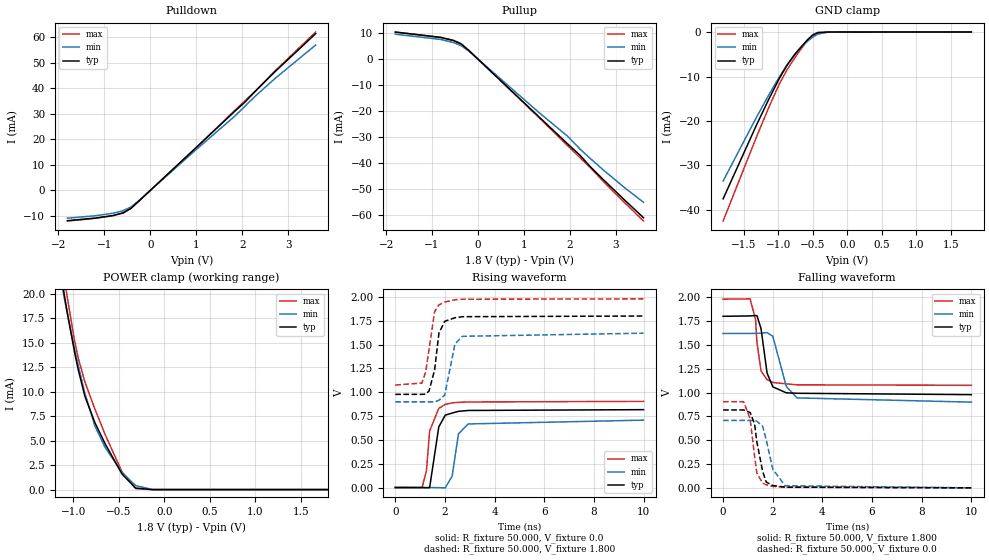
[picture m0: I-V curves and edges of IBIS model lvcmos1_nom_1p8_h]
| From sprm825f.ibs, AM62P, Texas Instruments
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|*********************** Begin LVCMOS ***********************************
|   nom_1p8_H
[Model]   lvcmos1_nom_1p8_h
Model_type I/O
Polarity   Non-Inverting
Enable   Active-High
Vinl = 0
Vinh = 0.8
Vmeas = 0.9
Vref = 1.8
Cref = 2pF
Rref = 100000
|   typ   min   max
C_comp   4.812pF   4.643pF   4.867pF
[Voltage Range]   1.8   1.62   1.98
[Temperature Range]   27   150   -40
[Pullup Reference]   1.8   1.62   1.98
[Pulldown Reference]   0   0   0
[Power Clamp Reference]   1.8   1.62   1.98
[GND Clamp Reference]   0   0   0
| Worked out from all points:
|   slope of the pulldown table from 0 to 0.27 V, typ, clamps not added: 59.6 ohm
|   slope of the pullup table from 0 to 0.27 V, typ, clamps not added: 60.3 ohm
|   GND clamp passes 1 mA (typ) near -0.52 V on its own axis
|   POWER clamp passes 1 mA (typ) near -0.42 V on its own axis
|   rising waveform, R_fixture 50.000, V_fixture 0.0: 20-80 % time 250ps typ, 243ps min, 219ps max; typ from 0 V to 0.817 V
|   rising waveform, R_fixture 50.000, V_fixture 1.800: 20-80 % time 281ps typ, 299ps min, 295ps max; typ from 0.978 V to 1.8 V
|   falling waveform, R_fixture 50.000, V_fixture 1.800: 20-80 % time 284ps typ, 315ps min, 224ps max; typ from 1.8 V to 0.978 V
|   falling waveform, R_fixture 50.000, V_fixture 0.0: 20-80 % time 324ps typ, 399ps min, 252ps max; typ from 0.817 V to 0 V
[Pulldown]
|Voltage   I(typ)   I(min)   I(max)
-1.8V     -11.83mA   -10.84mA   -11.95mA
-1.194V   -10.81mA   -9.89mA    -10.89mA
-808mV    -9.796mA   -8.891mA   -9.883mA
-588mV    -8.727mA   -7.88mA    -8.834mA
-422mV    -7.017mA   -6.479mA   -7.051mA
-257mV    -4.32mA    -4.115mA   -4.313mA
955mV     16.06mA    15.31mA    16.02mA
1.837V    30.98mA    29.07mA    31.32mA
2.057V    34.53mA    32.95mA    35.07mA
2.278V    38.73mA    36.82mA    38.73mA
2.718V    46.58mA    43.91mA    46.89mA
3.6V      61.43mA    56.98mA    62.05mA
[Pullup]
|Voltage   I(typ)   I(min)   I(max)
-1.8V     10.4mA     9.589mA    10.42mA
-808mV    8.34mA     7.567mA    8.338mA
-533mV    7.149mA    6.373mA    7.209mA
-367mV    5.812mA    5.163mA    5.937mA
-202mV    3.357mA    3.122mA    3.385mA
1.341V    -22.43mA   -20.74mA   -22.71mA
1.947V    -32.54mA   -29.6mA    -33.21mA
2.222V    -37mA      -34.61mA   -37.92mA
2.443V    -41.34mA   -38.19mA   -41.68mA
2.718V    -46.16mA   -42.47mA   -46.89mA
3.214V    -54.57mA   -49.76mA   -55.58mA
3.6V      -60.94mA   -55.01mA   -62.2mA
[GND_clamp]
|Voltage   I(typ)   I(min)   I(max)
-1.8V     -37.5mA    -33.49mA   -42.48mA
-1.318V   -20.97mA   -19.21mA   -23.65mA
-1.132V   -14.92mA   -13.99mA   -16.76mA
-984mV    -10.42mA   -10.06mA   -11.66mA
-872mV    -7.442mA   -7.36mA    -8.464mA
-761mV    -5.052mA   -4.998mA   -5.817mA
-687mV    -3.663mA   -3.691mA   -4.162mA
-575mV    -1.728mA   -2.058mA   -1.807mA
-501mV    -716.8uA   -1.141mA   -632.9uA
-427mV    -157.5uA   -469uA     -83.58uA
-278mV    -1.328uA   -23.74uA   -249.6nA
1.8V      0A         0A         0A
[POWER_clamp]
|Voltage   I(typ)   I(min)   I(max)
-1.8V     63.27mA    56.65mA    71.18mA
-1.095V   19.71mA    19.39mA    21.45mA
-1.058V   17.7mA     17.64mA    19.2mA
-984mV    13.96mA    14.3mA     15.14mA
-946mV    12.28mA    12.71mA    13.47mA
-872mV    9.531mA    9.826mA    11mA
-761mV    6.815mA    6.469mA    8.199mA
-649mV    4.665mA    4.296mA    5.605mA
-464mV    1.58mA     1.756mA    1.801mA
-315mV    158.8uA    413.9uA    104.9uA
-130mV    309.6nA    7.728uA    148.5nA
1.8V      0A         0A         0A
[Ramp]
| variable   typ   min   max
dV/dt_r   0.490/0.250n   0.424/0.242n   0.543/0.219n
dV/dt_f   0.493/0.285n   0.432/0.315n   0.543/0.223n
R_load = 50.000
[Rising Waveform]
R_fixture= 50.000
V_fixture= 0.0
V_fixture_min= 0.0
V_fixture_max= 0.0
|time   V(typ)   V(min)   V(max)
0s        823.8nV    18.05uV    1.398uV
1.078ns   135.1uV    18.7uV     -608.1uV
1.255ns   -2.306mV   28.57uV    177.4mV
1.383ns   -399.7uV   47.89uV    593.6mV
1.752ns   636.5mV    -1.598mV   830.2mV
2.013ns   759.9mV    -3.258mV   873.1mV
2.29ns    781.7mV    119.9mV    888.1mV
2.544ns   799.5mV    562.8mV    893.9mV
2.934ns   808.8mV    667.3mV    898.2mV
10ns      817.3mV    707.4mV    904.2mV
[Rising Waveform]
R_fixture= 50.000
V_fixture= 1.800
V_fixture_min= 1.620
V_fixture_max= 1.980
|time   V(typ)   V(min)   V(max)
0s        977.8mV    899.3mV    1.076V
1.069ns   977.9mV    899.3mV    1.096V
1.221ns   980.6mV    899.3mV    1.208V
1.356ns   1.011V     899.3mV    1.444V
1.584ns   1.235V     899.4mV    1.846V
1.757ns   1.62V      915.7mV    1.917V
1.992ns   1.745V     971.5mV    1.947V
2.403ns   1.782V     1.507V     1.971V
2.706ns   1.793V     1.587V     1.976V
10ns      1.8V       1.62V      1.98V
[Falling Waveform]
R_fixture= 50.000
V_fixture= 1.800
V_fixture_min= 1.620
V_fixture_max= 1.980
|time   V(typ)   V(min)   V(max)
0s        1.8V       1.62V      1.98V
1.087ns   1.804V     1.62V      1.983V
1.309ns   1.808V     1.621V     1.764V
1.363ns   1.807V     1.622V     1.525V
1.528ns   1.67V      1.623V     1.225V
1.771ns   1.204V     1.629V     1.136V
2.003ns   1.06V      1.591V     1.106V
2.544ns   997.1mV    1.064V     1.091V
2.977ns   992.4mV    943.8mV    1.081V
10ns      977.8mV    899.4mV    1.076V
[Falling Waveform]
R_fixture= 50.000
V_fixture= 0.0
V_fixture_min= 0.0
V_fixture_max= 0.0
|time   V(typ)   V(min)   V(max)
0s        817.3mV    707.5mV    904.3mV
825ps     817.3mV    707.5mV    903.8mV
1.087ns   790.8mV    707.5mV    726.3mV
1.266ns   672.8mV    707.5mV    334.4mV
1.359ns   481.5mV    699.2mV    155.1mV
1.591ns   174.7mV    648.4mV    49.85mV
1.736ns   60.8mV     503mV      31.72mV
2.003ns   23.91mV    194.1mV    14.95mV
2.497ns   7.87mV     22.14mV    6.191mV
10ns      33.03uV    87.62uV    16.17uV
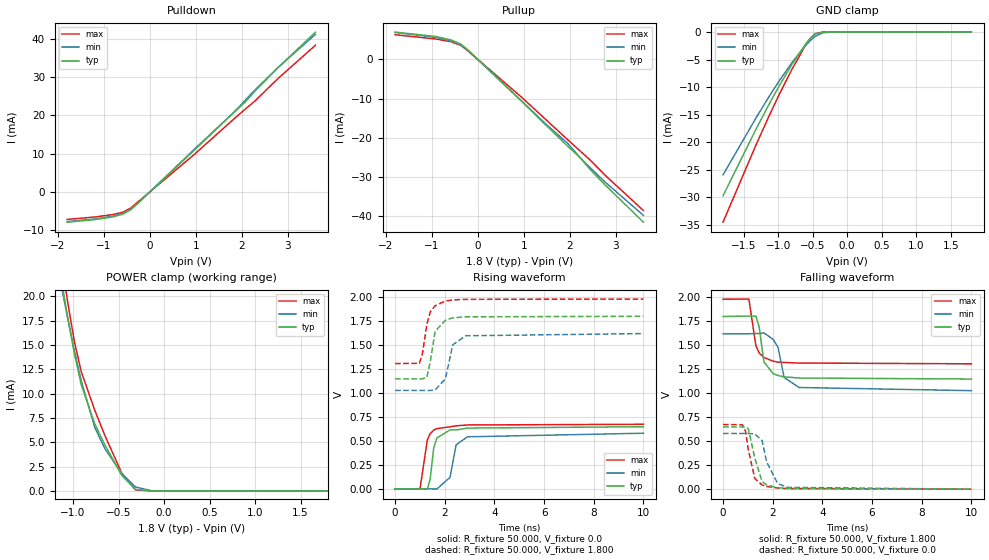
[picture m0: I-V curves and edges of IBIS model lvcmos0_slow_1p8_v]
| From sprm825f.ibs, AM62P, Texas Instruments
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|   slow_1p8_v
[Model]   lvcmos0_slow_1p8_v
Model_type I/O
Polarity   Non-Inverting
Enable   Active-High
Vinl = 0
Vinh = 0.8
Vmeas = 0.9
Vref = 1.8
Cref = 2pF
Rref = 100000
|   typ   min   max
C_comp   5.313pF   5.138pF   5.385pF
[Voltage Range]   1.8   1.62   1.98
[Temperature Range]   27   150   -40
[Pullup Reference]   1.8   1.62   1.98
[Pulldown Reference]   0   0   0
[Power Clamp Reference]   1.8   1.62   1.98
[GND Clamp Reference]   0   0   0
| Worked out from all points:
|   slope of the pulldown table from 0 to 0.27 V, typ, clamps not added: 88.7 ohm
|   slope of the pullup table from 0 to 0.27 V, typ, clamps not added: 89.7 ohm
|   GND clamp passes 1 mA (typ) near -0.52 V on its own axis
|   POWER clamp passes 1 mA (typ) near -0.42 V on its own axis
|   rising waveform, R_fixture 50.000, V_fixture 0.0: 20-80 % time 234ps typ, 265ps min, 232ps max; typ from 0 V to 0.648 V
|   rising waveform, R_fixture 50.000, V_fixture 1.800: 20-80 % time 260ps typ, 296ps min, 294ps max; typ from 1.15 V to 1.8 V
|   falling waveform, R_fixture 50.000, V_fixture 1.800: 20-80 % time 258ps typ, 334ps min, 257ps max; typ from 1.8 V to 1.15 V
|   falling waveform, R_fixture 50.000, V_fixture 0.0: 20-80 % time 343ps typ, 411ps min, 294ps max; typ from 0.648 V to 0 V
[Pulldown]
|Voltage   I(typ)   I(min)   I(max)
-1.8V     -7.963mA   -7.801mA   -7.241mA
-1.194V   -7.271mA   -7.118mA   -6.591mA
-808mV    -6.583mA   -6.398mA   -5.977mA
-588mV    -5.86mA    -5.668mA   -5.345mA
-422mV    -4.71mA    -4.654mA   -4.282mA
-257mV    -2.902mA   -2.957mA   -2.608mA
955mV     10.79mA    11.03mA    9.687mA
1.837V    20.92mA    20.94mA    19.19mA
2.057V    23.3mA     23.79mA    21.49mA
2.278V    26.26mA    26.63mA    23.71mA
2.773V    32.37mA    32.42mA    29.54mA
3.6V      41.82mA    41.24mA    38.38mA
[Pullup]
|Voltage   I(typ)   I(min)   I(max)
-1.8V     6.998mA    6.891mA    6.313mA
-918mV    5.872mA    5.673mA    5.243mA
-588mV    5.01mA     4.789mA    4.536mA
-367mV    3.923mA    3.703mA    3.583mA
-202mV    2.255mA    2.239mA    2.047mA
955mV     -10.69mA   -10.66mA   -9.684mA
1.506V    -17.07mA   -16.77mA   -15.65mA
1.947V    -22.06mA   -21.35mA   -20.42mA
2.222V    -25.07mA   -25.04mA   -23.35mA
2.443V    -28.13mA   -27.65mA   -25.69mA
2.773V    -32.1mA    -31.37mA   -29.62mA
3.6V      -41.55mA   -39.8mA    -38.57mA
[GND_clamp]
|Voltage   I(typ)   I(min)   I(max)
-1.8V     -29.72mA   -25.92mA   -34.52mA
-1.318V   -17.54mA   -15.51mA   -20.38mA
-1.132V   -13.09mA   -11.7mA    -15.22mA
-984mV    -9.729mA   -8.822mA   -11.3mA
-798mV    -5.797mA   -5.487mA   -6.696mA
-612mV    -2.352mA   -2.574mA   -2.564mA
-538mV    -1.174mA   -1.582mA   -1.166mA
-464mV    -368uA     -771.3uA   -275.5uA
-353mV    -15.75uA   -129.3uA   -4.378uA
-241mV    -383.4nA   -10.85uA   -119.1nA
1.8V      0A         0A         0A
[POWER_clamp]
|Voltage   I(typ)   I(min)   I(max)
-1.8V     63.47mA    56.87mA    71.37mA
-1.132V   21.93mA    21.29mA    24mA
-1.095V   19.85mA    19.49mA    21.65mA
-1.058V   17.84mA    17.74mA    19.39mA
-984mV    14.08mA    14.39mA    15.3mA
-909mV    10.9mA     11.31mA    12.25mA
-761mV    6.887mA    6.531mA    8.298mA
-649mV    4.716mA    4.334mA    5.678mA
-464mV    1.598mA    1.771mA    1.827mA
-315mV    160.7uA    409.8uA    112.2uA
-130mV    308nA      7.74uA     148.3nA
1.8V      0A         0A         0A
[Ramp]
| variable   typ   min   max
dV/dt_r   0.389/0.233n   0.348/0.263n   0.404/0.232n
dV/dt_f   0.391/0.258n   0.356/0.335n   0.404/0.256n
R_load = 50.000
[Rising Waveform]
R_fixture= 50.000
V_fixture= 0.0
|time   V(typ)   V(min)   V(max)
0s        961.2nV    20.53uV    1.691uV
1.003ns   104uV      18.77uV    172.7uV
1.297ns   -3.062mV   -5.319uV   510.4mV
1.411ns   101.2mV    76.52uV    574.7mV
1.555ns   427.3mV    -706.1uV   612.8mV
1.681ns   530.4mV    -1.883mV   628.3mV
2.212ns   615.3mV    120.5mV    647.4mV
2.457ns   614.4mV    459.8mV    657.9mV
2.91ns    634.3mV    543mV      666.5mV
10ns      648.3mV    580.6mV    673.9mV
[Rising Waveform]
R_fixture= 50.000
V_fixture= 1.800
V_fixture_min= 1.620
V_fixture_max= 1.980
|time   V(typ)   V(min)   V(max)
0s        1.148V     1.027V     1.307V
979ps     1.148V     1.027V     1.31V
1.103ns   1.147V     1.027V     1.414V
1.283ns   1.167V     1.027V     1.723V
1.416ns   1.327V     1.027V     1.847V
1.611ns   1.643V     1.03V      1.909V
2.026ns   1.76V      1.149V     1.96V
2.321ns   1.784V     1.503V     1.971V
2.844ns   1.795V     1.597V     1.977V
10ns      1.8V       1.62V      1.98V
[Falling Waveform]
R_fixture= 50.000
V_fixture= 1.800
V_fixture_min= 1.620
V_fixture_max= 1.980
|time   V(typ)   V(min)   V(max)
0s        1.8V       1.62V      1.98V
1.042ns   1.805V     1.62V      1.982V
1.323ns   1.803V     1.622V     1.496V
1.456ns   1.69V      1.623V     1.42V
1.648ns   1.326V     1.629V     1.373V
2.02ns    1.204V     1.561V     1.334V
2.214ns   1.185V     1.48V      1.324V
2.461ns   1.171V     1.165V     1.321V
3.059ns   1.159V     1.06V      1.315V
10ns      1.148V     1.027V     1.307V
[Falling Waveform]
R_fixture= 50.000
V_fixture= 0.0
V_fixture_min= 0.0
V_fixture_max= 0.0
|time   V(typ)   V(min)   V(max)
0s        648.3mV    580.6mV    673.9mV
775ps     648.3mV    580.6mV    671.8mV
905ps     648.5mV    580.6mV    607.9mV
1.017ns   631.4mV    580.6mV    412.8mV
1.281ns   323.2mV    575mV      111.3mV
1.571ns   79.82mV    507.1mV    44.39mV
1.759ns   42.72mV    283.3mV    28.53mV
2.204ns   15.58mV    57.04mV    11.36mV
2.608ns   7.835mV    18.53mV    6.216mV
10ns      47.85uV    118uV      30.83uV
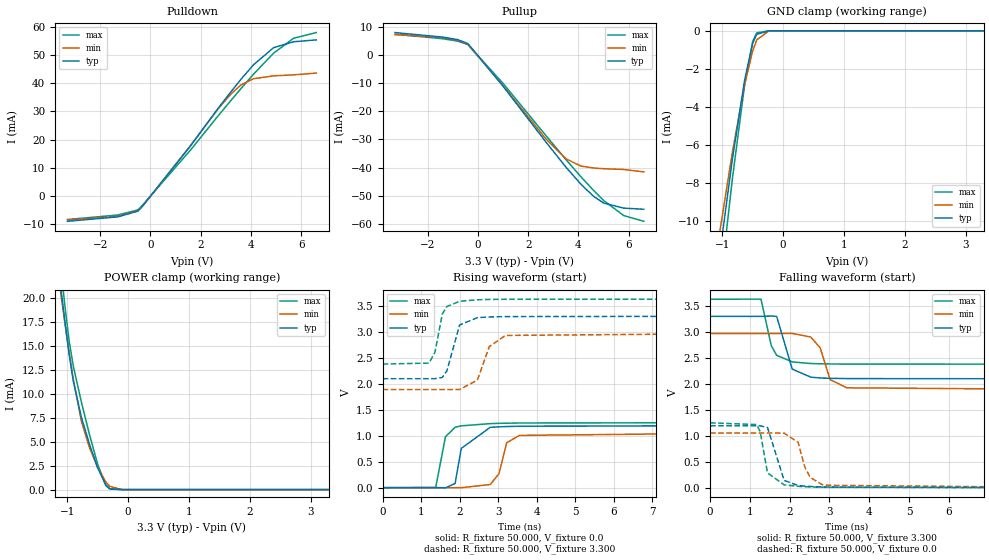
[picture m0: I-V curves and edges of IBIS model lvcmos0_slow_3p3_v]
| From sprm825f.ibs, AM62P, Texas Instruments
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|   slow_3p3_v
[Model]   lvcmos0_slow_3p3_v
Model_type I/O
Polarity   Non-Inverting
Enable   Active-High
Vinl = 0
Vinh = 0.8
Vmeas = 1.65
Vref = 3.3
Cref = 2pF
Rref = 100000
|   typ   min   max
C_comp   3.777pF   3.679pF   3.786pF
[Voltage Range]   3.3   2.97   3.63
[Temperature Range]   27   150   -40
[Pullup Reference]   3.3   2.97   3.63
[Pulldown Reference]   0   0   0
[Power Clamp Reference]   3.3   2.97   3.63
[GND Clamp Reference]   0   0   0
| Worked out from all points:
|   slope of the pulldown table from 0 to 0.495 V, typ, clamps not added: 89.6 ohm
|   slope of the pullup table from 0 to 0.495 V, typ, clamps not added: 90.9 ohm
|   GND clamp passes 1 mA (typ) near -0.53 V on its own axis
|   POWER clamp passes 1 mA (typ) near -0.41 V on its own axis
|   rising waveform, R_fixture 50.000, V_fixture 0.0: 20-80 % time 176ps typ, 256ps min, 171ps max; typ from 0 V to 1.19 V
|   rising waveform, R_fixture 50.000, V_fixture 3.300: 20-80 % time 250ps typ, 314ps min, 202ps max; typ from 2.1 V to 3.3 V
|   falling waveform, R_fixture 50.000, V_fixture 3.300: 20-80 % time 199ps typ, 289ps min, 196ps max; typ from 3.3 V to 2.1 V
|   falling waveform, R_fixture 50.000, V_fixture 0.0: 20-80 % time 240ps typ, 278ps min, 182ps max; typ from 1.19 V to 0 V
[Pulldown]
|Voltage   I(typ)   I(min)   I(max)
-3.3V     -8.88mA    -8.385mA   -8.25mA
-1.3V     -7.308mA   -7.119mA   -6.652mA
-500mV    -5.306mA   -5.103mA   -4.87mA
-300mV    -3.354mA   -3.386mA   -3.022mA
1.6V      17.84mA    18.03mA    16.39mA
2.7V      31.18mA    31mA       28.5mA
3.2V      36.91mA    36.13mA    33.86mA
3.6V      41.35mA    39.38mA    38.06mA
4.1V      46.49mA    41.56mA    43.15mA
4.9V      52.56mA    42.59mA    50.61mA
5.7V      54.65mA    42.94mA    55.9mA
6.6V      55.31mA    43.57mA    57.9mA
[Pullup]
|Voltage   I(typ)   I(min)   I(max)
-3.3V     8.025mA    7.28mA     7.462mA
-1.4V     6.408mA    6.261mA    5.826mA
-800mV    5.499mA    5.284mA    4.983mA
-400mV    4.1mA      3.839mA    3.763mA
1V        -11.05mA   -10.89mA   -10.06mA
2.7V      -30.85mA   -29.76mA   -28.57mA
3.5V      -39.82mA   -36.87mA   -37.14mA
4.1V      -45.93mA   -39.47mA   -43.29mA
4.6V      -50.21mA   -40.15mA   -48.11mA
5V        -52.61mA   -40.39mA   -51.69mA
5.8V      -54.41mA   -40.68mA   -57.07mA
6.6V      -54.82mA   -41.52mA   -59.1mA
[GND_clamp]
|Voltage   I(typ)   I(min)   I(max)
-3.3V     -91.93mA   -62.08mA   -135.9mA
-1.3V     -18.16mA   -15.85mA   -21.32mA
-1.233V   -16.57mA   -14.51mA   -19.39mA
-1.167V   -14.92mA   -13.18mA   -17.39mA
-1.1V     -13.23mA   -11.81mA   -15.39mA
-1.033V   -11.55mA   -10.42mA   -13.42mA
-833mV    -6.742mA   -6.382mA   -7.775mA
-633mV    -2.616mA   -2.841mA   -2.866mA
-500mV    -654.2uA   -1.063mA   -567uA
-433mV    -179.7uA   -474.3uA   -107.3uA
-233mV    -333.4nA   -7.881uA   -216.8nA
3.3V      0A         0A         0A
[POWER_clamp]
|Voltage   I(typ)   I(min)   I(max)
-3.3V     163.7mA    143.3mA    185.7mA
-1.1V     20.75mA    20.13mA    22.76mA
-1.033V   17.24mA    17.07mA    18.82mA
-967mV    14.03mA    14.18mA    15.4mA
-900mV    11.29mA    11.5mA     12.85mA
-767mV    7.523mA    7.108mA    9.097mA
-633mV    4.708mA    4.343mA    5.698mA
-500mV    2.263mA    2.325mA    2.644mA
-367mV    497.9uA    807.2uA    443.4uA
-300mV    94.26uA    333.7uA    53.33uA
-100mV    158.3nA    4.238uA    99.13nA
3.3V      0A         0A         0A
[Ramp]
| variable   typ   min   max
dV/dt_r   0.716/0.176n   0.633/0.257n   0.751/0.171n
dV/dt_f   0.721/0.199n   0.649/0.289n   0.750/0.196n
R_load = 50.000
[Rising Waveform]
R_fixture= 50.000
V_fixture= 0.0
V_fixture_min= 0.0
V_fixture_max= 0.0
|time   V(typ)   V(min)   V(max)
0s        2.233uV    22.67uV    3.142uV
1.378ns   -170.2uV   37.08uV    3.025mV
1.631ns   -3.81mV    -75.25uV   979.4mV
1.882ns   80.33mV    -80.37uV   1.163V
2.041ns   754.8mV    -747.2uV   1.19V
2.793ns   1.162V     60.76mV    1.233V
3.022ns   1.171V     269.9mV    1.238V
3.22ns    1.177V     864.7mV    1.241V
3.55ns    1.183V     1.006V     1.245V
10ns      1.194V     1.055V     1.252V
[Rising Waveform]
R_fixture= 50.000
V_fixture= 3.300
V_fixture_min= 2.970
V_fixture_max= 3.630
|time   V(typ)   V(min)   V(max)
0s        2.098V     1.889V     2.38V
1.205ns   2.098V     1.889V     2.398V
1.359ns   2.098V     1.889V     2.608V
1.55ns    2.122V     1.889V     3.344V
1.67ns    2.252V     1.889V     3.489V
1.998ns   3.132V     1.89V      3.588V
2.46ns    3.273V     2.071V     3.618V
2.769ns   3.287V     2.716V     3.624V
3.189ns   3.294V     2.931V     3.627V
10ns      3.3V       2.97V      3.63V
[Falling Waveform]
R_fixture= 50.000
V_fixture= 3.300
V_fixture_min= 2.970
V_fixture_max= 3.630
|time   V(typ)   V(min)   V(max)
0s        3.3V       2.97V      3.63V
1.279ns   3.3V       2.97V      3.632V
1.537ns   3.307V     2.97V      2.738V
1.673ns   3.3V       2.97V      2.551V
2.064ns   2.285V     2.972V     2.424V
2.528ns   2.131V     2.903V     2.393V
2.766ns   2.115V     2.696V     2.388V
3.014ns   2.108V     2.084V     2.384V
3.438ns   2.103V     1.925V     2.382V
10ns      2.098V     1.889V     2.38V
[Falling Waveform]
R_fixture= 50.000
V_fixture= 0.0
V_fixture_min= 0.0
V_fixture_max= 0.0
|time   V(typ)   V(min)   V(max)
0s        1.194V     1.055V     1.252V
1.168ns   1.194V     1.055V     1.218V
1.258ns   1.194V     1.055V     1.084V
1.443ns   1.162V     1.055V     287.1mV
1.861ns   142.9mV    1.053V     57.75mV
2.211ns   45.76mV    875.8mV    29.85mV
2.383ns   33.66mV    392.4mV    22.37mV
2.518ns   26.84mV    200mV      18.07mV
2.845ns   16.06mV    50.78mV    11.19mV
10ns      71.42uV    151.9uV    48.03uV
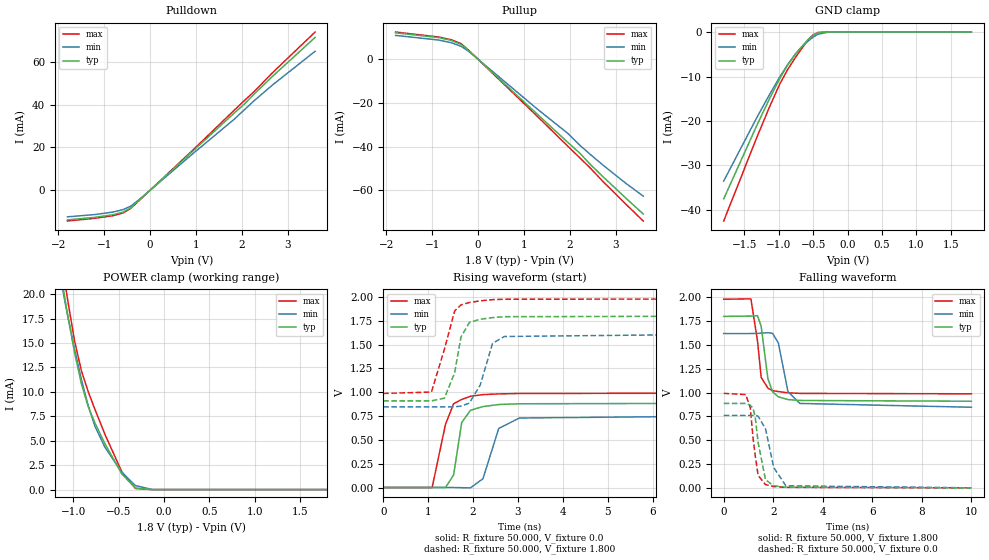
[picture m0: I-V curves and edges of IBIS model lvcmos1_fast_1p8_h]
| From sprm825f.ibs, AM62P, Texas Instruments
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|   fast_1p8_h
[Model]   lvcmos1_fast_1p8_h
Model_type I/O
Polarity   Non-Inverting
Enable   Active-High
Vinl = 0
Vinh = 0.8
Vmeas = 0.9
Vref = 1.8
Cref = 2pF
Rref = 100000
|   typ   min   max
C_comp   4.812pF   4.643pF   4.867pF
[Voltage Range]   1.8   1.62   1.98
[Temperature Range]   27   150   -40
[Pullup Reference]   1.8   1.62   1.98
[Pulldown Reference]   0   0   0
[Power Clamp Reference]   1.8   1.62   1.98
[GND Clamp Reference]   0   0   0
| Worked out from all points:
|   slope of the pulldown table from 0 to 0.27 V, typ, clamps not added: 51.1 ohm
|   slope of the pullup table from 0 to 0.27 V, typ, clamps not added: 51.6 ohm
|   GND clamp passes 1 mA (typ) near -0.52 V on its own axis
|   POWER clamp passes 1 mA (typ) near -0.42 V on its own axis
|   rising waveform, R_fixture 50.000, V_fixture 0.0: 20-80 % time 186ps typ, 284ps min, 281ps max; typ from 0 V to 0.886 V
|   rising waveform, R_fixture 50.000, V_fixture 1.800: 20-80 % time 220ps typ, 304ps min, 317ps max; typ from 0.909 V to 1.8 V
|   falling waveform, R_fixture 50.000, V_fixture 1.800: 20-80 % time 237ps typ, 357ps min, 242ps max; typ from 1.8 V to 0.909 V
|   falling waveform, R_fixture 50.000, V_fixture 0.0: 20-80 % time 320ps typ, 417ps min, 252ps max; typ from 0.886 V to 0 V
[Pulldown]
|Voltage   I(typ)   I(min)   I(max)
-1.8V     -13.81mA   -12.38mA   -14.33mA
-1.194V   -12.61mA   -11.3mA    -13.05mA
-808mV    -11.42mA   -10.15mA   -11.85mA
-588mV    -10.19mA   -9.002mA   -10.59mA
-422mV    -8.181mA   -7.402mA   -8.45mA
-257mV    -5.042mA   -4.7mA     -5.17mA
955mV     18.73mA    17.48mA    19.2mA
1.837V    36.09mA    33.19mA    37.41mA
2.057V    40.24mA    37.6mA     41.88mA
2.278V    45.07mA    41.97mA    46.25mA
2.663V    53.05mA    49.03mA    54.72mA
3.6V      71.37mA    64.91mA    73.89mA
[Pullup]
|Voltage   I(typ)   I(min)   I(max)
-1.8V     12.14mA    10.95mA    12.49mA
-863mV    9.949mA    8.822mA    10.22mA
-588mV    8.699mA    7.614mA    8.984mA
-367mV    6.789mA    5.895mA    7.103mA
-202mV    3.919mA    3.565mA    4.056mA
1.286V    -25.05mA   -22.7mA    -26mA
1.947V    -37.88mA   -33.76mA   -39.62mA
2.222V    -43.07mA   -39.42mA   -45.22mA
2.443V    -48.07mA   -43.49mA   -49.73mA
2.718V    -53.66mA   -48.37mA   -55.86mA
3.214V    -63.42mA   -56.66mA   -66.17mA
3.6V      -70.82mA   -62.64mA   -74.03mA
[GND_clamp]
|Voltage   I(typ)   I(min)   I(max)
-1.8V     -37.5mA    -33.49mA   -42.48mA
-1.318V   -20.97mA   -19.21mA   -23.65mA
-1.132V   -14.92mA   -13.99mA   -16.76mA
-984mV    -10.42mA   -10.06mA   -11.66mA
-872mV    -7.442mA   -7.36mA    -8.464mA
-761mV    -5.052mA   -4.998mA   -5.817mA
-687mV    -3.663mA   -3.691mA   -4.162mA
-575mV    -1.728mA   -2.058mA   -1.808mA
-501mV    -716.8uA   -1.141mA   -632.4uA
-427mV    -157.5uA   -468.3uA   -83.21uA
-278mV    -1.328uA   -23.76uA   -248.6nA
1.8V      0A         0A         0A
[POWER_clamp]
|Voltage   I(typ)   I(min)   I(max)
-1.8V     63.27mA    56.65mA    71.18mA
-1.095V   19.71mA    19.39mA    21.45mA
-1.058V   17.7mA     17.64mA    19.2mA
-984mV    13.96mA    14.3mA     15.15mA
-909mV    10.79mA    11.23mA    12.12mA
-835mV    8.489mA    8.575mA    10.02mA
-761mV    6.815mA    6.481mA    8.2mA
-649mV    4.665mA    4.299mA    5.607mA
-464mV    1.58mA     1.756mA    1.805mA
-315mV    158.8uA    411.2uA    110uA
-130mV    309.5nA    7.643uA    148.6nA
1.8V      0A         0A         0A
[Ramp]
| variable   typ   min   max
dV/dt_r   0.532/0.186n   0.456/0.284n   0.595/0.281n
dV/dt_f   0.535/0.237n   0.464/0.354n   0.596/0.242n
R_load = 50.000
[Rising Waveform]
R_fixture= 50.000
V_fixture= 0.0
V_fixture_min= 0.0
V_fixture_max= 0.0
|time   V(typ)   V(min)   V(max)
0s        765.5nV    16.98uV    1.281uV
1.089ns   103.2uV    17.62uV    -763.2uV
1.387ns   970.4uV    55.52uV    663.9mV
1.567ns   131.1mV    -256.9uV   879.7mV
1.747ns   681.1mV    -1.648mV   923.9mV
1.944ns   810.9mV    -3.579mV   958.3mV
2.221ns   849.6mV    92.62mV    974.9mV
2.572ns   871.1mV    620.2mV    982.5mV
3.032ns   878.9mV    729.4mV    986.8mV
10ns      886mV      760.3mV    992mV
[Rising Waveform]
R_fixture= 50.000
V_fixture= 1.800
V_fixture_min= 1.620
V_fixture_max= 1.980
|time   V(typ)   V(min)   V(max)
0s        909.1mV    846.2mV    987.3mV
1.074ns   909.2mV    846.2mV    1.002V
1.362ns   937.7mV    846.2mV    1.45V
1.59ns    1.203V     846.1mV    1.853V
1.731ns   1.579V     854.9mV    1.916V
1.918ns   1.732V     886.1mV    1.942V
2.159ns   1.766V     1.075V     1.959V
2.434ns   1.783V     1.513V     1.972V
2.696ns   1.793V     1.585V     1.976V
10ns      1.8V       1.62V      1.98V
[Falling Waveform]
R_fixture= 50.000
V_fixture= 1.800
V_fixture_min= 1.620
V_fixture_max= 1.980
|time   V(typ)   V(min)   V(max)
0s        1.8V       1.62V      1.98V
1.098ns   1.803V     1.62V      1.984V
1.364ns   1.808V     1.622V     1.543V
1.513ns   1.695V     1.624V     1.159V
1.783ns   1.147V     1.629V     1.047V
1.973ns   1.008V     1.622V     1.02V
2.208ns   955.3mV    1.52V      1.011V
2.593ns   926.8mV    1.011V     997.7mV
3.075ns   917.5mV    886mV      991.7mV
10ns      909.1mV    846.2mV    987.3mV
[Falling Waveform]
R_fixture= 50.000
V_fixture= 0.0
V_fixture_min= 0.0
V_fixture_max= 0.0
|time   V(typ)   V(min)   V(max)
0s        886mV      760.4mV    992mV
889ps     886mV      760.4mV    979.1mV
1.072ns   868.9mV    760.3mV    840.9mV
1.187ns   832.9mV    760.4mV    515.8mV
1.274ns   740mV      760.4mV    336.1mV
1.391ns   473.3mV    751.3mV    129.4mV
1.688ns   85.05mV    619.9mV    34.17mV
2.018ns   21.97mV    213.8mV    13.37mV
2.511ns   7.159mV    21.51mV    5.501mV
10ns      30.93uV    83.26uV    14.49uV
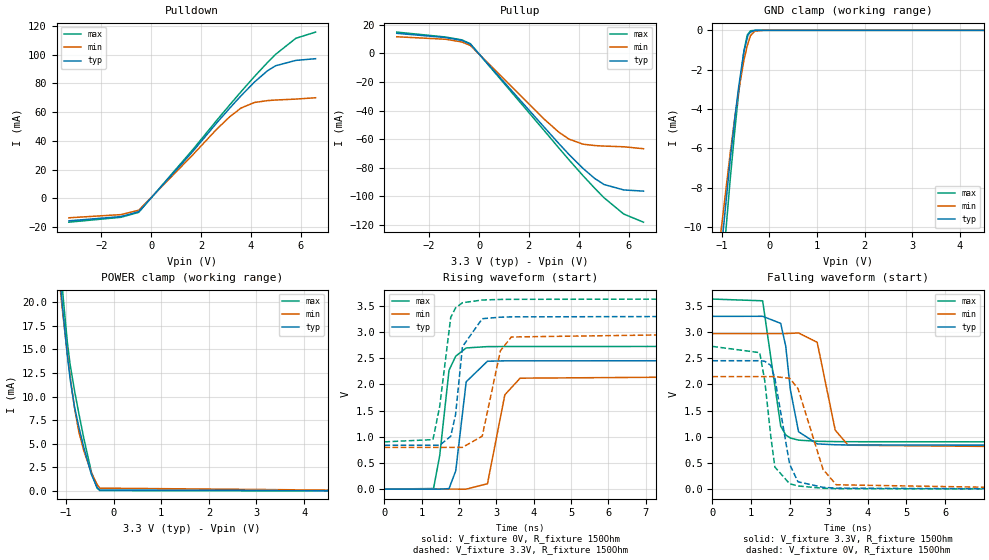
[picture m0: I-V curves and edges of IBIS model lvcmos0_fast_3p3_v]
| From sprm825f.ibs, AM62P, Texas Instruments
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|   fast_3p3_v
[Model]   lvcmos0_fast_3p3_v
Model_type   I/O
Polarity   Non-Inverting
Enable   Active-High
Vinl = 0
Vinh = 0.8
Vmeas = 1.65
Vref = 3.3
Cref = 2pF
Rref = 100000
|   typ   min   max
C_comp   3.777pF   3.679pF   3.786pF
[Voltage Range]   3.3   2.97   3.63
[Temperature Range]   27   150   -40
[Pullup Reference]   3.3   2.97   3.63
[Pulldown Reference]   0   0   0
[Power Clamp Reference]   3.3   2.97   3.63
[GND Clamp Reference]   0   0   0
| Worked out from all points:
|   slope of the pulldown table from 0 to 0.495 V, typ, clamps not added: 51 ohm
|   slope of the pullup table from 0 to 0.495 V, typ, clamps not added: 51.8 ohm
|   GND clamp passes 1 mA (typ) near -0.53 V on its own axis
|   POWER clamp passes 1 mA (typ) near -0.41 V on its own axis
|   falling waveform, V_fixture 3.3V, R_fixture 150Ohm: 20-80 % time 261ps typ, 321ps min, 254ps max; typ from 3.3 V to 0.838 V
|   rising waveform, V_fixture 0V, R_fixture 150Ohm: 20-80 % time 224ps typ, 296ps min, 246ps max; typ from 0 V to 2.45 V
|   rising waveform, V_fixture 3.3V, R_fixture 150Ohm: 20-80 % time 230ps typ, 344ps min, 246ps max; typ from 0.838 V to 3.3 V
|   falling waveform, V_fixture 0V, R_fixture 150Ohm: 20-80 % time 331ps typ, 530ps min, 250ps max; typ from 2.45 V to 0 V
[Pulldown]
|   Voltage   I(typ)   I(min)   I(max)
-3.3V     -15.6mA    -13.48mA   -16.54mA
-1.211V   -12.65mA   -11.27mA   -13.13mA
-498.3mV  -9.27mA    -8.248mA   -9.7mA
1.67V     32.6mA     30.27mA    33.88mA
2.64V     52.68mA    48.27mA    54.42mA
3.165V    62.99mA    56.94mA    65.26mA
3.61V     71.44mA    62.89mA    74.26mA
4.155V    81.07mA    66.76mA    84.94mA
4.67V     88.8mA     68.03mA    94.53mA
4.996V    92.28mA    68.45mA    100.2mA
5.808V    96.01mA    69.09mA    111.4mA
6.6V      97.19mA    70.03mA    115.7mA
[GND Clamp]
|   Voltage   I(typ)   I(min)   I(max)
-3.3V     -92.62mA   -62.37mA   -137.3mA
-1.558V   -24.44mA   -21.27mA   -28.6mA
-825mV    -6.576mA   -6.239mA   -7.571mA
-726mV    -4.419mA   -4.397mA   -5.03mA
-646.8mV  -2.873mA   -3.062mA   -3.168mA
-537.9mV  -1.081mA   -1.53mA    -1.069mA
-468.6mV  -411.3uA   -800.4uA   -249.5uA
-448.8mV  -222.3uA   -649.6uA   -177.8uA
-399.3mV  -88.23uA   -272.4uA   -22.86uA
-310.2mV  -2.837uA   -45uA      -952.2nA
-132mV    -56.02nA   -1.517uA   -88.26nA
6.6V      0A         0A         0A
[Pullup]
|   Voltage   I(typ)   I(min)   I(max)
-3.3V     14.1mA     11.7mA     14.97mA
-1.34V    11.16mA    9.96mA     11.51mA
-686.4mV  9.185mA    8.041mA    9.506mA
-349.8mV  6.513mA    5.631mA    6.858mA
2.64V     -52.08mA   -46.36mA   -54.47mA
3.194V    -62.88mA   -54.96mA   -65.98mA
3.61V     -70.68mA   -59.95mA   -74.44mA
4.165V    -80.32mA   -63.46mA   -85.38mA
4.64V     -87.46mA   -64.46mA   -94.28mA
5.016V    -91.72mA   -64.82mA   -101mA
5.808V    -95.53mA   -65.31mA   -112.4mA
6.6V      -96.34mA   -66.68mA   -118.1mA
[POWER Clamp]
|   Voltage   I(typ)   I(min)   I(max)
-3.3V     165.9mA    145.4mA    188.3mA
-1.112V   21.57mA    20.89mA    23.69mA
-1.063V   18.87mA    18.55mA    20.64mA
-973.5mV  14.41mA    14.56mA    15.79mA
-914.1mV  11.87mA    12.11mA    13.39mA
-825mV    8.991mA    8.884mA    10.71mA
-735.9mV  6.868mA    6.368mA    8.325mA
-627mV    4.603mA    4.244mA    5.577mA
-468.6mV  1.77mA     1.941mA    2.021mA
-349.8mV  384.3uA    698.9uA    308.4uA
-290.4mV  90.1uA     296uA      37.21uA
6.6V      0A         0A         0A
[Ramp]
R_load = 150
|   typ   min   max
dV/dt_r   1.47177/2.23289e-10   1.28927/2.94465e-10   1.63544/2.46128e-10
dV/dt_f   1.4772/2.5801e-10   1.30347/3.2028e-10   1.63641/2.55541e-10
[Falling Waveform]
V_fixture = 3.3V
V_fixture_min = 2.97V
V_fixture_max = 3.63V
R_fixture = 150Ohm
C_fixture = 0F
|   Time   V(typ)   V(min)   V(max)
0s        3.3V       2.97V      3.63V
1.295ns   3.301V     2.97V      3.597V
1.76ns    3.166V     2.97V      1.203V
1.89ns    2.729V     2.972V     1.035V
2.01ns    1.896V     2.975V     976.2mV
2.22ns    1.097V     2.983V     936.3mV
2.7ns     864.2mV    2.805V     914.4mV
3.165ns   847.7mV    1.126V     908.4mV
3.495ns   844.1mV    839.8mV    906.3mV
10ns      837.9mV    797.3mV    902.6mV
[Rising Waveform]
V_fixture = 0V
V_fixture_min = 0V
V_fixture_max = 0V
R_fixture = 150Ohm
C_fixture = 0F
|   Time   V(typ)   V(min)   V(max)
0s        97.29uV    232uV      57.55uV
1.315ns   65.81uV    210.7uV    11.1mV
1.48ns    -1.089mV   86.68uV    638.9mV
1.73ns    9.645mV    141.9uV    2.269V
1.91ns    349mV      117.8uV    2.54V
2.19ns    2.05V      -1.063mV   2.696V
2.76ns    2.443V     103.3mV    2.722V
3.225ns   2.45V      1.801V     2.723V
3.635ns   2.45V      2.119V     2.724V
10ns      2.453V     2.149V     2.726V
[Rising Waveform]
V_fixture = 3.3V
V_fixture_min = 2.97V
V_fixture_max = 3.63V
R_fixture = 150Ohm
C_fixture = 0F
|   Time   V(typ)   V(min)   V(max)
0s        837.9mV    797.3mV    902.6mV
1.3ns     837.9mV    797.2mV    945.1mV
1.48ns    838.4mV    797.1mV    1.578V
1.775ns   1.009V     797.2mV    3.279V
1.905ns   1.42V      797.1mV    3.462V
2.09ns    2.721V     797.3mV    3.56V
2.62ns    3.255V     1.012V     3.612V
3.105ns   3.284V     2.64V      3.623V
3.4ns     3.29V      2.906V     3.625V
10ns      3.3V       2.97V      3.63V
[Falling Waveform]
|Gnd
V_fixture = 0V
V_fixture_min = 0V
V_fixture_max = 0V
R_fixture = 150Ohm
C_fixture = 0F
|   Time   V(typ)   V(min)   V(max)
0s        2.453V     2.149V     2.726V
1.22ns    2.453V     2.149V     2.607V
1.35ns    2.442V     2.149V     2.07V
1.505ns   2.363V     2.149V     1.008V
1.61ns    2.117V     2.149V     421.8mV
1.99ns    475.7mV    2.117V     103.8mV
2.205ns   141.1mV    1.922V     61.45mV
2.85ns    35.41mV    379.2mV    17.02mV
3.19ns    19.13mV    83.99mV    9.983mV
10ns      97.42uV    232uV      57.54uV
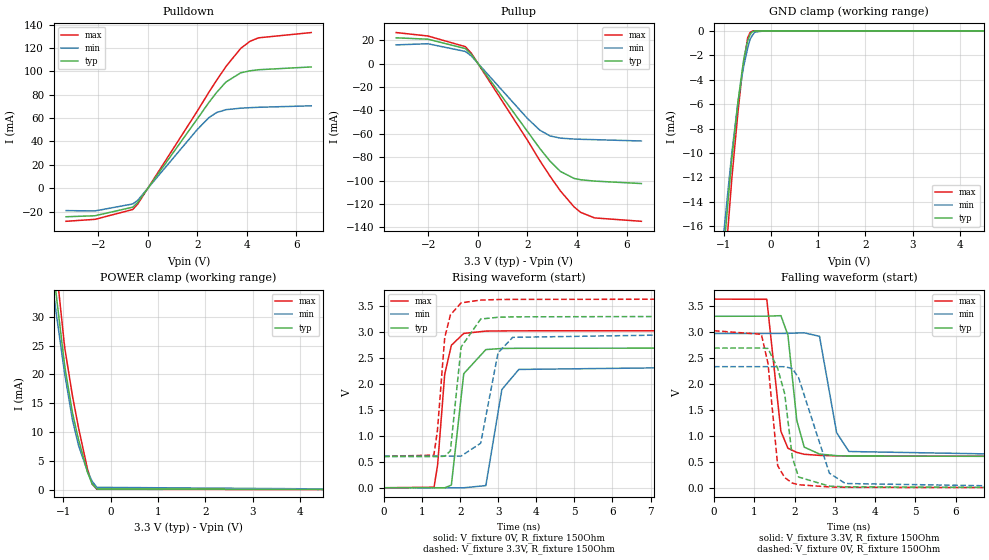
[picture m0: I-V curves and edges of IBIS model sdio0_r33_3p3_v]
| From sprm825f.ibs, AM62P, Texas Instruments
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|   r33_3p3_v
[Model]   sdio0_r33_3p3_v
Model_type   I/O
Polarity   Non-Inverting
Enable   Active-High
Vinl = 0
Vinh = 0.8
Vmeas = 1.65
Vref = 3.3
Cref = 2pF
Rref = 100000
|   typ   min   max
C_comp   4.972pF   4.893pF   4.997pF
[Voltage Range]   3.3   2.97   3.63
[Temperature Range]   27   150   -40
[Pullup Reference]   3.3   2.97   3.63
[Pulldown Reference]   0   0   0
[Power Clamp Reference]   3.3   2.97   3.63
[GND Clamp Reference]   0   0   0
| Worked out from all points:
|   slope of the pulldown table from 0 to 0.495 V, typ, clamps not added: 33.3 ohm
|   slope of the pullup table from 0 to 0.495 V, typ, clamps not added: 34 ohm
|   GND clamp passes 1 mA (typ) near -0.50 V on its own axis
|   POWER clamp passes 1 mA (typ) near -0.39 V on its own axis
|   falling waveform, V_fixture 3.3V, R_fixture 150Ohm: 20-80 % time 229ps typ, 284ps min, 207ps max; typ from 3.3 V to 0.6 V
|   rising waveform, V_fixture 0V, R_fixture 150Ohm: 20-80 % time 216ps typ, 280ps min, 213ps max; typ from 0 V to 2.69 V
|   rising waveform, V_fixture 3.3V, R_fixture 150Ohm: 20-80 % time 212ps typ, 322ps min, 207ps max; typ from 0.6 V to 3.3 V
|   falling waveform, V_fixture 0V, R_fixture 150Ohm: 20-80 % time 319ps typ, 565ps min, 207ps max; typ from 2.69 V to 0 V
[Pulldown]
|   Voltage   I(typ)   I(min)   I(max)
-3.3V     -24.46mA   -19.21mA   -28.35mA
-2.132V   -23.6mA    -19.48mA   -26.68mA
-607.2mV  -16.26mA   -13.5mA    -18.25mA
-409.2mV  -12.29mA   -10.44mA   -13.66mA
1.996V    59.18mA    50.11mA    65.83mA
2.472V    73.45mA    60.41mA    82.24mA
2.779V    81.9mA     64.69mA    92.3mA
3.155V    90.79mA    67.13mA    104mA
3.749V    98.64mA    68.42mA    119.5mA
4.125V    100.4mA    68.85mA    125.6mA
4.471V    101.3mA    69.18mA    128.6mA
6.6V      103.7mA    70.44mA    133.1mA
[GND Clamp]
|   Voltage   I(typ)   I(min)   I(max)
-3.3V     -167.6mA   -127.2mA   -224.9mA
-1.013V   -18.75mA   -17.23mA   -21.53mA
-825mV    -10.45mA   -9.998mA   -12.1mA
-696.3mV  -5.878mA   -5.888mA   -6.705mA
-607.2mV  -3.274mA   -3.637mA   -3.483mA
-567.6mV  -2.199mA   -2.783mA   -2.434mA
-488.4mV  -789uA     -1.403mA   -561uA
-438.9mV  -300.8uA   -691.9uA   -143.7uA
-389.4mV  -56.07uA   -362.7uA   -19.27uA
-339.9mV  -12.95uA   -110.9uA   -2.791uA
-132mV    -51.25nA   -1.744uA   -79.98nA
6.6V      0A         0A         0A
[Pullup]
|   Voltage   I(typ)   I(min)   I(max)
-3.3V     22.07mA    16.03mA    26.56mA
-2.023V   20.9mA     17mA       23.64mA
-508.2mV  12.85mA    10.4mA     14.51mA
-270.6mV  8mA        6.632mA    9.017mA
1.996V    -57.9mA    -46.84mA   -65.39mA
2.501V    -72.66mA   -56.97mA   -83.01mA
2.917V    -83.55mA   -61.91mA   -96.49mA
3.333V    -92.26mA   -63.76mA   -109mA
3.887V    -98.25mA   -64.54mA   -122.7mA
4.155V    -99.36mA   -64.74mA   -127.3mA
4.709V    -100.5mA   -65.05mA   -132mA
6.6V      -102.6mA   -66.2mA    -134.9mA
[POWER Clamp]
|   Voltage   I(typ)   I(min)   I(max)
-3.3V     223mA      188.3mA    262.7mA
-1.201V   37.71mA    33.88mA    43.19mA
-1.191V   36.97mA    33.27mA    42.33mA
-1.152V   34.04mA    30.8mA     38.94mA
-983.4mV  22.42mA    20.88mA    25.69mA
-963.6mV  21.15mA    19.79mA    24.34mA
-805.2mV  13.3mA     12.07mA    16.24mA
-676.5mV  8.66mA     7.637mA    10.69mA
-488.4mV  3.031mA    3.154mA    3.565mA
-389.4mV  960.3uA    1.439mA    969.3uA
-290.4mV  115.1uA    394uA      56.19uA
6.6V      0A         0A         0A
[Ramp]
R_load = 150
|   typ   min   max
dV/dt_r   1.61296/2.14879e-10   1.39809/2.78854e-10   1.81326/2.11824e-10
dV/dt_f   1.61967/2.27889e-10   1.41579/2.82397e-10   1.81476/2.05857e-10
[Falling Waveform]
V_fixture = 3.3V
V_fixture_min = 2.97V
V_fixture_max = 3.63V
R_fixture = 150Ohm
C_fixture = 0F
|   Time   V(typ)   V(min)   V(max)
0s        3.3V       2.969V     3.63V
1.31ns    3.302V     2.97V      3.627V
1.66ns    3.312V     2.97V      1.089V
1.835ns   2.938V     2.972V     762.6mV
2.055ns   1.298V     2.978V     682.2mV
2.24ns    782.8mV    2.982V     645.8mV
2.62ns    650.8mV    2.915V     624.8mV
3.045ns   619.2mV    1.061V     616.3mV
3.35ns    612.9mV    699.3mV    613mV
10ns      600.2mV    609.8mV    605.2mV
[Rising Waveform]
V_fixture = 0V
V_fixture_min = 0V
V_fixture_max = 0V
R_fixture = 150Ohm
C_fixture = 0F
|   Time   V(typ)   V(min)   V(max)
0s        273.1uV    591.5uV    174.9uV
1.315ns   238uV      436.2uV    10.05mV
1.41ns    20.34uV    351.6uV    446.1mV
1.595ns   -1.768mV   317.1uV    2.183V
1.77ns    52.6mV     338.2uV    2.742V
2.095ns   2.195V     -266.2uV   2.97V
2.675ns   2.659V     42.12mV    3.015V
3.095ns   2.68V      1.889V     3.018V
3.54ns    2.684V     2.277V     3.02V
10ns      2.689V     2.331V     3.022V
[Rising Waveform]
V_fixture = 3.3V
V_fixture_min = 2.97V
V_fixture_max = 3.63V
R_fixture = 150Ohm
C_fixture = 0F
|   Time   V(typ)   V(min)   V(max)
0s        600.2mV    609.8mV    605.2mV
1.31ns    600.2mV    609.7mV    628mV
1.405ns   600.1mV    609.6mV    1.106V
1.595ns   606.6mV    609.6mV    2.889V
1.745ns   710.5mV    609.6mV    3.326V
2.025ns   2.708V     609.5mV    3.558V
2.54ns    3.247V     858.1mV    3.612V
2.995ns   3.281V     2.595V     3.622V
3.38ns    3.289V     2.895V     3.625V
10ns      3.3V       2.969V     3.63V
[Falling Waveform]
|Gnd
V_fixture = 0V
V_fixture_min = 0V
V_fixture_max = 0V
R_fixture = 150Ohm
C_fixture = 0F
|   Time   V(typ)   V(min)   V(max)
0s        2.689V     2.331V     3.022V
1.175ns   2.689V     2.331V     2.954V
1.34ns    2.681V     2.331V     2.391V
1.58ns    2.299V     2.331V     428.2mV
1.755ns   1.809V     2.33V      197.5mV
1.945ns   584.4mV    2.295V     91.65mV
2.1ns     208mV      2.118V     60.03mV
2.865ns   33.27mV    283.2mV    17.49mV
3.26ns    20.13mV    83.75mV    10.83mV
10ns      272.9uV    591.6uV    175.3uV
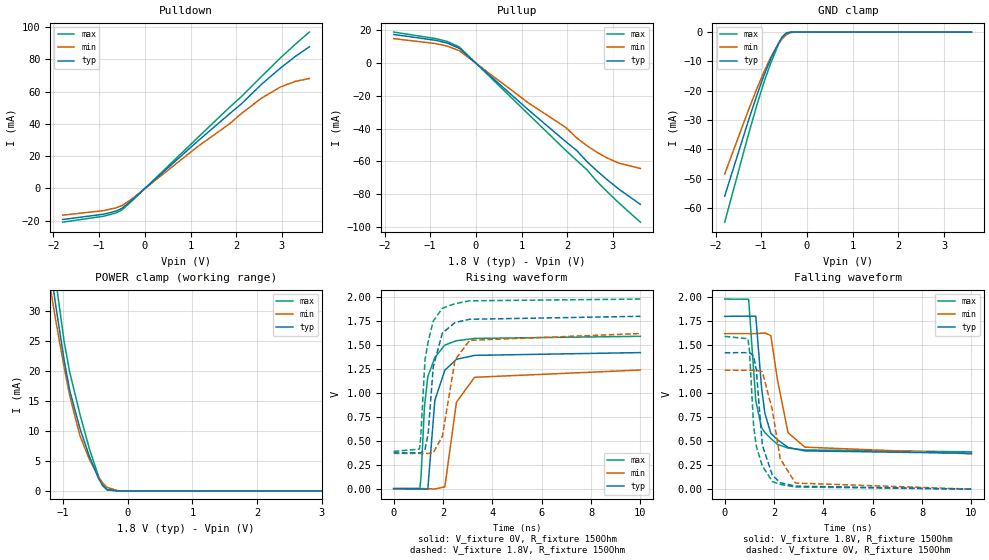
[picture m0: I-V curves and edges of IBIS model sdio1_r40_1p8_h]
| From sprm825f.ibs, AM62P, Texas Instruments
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|   r40_1p8_h
[Model]   sdio1_r40_1p8_h
Model_type   I/O
Polarity   Non-Inverting
Enable   Active-High
Vinl = 0
Vinh = 0.8
Vmeas = 0.9
Vref = 1.8
Cref = 2pF
Rref = 100000
|   typ   min   max
C_comp   7.913pF   7.707pF   7.969pF
[Voltage Range]   1.8   1.62   1.98
[Temperature Range]   27   150   -40
[Pullup Reference]   1.8   1.62   1.98
[Pulldown Reference]   0   0   0
[Power Clamp Reference]   1.8   1.62   1.98
[GND Clamp Reference]   0   0   0
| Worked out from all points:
|   slope of the pulldown table from 0 to 0.27 V, typ, clamps not added: 39.2 ohm
|   slope of the pullup table from 0 to 0.27 V, typ, clamps not added: 39.9 ohm
|   GND clamp passes 1 mA (typ) near -0.50 V on its own axis
|   POWER clamp passes 1 mA (typ) near -0.39 V on its own axis
|   falling waveform, V_fixture 1.8V, R_fixture 150Ohm: 20-80 % time 381ps typ, 505ps min, 345ps max; typ from 1.8 V to 0.374 V
|   rising waveform, V_fixture 0V, R_fixture 150Ohm: 20-80 % time 392ps typ, 476ps min, 388ps max; typ from 0 V to 1.42 V
|   rising waveform, V_fixture 1.8V, R_fixture 150Ohm: 20-80 % time 390ps typ, 483ps min, 375ps max; typ from 0.374 V to 1.8 V
|   falling waveform, V_fixture 0V, R_fixture 150Ohm: 20-80 % time 395ps typ, 510ps min, 391ps max; typ from 1.42 V to 0 V
[Pulldown]
|   Voltage   I(typ)   I(min)   I(max)
-1.8V     -19.28mA   -16.58mA   -20.93mA
-892.8mV  -15.94mA   -13.72mA   -17.19mA
-622.8mV  -13.96mA   -11.96mA   -15.1mA
-498.6mV  -12.28mA   -10.57mA   -13.28mA
-298.8mV  -7.64mA    -6.833mA   -8.173mA
1.154V    29.3mA     25.93mA    31.47mA
1.856V    46.38mA    40.15mA    50.39mA
2.12V     52.65mA    46.63mA    57.18mA
2.552V    64.58mA    55.99mA    69.41mA
2.968V    74.7mA     62.95mA    81mA
3.292V    81.89mA    66.42mA    89.43mA
3.6V      87.86mA    68.2mA     97mA
[GND Clamp]
|   Voltage   I(typ)   I(min)   I(max)
-1.8V     -55.9mA    -48.35mA   -64.79mA
-1.287V   -30.48mA   -26.87mA   -35.27mA
-1.109V   -22.12mA   -19.8mA    -25.59mA
-946.8mV  -15.01mA   -13.77mA   -17.35mA
-790.2mV  -8.997mA   -8.533mA   -10.48mA
-622.8mV  -3.762mA   -4.011mA   -4.148mA
-541.8mV  -1.721mA   -2.298mA   -1.693mA
-450mV    -363uA     -857.5uA   -221.7uA
-347.4mV  -20.25uA   -138.5uA   -4.047uA
-234mV    -328.7nA   -10.21uA   -105.1nA
3.6V      0A         0A         0A
[Pullup]
|   Voltage   I(typ)   I(min)   I(max)
-1.8V     17.29mA    14.76mA    18.75mA
-887.4mV  13.77mA    11.79mA    14.82mA
-628.2mV  12.1mA     10.22mA    13.07mA
-363.6mV  8.839mA    7.421mA    9.688mA
1.138V    -28.35mA   -24.18mA   -30.97mA
1.969V    -48.05mA   -39.37mA   -53.35mA
2.201V    -53.23mA   -45.58mA   -59.29mA
2.434V    -60.24mA   -50.5mA    -65.2mA
2.639V    -65.53mA   -54.28mA   -71.94mA
2.866V    -70.99mA   -57.86mA   -78.26mA
3.13V     -76.95mA   -61.09mA   -85.31mA
3.6V      -86.2mA    -64.31mA   -97.05mA
[POWER Clamp]
|   Voltage   I(typ)   I(min)   I(max)
-1.8V     86.44mA    75.43mA    99.9mA
-1.287V   44.12mA    39.56mA    50.59mA
-1.109V   30.39mA    27.98mA    34.62mA
-984.6mV  21.72mA    20.51mA    24.79mA
-898.2mV  16.68mA    15.82mA    19.69mA
-741.6mV  10.42mA    9.224mA    12.8mA
-595.8mV  5.776mA    5.267mA    7.057mA
-450mV    2.018mA    2.285mA    2.308mA
-390.6mV  933uA      1.359mA    950.1uA
-320.4mV  226.3uA    591.6uA    146.8uA
-147.6mV  917.5nA    14.06uA    197.8nA
3.6V      0A         0A         0A
[Ramp]
R_load = 150
|   typ   min   max
dV/dt_r   0.852598/3.91919e-10   0.742887/4.76013e-10   0.954205/3.88609e-10
dV/dt_f   0.855747/3.79521e-10   0.751111/5.00023e-10   0.954658/3.44802e-10
[Falling Waveform]
V_fixture = 1.8V
V_fixture_min = 1.62V
V_fixture_max = 1.98V
R_fixture = 150Ohm
C_fixture = 0F
|   Time   V(typ)   V(min)   V(max)
0s        1.8V       1.62V      1.98V
970ps     1.802V     1.62V      1.978V
1.26ns    1.802V     1.62V      919.6mV
1.495ns   1.052V     1.624V     640.3mV
1.63ns    788.7mV    1.628V     589.9mV
1.87ns    581.3mV    1.599V     527.6mV
2.14ns    514.9mV    1.137V     466.7mV
2.57ns    434.7mV    587.5mV    428.4mV
3.25ns    399mV      437.8mV    408.3mV
10ns      373.6mV    367.7mV    388.8mV
[Rising Waveform]
V_fixture = 0V
V_fixture_min = 0V
V_fixture_max = 0V
R_fixture = 150Ohm
C_fixture = 0F
|   Time   V(typ)   V(min)   V(max)
0s        269.3uV    665.7uV    176.7uV
1.065ns   -1.958mV   469.1uV    3.076mV
1.11ns    -2.732mV   473.5uV    125.1mV
1.25ns    -5.339mV   427.9uV    861.2mV
1.385ns   -4.684mV   -581.5uV   1.169V
1.67ns    922.7mV    -3.461mV   1.37V
2.075ns   1.237V     18.85mV    1.5V
2.545ns   1.351V     902.5mV    1.545V
3.28ns    1.392V     1.163V     1.569V
10ns      1.421V     1.239V     1.591V
[Rising Waveform]
V_fixture = 1.8V
V_fixture_min = 1.62V
V_fixture_max = 1.98V
R_fixture = 150Ohm
C_fixture = 0F
|   Time   V(typ)   V(min)   V(max)
0s        373.6mV    367.7mV    388.8mV
1.045ns   372.7mV    367.4mV    412.9mV
1.095ns   373.3mV    367.4mV    526mV
1.27ns    406.1mV    367.3mV    1.346V
1.4ns     578.6mV    367.2mV    1.536V
1.605ns   1.272V     374.5mV    1.751V
1.975ns   1.625V     548.6mV    1.884V
2.49ns    1.735V     1.346V     1.932V
3.08ns    1.769V     1.549V     1.962V
10ns      1.8V       1.62V      1.98V
[Falling Waveform]
|Gnd
V_fixture = 0V
V_fixture_min = 0V
V_fixture_max = 0V
R_fixture = 150Ohm
C_fixture = 0F
|   Time   V(typ)   V(min)   V(max)
0s        1.421V     1.239V     1.591V
945ps     1.422V     1.239V     1.567V
1.01ns    1.422V     1.239V     1.42V
1.17ns    1.389V     1.239V     666.5mV
1.28ns    1.244V     1.239V     447.9mV
1.525ns   459.3mV    1.224V     241.5mV
1.93ns    147.1mV    825.9mV    80.49mV
2.25ns    67.74mV    316.5mV    49.84mV
2.87ns    31.49mV    63.8mV     23.15mV
10ns      269.3uV    665.9uV    178.1uV
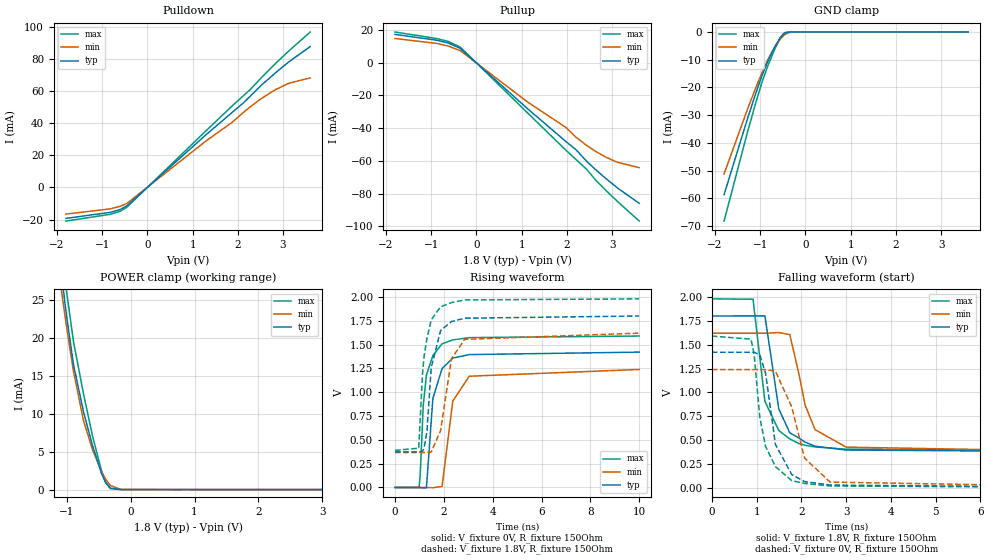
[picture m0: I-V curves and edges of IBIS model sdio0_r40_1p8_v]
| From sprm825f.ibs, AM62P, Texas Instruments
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|   r40_1p8_v
[Model]   sdio0_r40_1p8_v
Model_type   I/O
Polarity   Non-Inverting
Enable   Active-High
Vinl = 0
Vinh = 0.8
Vmeas = 0.9
Vref = 1.8
Cref = 2pF
Rref = 100000
|   typ   min   max
C_comp   6.976pF   6.800pF   6.977pF
[Voltage Range]   1.8   1.62   1.98
[Temperature Range]   27   150   -40
[Pullup Reference]   1.8   1.62   1.98
[Pulldown Reference]   0   0   0
[Power Clamp Reference]   1.8   1.62   1.98
[GND Clamp Reference]   0   0   0
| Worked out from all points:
|   slope of the pulldown table from 0 to 0.27 V, typ, clamps not added: 39.3 ohm
|   slope of the pullup table from 0 to 0.27 V, typ, clamps not added: 40 ohm
|   GND clamp passes 1 mA (typ) near -0.50 V on its own axis
|   POWER clamp passes 1 mA (typ) near -0.39 V on its own axis
|   falling waveform, V_fixture 1.8V, R_fixture 150Ohm: 20-80 % time 339ps typ, 420ps min, 306ps max; typ from 1.8 V to 0.374 V
|   rising waveform, V_fixture 0V, R_fixture 150Ohm: 20-80 % time 358ps typ, 435ps min, 347ps max; typ from 0 V to 1.42 V
|   rising waveform, V_fixture 1.8V, R_fixture 150Ohm: 20-80 % time 349ps typ, 447ps min, 334ps max; typ from 0.374 V to 1.8 V
|   falling waveform, V_fixture 0V, R_fixture 150Ohm: 20-80 % time 361ps typ, 444ps min, 349ps max; typ from 1.42 V to 0 V
[Pulldown]
|   Voltage   I(typ)   I(min)   I(max)
-1.8V     -19.24mA   -16.57mA   -20.88mA
-817.2mV  -15.47mA   -13.31mA   -16.69mA
-595.8mV  -13.64mA   -11.69mA   -14.75mA
-450mV    -11.31mA   -9.86mA    -12.17mA
1.289V    32.62mA    28.79mA    35.08mA
1.872V    46.66mA    40.48mA    50.66mA
2.115V    52.41mA    46.51mA    56.88mA
2.266V    56.58mA    50.01mA    60.72mA
2.525V    63.76mA    55.4mA     68.42mA
2.828V    71.21mA    60.81mA    77.02mA
3.125V    78.1mA     64.81mA    84.86mA
3.6V      87.67mA    68.16mA    96.71mA
[GND Clamp]
|   Voltage   I(typ)   I(min)   I(max)
-1.8V     -58.72mA   -51.23mA   -68.24mA
-1.271V   -30.69mA   -27.39mA   -35.46mA
-1.098V   -22.1mA    -20.06mA   -25.47mA
-952.2mV  -15.37mA   -14.29mA   -17.66mA
-822.6mV  -10.14mA   -9.655mA   -11.8mA
-671.4mV  -5.164mA   -5.19mA    -5.873mA
-563.4mV  -2.202mA   -2.714mA   -2.268mA
-487.8mV  -770.7uA   -1.357mA   -615uA
-439.2mV  -272.5uA   -734.7uA   -140.6uA
-369mV    -36.01uA   -217.7uA   -8.95uA
-255.6mV  -694nA     -16.46uA   -114.6nA
3.6V      0A         0A         0A
[Pullup]
|   Voltage   I(typ)   I(min)   I(max)
-1.8V     17.27mA    14.77mA    18.72mA
-887.4mV  13.75mA    11.78mA    14.79mA
-628.2mV  12.07mA    10.21mA    13.04mA
-358.2mV  8.717mA    7.34mA     9.549mA
1.138V    -28.29mA   -24.16mA   -30.88mA
1.98V     -48.19mA   -39.56mA   -53.47mA
2.201V    -53.12mA   -45.56mA   -59.11mA
2.439V    -60.28mA   -50.55mA   -65.17mA
2.633V    -65.26mA   -54.13mA   -71.59mA
2.871V    -70.96mA   -57.85mA   -78.18mA
3.125V    -76.65mA   -60.89mA   -84.92mA
3.6V      -85.89mA   -64.11mA   -96.71mA
[POWER Clamp]
|   Voltage   I(typ)   I(min)   I(max)
-1.8V     85.65mA    74.47mA    98.51mA
-1.287V   43.92mA    39.26mA    50.24mA
-1.13V    31.96mA    29.2mA     36.42mA
-1.006V   23.2mA     21.73mA    26.43mA
-892.8mV  16.49mA    15.59mA    19.51mA
-736.2mV  10.27mA    9.092mA    12.63mA
-595.8mV  5.806mA    5.297mA    7.095mA
-450mV    2.033mA    2.29mA     2.335mA
-390.6mV  941.9uA    1.376mA    958.2uA
-315mV    199.5uA    531uA      119.1uA
-147.6mV  835.7nA    14.07uA    186.3nA
3.6V      0A         0A         0A
[Ramp]
R_load = 150
|   typ   min   max
dV/dt_r   0.852335/3.58302e-10   0.742947/4.32864e-10   0.953788/3.46866e-10
dV/dt_f   0.855499/3.36816e-10   0.751211/4.18297e-10   0.954247/3.04296e-10
[Falling Waveform]
V_fixture = 1.8V
V_fixture_min = 1.62V
V_fixture_max = 1.98V
R_fixture = 150Ohm
C_fixture = 0F
|   Time   V(typ)   V(min)   V(max)
0s        1.8V       1.62V      1.98V
920ps     1.802V     1.62V      1.976V
1.185ns   1.802V     1.62V      906.2mV
1.495ns   827.7mV    1.627V     600.9mV
1.74ns    577.7mV    1.606V     512.8mV
1.94ns    523.2mV    1.204V     465.3mV
2.085ns   478.4mV    865.5mV    446.3mV
2.305ns   436.3mV    610.1mV    428.6mV
3ns       396.3mV    426.8mV    405.5mV
10ns      374mV      367.6mV    389.5mV
[Rising Waveform]
V_fixture = 0V
V_fixture_min = 0V
V_fixture_max = 0V
R_fixture = 150Ohm
C_fixture = 0F
|   Time   V(typ)   V(min)   V(max)
0s        206.9uV    471.4uV    132.9uV
985ps     -1.162mV   369.1uV    1.71mV
1.03ns    -1.864mV   368.1uV    131.4mV
1.155ns   -3.9mV     407.7uV    862mV
1.285ns   -3.567mV   -135.7uV   1.18V
1.55ns    934.7mV    -2.785mV   1.385V
1.925ns   1.248V     10.93mV    1.508V
2.365ns   1.358V     907.1mV    1.549V
3.04ns    1.395V     1.168V     1.573V
10ns      1.421V     1.239V     1.59V
[Rising Waveform]
V_fixture = 1.8V
V_fixture_min = 1.62V
V_fixture_max = 1.98V
R_fixture = 150Ohm
C_fixture = 0F
|   Time   V(typ)   V(min)   V(max)
0s        374mV      367.6mV    389.5mV
970ps     373.4mV    367.4mV    412.2mV
1.125ns   382.2mV    367.5mV    1.194V
1.185ns   406.3mV    367.4mV    1.368V
1.305ns   584.9mV    367.2mV    1.563V
1.48ns    1.256V     371.5mV    1.759V
1.865ns   1.648V     596.5mV    1.897V
2.31ns    1.742V     1.352V     1.941V
2.855ns   1.777V     1.555V     1.969V
10ns      1.8V       1.62V      1.98V
[Falling Waveform]
|Gnd
V_fixture = 0V
V_fixture_min = 0V
V_fixture_max = 0V
R_fixture = 150Ohm
C_fixture = 0F
|   Time   V(typ)   V(min)   V(max)
0s        1.421V     1.239V     1.59V
875ps     1.421V     1.239V     1.558V
945ps     1.421V     1.239V     1.397V
1.07ns    1.393V     1.239V     738.5mV
1.2ns     1.201V     1.239V     433.5mV
1.42ns    455.7mV    1.223V     222.1mV
1.785ns   138.8mV    847.3mV    75.55mV
2.07ns    65.82mV    312.5mV    46.53mV
2.64ns    29.16mV    60.59mV    19.94mV
10ns      207.3uV    470.5uV    132.9uV
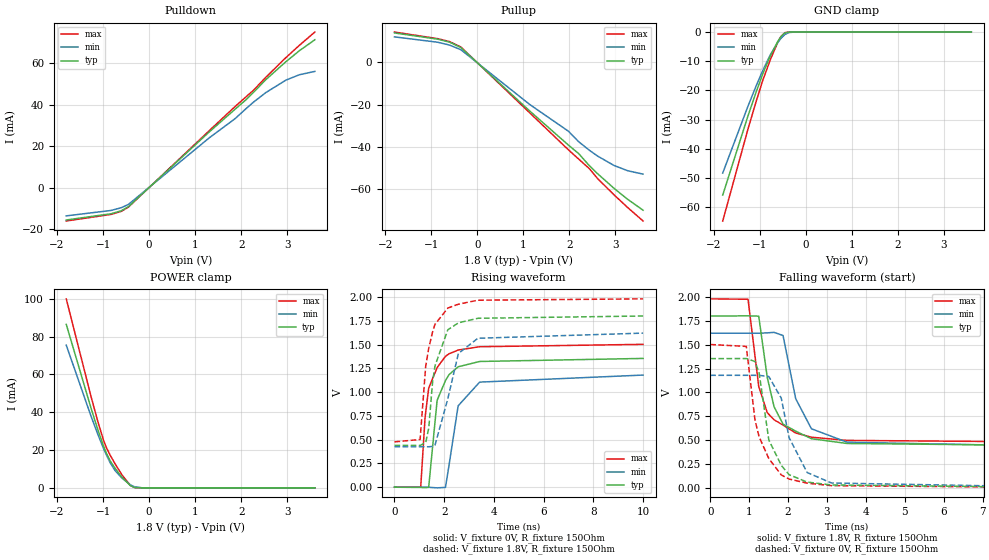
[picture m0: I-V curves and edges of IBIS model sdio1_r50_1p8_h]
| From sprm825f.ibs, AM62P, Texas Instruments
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|   r50_1p8_h
[Model]   sdio1_r50_1p8_h
Model_type   I/O
Polarity   Non-Inverting
Enable   Active-High
Vinl = 0
Vinh = 0.8
Vmeas = 0.9
Vref = 1.8
Cref = 2pF
Rref = 100000
|   typ   min   max
C_comp   7.913pF   7.707pF   7.969pF
[Voltage Range]   1.8   1.62   1.98
[Temperature Range]   27   150   -40
[Pullup Reference]   1.8   1.62   1.98
[Pulldown Reference]   0   0   0
[Power Clamp Reference]   1.8   1.62   1.98
[GND Clamp Reference]   0   0   0
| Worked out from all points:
|   slope of the pulldown table from 0 to 0.27 V, typ, clamps not added: 48.4 ohm
|   slope of the pullup table from 0 to 0.27 V, typ, clamps not added: 49.2 ohm
|   GND clamp passes 1 mA (typ) near -0.50 V on its own axis
|   POWER clamp passes 1 mA (typ) near -0.39 V on its own axis
|   falling waveform, V_fixture 1.8V, R_fixture 150Ohm: 20-80 % time 439ps typ, 515ps min, 422ps max; typ from 1.8 V to 0.44 V
|   rising waveform, V_fixture 0V, R_fixture 150Ohm: 20-80 % time 502ps typ, 559ps min, 490ps max; typ from 0 V to 1.35 V
|   rising waveform, V_fixture 1.8V, R_fixture 150Ohm: 20-80 % time 462ps typ, 606ps min, 469ps max; typ from 0.44 V to 1.8 V
|   falling waveform, V_fixture 0V, R_fixture 150Ohm: 20-80 % time 478ps typ, 519ps min, 488ps max; typ from 1.35 V to 0 V
[Pulldown]
|   Voltage   I(typ)   I(min)   I(max)
-1.8V     -15.62mA   -13.64mA   -16.12mA
-828mV    -12.62mA   -11.02mA   -12.94mA
-606.6mV  -11.18mA   -9.715mA   -11.49mA
-450mV    -9.198mA   -8.116mA   -9.407mA
1.316V    27.07mA    24.2mA     27.69mA
1.861V    37.71mA    33.16mA    39mA
2.12V     42.7mA     38.41mA    44.11mA
2.266V    45.96mA    41.23mA    46.97mA
2.536V    52.13mA    45.88mA    53.25mA
2.974V    60.82mA    51.91mA    62.81mA
3.265V    66.09mA    54.48mA    68.7mA
3.6V      71.36mA    56.09mA    75.09mA
[GND Clamp]
|   Voltage   I(typ)   I(min)   I(max)
-1.8V     -55.9mA    -48.35mA   -64.79mA
-1.255V   -28.93mA   -25.56mA   -33.47mA
-1.076V   -20.66mA   -18.55mA   -23.89mA
-930.6mV  -14.34mA   -13.21mA   -16.58mA
-768.6mV  -8.276mA   -7.871mA   -9.608mA
-606.6mV  -3.3mA     -3.654mA   -3.6mA
-536.4mV  -1.601mA   -2.185mA   -1.566mA
-450mV    -327.4uA   -852.5uA   -209.4uA
-358.2mV  -29.45uA   -169uA     -5.977uA
-239.4mV  -441.5nA   -11.55uA   -121.3nA
3.6V      0A         0A         0A
[Pullup]
|   Voltage   I(typ)   I(min)   I(max)
-1.8V     14.01mA    12.14mA    14.44mA
-865.8mV  11.07mA    9.615mA    11.32mA
-606.6mV  9.659mA    8.274mA    9.921mA
-358.2mV  7.082mA    6.053mA    7.368mA
1.138V    -23mA      -19.92mA   -23.87mA
1.98V     -39.19mA   -32.61mA   -41.44mA
2.201V    -43.2mA    -37.56mA   -45.79mA
2.434V    -48.94mA   -41.63mA   -50.35mA
2.612V    -52.73mA   -44.36mA   -55.02mA
2.968V    -59.64mA   -48.81mA   -62.72mA
3.265V    -64.86mA   -51.32mA   -68.76mA
3.6V      -70.03mA   -52.92mA   -75.15mA
[POWER Clamp]
|   Voltage   I(typ)   I(min)   I(max)
-1.8V     86.44mA    75.43mA    99.9mA
-1.26V    41.98mA    37.75mA    48.1mA
-1.109V   30.39mA    27.97mA    34.62mA
-990mV    22.06mA    20.81mA    25.16mA
-930.6mV  18.44mA    17.53mA    21.37mA
-844.2mV  14.2mA     13.21mA    17.16mA
-741.6mV  10.42mA    9.226mA    12.81mA
-595.8mV  5.783mA    5.268mA    7.062mA
-406.8mV  1.193mA    1.584mA    1.267mA
-315mV    187uA      546.2uA    116.5uA
-147.6mV  628.8nA    14.04uA    194.3nA
3.6V      0A         0A         0A
[Ramp]
R_load = 150
|   typ   min   max
dV/dt_r   0.812415/5.03508e-10   0.706683/5.59233e-10   0.901115/4.8967e-10
dV/dt_f   0.81606/4.37099e-10   0.71599/5.14122e-10   0.901707/4.20849e-10
[Falling Waveform]
V_fixture = 1.8V
V_fixture_min = 1.62V
V_fixture_max = 1.98V
R_fixture = 150Ohm
C_fixture = 0F
|   Time   V(typ)   V(min)   V(max)
0s        1.8V       1.62V      1.98V
970ps     1.802V     1.62V      1.976V
1.245ns   1.799V     1.62V      1.063V
1.465ns   1.156V     1.624V     787.3mV
1.64ns    849.1mV    1.629V     713.4mV
1.87ns    667.8mV    1.596V     657.8mV
2.195ns   594mV      934.8mV    574.9mV
2.6ns     515.1mV    619mV      530.8mV
3.515ns   465mV      478.4mV    497.3mV
10ns      439.7mV    426.2mV    477mV
[Rising Waveform]
V_fixture = 0V
V_fixture_min = 0V
V_fixture_max = 0V
R_fixture = 150Ohm
C_fixture = 0F
|   Time   V(typ)   V(min)   V(max)
0s        324.9uV    770.3uV    225.8uV
1.055ns   -1.891mV   541.4uV    947.5uV
1.23ns    -4.433mV   593.3uV    732.6mV
1.375ns   -806.9uV   -648.4uV   1.041V
1.715ns   914mV      -6.347mV   1.258V
2.05ns    1.121V     -1.969mV   1.376V
2.195ns   1.184V     232.9mV    1.403V
2.56ns    1.266V     855.6mV    1.442V
3.425ns   1.322V     1.105V     1.477V
10ns      1.354V     1.179V     1.502V
[Rising Waveform]
V_fixture = 1.8V
V_fixture_min = 1.62V
V_fixture_max = 1.98V
R_fixture = 150Ohm
C_fixture = 0F
|   Time   V(typ)   V(min)   V(max)
0s        439.7mV    426.2mV    477mV
1.03ns    439mV      425.9mV    501.8mV
1.255ns   470.3mV    425.8mV    1.271V
1.38ns    621.7mV    425.5mV    1.464V
1.53ns    1.101V     429.5mV    1.631V
1.63ns    1.276V     442.8mV    1.713V
2.145ns   1.655V     930.2mV    1.883V
2.57ns    1.728V     1.406V     1.924V
3.355ns   1.776V     1.566V     1.966V
10ns      1.8V       1.62V      1.98V
[Falling Waveform]
|Gnd
V_fixture = 0V
V_fixture_min = 0V
V_fixture_max = 0V
R_fixture = 150Ohm
C_fixture = 0F
|   Time   V(typ)   V(min)   V(max)
0s        1.354V     1.179V     1.502V
925ps     1.355V     1.179V     1.482V
1.15ns    1.324V     1.179V     709.3mV
1.255ns   1.204V     1.179V     535.2mV
1.505ns   501.4mV    1.166V     306.7mV
1.825ns   235.7mV    939.7mV    135.3mV
2.025ns   138.3mV    526.8mV    92.6mV
2.49ns    60.52mV    160.9mV    49.1mV
3.115ns   30.55mV    51.03mV    23.36mV
10ns      324.9uV    770.5uV    225.8uV
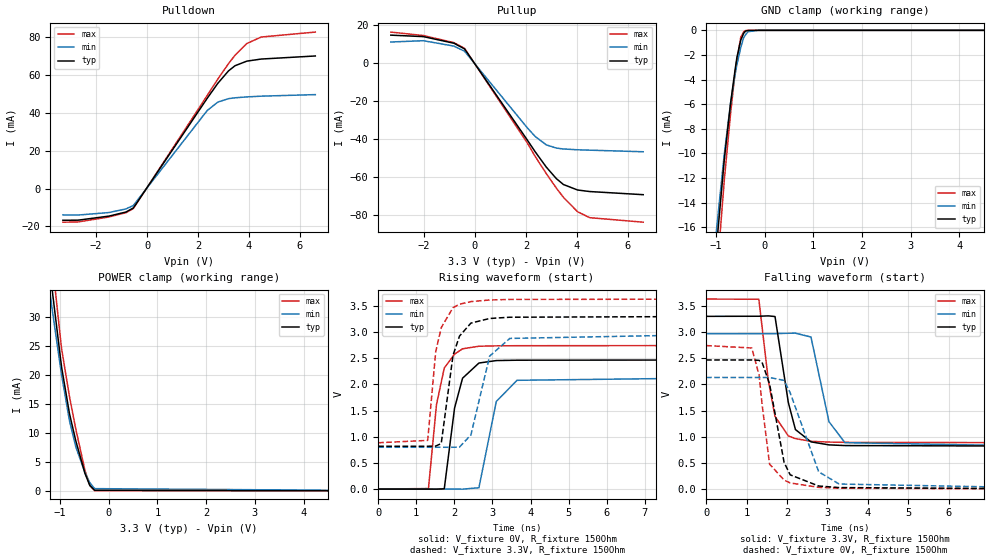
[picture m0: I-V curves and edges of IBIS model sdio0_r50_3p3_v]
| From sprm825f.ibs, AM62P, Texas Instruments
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|   r50_3p3_v
[Model]   sdio0_r50_3p3_v
Model_type   I/O
Polarity   Non-Inverting
Enable   Active-High
Vinl = 0
Vinh = 0.8
Vmeas = 1.65
Vref = 3.3
Cref = 2pF
Rref = 100000
|   typ   min   max
C_comp   4.972pF   4.893pF   4.997pF
[Voltage Range]   3.3   2.97   3.63
[Temperature Range]   27   150   -40
[Pullup Reference]   3.3   2.97   3.63
[Pulldown Reference]   0   0   0
[Power Clamp Reference]   3.3   2.97   3.63
[GND Clamp Reference]   0   0   0
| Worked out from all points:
|   slope of the pulldown table from 0 to 0.495 V, typ, clamps not added: 49.3 ohm
|   slope of the pullup table from 0 to 0.495 V, typ, clamps not added: 50.4 ohm
|   GND clamp passes 1 mA (typ) near -0.50 V on its own axis
|   POWER clamp passes 1 mA (typ) near -0.39 V on its own axis
|   falling waveform, V_fixture 3.3V, R_fixture 150Ohm: 20-80 % time 300ps typ, 354ps min, 284ps max; typ from 3.3 V to 0.819 V
|   rising waveform, V_fixture 0V, R_fixture 150Ohm: 20-80 % time 286ps typ, 345ps min, 277ps max; typ from 0 V to 2.47 V
|   rising waveform, V_fixture 3.3V, R_fixture 150Ohm: 20-80 % time 268ps typ, 399ps min, 273ps max; typ from 0.819 V to 3.3 V
|   falling waveform, V_fixture 0V, R_fixture 150Ohm: 20-80 % time 351ps typ, 594ps min, 238ps max; typ from 2.47 V to 0 V
[Pulldown]
|   Voltage   I(typ)   I(min)   I(max)
-3.3V     -16.73mA   -13.92mA   -17.75mA
-2.706V   -16.69mA   -13.98mA   -17.62mA
-1.498V   -14.55mA   -12.67mA   -15.02mA
-825mV    -12.38mA   -10.75mA   -12.74mA
-537.9mV  -10.26mA   -8.938mA   -10.57mA
2.363V    47.65mA    41.19mA    49.15mA
2.779V    55.55mA    45.62mA    57.8mA
3.194V    62.03mA    47.4mA     65.85mA
3.452V    64.79mA    47.87mA    70.33mA
3.917V    67.22mA    48.34mA    76.54mA
4.481V    68.31mA    48.73mA    79.93mA
6.6V      69.93mA    49.55mA    82.53mA
[GND Clamp]
|   Voltage   I(typ)   I(min)   I(max)
-3.3V     -167.6mA   -127.2mA   -224.9mA
-1.013V   -18.75mA   -17.23mA   -21.53mA
-825mV    -10.45mA   -9.999mA   -12.11mA
-696.3mV  -5.878mA   -5.888mA   -6.705mA
-607.2mV  -3.274mA   -3.636mA   -3.486mA
-567.6mV  -2.201mA   -2.784mA   -2.433mA
-488.4mV  -790.5uA   -1.403mA   -561.9uA
-429mV    -244.1uA   -590.5uA   -117.7uA
-389.4mV  -55.8uA    -362.5uA   -20.11uA
-339.9mV  -13.05uA   -110.4uA   -2.848uA
-132mV    -51.23nA   -1.745uA   -80.02nA
6.6V      0A         0A         0A
[Pullup]
|   Voltage   I(typ)   I(min)   I(max)
-3.3V     14.9mA     11.28mA    16.51mA
-2.023V   14.12mA    11.97mA    14.7mA
-825mV    10.63mA    9.127mA    10.93mA
-409.2mV  7.656mA    6.429mA    7.973mA
2.056V    -40.44mA   -34mA      -41.99mA
2.363V    -46.6mA    -38.51mA   -49.05mA
2.798V    -54.66mA   -42.94mA   -58.08mA
3.194V    -60.76mA   -44.64mA   -65.75mA
3.472V    -63.86mA   -45.11mA   -70.63mA
4.026V    -66.74mA   -45.54mA   -78.21mA
4.501V    -67.55mA   -45.74mA   -81.33mA
6.6V      -69.21mA   -46.58mA   -83.71mA
[POWER Clamp]
|   Voltage   I(typ)   I(min)   I(max)
-3.3V     223mA      188.3mA    262.7mA
-1.201V   37.71mA    33.88mA    43.19mA
-1.191V   36.97mA    33.27mA    42.33mA
-1.152V   34.04mA    30.8mA     38.94mA
-983.4mV  22.42mA    20.88mA    25.69mA
-963.6mV  21.15mA    19.79mA    24.33mA
-805.2mV  13.3mA     12.07mA    16.24mA
-676.5mV  8.66mA     7.636mA    10.69mA
-488.4mV  3.032mA    3.154mA    3.565mA
-389.4mV  959.3uA    1.439mA    971.7uA
-290.4mV  115.2uA    394.4uA    56.55uA
6.6V      0A         0A         0A
[Ramp]
R_load = 150
|   typ   min   max
dV/dt_r   1.47998/2.85323e-10   1.27948/3.43695e-10   1.64476/2.76258e-10
dV/dt_f   1.48868/2.97616e-10   1.30209/3.51727e-10   1.6468/2.84225e-10
[Falling Waveform]
V_fixture = 3.3V
V_fixture_min = 2.97V
V_fixture_max = 3.63V
R_fixture = 150Ohm
C_fixture = 0F
|   Time   V(typ)   V(min)   V(max)
0s        3.3V       2.969V     3.63V
1.305ns   3.302V     2.97V      3.627V
1.54ns    3.309V     2.97V      2.072V
1.705ns   3.296V     2.97V      1.39V
2.035ns   1.653V     2.977V     1.016V
2.21ns    1.139V     2.979V     965.9mV
2.595ns   903.4mV    2.905V     913.8mV
3.04ns    845.8mV    1.289V     899.3mV
3.435ns   832.7mV    887.7mV    894mV
10ns      818.5mV    799.2mV    885mV
[Rising Waveform]
V_fixture = 0V
V_fixture_min = 0V
V_fixture_max = 0V
R_fixture = 150Ohm
C_fixture = 0F
|   Time   V(typ)   V(min)   V(max)
0s        358.2uV    734.9uV    249.7uV
1.32ns    296.4uV    536.7uV    10.57mV
1.53ns    -1.283mV   403.4uV    1.611V
1.735ns   5.726mV    394.1uV    2.313V
2.005ns   1.547V     118.3uV    2.578V
2.215ns   2.118V     -1.486mV   2.68V
2.645ns   2.408V     25.78mV    2.729V
3.1ns     2.455V     1.673V     2.736V
3.645ns   2.462V     2.078V     2.739V
10ns      2.467V     2.133V     2.742V
[Rising Waveform]
V_fixture = 3.3V
V_fixture_min = 2.97V
V_fixture_max = 3.63V
R_fixture = 150Ohm
C_fixture = 0F
|   Time   V(typ)   V(min)   V(max)
0s        818.5mV    799.2mV    885mV
1.3ns     818.4mV    799.1mV    930.3mV
1.51ns    821.4mV    799mV      2.623V
1.655ns   870.4mV    799mV      3.084V
1.965ns   2.557V     798.9mV    3.466V
2.135ns   2.923V     803.1mV    3.531V
2.435ns   3.171V     1.035V     3.582V
2.925ns   3.259V     2.54V      3.612V
3.455ns   3.283V     2.878V     3.623V
10ns      3.3V       2.969V     3.63V
[Falling Waveform]
|Gnd
V_fixture = 0V
V_fixture_min = 0V
V_fixture_max = 0V
R_fixture = 150Ohm
C_fixture = 0F
|   Time   V(typ)   V(min)   V(max)
0s        2.467V     2.133V     2.742V
1.13ns    2.467V     2.133V     2.696V
1.31ns    2.46V      2.133V     2.181V
1.385ns   2.421V     2.133V     1.621V
1.57ns    2.009V     2.133V     479.3mV
1.93ns    511mV      2.077V     173mV
2.08ns    274.1mV    1.841V     118.8mV
2.785ns   60.68mV    332.3mV    35.04mV
3.29ns    30.44mV    98.21mV    18.93mV
10ns      358.5uV    735.2uV    249.3uV
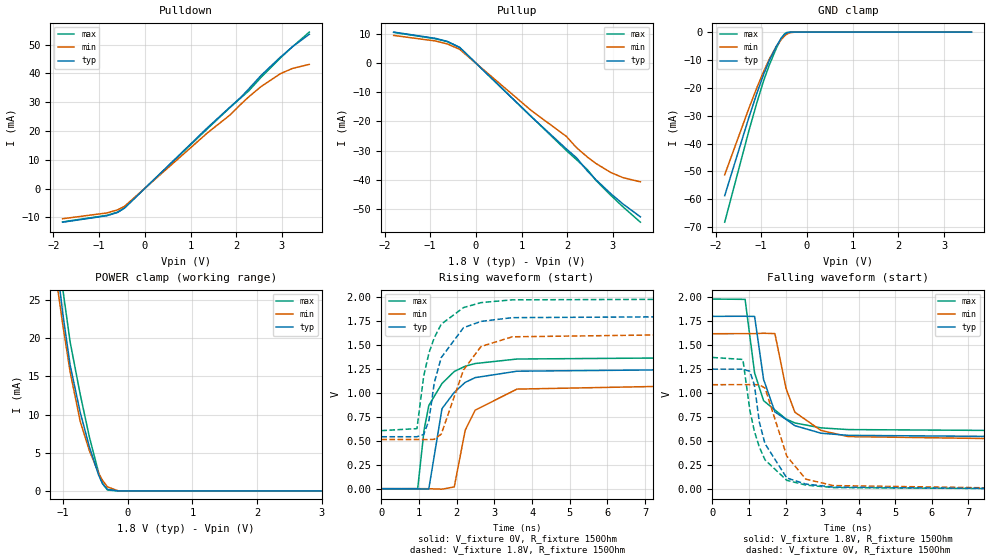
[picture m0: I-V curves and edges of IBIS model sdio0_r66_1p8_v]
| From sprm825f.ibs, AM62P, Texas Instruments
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|   r66_1p8_v
[Model]   sdio0_r66_1p8_v
Model_type   I/O
Polarity   Non-Inverting
Enable   Active-High
Vinl = 0
Vinh = 0.8
Vmeas = 0.9
Vref = 1.8
Cref = 2pF
Rref = 100000
|   typ   min   max
C_comp   6.976pF   6.800pF   6.977pF
[Voltage Range]   1.8   1.62   1.98
[Temperature Range]   27   150   -40
[Pullup Reference]   1.8   1.62   1.98
[Pulldown Reference]   0   0   0
[Power Clamp Reference]   1.8   1.62   1.98
[GND Clamp Reference]   0   0   0
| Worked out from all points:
|   slope of the pulldown table from 0 to 0.27 V, typ, clamps not added: 64.6 ohm
|   slope of the pullup table from 0 to 0.27 V, typ, clamps not added: 65.7 ohm
|   GND clamp passes 1 mA (typ) near -0.50 V on its own axis
|   POWER clamp passes 1 mA (typ) near -0.39 V on its own axis
|   falling waveform, V_fixture 1.8V, R_fixture 150Ohm: 20-80 % time 480ps typ, 535ps min, 520ps max; typ from 1.8 V to 0.543 V
|   rising waveform, V_fixture 0V, R_fixture 150Ohm: 20-80 % time 570ps typ, 638ps min, 565ps max; typ from 0 V to 1.25 V
|   rising waveform, V_fixture 1.8V, R_fixture 150Ohm: 20-80 % time 515ps typ, 638ps min, 540ps max; typ from 0.543 V to 1.8 V
|   falling waveform, V_fixture 0V, R_fixture 150Ohm: 20-80 % time 512ps typ, 567ps min, 540ps max; typ from 1.25 V to 0 V
[Pulldown]
|   Voltage   I(typ)   I(min)   I(max)
-1.8V     -11.69mA   -10.49mA   -11.59mA
-833.4mV  -9.461mA   -8.485mA   -9.319mA
-595.8mV  -8.29mA    -7.398mA   -8.185mA
-450mV    -6.873mA   -6.24mA    -6.754mA
1.364V    21.03mA    19.25mA    20.69mA
1.867V    28.33mA    25.58mA    28.18mA
2.115V    31.9mA     29.48mA    31.69mA
2.272V    34.56mA    31.81mA    33.89mA
2.547V    39.34mA    35.45mA    38.67mA
2.968V    45.65mA    39.9mA     45.36mA
3.238V    49.33mA    41.75mA    49.33mA
3.6V      53.58mA    43.11mA    54.33mA
[GND Clamp]
|   Voltage   I(typ)   I(min)   I(max)
-1.8V     -58.72mA   -51.23mA   -68.24mA
-1.271V   -30.69mA   -27.39mA   -35.46mA
-1.098V   -22.1mA    -20.06mA   -25.47mA
-952.2mV  -15.37mA   -14.29mA   -17.66mA
-822.6mV  -10.14mA   -9.655mA   -11.8mA
-671.4mV  -5.164mA   -5.19mA    -5.873mA
-563.4mV  -2.202mA   -2.714mA   -2.268mA
-487.8mV  -770.8uA   -1.357mA   -614.2uA
-439.2mV  -272.6uA   -734.7uA   -140.2uA
-369mV    -35.98uA   -217.8uA   -8.946uA
-255.6mV  -694.8nA   -16.48uA   -114.5nA
3.6V      0A         0A         0A
[Pullup]
|   Voltage   I(typ)   I(min)   I(max)
-1.8V     10.49mA    9.352mA    10.39mA
-887.4mV  8.355mA    7.456mA    8.208mA
-628.2mV  7.337mA    6.463mA    7.237mA
-358.2mV  5.298mA    4.645mA    5.299mA
1.213V    -18.38mA   -16.29mA   -18.34mA
1.98V     -29.38mA   -25.09mA   -29.92mA
2.201V    -32.36mA   -28.93mA   -33.03mA
2.444V    -36.98mA   -32.19mA   -36.49mA
2.628V    -39.89mA   -34.34mA   -40.12mA
2.957V    -44.7mA    -37.45mA   -45.26mA
3.217V    -48.13mA   -39.15mA   -49.1mA
3.6V      -52.54mA   -40.6mA    -54.37mA
[POWER Clamp]
|   Voltage   I(typ)   I(min)   I(max)
-1.8V     85.65mA    74.47mA    98.51mA
-1.287V   43.92mA    39.26mA    50.24mA
-1.13V    31.96mA    29.2mA     36.42mA
-1.006V   23.2mA     21.73mA    26.43mA
-892.8mV  16.49mA    15.59mA    19.51mA
-736.2mV  10.27mA    9.092mA    12.63mA
-595.8mV  5.806mA    5.297mA    7.095mA
-450mV    2.033mA    2.29mA     2.335mA
-390.6mV  942uA      1.376mA    958.1uA
-315mV    199.5uA    531.1uA    119.8uA
-147.6mV  837.1nA    14.06uA    186.1nA
3.6V      0A         0A         0A
[Ramp]
R_load = 150
|   typ   min   max
dV/dt_r   0.749875/5.6972e-10   0.652666/6.3674e-10   0.823341/5.6529e-10
dV/dt_f   0.754114/4.78568e-10   0.663357/5.30897e-10   0.824007/5.18626e-10
[Falling Waveform]
V_fixture = 1.8V
V_fixture_min = 1.62V
V_fixture_max = 1.98V
R_fixture = 150Ohm
C_fixture = 0F
|   Time   V(typ)   V(min)   V(max)
0s        1.8V       1.619V     1.98V
895ps     1.801V     1.62V      1.977V
1.155ns   1.799V     1.62V      1.21V
1.4ns     1.144V     1.624V     921.9mV
1.71ns    804.3mV    1.62V      825.3mV
2.015ns   726.9mV    1.049V     731mV
2.255ns   661.4mV    801.9mV    690mV
2.97ns    583.1mV    611.7mV    638.4mV
3.71ns    560.6mV    547.8mV    620.8mV
10ns      542.9mV    513.9mV    606.5mV
[Rising Waveform]
V_fixture = 0V
V_fixture_min = 0V
V_fixture_max = 0V
R_fixture = 150Ohm
C_fixture = 0F
|   Time   V(typ)   V(min)   V(max)
0s        289.8uV    640.8uV    196.2uV
965ps     -1.093mV   504.4uV    1.01mV
1.135ns   -3.178mV   563.1uV    615.2mV
1.26ns    -2.425mV   76.63uV    869.1mV
1.61ns    836.1mV    -4.644mV   1.099V
1.935ns   1.006V     18.61mV    1.224V
2.225ns   1.11V      609.9mV    1.279V
2.49ns    1.16V      820.3mV    1.307V
3.6ns     1.227V     1.04V      1.354V
10ns      1.25V      1.088V     1.372V
[Rising Waveform]
V_fixture = 1.8V
V_fixture_min = 1.62V
V_fixture_max = 1.98V
R_fixture = 150Ohm
C_fixture = 0F
|   Time   V(typ)   V(min)   V(max)
0s        542.9mV    513.9mV    606.5mV
945ps     542.6mV    513.7mV    627.4mV
1.125ns   565.8mV    513.7mV    1.177V
1.265ns   716.8mV    513.4mV    1.419V
1.405ns   1.107V     516.1mV    1.576V
1.59ns    1.369V     569.2mV    1.718V
2.18ns    1.681V     1.24V      1.891V
2.645ns   1.747V     1.485V     1.943V
3.475ns   1.786V     1.586V     1.972V
10ns      1.8V       1.619V     1.98V
[Falling Waveform]
|Gnd
V_fixture = 0V
V_fixture_min = 0V
V_fixture_max = 0V
R_fixture = 150Ohm
C_fixture = 0F
|   Time   V(typ)   V(min)   V(max)
0s        1.25V      1.088V     1.372V
835ps     1.25V      1.089V     1.351V
1.025ns   1.227V     1.089V     823.5mV
1.15ns    1.084V     1.089V     601.2mV
1.285ns   697.2mV    1.087V     437.4mV
1.44ns    473.4mV    1.053V     304.8mV
2.035ns   116.7mV    344.3mV    92.45mV
2.555ns   53.29mV    104.5mV    42.48mV
3.31ns    21.44mV    37.59mV    17.01mV
10ns      290.8uV    641uV      196.1uV
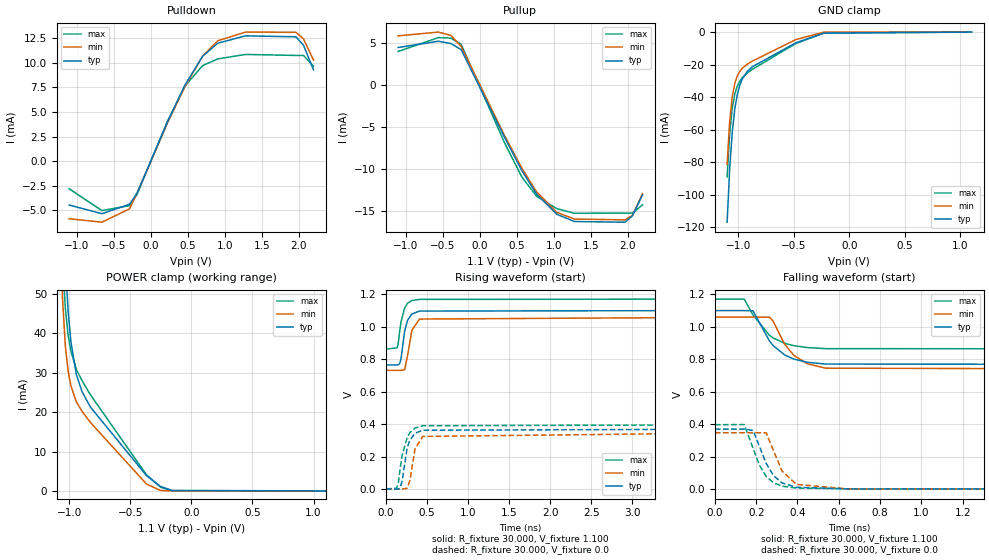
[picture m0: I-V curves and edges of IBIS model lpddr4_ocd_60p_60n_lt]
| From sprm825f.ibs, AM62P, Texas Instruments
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|   Model lpddr4_ocd_60p_60n_lt
[Model] lpddr4_ocd_60p_60n_lt
Model_type I/O
Polarity   Non-Inverting
Enable   Active-High
Vinl =  0.113V
Vinh =  0.253V
Vmeas =  0.183V
C_comp   2.344pF   2.143pF   2.405pF
[Model Spec]
Vinh   0.253V   0.247V   0.265V
Vinl   0.113V   0.107V   0.125V
Vmeas   0.183V   0.176V   0.195V
[Temperature Range]   25.000   -40.000   -40.000
[Voltage Range]   1.100V   1.060V   1.170V
[Pullup Reference]   1.100V   1.060V   1.170V
[Pulldown Reference]   0.0V   0.0V   0.0V
[C Comp Corner]
C_comp   2.344pF   2.143pF   2.405pF
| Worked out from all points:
|   slope of the pulldown table from 0 to 0.165 V, typ, clamps not added: 56.6 ohm
|   slope of the pullup table from 0 to 0.165 V, typ, clamps not added: 52.9 ohm
|   GND clamp passes 1 mA (typ) near -0.26 V on its own axis
|   POWER clamp passes 1 mA (typ) near -0.24 V on its own axis
|   rising waveform, R_fixture 30.000, V_fixture 1.100: 20-80 % time 67.5ps typ, 70.8ps min, 66.5ps max; typ from 0.765 V to 1.1 V
|   rising waveform, R_fixture 30.000, V_fixture 0.0: 20-80 % time 82.2ps typ, 81.1ps min, 96.3ps max; typ from 0.001 V to 0.37 V
|   falling waveform, R_fixture 30.000, V_fixture 1.100: 20-80 % time 118ps typ, 113ps min, 122ps max; typ from 1.1 V to 0.765 V
|   falling waveform, R_fixture 30.000, V_fixture 0.0: 20-80 % time 82.8ps typ, 75.5ps min, 78.2ps max; typ from 0.37 V to 0.001 V
[Pulldown]
|Voltage   I(typ)   I(min)   I(max)
-1.1V     -4.446mA   -5.832mA   -2.793mA
-658mV    -5.323mA   -6.187mA   -5.008mA
-284mV    -4.362mA   -4.83mA    -4.507mA
-181mV    -3.211mA   -3.196mA   -3.341mA
227mV     3.978mA    3.867mA    4.045mA
465mV     7.753mA    7.608mA    7.634mA
703mV     10.66mA    10.67mA    9.708mA
907mV     11.98mA    12.23mA    10.39mA
1.281V    12.73mA    13.11mA    10.84mA
1.962V    12.63mA    13.09mA    10.74mA
2.064V    11.79mA    12.42mA    10.74mA
2.2V      9.269mA    10.27mA    9.64mA
[Pullup]
|Voltage   I(typ)   I(min)   I(max)
-1.1V     4.437mA    5.825mA    3.961mA
-556mV    5.183mA    6.272mA    5.618mA
-386mV    4.908mA    5.867mA    5.553mA
-249mV    4.183mA    4.566mA    4.815mA
329mV     -6.125mA   -5.908mA   -6.761mA
567mV     -10.18mA   -9.883mA   -10.94mA
771mV     -13.04mA   -12.78mA   -13.3mA
1.043V    -15.43mA   -15.19mA   -14.76mA
1.281V    -16.29mA   -16mA      -15.31mA
1.962V    -16.37mA   -16.09mA   -15.29mA
2.064V    -15.61mA   -15.55mA   -15.29mA
2.2V      -13.11mA   -12.97mA   -14.31mA
[GND_clamp]
|Voltage   I(typ)   I(min)   I(max)
-1.1V     -116.8mA   -81.18mA   -88.94mA
-1.077V   -83.96mA   -55.01mA   -62.39mA
-1.054V   -61.6mA    -39.81mA   -46.82mA
-1.031V   -47.19mA   -31.46mA   -38.11mA
-1.008V   -38.16mA   -26.8mA    -33.12mA
-985mV    -32.43mA   -23.99mA   -30.04mA
-962mV    -28.65mA   -22.13mA   -27.95mA
-917mV    -24.03mA   -19.66mA   -25.07mA
-871mV    -21.2mA    -17.79mA   -22.81mA
-481mV    -6.583mA   -4.567mA   -6.994mA
-229mV    -598.8uA   -45.01uA   -573.1uA
1.1V      0A         0A         0A
[POWER_clamp]
|Voltage   I(typ)   I(min)   I(max)
-1.1V     158.5mA    112mA      122.8mA
-1.054V   78.43mA    48.88mA    58.82mA
-1.031V   58.13mA    36.84mA    46.37mA
-1.008V   45.61mA    30.38mA    39.54mA
-985mV    37.81mA    26.62mA    35.43mA
-940mV    29.44mA    22.56mA    30.8mA
-894mV    25.17mA    20.2mA     27.97mA
-825mV    21.26mA    17.35mA    24.37mA
-367mV    3.904mA    1.752mA    4.09mA
-252mV    1.127mA    118.9uA    960.8uA
-160mV    128.1uA    2.957uA    54.27uA
1.1V      0A         0A         0A
[Ramp]
| variable   typ   min   max
dV/dt_r   0.222/82.037p   0.210/81.160p   0.238/96.254p
dV/dt_f   0.201/0.118n   0.197/0.113n   0.185/0.122n
R_load = 30.000
[Rising Waveform]
R_fixture= 30.000
V_fixture= 1.100
V_fixture_min= 1.060
V_fixture_max= 1.170
|time   V(typ)   V(min)   V(max)
0s        764.9mV    731.4mV    861.9mV
136ps     764.3mV    731.4mV    869.9mV
149ps     765.6mV    731.4mV    892.8mV
170ps     774.7mV    731.4mV    980.9mV
185ps     805.5mV    731.2mV    1.031V
228ps     973.1mV    735.5mV    1.115V
265ps     1.041V     825.3mV    1.145V
316ps     1.078V     977.7mV    1.161V
409ps     1.096V     1.047V     1.168V
5ns       1.1V       1.06V      1.17V
[Rising Waveform]
R_fixture= 30.000
V_fixture= 0.0
V_fixture_min= 0.0
V_fixture_max= 0.0
|time   V(typ)   V(min)   V(max)
0s        840.1uV    56.39uV    1.786mV
130ps     803uV      55.73uV    5.934mV
153ps     1.087mV    57.47uV    43.93mV
175ps     12.86mV    55.26uV    132.8mV
198ps     50.73mV    96.17uV    209.2mV
258ps     253.2mV    5.765mV    316.8mV
291ps     300.9mV    50.83mV    346.8mV
355ps     344.4mV    248.7mV    376.2mV
448ps     362.8mV    324.5mV    390.4mV
5ns       370.4mV    350.1mV    397.6mV
[Falling Waveform]
R_fixture= 30.000
V_fixture= 1.100
V_fixture_min= 1.060
V_fixture_max= 1.170
|time   V(typ)   V(min)   V(max)
0s        1.1V       1.06V      1.17V
142ps     1.1V       1.06V      1.171V
184ps     1.099V     1.06V      1.074V
265ps     911.4mV    1.059V     946.5mV
282ps     884.9mV    1.035V     931.5mV
337ps     827.4mV    894.3mV    898.9mV
382ps     801.4mV    824.6mV    884mV
447ps     781.7mV    772.9mV    872.3mV
536ps     770.7mV    745.2mV    865.7mV
5ns       764.9mV    731.4mV    861.9mV
[Falling Waveform]
R_fixture= 30.000
V_fixture= 0.0
V_fixture_min= 0.0
V_fixture_max= 0.0
|time   V(typ)   V(min)   V(max)
0s        369.9mV    347.7mV    397.2mV
142ps     369.8mV    347.7mV    397.9mV
185ps     361.8mV    347.7mV    251.3mV
216ps     262.8mV    347.7mV    146.6mV
248ps     159.8mV    347.2mV    79.01mV
284ps     83.07mV    237.3mV    39.42mV
325ps     38.59mV    111.8mV    18.69mV
395ps     11.56mV    29.11mV    6.622mV
651ps     1.609mV    963.8uV    2.219mV
5ns       839.5uV    56.18uV    1.787mV
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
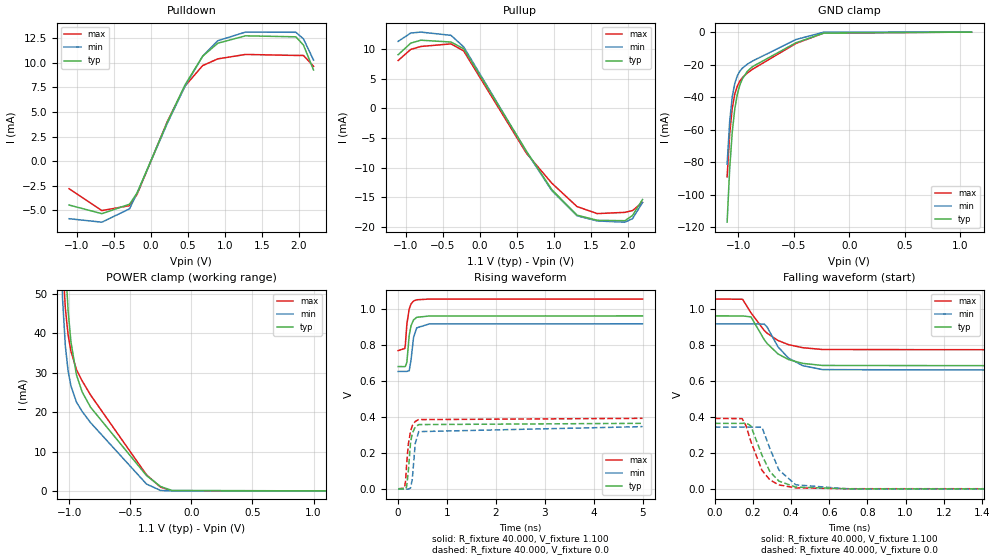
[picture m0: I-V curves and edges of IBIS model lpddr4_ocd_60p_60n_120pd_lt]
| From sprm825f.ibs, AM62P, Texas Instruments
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|   Model lpddr4_ocd_60p_60n_120pd
[Model] lpddr4_ocd_60p_60n_120pd_lt
Model_type I/O
Polarity   Non-Inverting
Enable   Active-High
Vinl =  0.113V
Vinh =  0.253V
Vmeas =  0.183V
C_comp   2.248pF   2.075pF   2.320pF
[Model Spec]
Vinh   0.253V   0.247V   0.265V
Vinl   0.113V   0.107V   0.125V
Vmeas   0.183V   0.176V   0.195V
[Temperature Range]   25.000   -40.000   -40.000
[Voltage Range]   1.100V   1.060V   1.170V
[Pullup Reference]   1.100V   1.060V   1.170V
[Pulldown Reference]   0.0V   0.0V   0.0V
[C Comp Corner]
C_comp   2.248pF   2.075pF   2.320pF
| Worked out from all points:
|   slope of the pulldown table from 0 to 0.165 V, typ, clamps not added: 56.6 ohm
|   slope of the pullup table from 0 to 0.165 V, typ, clamps not added: 49.8 ohm
|   GND clamp passes 1 mA (typ) near -0.26 V on its own axis
|   POWER clamp passes 1 mA (typ) near -0.24 V on its own axis
|   rising waveform, R_fixture 40.000, V_fixture 1.100: 20-80 % time 71.6ps typ, 74.6ps min, 70.4ps max; typ from 0.682 V to 0.963 V
|   rising waveform, R_fixture 40.000, V_fixture 0.0: 20-80 % time 72.3ps typ, 71.1ps min, 86.2ps max; typ from 0.001 V to 0.366 V
|   falling waveform, R_fixture 40.000, V_fixture 1.100: 20-80 % time 135ps typ, 126ps min, 150ps max; typ from 0.963 V to 0.682 V
|   falling waveform, R_fixture 40.000, V_fixture 0.0: 20-80 % time 92.7ps typ, 87.8ps min, 87.6ps max; typ from 0.366 V to 0.001 V
[Pulldown]
|Voltage   I(typ)   I(min)   I(max)
-1.1V     -4.446mA   -5.832mA   -2.793mA
-658mV    -5.323mA   -6.187mA   -5.008mA
-284mV    -4.362mA   -4.83mA    -4.507mA
-181mV    -3.211mA   -3.196mA   -3.341mA
227mV     3.978mA    3.867mA    4.045mA
465mV     7.753mA    7.608mA    7.634mA
703mV     10.66mA    10.67mA    9.708mA
907mV     11.98mA    12.23mA    10.39mA
1.281V    12.73mA    13.11mA    10.84mA
1.962V    12.63mA    13.09mA    10.74mA
2.064V    11.79mA    12.42mA    10.74mA
2.2V      9.269mA    10.27mA    9.64mA
[Pullup]
|Voltage   I(typ)   I(min)   I(max)
-1.1V     9.064mA    11.32mA    8.089mA
-930mV    11.02mA    12.73mA    9.963mA
-794mV    11.52mA    12.89mA    10.46mA
-386mV    11.21mA    12.34mA    10.9mA
-215mV    10.08mA    10.4mA     9.714mA
635mV     -7.266mA   -7.348mA   -7.62mA
975mV     -13.71mA   -13.89mA   -12.62mA
1.315V    -18.02mA   -18.13mA   -16.57mA
1.588V    -18.89mA   -19mA      -17.76mA
1.962V    -18.96mA   -19.21mA   -17.55mA
2.064V    -18.09mA   -18.62mA   -17.25mA
2.2V      -15.37mA   -15.9mA    -15.87mA
[GND_clamp]
|Voltage   I(typ)   I(min)   I(max)
-1.1V     -116.8mA   -81.18mA   -88.94mA
-1.077V   -83.96mA   -55.01mA   -62.39mA
-1.054V   -61.6mA    -39.81mA   -46.82mA
-1.031V   -47.19mA   -31.46mA   -38.11mA
-1.008V   -38.16mA   -26.8mA    -33.12mA
-985mV    -32.43mA   -23.99mA   -30.04mA
-962mV    -28.65mA   -22.13mA   -27.95mA
-917mV    -24.03mA   -19.66mA   -25.07mA
-871mV    -21.2mA    -17.79mA   -22.81mA
-481mV    -6.583mA   -4.567mA   -6.994mA
-229mV    -598.7uA   -45.02uA   -573.1uA
1.1V      0A         0A         0A
[POWER_clamp]
|Voltage   I(typ)   I(min)   I(max)
-1.1V     158.5mA    112mA      122.8mA
-1.054V   78.43mA    48.88mA    58.82mA
-1.031V   58.13mA    36.84mA    46.37mA
-1.008V   45.61mA    30.38mA    39.54mA
-985mV    37.81mA    26.62mA    35.43mA
-940mV    29.44mA    22.56mA    30.8mA
-894mV    25.17mA    20.2mA     27.97mA
-825mV    21.26mA    17.35mA    24.37mA
-367mV    3.904mA    1.752mA    4.09mA
-252mV    1.127mA    118.9uA    960.8uA
-160mV    128.1uA    2.957uA    54.27uA
1.1V      0A         0A         0A
[Ramp]
| variable   typ   min   max
dV/dt_r   0.219/72.259p   0.209/71.224p   0.235/86.126p
dV/dt_f   0.169/0.135n   0.159/0.126n   0.172/0.150n
R_load = 40.000
[Rising Waveform]
R_fixture= 40.000
V_fixture= 1.100
V_fixture_min= 1.060
V_fixture_max= 1.170
|time   V(typ)   V(min)   V(max)
0s        681.9mV    654.7mV    770.5mV
137ps     681.4mV    654.7mV    782.4mV
149ps     682.7mV    654.7mV    806mV
179ps     706.1mV    654.7mV    918.1mV
227ps     856mV      658.4mV    1.002V
265ps     909.7mV    720.2mV    1.03V
315ps     940.7mV    843.1mV    1.046V
380ps     955.6mV    897mV      1.053V
637ps     962.9mV    918.7mV    1.057V
5ns       963.4mV    919.4mV    1.057V
[Rising Waveform]
R_fixture= 40.000
V_fixture= 0.0
V_fixture_min= 0.0
V_fixture_max= 0.0
|time   V(typ)   V(min)   V(max)
0s        1.002mV    66.58uV    2.128mV
129ps     967.8uV    65.84uV    5.958mV
152ps     1.194mV    67.55uV    45.36mV
173ps     12.36mV    65.3uV     134.7mV
208ps     96.57mV    97.91uV    248.3mV
255ps     261mV      7.022mV    324mV
290ps     310.2mV    55.14mV    353.1mV
350ps     346.1mV    253.4mV    376.8mV
421ps     359.1mV    320mV      386.8mV
5ns       366.2mV    347.8mV    393.9mV
[Falling Waveform]
R_fixture= 40.000
V_fixture= 1.100
V_fixture_min= 1.060
V_fixture_max= 1.170
|time   V(typ)   V(min)   V(max)
0s        963.4mV    919.1mV    1.057V
145ps     963.3mV    919.1mV    1.056V
189ps     958mV      919.1mV    981.1mV
259ps     831mV      917.9mV    882mV
274ps     809.8mV    901.2mV    867.2mV
331ps     752mV      791mV      826.6mV
386ps     720.8mV    728.8mV    803.5mV
461ps     699.3mV    686.6mV    786.5mV
565ps     687.9mV    664.7mV    776.5mV
5ns       681.9mV    654.7mV    770.5mV
[Falling Waveform]
R_fixture= 40.000
V_fixture= 0.0
V_fixture_min= 0.0
V_fixture_max= 0.0
|time   V(typ)   V(min)   V(max)
0s        365.8mV    345.3mV    393.5mV
143ps     365.6mV    345.3mV    392.1mV
163ps     368.4mV    345.3mV    352.8mV
188ps     352.7mV    345.3mV    266.8mV
247ps     188.5mV    344.3mV    104.5mV
289ps     97.01mV    224.5mV    51.02mV
336ps     44.61mV    106.6mV    23.7mV
424ps     11.64mV    24.26mV    7.329mV
705ps     1.777mV    953.6uV    2.553mV
5ns       1.002mV    66.34uV    2.129mV
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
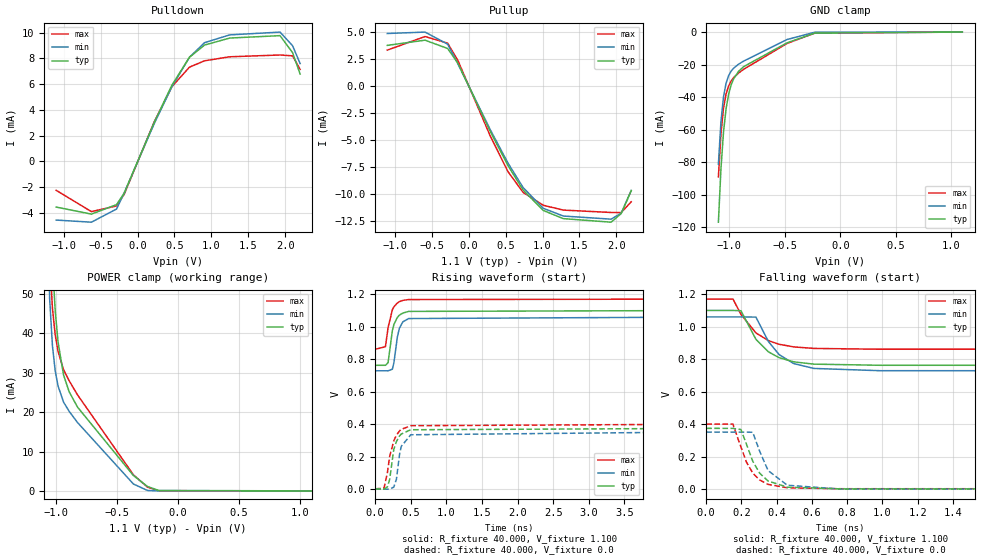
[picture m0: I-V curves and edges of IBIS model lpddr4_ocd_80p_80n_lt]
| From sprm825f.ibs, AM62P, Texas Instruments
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|   Model lpddr4_ocd_80p_80n_lt
[Model] lpddr4_ocd_80p_80n_lt
Model_type I/O
Polarity   Non-Inverting
Enable   Active-High
Vinl =  0.113V
Vinh =  0.253V
Vmeas =  0.183V
C_comp   2.560pF   2.357pF   2.583pF
[Model Spec]
Vinh   0.253V   0.247V   0.265V
Vinl   0.113V   0.107V   0.125V
Vmeas   0.183V   0.176V   0.195V
[Temperature Range]   25.000   -40.000   -40.000
[Voltage Range]   1.100V   1.060V   1.170V
[Pullup Reference]   1.100V   1.060V   1.170V
[Pulldown Reference]   0.0V   0.0V   0.0V
[C Comp Corner]
C_comp   2.560pF   2.357pF   2.583pF
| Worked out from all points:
|   slope of the pulldown table from 0 to 0.165 V, typ, clamps not added: 73.9 ohm
|   slope of the pullup table from 0 to 0.165 V, typ, clamps not added: 69 ohm
|   GND clamp passes 1 mA (typ) near -0.26 V on its own axis
|   POWER clamp passes 1 mA (typ) near -0.24 V on its own axis
|   rising waveform, R_fixture 40.000, V_fixture 1.100: 20-80 % time 79ps typ, 73.8ps min, 83.4ps max; typ from 0.762 V to 1.1 V
|   rising waveform, R_fixture 40.000, V_fixture 0.0: 20-80 % time 96.6ps typ, 82.8ps min, 118ps max; typ from 0.001 V to 0.375 V
|   falling waveform, R_fixture 40.000, V_fixture 1.100: 20-80 % time 148ps typ, 141ps min, 154ps max; typ from 1.1 V to 0.762 V
|   falling waveform, R_fixture 40.000, V_fixture 0.0: 20-80 % time 100ps typ, 94ps min, 96.9ps max; typ from 0.374 V to 0.001 V
[Pulldown]
|Voltage   I(typ)   I(min)   I(max)
-1.1V     -3.54mA    -4.549mA   -2.243mA
-624mV    -4.087mA   -4.713mA   -3.891mA
-284mV    -3.349mA   -3.692mA   -3.451mA
-181mV    -2.465mA   -2.443mA   -2.558mA
227mV     3.047mA    2.952mA    3.088mA
465mV     5.92mA     5.796mA    5.804mA
703mV     8.089mA    8.091mA    7.321mA
907mV     9.034mA    9.219mA    7.812mA
1.247V    9.577mA    9.823mA    8.123mA
1.928V    9.764mA    10.04mA    8.263mA
2.098V    8.441mA    8.98mA     8.195mA
2.2V      6.782mA    7.594mA    7.144mA
[Pullup]
|Voltage   I(typ)   I(min)   I(max)
-1.1V     3.776mA    4.877mA    3.339mA
-590mV    4.258mA    5.007mA    4.595mA
-284mV    3.487mA    3.892mA    3.984mA
-147mV    2.15mA     2.087mA    2.406mA
295mV     -4.224mA   -4.061mA   -4.655mA
533mV     -7.364mA   -7.129mA   -7.922mA
737mV     -9.617mA   -9.391mA   -9.838mA
1.009V    -11.51mA   -11.31mA   -11.03mA
1.281V    -12.27mA   -12.03mA   -11.48mA
1.928V    -12.6mA    -12.32mA   -11.7mA
2.064V    -11.8mA    -11.77mA   -11.71mA
2.2V      -9.689mA   -9.656mA   -10.71mA
[GND_clamp]
|Voltage   I(typ)   I(min)   I(max)
-1.1V     -116.8mA   -81.18mA   -88.94mA
-1.077V   -83.96mA   -55.01mA   -62.39mA
-1.054V   -61.6mA    -39.81mA   -46.82mA
-1.031V   -47.19mA   -31.46mA   -38.11mA
-1.008V   -38.16mA   -26.8mA    -33.12mA
-985mV    -32.43mA   -23.99mA   -30.04mA
-962mV    -28.65mA   -22.13mA   -27.95mA
-917mV    -24.03mA   -19.66mA   -25.07mA
-871mV    -21.2mA    -17.79mA   -22.81mA
-481mV    -6.583mA   -4.567mA   -6.994mA
-229mV    -598.7uA   -45.01uA   -573.1uA
1.1V      0A         0A         0A
[POWER_clamp]
|Voltage   I(typ)   I(min)   I(max)
-1.1V     158.5mA    112mA      122.8mA
-1.054V   78.43mA    48.88mA    58.82mA
-1.031V   58.13mA    36.84mA    46.37mA
-1.008V   45.61mA    30.38mA    39.54mA
-985mV    37.81mA    26.62mA    35.43mA
-940mV    29.44mA    22.56mA    30.8mA
-894mV    25.17mA    20.2mA     27.97mA
-825mV    21.26mA    17.35mA    24.37mA
-367mV    3.904mA    1.752mA    4.09mA
-252mV    1.127mA    118.9uA    960.8uA
-160mV    128.1uA    2.957uA    54.28uA
1.1V      0A         0A         0A
[Ramp]
| variable   typ   min   max
dV/dt_r   0.224/96.443p   0.212/82.237p   0.239/0.118n
dV/dt_f   0.203/0.148n   0.199/0.141n   0.185/0.154n
R_load = 40.000
[Rising Waveform]
R_fixture= 40.000
V_fixture= 1.100
V_fixture_min= 1.060
V_fixture_max= 1.170
|time   V(typ)   V(min)   V(max)
0s        762.3mV    728.7mV    861mV
145ps     762.3mV    728.7mV    876.5mV
182ps     779.1mV    728.5mV    994.3mV
243ps     977.8mV    738.4mV    1.105V
265ps     1.015V     781.1mV    1.123V
312ps     1.057V     935.8mV    1.146V
341ps     1.071V     990.5mV    1.154V
390ps     1.084V     1.03V      1.162V
471ps     1.094V     1.05V      1.167V
5ns       1.1V       1.06V      1.17V
[Rising Waveform]
R_fixture= 40.000
V_fixture= 0.0
V_fixture_min= 0.0
V_fixture_max= 0.0
|time   V(typ)   V(min)   V(max)
0s        1.128mV    71.4uV     2.398mV
125ps     1.1mV      70.96uV    5.56mV
172ps     13.25mV    70.12uV    99.92mV
204ps     59.55mV    66.77uV    201.2mV
262ps     243.8mV    12.59mV    297.3mV
299ps     293.2mV    60.63mV    332.6mV
344ps     328.1mV    216.1mV    359.1mV
367ps     339.4mV    263.1mV    367.9mV
500ps     365.7mV    334.8mV    390.6mV
5ns       374.9mV    353.7mV    400.5mV
[Falling Waveform]
R_fixture= 40.000
V_fixture= 1.100
V_fixture_min= 1.060
V_fixture_max= 1.170
|time   V(typ)   V(min)   V(max)
0s        1.1V       1.06V      1.17V
152ps     1.1V       1.06V      1.17V
197ps     1.098V     1.06V      1.076V
282ps     922.5mV    1.059V     961.6mV
353ps     845.1mV    908.4mV    914.1mV
414ps     809mV      827.8mV    891.6mV
497ps     783.6mV    772.7mV    875.5mV
611ps     769.5mV    743.1mV    866.2mV
987ps     762.5mV    729.1mV    861.2mV
5ns       762.3mV    728.7mV    861mV
[Falling Waveform]
R_fixture= 40.000
V_fixture= 0.0
V_fixture_min= 0.0
V_fixture_max= 0.0
|time   V(typ)   V(min)   V(max)
0s        374.4mV    351.2mV    400.1mV
151ps     374.2mV    351.2mV    401mV
197ps     367.2mV    351.1mV    259.7mV
229ps     275.1mV    351mV      164.9mV
264ps     172.6mV    350.2mV    99.13mV
303ps     98.77mV    234.3mV    56.87mV
351ps     50.43mV    114.6mV    29.44mV
460ps     12.32mV    24.25mV    8.35mV
761ps     1.909mV    864.5uV    2.809mV
5ns       1.127mV    71.41uV    2.399mV
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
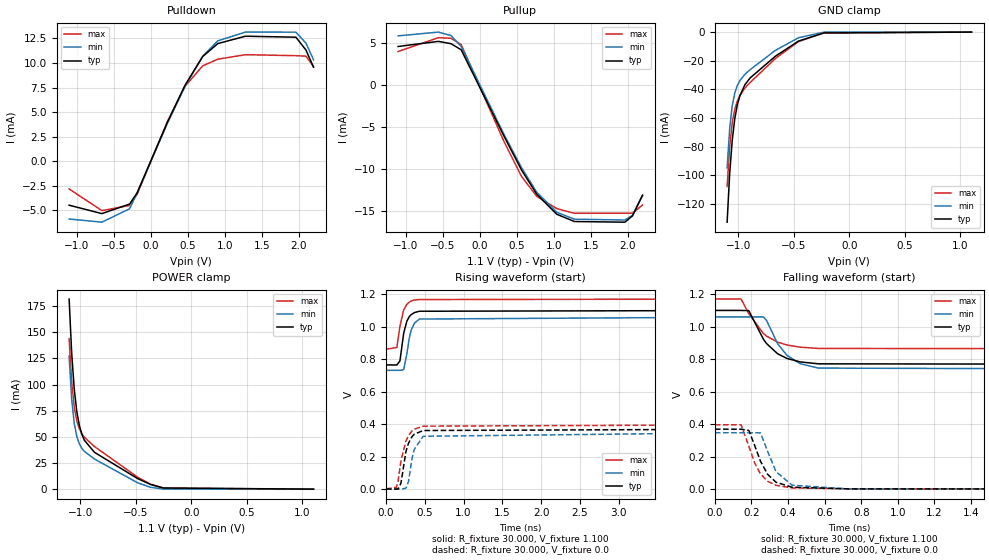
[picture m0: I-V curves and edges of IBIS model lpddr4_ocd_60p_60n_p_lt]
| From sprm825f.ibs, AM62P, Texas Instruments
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|   Model lpddr4_ocd_60p_60n_p_lt
[Model] lpddr4_ocd_60p_60n_p_lt
Model_type I/O
Polarity   Non-Inverting
Enable   Active-High
Vinl =  0.113V
Vinh =  0.253V
Vmeas =  0.183V
C_comp   2.659pF   2.485pF   2.734pF
C_comp_pullup   0.232pF   0.222pF   0.242pF
C_comp_pulldown   1.079pF   1.003pF   1.105pF
[Model Spec]
Vinh   0.253V   0.247V   0.265V
Vinl   0.113V   0.107V   0.125V
Vmeas   0.183V   0.176V   0.195V
[Temperature Range]   25.000   -40.000   -40.000
[Voltage Range]   1.100V   1.060V   1.170V
[Pullup Reference]   1.100V   1.060V   1.170V
[Pulldown Reference]   0.0V   0.0V   0.0V
[C Comp Corner]
C_comp_pullup   0.232pF   0.222pF   0.242pF
C_comp_pulldown   1.079pF   1.003pF   1.105pF
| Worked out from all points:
|   slope of the pulldown table from 0 to 0.165 V, typ, clamps not added: 56.7 ohm
|   slope of the pullup table from 0 to 0.165 V, typ, clamps not added: 53.1 ohm
|   GND clamp passes 1 mA (typ) near -0.26 V on its own axis
|   POWER clamp passes 1 mA (typ) near -0.24 V on its own axis
|   rising waveform, R_fixture 30.000, V_fixture 1.100: 20-80 % time 75.6ps typ, 78.8ps min, 74.4ps max; typ from 0.765 V to 1.1 V
|   rising waveform, R_fixture 30.000, V_fixture 0.0: 20-80 % time 95.6ps typ, 95.6ps min, 111ps max; typ from 0.001 V to 0.37 V
|   falling waveform, R_fixture 30.000, V_fixture 1.100: 20-80 % time 130ps typ, 124ps min, 135ps max; typ from 1.1 V to 0.765 V
|   falling waveform, R_fixture 30.000, V_fixture 0.0: 20-80 % time 90.8ps typ, 83.3ps min, 86.5ps max; typ from 0.369 V to 0.001 V
[Pulldown]
|Voltage   I(typ)   I(min)   I(max)
-1.1V     -4.465mA   -5.868mA   -2.813mA
-658mV    -5.322mA   -6.195mA   -5.016mA
-284mV    -4.35mA    -4.83mA    -4.5mA
-181mV    -3.204mA   -3.197mA   -3.337mA
227mV     3.972mA    3.87mA     4.042mA
465mV     7.743mA    7.616mA    7.631mA
703mV     10.66mA    10.69mA    9.709mA
907mV     11.98mA    12.26mA    10.39mA
1.281V    12.73mA    13.15mA    10.85mA
1.962V    12.63mA    13.14mA    10.75mA
2.098V    11.32mA    12.02mA    10.7mA
2.2V      9.575mA    10.33mA    9.654mA
[Pullup]
|Voltage   I(typ)   I(min)   I(max)
-1.1V     4.549mA    5.812mA    3.953mA
-556mV    5.158mA    6.261mA    5.598mA
-386mV    4.881mA    5.848mA    5.525mA
-249mV    4.161mA    4.556mA    4.791mA
329mV     -6.101mA   -5.897mA   -6.734mA
567mV     -10.14mA   -9.865mA   -10.9mA
771mV     -13mA      -12.76mA   -13.25mA
1.043V    -15.39mA   -15.16mA   -14.72mA
1.281V    -16.25mA   -15.97mA   -15.27mA
1.962V    -16.33mA   -16.07mA   -15.26mA
2.064V    -15.58mA   -15.53mA   -15.26mA
2.2V      -13.15mA   -13.09mA   -14.29mA
[GND_clamp]
|Voltage   I(typ)   I(min)   I(max)
-1.1V     -132.9mA   -94.96mA   -107.9mA
-1.077V   -98.86mA   -67.55mA   -79.9mA
-1.054V   -75.63mA   -51.54mA   -63.35mA
-1.031V   -60.5mA    -42.53mA   -53.84mA
-1.008V   -50.81mA   -37.28mA   -48.11mA
-985mV    -44.46mA   -33.89mA   -44.3mA
-940mV    -36.83mA   -29.52mA   -39.19mA
-894mV    -32.12mA   -26.33mA   -35.3mA
-665mV    -16.86mA   -12.76mA   -18.45mA
-458mV    -6.31mA    -3.966mA   -6.61mA
-229mV    -598.2uA   -44.98uA   -572.8uA
1.1V      0A         0A         0A
[POWER_clamp]
|Voltage   I(typ)   I(min)   I(max)
-1.1V     181.7mA    127.2mA    143.9mA
-1.077V   130mA      86.12mA    102.2mA
-1.054V   95.89mA    62.98mA    78.5mA
-1.031V   74.31mA    50.37mA    65.32mA
-1.008V   60.91mA    43.33mA    57.78mA
-985mV    52.38mA    38.99mA    52.94mA
-963mV    46.75mA    36.06mA    49.58mA
-871mV    35.15mA    28.73mA    40.66mA
-481mV    10mA       5.972mA    11.31mA
-367mV    4.507mA    1.8mA      4.728mA
-252mV    1.151mA    119.1uA    969.3uA
1.1V      0A         0A         0A
[Ramp]
| variable   typ   min   max
dV/dt_r   0.224/66.061p   0.213/75.699p   0.245/67.594p
dV/dt_f   0.224/0.129n   0.212/0.104n   0.245/0.137n
R_load = 30.000
[Rising Waveform]
R_fixture= 30.000
V_fixture= 1.100
V_fixture_min= 1.060
V_fixture_max= 1.170
|time   V(typ)   V(min)   V(max)
0s        764.7mV    731.4mV    861.3mV
141ps     764.3mV    731.4mV    871.7mV
181ps     789.7mV    731.3mV    1.003V
229ps     960.1mV    735.1mV    1.103V
270ps     1.034V     831.7mV    1.138V
300ps     1.061V     927.3mV    1.151V
325ps     1.074V     977.9mV    1.158V
369ps     1.087V     1.023V     1.164V
433ps     1.095V     1.047V     1.167V
5ns       1.1V       1.06V      1.17V
[Rising Waveform]
R_fixture= 30.000
V_fixture= 0.0
V_fixture_min= 0.0
V_fixture_max= 0.0
|time   V(typ)   V(min)   V(max)
0s        839uV      56.48uV    1.781mV
136ps     805.9uV    55.59uV    11.99mV
157ps     1.959mV    56.5uV     50.07mV
194ps     36.91mV    59.25uV    173.8mV
258ps     230.9mV    6.113mV    296.2mV
291ps     282.7mV    46.36mV    330mV
336ps     323mV      187.8mV    357.9mV
366ps     338.3mV    245.2mV    369.2mV
480ps     361mV      325.6mV    387.8mV
5ns       369.5mV    349.5mV    396.5mV
[Falling Waveform]
R_fixture= 30.000
V_fixture= 1.100
V_fixture_min= 1.060
V_fixture_max= 1.170
|time   V(typ)   V(min)   V(max)
0s        1.1V       1.06V      1.17V
143ps     1.1V       1.06V      1.17V
185ps     1.099V     1.06V      1.081V
266ps     921.5mV    1.06V      956.7mV
283ps     895.5mV    1.037V     941.5mV
343ps     833.4mV    895.2mV    904.8mV
394ps     804.5mV    823.3mV    887.3mV
466ps     783.3mV    772.3mV    874mV
566ps     771.4mV    745.1mV    866.1mV
5ns       764.7mV    731.4mV    861.3mV
[Falling Waveform]
R_fixture= 30.000
V_fixture= 0.0
V_fixture_min= 0.0
V_fixture_max= 0.0
|time   V(typ)   V(min)   V(max)
0s        369.2mV    347mV      396.4mV
143ps     369.1mV    347.1mV    396.4mV
186ps     361mV      347mV      263mV
218ps     267.2mV    347.3mV    160.1mV
249ps     172.9mV    346.5mV    94.24mV
288ps     91.63mV    233.8mV    48.65mV
334ps     42.79mV    108.4mV    23.59mV
422ps     11.91mV    24.6mV     7.862mV
735ps     1.732mV    1.086mV    2.283mV
5ns       842.1uV    56.4uV     1.785mV
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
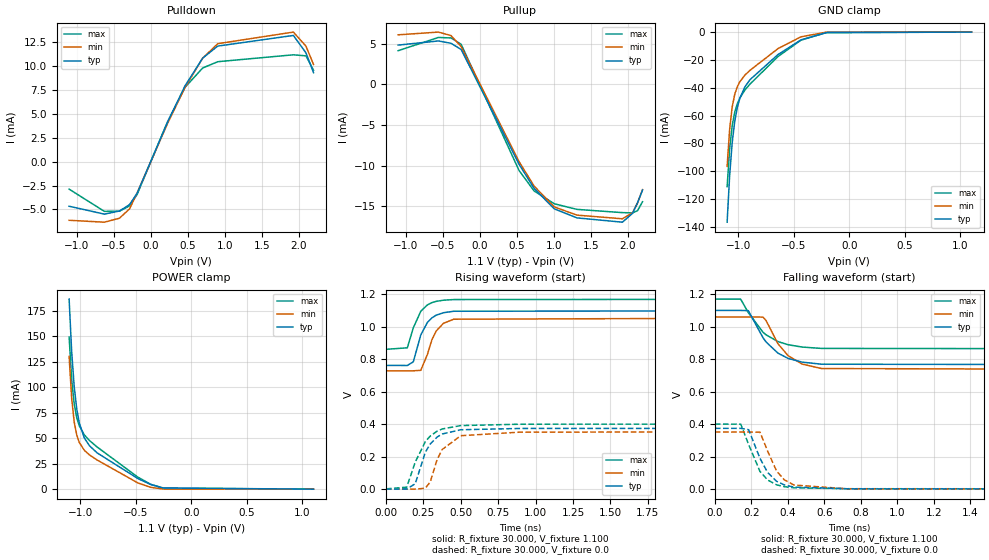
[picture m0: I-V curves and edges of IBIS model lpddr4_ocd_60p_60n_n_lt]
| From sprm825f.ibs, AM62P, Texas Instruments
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|   Model lpddr4_ocd_60p_60n_n_lt
[Model] lpddr4_ocd_60p_60n_n_lt
Model_type I/O
Polarity   Non-Inverting
Enable   Active-High
Vinl =  0.113V
Vinh =  0.253V
Vmeas =  0.183V
C_comp   3.036pF   2.867pF   3.082pF
C_comp_pullup   0.271pF   0.260pF   0.277pF
C_comp_pulldown   1.220pF   1.147pF   1.236pF
[Model Spec]
Vinh   0.253V   0.247V   0.265V
Vinl   0.113V   0.107V   0.125V
Vmeas   0.183V   0.176V   0.195V
[Temperature Range]   25.000   -40.000   -40.000
[Voltage Range]   1.100V   1.060V   1.170V
[Pullup Reference]   1.100V   1.060V   1.170V
[Pulldown Reference]   0.0V   0.0V   0.0V
[C Comp Corner]
C_comp_pullup   0.271pF   0.260pF   0.277pF
C_comp_pulldown   1.220pF   1.147pF   1.236pF
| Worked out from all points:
|   slope of the pulldown table from 0 to 0.165 V, typ, clamps not added: 55.3 ohm
|   slope of the pullup table from 0 to 0.165 V, typ, clamps not added: 51.6 ohm
|   GND clamp passes 1 mA (typ) near -0.26 V on its own axis
|   POWER clamp passes 1 mA (typ) near -0.24 V on its own axis
|   rising waveform, R_fixture 30.000, V_fixture 1.100: 20-80 % time 84.7ps typ, 87.1ps min, 82.2ps max; typ from 0.762 V to 1.1 V
|   rising waveform, R_fixture 30.000, V_fixture 0.0: 20-80 % time 105ps typ, 105ps min, 120ps max; typ from 0.001 V to 0.375 V
|   falling waveform, R_fixture 30.000, V_fixture 1.100: 20-80 % time 141ps typ, 134ps min, 145ps max; typ from 1.1 V to 0.762 V
|   falling waveform, R_fixture 30.000, V_fixture 0.0: 20-80 % time 98.7ps typ, 92.1ps min, 93.8ps max; typ from 0.375 V to 0.001 V
[Pulldown]
|Voltage   I(typ)   I(min)   I(max)
-1.1V     -4.662mA   -6.128mA   -2.879mA
-624mV    -5.487mA   -6.327mA   -5.197mA
-420mV    -5.158mA   -5.912mA   -5.178mA
-284mV    -4.493mA   -4.936mA   -4.625mA
-181mV    -3.295mA   -3.26mA    -3.417mA
227mV     4.067mA    3.939mA    4.121mA
465mV     7.903mA    7.734mA    7.744mA
703mV     10.79mA    10.79mA    9.764mA
907mV     12.05mA    12.3mA     10.42mA
1.928V    13.16mA    13.51mA    11.14mA
2.098V    11.34mA    12.04mA    11.03mA
2.2V      9.276mA    10.13mA    9.525mA
[Pullup]
|Voltage   I(typ)   I(min)   I(max)
-1.1V     4.852mA    6.119mA    4.161mA
-556mV    5.364mA    6.456mA    5.795mA
-386mV    5.075mA    6.024mA    5.732mA
-249mV    4.312mA    4.67mA     4.955mA
533mV     -9.838mA   -9.519mA   -10.61mA
737mV     -12.83mA   -12.54mA   -13.14mA
1.009V    -15.34mA   -15.1mA    -14.71mA
1.315V    -16.45mA   -16.11mA   -15.4mA
1.928V    -16.98mA   -16.56mA   -15.8mA
2.064V    -15.9mA    -15.83mA   -15.83mA
2.132V    -14.61mA   -14.62mA   -15.57mA
2.2V      -13.01mA   -12.97mA   -14.46mA
[GND_clamp]
|Voltage   I(typ)   I(min)   I(max)
-1.1V     -136.6mA   -96.46mA   -111.1mA
-1.077V   -102.6mA   -69.55mA   -83.57mA
-1.054V   -79.22mA   -53.64mA   -67.05mA
-1.031V   -63.93mA   -44.56mA   -57.36mA
-1.008V   -54.04mA   -39.16mA   -51.37mA
-985mV    -47.47mA   -35.61mA   -47.28mA
-940mV    -39.36mA   -30.91mA   -41.63mA
-894mV    -34.19mA   -27.47mA   -37.37mA
-642mV    -16.16mA   -11.85mA   -17.57mA
-435mV    -5.566mA   -3.394mA   -5.8mA
-206mV    -368.5uA   -17.49uA   -340.6uA
1.1V      0A         0A         0A
[POWER_clamp]
|Voltage   I(typ)   I(min)   I(max)
-1.1V     186.7mA    130.4mA    149.4mA
-1.077V   134.7mA    89.1mA     107.4mA
-1.054V   100.3mA    65.79mA    83.44mA
-1.031V   78.51mA    53mA       69.97mA
-1.008V   64.87mA    45.79mA    62.12mA
-963mV    50.23mA    38.14mA    53.29mA
-917mV    42.67mA    33.66mA    47.79mA
-848mV    35.63mA    28.64mA    41.42mA
-481mV    10.42mA    6.123mA    11.78mA
-367mV    4.613mA    1.825mA    4.83mA
-252mV    1.166mA    119.4uA    981uA
1.1V      0A         0A         0A
[Ramp]
| variable   typ   min   max
dV/dt_r   0.236/85.778p   0.222/97.378p   0.256/83.872p
dV/dt_f   0.235/0.167n   0.221/0.141n   0.256/0.177n
R_load = 30.000
[Rising Waveform]
R_fixture= 30.000
V_fixture= 1.100
V_fixture_min= 1.060
V_fixture_max= 1.170
|time   V(typ)   V(min)   V(max)
0s        761.8mV    728.5mV    860.8mV
143ps     761.3mV    728.5mV    869.9mV
183ps     783.5mV    728.4mV    992.7mV
233ps     949.2mV    731.4mV    1.095V
277ps     1.026V     828.7mV    1.134V
307ps     1.054V     919mV      1.148V
336ps     1.071V     973.6mV    1.156V
385ps     1.086V     1.021V     1.163V
453ps     1.095V     1.046V     1.167V
5ns       1.1V       1.06V      1.17V
[Rising Waveform]
R_fixture= 30.000
V_fixture= 0.0
V_fixture_min= 0.0
V_fixture_max= 0.0
|time   V(typ)   V(min)   V(max)
0s        850uV      57.13uV    1.802mV
139ps     802.6uV    56.6uV     12.16mV
196ps     33.56mV    42.98uV    166.9mV
264ps     228.4mV    6.344mV    293.6mV
296ps     277.8mV    44.01mV    326.7mV
342ps     320.9mV    182.4mV    356.9mV
376ps     339.6mV    244.2mV    370.5mV
500ps     365.7mV    329.1mV    391.4mV
898ps     373.7mV    351.1mV    399.9mV
5ns       374.8mV    353.8mV    400.8mV
[Falling Waveform]
R_fixture= 30.000
V_fixture= 1.100
V_fixture_min= 1.060
V_fixture_max= 1.170
|time   V(typ)   V(min)   V(max)
0s        1.1V       1.06V      1.17V
141ps     1.1V       1.06V      1.17V
183ps     1.099V     1.06V      1.087V
264ps     931.6mV    1.059V     965.3mV
281ps     905.4mV    1.037V     949.5mV
345ps     837.7mV    896.1mV    908.8mV
401ps     805mV      821.8mV    889mV
478ps     781.9mV    770mV      874.6mV
584ps     769.1mV    742.5mV    866.3mV
5ns       761.8mV    728.5mV    860.8mV
[Falling Waveform]
R_fixture= 30.000
V_fixture= 0.0
V_fixture_min= 0.0
V_fixture_max= 0.0
|time   V(typ)   V(min)   V(max)
0s        374.5mV    351.7mV    400.8mV
142ps     374.4mV    351.7mV    399.9mV
185ps     365.8mV    351.7mV    274.5mV
247ps     190.2mV    351.2mV    109.6mV
289ps     102.6mV    234.4mV    56.53mV
338ps     48.67mV    112mV      27.03mV
380ps     26.28mV    58.04mV    15.27mV
434ps     12.69mV    25.44mV    8.343mV
737ps     2.085mV    1.449mV    2.804mV
5ns       857.8uV    57.08uV    1.807mV
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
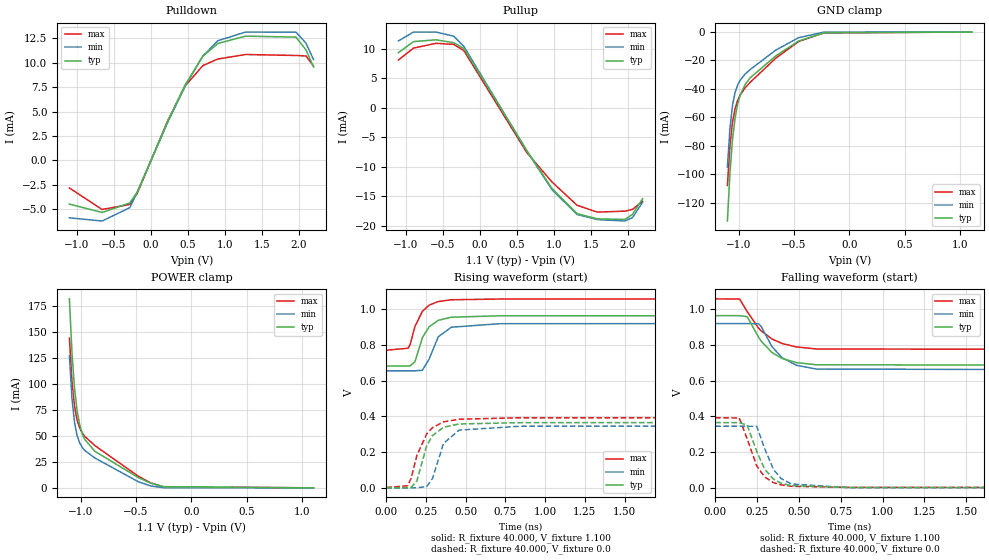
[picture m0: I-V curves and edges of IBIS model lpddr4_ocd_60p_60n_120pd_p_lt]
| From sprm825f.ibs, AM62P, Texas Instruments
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|   Model lpddr4_ocd_60p_60n_120pd_p_lt
[Model] lpddr4_ocd_60p_60n_120pd_p_lt
Model_type I/O
Polarity   Non-Inverting
Enable   Active-High
Vinl =  0.113V
Vinh =  0.253V
Vmeas =  0.183V
C_comp   2.501pF   2.199pF   2.627pF
C_comp_pullup   0.222pF   0.183pF   0.241pF
C_comp_pulldown   1.010pF   0.900pF   1.054pF
[Model Spec]
Vinh   0.253V   0.247V   0.265V
Vinl   0.113V   0.107V   0.125V
Vmeas   0.183V   0.176V   0.195V
[Temperature Range]   25.000   -40.000   -40.000
[Voltage Range]   1.100V   1.060V   1.170V
[Pullup Reference]   1.100V   1.060V   1.170V
[Pulldown Reference]   0.0V   0.0V   0.0V
[C Comp Corner]
C_comp_pullup   0.222pF   0.183pF   0.241pF
C_comp_pulldown   1.010pF   0.900pF   1.054pF
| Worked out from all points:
|   slope of the pulldown table from 0 to 0.165 V, typ, clamps not added: 56.7 ohm
|   slope of the pullup table from 0 to 0.165 V, typ, clamps not added: 50 ohm
|   GND clamp passes 1 mA (typ) near -0.26 V on its own axis
|   POWER clamp passes 1 mA (typ) near -0.24 V on its own axis
|   rising waveform, R_fixture 40.000, V_fixture 1.100: 20-80 % time 82.6ps typ, 84.4ps min, 81.3ps max; typ from 0.682 V to 0.963 V
|   rising waveform, R_fixture 40.000, V_fixture 0.0: 20-80 % time 86.2ps typ, 85.9ps min, 101ps max; typ from 0.001 V to 0.365 V
|   falling waveform, R_fixture 40.000, V_fixture 1.100: 20-80 % time 149ps typ, 138ps min, 167ps max; typ from 0.963 V to 0.682 V
|   falling waveform, R_fixture 40.000, V_fixture 0.0: 20-80 % time 102ps typ, 97.4ps min, 97.7ps max; typ from 0.365 V to 0.001 V
[Pulldown]
|Voltage   I(typ)   I(min)   I(max)
-1.1V     -4.465mA   -5.868mA   -2.813mA
-658mV    -5.322mA   -6.195mA   -5.016mA
-284mV    -4.35mA    -4.83mA    -4.5mA
-181mV    -3.204mA   -3.197mA   -3.337mA
227mV     3.972mA    3.87mA     4.042mA
465mV     7.743mA    7.616mA    7.631mA
703mV     10.66mA    10.69mA    9.709mA
907mV     11.98mA    12.26mA    10.39mA
1.281V    12.73mA    13.15mA    10.85mA
1.962V    12.63mA    13.14mA    10.75mA
2.098V    11.32mA    12.01mA    10.7mA
2.2V      9.575mA    10.33mA    9.655mA
[Pullup]
|Voltage   I(typ)   I(min)   I(max)
-1.1V     9.331mA    11.33mA    8.089mA
-896mV    11.22mA    12.84mA    10.12mA
-590mV    11.52mA    12.84mA    10.93mA
-352mV    11.03mA    12.13mA    10.74mA
-215mV    10.05mA    10.41mA    9.687mA
635mV     -7.226mA   -7.319mA   -7.577mA
975mV     -13.66mA   -13.86mA   -12.56mA
1.315V    -17.95mA   -18.1mA    -16.52mA
1.588V    -18.82mA   -18.95mA   -17.68mA
1.962V    -18.93mA   -19.19mA   -17.52mA
2.064V    -18.06mA   -18.61mA   -17.22mA
2.2V      -15.42mA   -16.05mA   -15.86mA
[GND_clamp]
|Voltage   I(typ)   I(min)   I(max)
-1.1V     -132.9mA   -94.96mA   -107.9mA
-1.077V   -98.86mA   -67.55mA   -79.9mA
-1.054V   -75.63mA   -51.54mA   -63.35mA
-1.031V   -60.5mA    -42.53mA   -53.84mA
-1.008V   -50.81mA   -37.28mA   -48.11mA
-985mV    -44.46mA   -33.89mA   -44.3mA
-940mV    -36.83mA   -29.52mA   -39.19mA
-894mV    -32.12mA   -26.33mA   -35.3mA
-665mV    -16.86mA   -12.76mA   -18.45mA
-458mV    -6.31mA    -3.966mA   -6.61mA
-229mV    -598.2uA   -44.97uA   -572.8uA
1.1V      0A         0A         0A
[POWER_clamp]
|Voltage   I(typ)   I(min)   I(max)
-1.1V     181.7mA    127.2mA    143.9mA
-1.077V   130mA      86.12mA    102.2mA
-1.054V   95.89mA    62.98mA    78.5mA
-1.031V   74.31mA    50.37mA    65.32mA
-1.008V   60.91mA    43.33mA    57.78mA
-985mV    52.38mA    38.99mA    52.94mA
-963mV    46.75mA    36.06mA    49.58mA
-871mV    35.15mA    28.73mA    40.66mA
-481mV    10mA       5.973mA    11.31mA
-367mV    4.507mA    1.8mA      4.728mA
-252mV    1.151mA    119.1uA    969.3uA
1.1V      0A         0A         0A
[Ramp]
| variable   typ   min   max
dV/dt_r   0.204/64.725p   0.193/75.922p   0.233/76.545p
dV/dt_f   0.204/0.144n   0.191/0.113n   0.233/0.138n
R_load = 40.000
[Rising Waveform]
R_fixture= 40.000
V_fixture= 1.100
V_fixture_min= 1.060
V_fixture_max= 1.170
|time   V(typ)   V(min)   V(max)
0s        681.8mV    654.8mV    769.8mV
139ps     681.3mV    654.8mV    781.1mV
151ps     682.7mV    654.8mV    802.9mV
181ps     705.5mV    654.7mV    903mV
228ps     840.8mV    657.8mV    987.4mV
270ps     900.9mV    720.4mV    1.022V
328ps     937mV      845.3mV    1.042V
410ps     954.6mV    898.5mV    1.052V
716ps     962.3mV    918.1mV    1.056V
5ns       963.1mV    919.1mV    1.057V
[Rising Waveform]
R_fixture= 40.000
V_fixture= 0.0
V_fixture_min= 0.0
V_fixture_max= 0.0
|time   V(typ)   V(min)   V(max)
0s        1.001mV    66.44uV    2.122mV
135ps     958.1uV    65.51uV    12.02mV
157ps     2.348mV    66.4uV     54.57mV
193ps     39.17mV    64.57uV    181.4mV
255ps     235.7mV    7.366mV    301.9mV
291ps     291.9mV    51.94mV    336.5mV
361ps     339.4mV    248.9mV    369.2mV
458ps     357.3mV    322.9mV    384mV
845ps     364.6mV    344.7mV    392.1mV
5ns       365.4mV    347.1mV    392.5mV
[Falling Waveform]
R_fixture= 40.000
V_fixture= 1.100
V_fixture_min= 1.060
V_fixture_max= 1.170
|time   V(typ)   V(min)   V(max)
0s        963.1mV    918.8mV    1.057V
146ps     963mV      918.8mV    1.056V
191ps     957.3mV    918.8mV    985.7mV
260ps     840.7mV    917.3mV    892.5mV
275ps     820mV      902.3mV    877.9mV
339ps     756.9mV    789.9mV    832.6mV
401ps     723.1mV    726.9mV    806.9mV
485ps     700.5mV    685.7mV    788.2mV
603ps     688.5mV    664.5mV    776.9mV
5ns       681.8mV    654.8mV    769.8mV
[Falling Waveform]
R_fixture= 40.000
V_fixture= 0.0
V_fixture_min= 0.0
V_fixture_max= 0.0
|time   V(typ)   V(min)   V(max)
0s        365.1mV    344.7mV    392.4mV
144ps     364.9mV    344.7mV    390.8mV
191ps     350.7mV    344.7mV    273.8mV
248ps     203.6mV    344mV      123mV
295ps     105.1mV    221.2mV    61.08mV
348ps     48.7mV     103mV      29.09mV
394ps     25.99mV    51.71mV    16.4mV
455ps     12.38mV    21.75mV    8.768mV
802ps     1.883mV    1.067mV    2.601mV
5ns       1.007mV    66.26uV    2.128mV
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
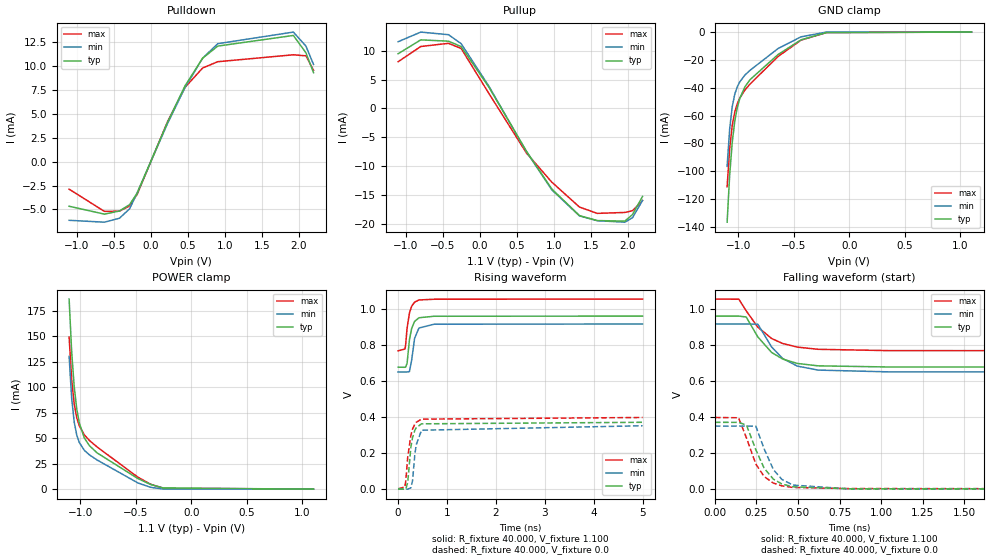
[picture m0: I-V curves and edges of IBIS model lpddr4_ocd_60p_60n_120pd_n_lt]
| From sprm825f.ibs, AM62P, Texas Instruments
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|   Model lpddr4_ocd_60p_60n_120pd_n_lt
[Model] lpddr4_ocd_60p_60n_120pd_n_lt
Model_type I/O
Polarity   Non-Inverting
Enable   Active-High
Vinl =  0.113V
Vinh =  0.253V
Vmeas =  0.183V
C_comp   2.882pF   2.570pF   2.980pF
C_comp_pullup   0.261pF   0.223pF   0.276pF
C_comp_pulldown   1.154pF   1.038pF   1.187pF
[Model Spec]
Vinh   0.253V   0.247V   0.265V
Vinl   0.113V   0.107V   0.125V
Vmeas   0.183V   0.176V   0.195V
[Temperature Range]   25.000   -40.000   -40.000
[Voltage Range]   1.100V   1.060V   1.170V
[Pullup Reference]   1.100V   1.060V   1.170V
[Pulldown Reference]   0.0V   0.0V   0.0V
[C Comp Corner]
C_comp_pullup   0.261pF   0.223pF   0.276pF
C_comp_pulldown   1.154pF   1.038pF   1.187pF
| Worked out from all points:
|   slope of the pulldown table from 0 to 0.165 V, typ, clamps not added: 55.3 ohm
|   slope of the pullup table from 0 to 0.165 V, typ, clamps not added: 48.5 ohm
|   GND clamp passes 1 mA (typ) near -0.26 V on its own axis
|   POWER clamp passes 1 mA (typ) near -0.24 V on its own axis
|   rising waveform, R_fixture 40.000, V_fixture 1.100: 20-80 % time 92.8ps typ, 93.9ps min, 90.2ps max; typ from 0.678 V to 0.961 V
|   rising waveform, R_fixture 40.000, V_fixture 0.0: 20-80 % time 95.8ps typ, 95.3ps min, 111ps max; typ from 0.001 V to 0.371 V
|   falling waveform, R_fixture 40.000, V_fixture 1.100: 20-80 % time 162ps typ, 150ps min, 180ps max; typ from 0.961 V to 0.678 V
|   falling waveform, R_fixture 40.000, V_fixture 0.0: 20-80 % time 112ps typ, 108ps min, 106ps max; typ from 0.371 V to 0.001 V
[Pulldown]
|Voltage   I(typ)   I(min)   I(max)
-1.1V     -4.662mA   -6.128mA   -2.879mA
-624mV    -5.486mA   -6.326mA   -5.197mA
-420mV    -5.158mA   -5.912mA   -5.178mA
-284mV    -4.493mA   -4.936mA   -4.625mA
-181mV    -3.295mA   -3.26mA    -3.417mA
227mV     4.067mA    3.939mA    4.121mA
465mV     7.903mA    7.734mA    7.744mA
703mV     10.79mA    10.79mA    9.764mA
907mV     12.05mA    12.3mA     10.42mA
1.928V    13.16mA    13.51mA    11.14mA
2.098V    11.34mA    12.04mA    11.03mA
2.2V      9.276mA    10.13mA    9.525mA
[Pullup]
|Voltage   I(typ)   I(min)   I(max)
-1.1V     9.492mA    11.58mA    8.104mA
-794mV    11.9mA     13.25mA    10.75mA
-420mV    11.67mA    12.8mA     11.3mA
-249mV    10.74mA    11.24mA    10.41mA
125mV     3.7mA      3.874mA    2.615mA
635mV     -7.477mA   -7.541mA   -7.78mA
975mV     -13.98mA   -14.12mA   -12.79mA
1.349V    -18.6mA    -18.65mA   -17.12mA
1.588V    -19.46mA   -19.48mA   -18.21mA
1.962V    -19.55mA   -19.74mA   -18.05mA
2.064V    -18.42mA   -18.97mA   -17.75mA
2.2V      -15.28mA   -15.97mA   -15.99mA
[GND_clamp]
|Voltage   I(typ)   I(min)   I(max)
-1.1V     -136.6mA   -96.46mA   -111.1mA
-1.077V   -102.6mA   -69.55mA   -83.57mA
-1.054V   -79.22mA   -53.64mA   -67.05mA
-1.031V   -63.93mA   -44.56mA   -57.36mA
-1.008V   -54.04mA   -39.16mA   -51.37mA
-985mV    -47.47mA   -35.61mA   -47.28mA
-940mV    -39.36mA   -30.91mA   -41.63mA
-894mV    -34.19mA   -27.47mA   -37.37mA
-642mV    -16.16mA   -11.85mA   -17.57mA
-435mV    -5.566mA   -3.394mA   -5.8mA
-206mV    -368.5uA   -17.49uA   -340.6uA
1.1V      0A         0A         0A
[POWER_clamp]
|Voltage   I(typ)   I(min)   I(max)
-1.1V     186.7mA    130.4mA    149.4mA
-1.077V   134.7mA    89.1mA     107.4mA
-1.054V   100.3mA    65.79mA    83.44mA
-1.031V   78.51mA    53mA       69.97mA
-1.008V   64.87mA    45.79mA    62.12mA
-963mV    50.23mA    38.14mA    53.29mA
-917mV    42.67mA    33.66mA    47.79mA
-848mV    35.63mA    28.64mA    41.42mA
-481mV    10.42mA    6.123mA    11.78mA
-367mV    4.613mA    1.825mA    4.83mA
-252mV    1.166mA    119.3uA    981uA
1.1V      0A         0A         0A
[Ramp]
| variable   typ   min   max
dV/dt_r   0.212/79.827p   0.199/91.371p   0.242/93.343p
dV/dt_f   0.212/0.171n   0.199/0.143n   0.242/0.166n
R_load = 40.000
[Rising Waveform]
R_fixture= 40.000
V_fixture= 1.100
V_fixture_min= 1.060
V_fixture_max= 1.170
|time   V(typ)   V(min)   V(max)
0s        677.6mV    651mV      768.6mV
141ps     677.1mV    651mV      778.5mV
153ps     678.2mV    651mV      799.5mV
183ps     699.1mV    650.9mV    893.6mV
232ps     831mV      653.3mV    978.9mV
278ps     894mV      718.9mV    1.017V
337ps     931.7mV    838mV      1.039V
426ps     952.2mV    895.1mV    1.051V
735ps     960.5mV    916.3mV    1.055V
5ns       961.4mV    917.6mV    1.056V
[Rising Waveform]
R_fixture= 40.000
V_fixture= 0.0
V_fixture_min= 0.0
V_fixture_max= 0.0
|time   V(typ)   V(min)   V(max)
0s        1.013mV    67.98uV    2.144mV
138ps     958.2uV    67.48uV    12.04mV
158ps     1.751mV    69.55uV    48.72mV
196ps     37.34mV    55.44uV    177.2mV
261ps     233.6mV    7.374mV    299.7mV
295ps     286.2mV    47.33mV    333.5mV
341ps     326.6mV    190.3mV    361mV
370ps     341.2mV    246.8mV    371.5mV
479ps     363mV      327.5mV    389mV
5ns       371.5mV    352.3mV    398.2mV
[Falling Waveform]
R_fixture= 40.000
V_fixture= 1.100
V_fixture_min= 1.060
V_fixture_max= 1.170
|time   V(typ)   V(min)   V(max)
0s        961.5mV    917.6mV    1.056V
144ps     961.4mV    917.6mV    1.055V
188ps     956.4mV    917.6mV    990.7mV
258ps     845.8mV    916.3mV    899.9mV
341ps     759.4mV    789.9mV    836.9mV
408ps     722.6mV    725.4mV    808.9mV
496ps     698.3mV    683.5mV    789.1mV
620ps     685.1mV    661.5mV    776.9mV
1.044ns   678.7mV    651.6mV    769.6mV
5ns       677.6mV    651mV      768.7mV
[Falling Waveform]
R_fixture= 40.000
V_fixture= 0.0
V_fixture_min= 0.0
V_fixture_max= 0.0
|time   V(typ)   V(min)   V(max)
0s        371.3mV    350.5mV    398.2mV
142ps     371.2mV    350.5mV    396.6mV
190ps     355.7mV    350.5mV    284.1mV
246ps     219mV      349.5mV    139.6mV
296ps     116.3mV    224mV      70.37mV
352ps     55.39mV    107.9mV    33.56mV
403ps     28.81mV    54.06mV    18.18mV
469ps     13.3mV     22.76mV    9.479mV
808ps     2.308mV    1.508mV    3.187mV
5ns       1.025mV    68.48uV    2.152mV
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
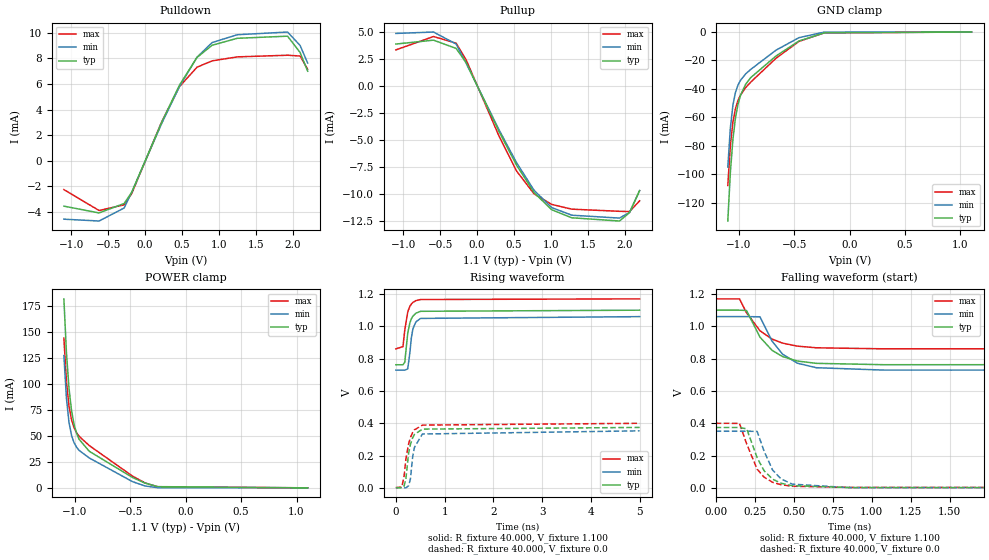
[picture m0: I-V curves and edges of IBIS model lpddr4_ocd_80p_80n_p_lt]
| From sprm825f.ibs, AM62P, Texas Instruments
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|   Model lpddr4_ocd_80p_80n_p_lt
[Model] lpddr4_ocd_80p_80n_p_lt
Model_type I/O
Polarity   Non-Inverting
Enable   Active-High
Vinl =  0.113V
Vinh =  0.253V
Vmeas =  0.183V
C_comp   2.875pF   2.705pF   2.914pF
C_comp_pullup   0.267pF   0.256pF   0.274pF
C_comp_pulldown   1.150pF   1.077pF   1.162pF
[Model Spec]
Vinh   0.253V   0.247V   0.265V
Vinl   0.113V   0.107V   0.125V
Vmeas   0.183V   0.176V   0.195V
[Temperature Range]   25.000   -40.000   -40.000
[Voltage Range]   1.100V   1.060V   1.170V
[Pullup Reference]   1.100V   1.060V   1.170V
[Pulldown Reference]   0.0V   0.0V   0.0V
[C Comp Corner]
C_comp_pullup   0.267pF   0.256pF   0.274pF
C_comp_pulldown   1.150pF   1.077pF   1.162pF
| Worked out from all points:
|   slope of the pulldown table from 0 to 0.165 V, typ, clamps not added: 73.9 ohm
|   slope of the pullup table from 0 to 0.165 V, typ, clamps not added: 69.2 ohm
|   GND clamp passes 1 mA (typ) near -0.26 V on its own axis
|   POWER clamp passes 1 mA (typ) near -0.24 V on its own axis
|   rising waveform, R_fixture 40.000, V_fixture 1.100: 20-80 % time 94.3ps typ, 85.3ps min, 97.7ps max; typ from 0.762 V to 1.1 V
|   rising waveform, R_fixture 40.000, V_fixture 0.0: 20-80 % time 117ps typ, 111ps min, 138ps max; typ from 0.001 V to 0.374 V
|   falling waveform, R_fixture 40.000, V_fixture 1.100: 20-80 % time 165ps typ, 156ps min, 173ps max; typ from 1.1 V to 0.762 V
|   falling waveform, R_fixture 40.000, V_fixture 0.0: 20-80 % time 112ps typ, 106ps min, 109ps max; typ from 0.374 V to 0.001 V
[Pulldown]
|Voltage   I(typ)   I(min)   I(max)
-1.1V     -3.55mA    -4.569mA   -2.257mA
-624mV    -4.081mA   -4.713mA   -3.89mA
-284mV    -3.342mA   -3.694mA   -3.446mA
-181mV    -2.462mA   -2.445mA   -2.556mA
227mV     3.045mA    2.956mA    3.087mA
465mV     5.917mA    5.805mA    5.803mA
703mV     8.088mA    8.108mA    7.323mA
907mV     9.036mA    9.246mA    7.815mA
1.247V    9.58mA     9.859mA    8.126mA
1.928V    9.746mA    10.07mA    8.255mA
2.098V    8.47mA     9.019mA    8.192mA
2.2V      7.007mA    7.645mA    7.157mA
[Pullup]
|Voltage   I(typ)   I(min)   I(max)
-1.1V     3.878mA    4.864mA    3.337mA
-590mV    4.241mA    4.995mA    4.578mA
-284mV    3.474mA    3.881mA    3.963mA
-147mV    2.143mA    2.082mA    2.395mA
295mV     -4.212mA   -4.051mA   -4.634mA
533mV     -7.344mA   -7.112mA   -7.89mA
771mV     -9.904mA   -9.688mA   -10.02mA
1.009V    -11.49mA   -11.29mA   -11mA
1.281V    -12.24mA   -12mA      -11.44mA
1.928V    -12.54mA   -12.27mA   -11.64mA
2.064V    -11.76mA   -11.74mA   -11.66mA
2.2V      -9.708mA   -9.73mA    -10.67mA
[GND_clamp]
|Voltage   I(typ)   I(min)   I(max)
-1.1V     -132.9mA   -94.96mA   -107.9mA
-1.077V   -98.86mA   -67.55mA   -79.9mA
-1.054V   -75.63mA   -51.54mA   -63.35mA
-1.031V   -60.5mA    -42.53mA   -53.84mA
-1.008V   -50.81mA   -37.28mA   -48.11mA
-985mV    -44.46mA   -33.89mA   -44.3mA
-940mV    -36.83mA   -29.52mA   -39.19mA
-894mV    -32.12mA   -26.33mA   -35.3mA
-665mV    -16.86mA   -12.76mA   -18.45mA
-458mV    -6.31mA    -3.966mA   -6.61mA
-229mV    -598.2uA   -44.98uA   -572.8uA
1.1V      0A         0A         0A
[POWER_clamp]
|Voltage   I(typ)   I(min)   I(max)
-1.1V     181.7mA    127.2mA    143.9mA
-1.077V   130mA      86.12mA    102.2mA
-1.054V   95.89mA    62.98mA    78.5mA
-1.031V   74.31mA    50.37mA    65.33mA
-1.008V   60.91mA    43.33mA    57.78mA
-985mV    52.38mA    38.99mA    52.94mA
-963mV    46.75mA    36.06mA    49.58mA
-871mV    35.15mA    28.73mA    40.66mA
-481mV    10mA       5.973mA    11.31mA
-367mV    4.507mA    1.8mA      4.728mA
-252mV    1.151mA    119.1uA    969.3uA
1.1V      0A         0A         0A
[Ramp]
| variable   typ   min   max
dV/dt_r   0.230/80.319p   0.218/74.786p   0.251/87.678p
dV/dt_f   0.230/0.177n   0.217/0.160n   0.251/0.185n
R_load = 40.000
[Rising Waveform]
R_fixture= 40.000
V_fixture= 1.100
V_fixture_min= 1.060
V_fixture_max= 1.170
|time   V(typ)   V(min)   V(max)
0s        762.1mV    728.7mV    860.5mV
146ps     762mV      728.7mV    874.4mV
183ps     777.5mV    728.5mV    976.1mV
244ps     957.8mV    736.6mV    1.089V
288ps     1.022V     837.3mV    1.124V
319ps     1.047V     930.8mV    1.138V
350ps     1.063V     984mV      1.148V
410ps     1.081V     1.027V     1.159V
508ps     1.093V     1.049V     1.166V
5ns       1.1V       1.06V      1.17V
[Rising Waveform]
R_fixture= 40.000
V_fixture= 0.0
V_fixture_min= 0.0
V_fixture_max= 0.0
|time   V(typ)   V(min)   V(max)
0s        1.126mV    70.83uV    2.392mV
122ps     1.111mV    70.64uV    4.252mV
170ps     11.4mV     70.26uV    75.8mV
206ps     57.8mV     67.76uV    177.4mV
262ps     214.5mV    13.01mV    272.4mV
299ps     269mV      55.06mV    311.4mV
346ps     311.3mV    194.5mV    343.7mV
381ps     330.7mV    250mV      359.2mV
545ps     363.7mV    333.3mV    388.5mV
5ns       374.1mV    353mV      399.7mV
[Falling Waveform]
R_fixture= 40.000
V_fixture= 1.100
V_fixture_min= 1.060
V_fixture_max= 1.170
|time   V(typ)   V(min)   V(max)
0s        1.1V       1.06V      1.17V
153ps     1.1V       1.06V      1.17V
198ps     1.098V     1.06V      1.084V
284ps     933.2mV    1.059V     972.7mV
362ps     851mV      907.8mV    920.8mV
430ps     812.4mV    826.8mV    895.7mV
524ps     785.2mV    771.7mV    877.4mV
645ps     770.8mV    743.8mV    867.1mV
1.073ns   762.5mV    729.2mV    860.8mV
5ns       762.1mV    728.7mV    860.5mV
[Falling Waveform]
R_fixture= 40.000
V_fixture= 0.0
V_fixture_min= 0.0
V_fixture_max= 0.0
|time   V(typ)   V(min)   V(max)
0s        373.8mV    350.5mV    399.6mV
153ps     373.6mV    350.5mV    399.2mV
199ps     365.6mV    350.5mV    272mV
266ps     186.9mV    349.6mV    115.8mV
311ps     105.2mV    226.1mV    65.9mV
365ps     54.02mV    110.4mV    34.68mV
419ps     28.83mV    55.42mV    19.31mV
492ps     13.39mV    22.94mV    9.914mV
859ps     2.026mV    1.008mV    2.866mV
5ns       1.132mV    70.72uV    2.397mV
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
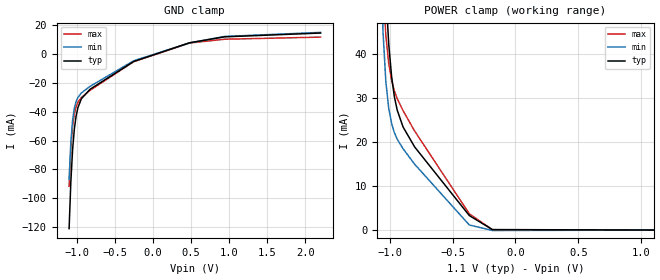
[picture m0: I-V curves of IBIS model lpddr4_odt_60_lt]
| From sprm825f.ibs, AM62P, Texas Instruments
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|   Model lpddr4_odt_60_lt
[Model] lpddr4_odt_60_lt
Model_type Input
Polarity   Non-Inverting
Enable   Active-High
Vinl =  0.113V
Vinh =  0.253V
C_comp   2.516pF   2.367pF   2.551pF
[Model Spec]
Vinh   0.253V   0.247V   0.265V
Vinl   0.113V   0.107V   0.125V
[Temperature Range]   25.000   -40.000   -40.000
[Voltage Range]   1.100V   1.060V   1.170V
[C Comp Corner]
C_comp   2.516pF   2.367pF   2.551pF
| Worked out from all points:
|   GND clamp passes 1 mA (typ) near -0.05 V on its own axis
|   POWER clamp passes 1 mA (typ) near -0.27 V on its own axis
[GND_clamp]
|Voltage   I(typ)   I(min)   I(max)
-1.1V     -121.2mA   -87mA      -91.74mA
-1.077V   -88.47mA   -60.89mA   -65.3mA
-1.054V   -66.2mA    -45.75mA   -49.83mA
-1.031V   -51.88mA   -37.44mA   -41.24mA
-1.008V   -42.91mA   -32.83mA   -36.39mA
-985mV    -37.26mA   -30.08mA   -33.45mA
-940mV    -30.99mA   -26.94mA   -30.07mA
-825mV    -24.33mA   -22.31mA   -25.06mA
-252mV    -5.011mA   -4.503mA   -5.159mA
481mV     7.979mA    7.845mA    7.801mA
940mV     12.1mA     12.38mA    10.44mA
2.2V      14.74mA    15.19mA    11.91mA
[POWER_clamp]
|Voltage   I(typ)   I(min)   I(max)
-1.1V     153.2mA    107.6mA    119.3mA
-1.054V   74.17mA    45.42mA    56.33mA
-1.031V   54.35mA    33.78mA    44.31mA
-1.008V   42.29mA    27.69mA    37.87mA
-985mV    34.9mA     24.24mA    34.08mA
-963mV    30.31mA    22.15mA    31.67mA
-940mV    27.23mA    20.64mA    29.86mA
-894mV    23.45mA    18.5mA     27.16mA
-802mV    18.91mA    14.98mA    22.53mA
-367mV    3.295mA    1.152mA    3.701mA
-183mV    103.8uA    -100.7uA   71.17uA
1.1V      0A         0A         0A
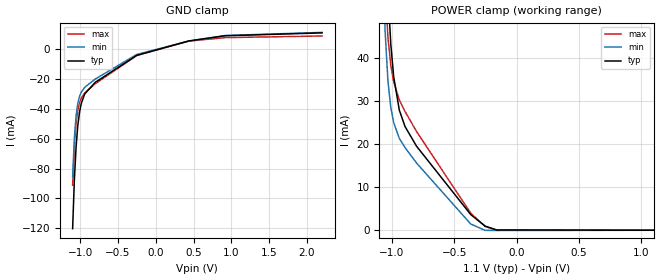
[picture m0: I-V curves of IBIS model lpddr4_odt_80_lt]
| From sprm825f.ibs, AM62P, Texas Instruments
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|   Model lpddr4_odt_80_lt
[Model] lpddr4_odt_80_lt
Model_type Input
Polarity   Non-Inverting
Enable   Active-High
Vinl =  0.113V
Vinh =  0.253V
C_comp   2.678pF   2.500pF   2.686pF
[Model Spec]
Vinh   0.253V   0.247V   0.265V
Vinl   0.113V   0.107V   0.125V
[Temperature Range]   25.000   -40.000   -40.000
[Voltage Range]   1.100V   1.060V   1.170V
[C Comp Corner]
C_comp   2.678pF   2.500pF   2.686pF
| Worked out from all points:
|   GND clamp passes 1 mA (typ) near -0.07 V on its own axis
|   POWER clamp passes 1 mA (typ) near -0.25 V on its own axis
[GND_clamp]
|Voltage   I(typ)   I(min)   I(max)
-1.1V     -120.3mA   -85.71mA   -91.19mA
-1.077V   -87.55mA   -59.59mA   -64.72mA
-1.054V   -65.25mA   -44.43mA   -49.23mA
-1.031V   -50.9mA    -36.1mA    -40.6mA
-1.008V   -41.92mA   -31.47mA   -35.71mA
-985mV    -36.24mA   -28.69mA   -32.73mA
-940mV    -29.91mA   -25.5mA    -29.26mA
-802mV    -22.2mA    -20mA      -23.13mA
-252mV    -4.059mA   -3.469mA   -4.164mA
435mV     5.579mA    5.465mA    5.474mA
917mV     9.059mA    9.251mA    7.814mA
2.2V      11.01mA    11.33mA    8.92mA
[POWER_clamp]
|Voltage   I(typ)   I(min)   I(max)
-1.1V     154.4mA    108.7mA    119.9mA
-1.054V   75.16mA    46.35mA    56.82mA
-1.031V   55.26mA    34.64mA    44.74mA
-1.008V   43.12mA    28.48mA    38.27mA
-985mV    35.66mA    24.99mA    34.46mA
-940mV    27.9mA     21.34mA    30.26mA
-894mV    24.08mA    19.19mA    27.58mA
-802mV    19.52mA    15.62mA    22.94mA
-367mV    3.629mA    1.439mA    3.947mA
-252mV    967.4uA    -24.03uA   877.7uA
-160mV    71.14uA    -54.83uA   34.22uA
1.1V      0A         0A         0A
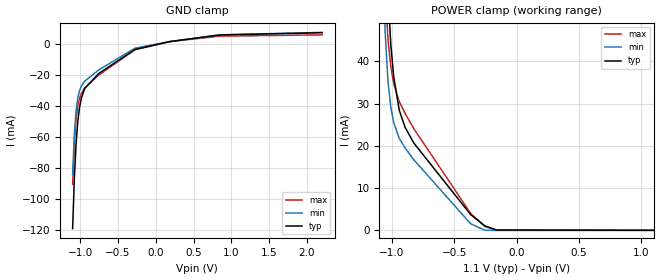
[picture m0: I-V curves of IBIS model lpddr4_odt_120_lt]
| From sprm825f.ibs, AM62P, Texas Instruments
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|   Model lpddr4_odt_120_lt
[Model] lpddr4_odt_120_lt
Model_type Input
Polarity   Non-Inverting
Enable   Active-High
Vinl =  0.113V
Vinh =  0.253V
C_comp   2.759pF   2.558pF   2.762pF
[Model Spec]
Vinh   0.253V   0.247V   0.265V
Vinl   0.113V   0.107V   0.125V
[Temperature Range]   25.000   -40.000   -40.000
[Voltage Range]   1.100V   1.060V   1.170V
[C Comp Corner]
C_comp   2.759pF   2.558pF   2.762pF
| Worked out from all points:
|   GND clamp passes 1 mA (typ) near -0.10 V on its own axis
|   POWER clamp passes 1 mA (typ) near -0.25 V on its own axis
[GND_clamp]
|Voltage   I(typ)   I(min)   I(max)
-1.1V     -119.1mA   -84.18mA   -90.44mA
-1.077V   -86.33mA   -58.04mA   -63.94mA
-1.054V   -64.01mA   -42.87mA   -48.42mA
-1.031V   -49.65mA   -34.53mA   -39.77mA
-1.008V   -40.65mA   -29.89mA   -34.85mA
-985mV    -34.95mA   -27.11mA   -31.83mA
-940mV    -28.59mA   -23.91mA   -28.3mA
-756mV    -19.03mA   -16.72mA   -20.07mA
-275mV    -3.494mA   -2.65mA    -3.59mA
183mV     1.609mA    1.598mA    1.584mA
848mV     5.888mA    5.986mA    5.131mA
2.2V      7.344mA    7.55mA     5.944mA
[POWER_clamp]
|Voltage   I(typ)   I(min)   I(max)
-1.1V     155.8mA    109.8mA    120.9mA
-1.054V   76.24mA    47.18mA    57.49mA
-1.031V   56.2mA     35.36mA    45.29mA
-1.008V   43.93mA    29.1mA     38.69mA
-985mV    36.35mA    25.52mA    34.77mA
-940mV    28.38mA    21.73mA    30.42mA
-894mV    24.41mA    19.5mA     27.69mA
-825mV    20.71mA    16.73mA    24.12mA
-367mV    3.696mA    1.527mA    3.977mA
-252mV    1.004mA    20.43uA    893.6uA
-160mV    85.09uA    -35.79uA   39.17uA
1.1V      0A         0A         0A
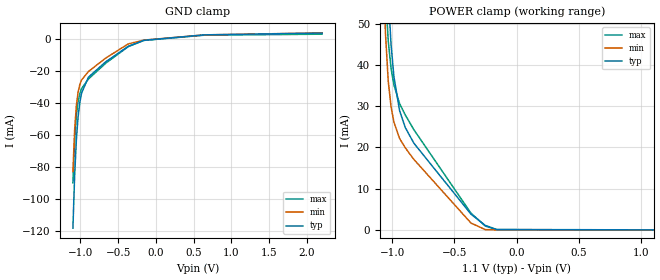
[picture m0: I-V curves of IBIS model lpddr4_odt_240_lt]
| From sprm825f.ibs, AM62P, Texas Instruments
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|   Model lpddr4_odt_240_lt
[Model] lpddr4_odt_240_lt
Model_type Input
Polarity   Non-Inverting
Enable   Active-High
Vinl =  0.113V
Vinh =  0.253V
C_comp   2.845pF   2.618pF   2.850pF
[Model Spec]
Vinh   0.253V   0.247V   0.265V
Vinl   0.113V   0.107V   0.125V
[Temperature Range]   25.000   -40.000   -40.000
[Voltage Range]   1.100V   1.060V   1.170V
[C Comp Corner]
C_comp   2.850pF   2.618pF   2.845pF
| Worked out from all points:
|   GND clamp passes 1 mA (typ) near -0.18 V on its own axis
|   POWER clamp passes 1 mA (typ) near -0.25 V on its own axis
[GND_clamp]
|Voltage   I(typ)   I(min)   I(max)
-1.1V     -118mA     -82.7mA    -89.7mA
-1.077V   -85.16mA   -56.55mA   -63.17mA
-1.054V   -62.82mA   -41.36mA   -47.63mA
-1.031V   -48.44mA   -33.02mA   -38.95mA
-1.008V   -39.42mA   -28.37mA   -34mA
-985mV    -33.72mA   -25.58mA   -30.95mA
-894mV    -23.83mA   -20.3mA    -24.96mA
-665mV    -14.23mA   -11.91mA   -15.11mA
-367mV    -4.597mA   -3.103mA   -4.806mA
-160mV    -865.1uA   -725uA     -900.3uA
642mV     2.55mA     2.533mA    2.353mA
2.2V      3.682mA    3.776mA    2.977mA
[POWER_clamp]
|Voltage   I(typ)   I(min)   I(max)
-1.1V     157.1mA    110.9mA    121.8mA
-1.054V   77.32mA    48.05mA    58.15mA
-1.031V   57.15mA    36.13mA    45.83mA
-1.008V   44.77mA    29.77mA    39.12mA
-985mV    37.09mA    26.1mA     35.11mA
-940mV    28.93mA    22.18mA    30.64mA
-894mV    24.81mA    19.89mA    27.87mA
-825mV    21.02mA    17.09mA    24.29mA
-367mV    3.829mA    1.664mA    4.063mA
-252mV    1.082mA    74.19uA    942.8uA
-160mV    107.7uA    -16.29uA   47.67uA
1.1V      0A         0A         0A
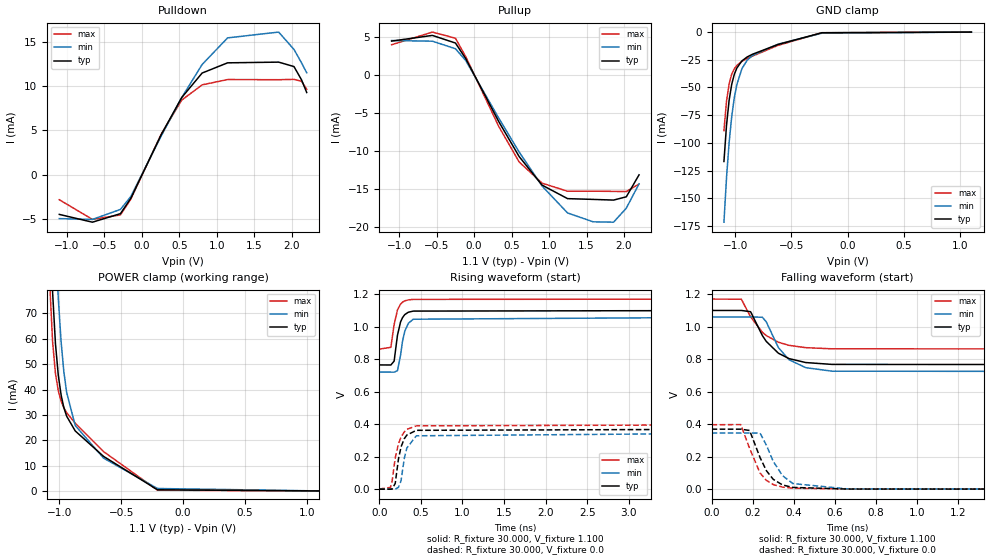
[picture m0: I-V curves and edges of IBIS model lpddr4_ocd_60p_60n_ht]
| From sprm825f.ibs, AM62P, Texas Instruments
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|   Model lpddr4_ocd_60p_60n_ht
[Model] lpddr4_ocd_60p_60n_ht
Model_type I/O
Polarity   Non-Inverting
Enable   Active-High
Vinl =  0.113V
Vinh =  0.253V
Vmeas =  0.183V
C_comp   2.344pF   2.304pF   2.405pF
[Model Spec]
Vinh   0.253V   0.247V   0.265V
Vinl   0.113V   0.107V   0.125V
Vmeas   0.183V   0.176V   0.195V
[Temperature Range]   25.000   0.125k   -40.000
[Voltage Range]   1.100V   1.060V   1.170V
[Pullup Reference]   1.100V   1.060V   1.170V
[Pulldown Reference]   0.0V   0.0V   0.0V
[C Comp Corner]
C_comp   2.344pF   2.304pF   2.405pF
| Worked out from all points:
|   slope of the pulldown table from 0 to 0.165 V, typ, clamps not added: 56.6 ohm
|   slope of the pullup table from 0 to 0.165 V, typ, clamps not added: 52.9 ohm
|   GND clamp passes 1 mA (typ) near -0.26 V on its own axis
|   POWER clamp passes 1 mA (typ) near -0.24 V on its own axis
|   rising waveform, R_fixture 30.000, V_fixture 1.100: 20-80 % time 67.5ps typ, 73.6ps min, 66.5ps max; typ from 0.765 V to 1.1 V
|   rising waveform, R_fixture 30.000, V_fixture 0.0: 20-80 % time 82.2ps typ, 82.5ps min, 96.3ps max; typ from 0.001 V to 0.37 V
|   falling waveform, R_fixture 30.000, V_fixture 1.100: 20-80 % time 118ps typ, 107ps min, 122ps max; typ from 1.1 V to 0.765 V
|   falling waveform, R_fixture 30.000, V_fixture 0.0: 20-80 % time 82.8ps typ, 90.5ps min, 78.2ps max; typ from 0.37 V to 0.001 V
[Pulldown]
|Voltage   I(typ)   I(min)   I(max)
-1.1V     -4.446mA   -4.919mA   -2.793mA
-658mV    -5.323mA   -5.012mA   -5.008mA
-284mV    -4.362mA   -3.884mA   -4.507mA
-147mV    -2.65mA    -2.442mA   -2.744mA
261mV     4.549mA    4.403mA    4.612mA
533mV     8.705mA    8.699mA    8.418mA
805mV     11.46mA    12.42mA    10.13mA
1.145V    12.61mA    15.42mA    10.73mA
1.826V    12.69mA    16.07mA    10.71mA
2.03V     12.19mA    14.12mA    10.75mA
2.132V    10.68mA    12.59mA    10.52mA
2.2V      9.269mA    11.49mA    9.64mA
[Pullup]
|Voltage   I(typ)   I(min)   I(max)
-1.1V     4.437mA    4.51mA     3.961mA
-556mV    5.183mA    4.424mA    5.618mA
-249mV    4.183mA    3.436mA    4.815mA
-113mV    2.168mA    1.914mA    2.422mA
329mV     -6.125mA   -5.668mA   -6.761mA
601mV     -10.71mA   -10.11mA   -11.42mA
907mV     -14.46mA   -14.58mA   -14.2mA
1.247V    -16.23mA   -18.11mA   -15.26mA
1.588V    -16.33mA   -19.27mA   -15.25mA
1.86V     -16.42mA   -19.32mA   -15.28mA
2.03V     -15.99mA   -17.48mA   -15.3mA
2.2V      -13.11mA   -14.29mA   -14.31mA
[GND_clamp]
|Voltage   I(typ)   I(min)   I(max)
-1.1V     -116.8mA   -171.6mA   -88.94mA
-1.077V   -83.96mA   -131.3mA   -62.39mA
-1.054V   -61.6mA    -99.87mA   -46.82mA
-1.031V   -47.19mA   -76.34mA   -38.11mA
-1.008V   -38.16mA   -59.32mA   -33.12mA
-985mV    -32.43mA   -47.3mA    -30.04mA
-940mV    -26mA      -32.95mA   -26.37mA
-894mV    -22.48mA   -25.52mA   -23.91mA
-848mV    -20.08mA   -21.13mA   -21.75mA
-619mV    -11.17mA   -10.91mA   -11.97mA
-229mV    -598.8uA   -1.001mA   -573.1uA
1.1V      0A         0A         0A
[POWER_clamp]
|Voltage   I(typ)   I(min)   I(max)
-1.1V     158.5mA    248.7mA    122.8mA
-1.077V   110.5mA    184.5mA    81.81mA
-1.054V   78.43mA    136mA      58.82mA
-1.031V   58.13mA    100.8mA    46.37mA
-1.008V   45.61mA    75.97mA    39.54mA
-985mV    37.81mA    58.74mA    35.43mA
-963mV    32.84mA    46.93mA    32.78mA
-940mV    29.44mA    38.74mA    30.8mA
-871mV    23.65mA    25.79mA    26.71mA
-642mV    13.62mA    12.94mA    15.51mA
-206mV    448.9uA    953.5uA    285.6uA
1.1V      0A         0A         0A
[Ramp]
| variable   typ   min   max
dV/dt_r   0.222/82.037p   0.208/82.554p   0.238/96.254p
dV/dt_f   0.201/0.118n   0.204/0.107n   0.185/0.122n
R_load = 30.000
[Rising Waveform]
R_fixture= 30.000
V_fixture= 1.100
V_fixture_min= 1.060
V_fixture_max= 1.170
|time   V(typ)   V(min)   V(max)
0s        764.9mV    720.6mV    861.9mV
140ps     764.5mV    720.6mV    873.4mV
179ps     788.4mV    720.3mV    1.013V
219ps     946.8mV    729.4mV    1.103V
256ps     1.029V     823.9mV    1.139V
280ps     1.056V     911.1mV    1.151V
308ps     1.075V     973.6mV    1.159V
350ps     1.089V     1.021V     1.165V
409ps     1.096V     1.046V     1.168V
5ns       1.1V       1.06V      1.17V
[Rising Waveform]
R_fixture= 30.000
V_fixture= 0.0
V_fixture_min= 0.0
V_fixture_max= 0.0
|time   V(typ)   V(min)   V(max)
0s        840.1uV    1.262mV    1.786mV
136ps     813.9uV    1.256mV    11.91mV
155ps     1.336mV    1.253mV    49.87mV
192ps     36.08mV    1.28mV     192.3mV
231ps     185.7mV    12.09mV    279.3mV
262ps     260.5mV    52.55mV    321.2mV
302ps     311.9mV    192.2mV    354mV
332ps     333.6mV    254.2mV    368.7mV
446ps     362.7mV    329.1mV    390.2mV
5ns       370.4mV    347.2mV    397.6mV
[Falling Waveform]
R_fixture= 30.000
V_fixture= 1.100
V_fixture_min= 1.060
V_fixture_max= 1.170
|time   V(typ)   V(min)   V(max)
0s        1.1V       1.06V      1.17V
145ps     1.1V       1.06V      1.169V
190ps     1.092V     1.06V      1.06V
247ps     945.7mV    1.058V     965.8mV
266ps     909.7mV    1.03V      945.5mV
325ps     837mV      871.5mV    904.4mV
377ps     803.7mV    796.9mV    885.3mV
458ps     779.6mV    748mV      871.1mV
586ps     768.1mV    726.5mV    864mV
5ns       764.9mV    720.6mV    861.9mV
[Falling Waveform]
R_fixture= 30.000
V_fixture= 0.0
V_fixture_min= 0.0
V_fixture_max= 0.0
|time   V(typ)   V(min)   V(max)
0s        369.9mV    346.1mV    397.2mV
142ps     369.8mV    346.1mV    397.9mV
185ps     361.8mV    346.1mV    251.3mV
236ps     194.8mV    345.4mV    99.87mV
267ps     114mV      270.3mV    54.59mV
300ps     61.45mV    171.6mV    29.23mV
345ps     26.87mV    83.99mV    13.39mV
395ps     11.56mV    35.45mV    6.622mV
662ps     1.571mV    2.272mV    2.197mV
5ns       839.5uV    1.255mV    1.787mV
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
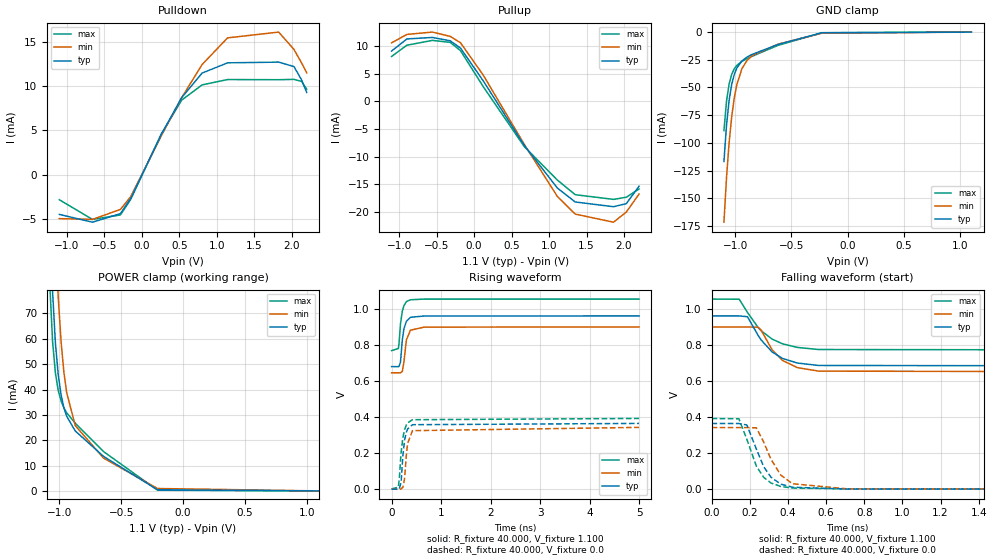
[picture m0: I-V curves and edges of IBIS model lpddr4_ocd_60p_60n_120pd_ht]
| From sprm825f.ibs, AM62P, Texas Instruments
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|   Model lpddr4_ocd_60p_60n_120pd_ht
[Model] lpddr4_ocd_60p_60n_120pd_ht
Model_type I/O
Polarity   Non-Inverting
Enable   Active-High
Vinl =  0.113V
Vinh =  0.253V
Vmeas =  0.183V
C_comp   2.248pF   2.196pF   2.320pF
[Model Spec]
Vinh   0.253V   0.247V   0.265V
Vinl   0.113V   0.107V   0.125V
Vmeas   0.183V   0.176V   0.195V
[Temperature Range]   25.000   0.125k   -40.000
[Voltage Range]   1.100V   1.060V   1.170V
[Pullup Reference]   1.100V   1.060V   1.170V
[Pulldown Reference]   0.0V   0.0V   0.0V
[C Comp Corner]
C_comp   2.248pF   2.196pF   2.320pF
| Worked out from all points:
|   slope of the pulldown table from 0 to 0.165 V, typ, clamps not added: 56.6 ohm
|   slope of the pullup table from 0 to 0.165 V, typ, clamps not added: 49.8 ohm
|   GND clamp passes 1 mA (typ) near -0.26 V on its own axis
|   POWER clamp passes 1 mA (typ) near -0.24 V on its own axis
|   rising waveform, R_fixture 40.000, V_fixture 1.100: 20-80 % time 71.6ps typ, 72.1ps min, 70.4ps max; typ from 0.682 V to 0.963 V
|   rising waveform, R_fixture 40.000, V_fixture 0.0: 20-80 % time 72.3ps typ, 72.9ps min, 86.2ps max; typ from 0.001 V to 0.366 V
|   falling waveform, R_fixture 40.000, V_fixture 1.100: 20-80 % time 135ps typ, 123ps min, 150ps max; typ from 0.963 V to 0.682 V
|   falling waveform, R_fixture 40.000, V_fixture 0.0: 20-80 % time 92.7ps typ, 102ps min, 87.6ps max; typ from 0.366 V to 0.001 V
[Pulldown]
|Voltage   I(typ)   I(min)   I(max)
-1.1V     -4.446mA   -4.919mA   -2.793mA
-658mV    -5.323mA   -5.012mA   -5.008mA
-284mV    -4.362mA   -3.884mA   -4.507mA
-147mV    -2.65mA    -2.442mA   -2.744mA
261mV     4.549mA    4.403mA    4.612mA
533mV     8.705mA    8.699mA    8.418mA
805mV     11.46mA    12.42mA    10.13mA
1.145V    12.61mA    15.42mA    10.73mA
1.826V    12.69mA    16.07mA    10.71mA
2.03V     12.19mA    14.12mA    10.75mA
2.132V    10.68mA    12.59mA    10.52mA
2.2V      9.269mA    11.49mA    9.64mA
[Pullup]
|Voltage   I(typ)   I(min)   I(max)
-1.1V     9.064mA    10.55mA    8.089mA
-896mV    11.25mA    12.07mA    10.12mA
-556mV    11.52mA    12.49mA    10.99mA
-318mV    10.91mA    11.71mA    10.63mA
-181mV    9.596mA    10.56mA    9.131mA
125mV     3.619mA    4.649mA    2.567mA
669mV     -7.994mA   -7.798mA   -8.199mA
1.111V    -15.7mA    -17.23mA   -14.26mA
1.349V    -18.22mA   -20.41mA   -16.9mA
1.86V     -19.07mA   -21.87mA   -17.75mA
2.03V     -18.52mA   -20.04mA   -17.36mA
2.2V      -15.37mA   -16.79mA   -15.87mA
[GND_clamp]
|Voltage   I(typ)   I(min)   I(max)
-1.1V     -116.8mA   -171.6mA   -88.94mA
-1.077V   -83.96mA   -131.3mA   -62.39mA
-1.054V   -61.6mA    -99.87mA   -46.82mA
-1.031V   -47.19mA   -76.34mA   -38.11mA
-1.008V   -38.16mA   -59.32mA   -33.12mA
-985mV    -32.43mA   -47.3mA    -30.04mA
-940mV    -26mA      -32.95mA   -26.37mA
-894mV    -22.48mA   -25.52mA   -23.91mA
-848mV    -20.08mA   -21.13mA   -21.75mA
-619mV    -11.17mA   -10.91mA   -11.97mA
-229mV    -598.7uA   -1.001mA   -573.1uA
1.1V      0A         0A         0A
[POWER_clamp]
|Voltage   I(typ)   I(min)   I(max)
-1.1V     158.5mA    248.7mA    122.8mA
-1.077V   110.5mA    184.5mA    81.81mA
-1.054V   78.43mA    136mA      58.82mA
-1.031V   58.13mA    100.8mA    46.37mA
-1.008V   45.61mA    75.97mA    39.54mA
-985mV    37.81mA    58.74mA    35.43mA
-963mV    32.84mA    46.93mA    32.78mA
-940mV    29.44mA    38.74mA    30.8mA
-871mV    23.65mA    25.79mA    26.71mA
-642mV    13.62mA    12.94mA    15.51mA
-206mV    448.9uA    953.5uA    285.6uA
1.1V      0A         0A         0A
[Ramp]
| variable   typ   min   max
dV/dt_r   0.219/72.259p   0.206/73.091p   0.235/86.126p
dV/dt_f   0.169/0.135n   0.153/0.123n   0.172/0.150n
R_load = 40.000
[Rising Waveform]
R_fixture= 40.000
V_fixture= 1.100
V_fixture_min= 1.060
V_fixture_max= 1.170
|time   V(typ)   V(min)   V(max)
0s        681.9mV    647.3mV    770.5mV
137ps     681.4mV    647.4mV    782.4mV
149ps     682.7mV    647.4mV    806mV
179ps     706.1mV    647mV      918.1mV
216ps     829.4mV    654.9mV    989mV
250ps     893.4mV    710.5mV    1.021V
299ps     933.6mV    830.4mV    1.043V
380ps     955.6mV    884mV      1.053V
658ps     962.9mV    901.2mV    1.057V
5ns       963.4mV    902.1mV    1.057V
[Rising Waveform]
R_fixture= 40.000
V_fixture= 0.0
V_fixture_min= 0.0
V_fixture_max= 0.0
|time   V(typ)   V(min)   V(max)
0s        1.002mV    1.511mV    2.128mV
135ps     967uV      1.505mV    11.9mV
155ps     1.593mV    1.502mV    54.88mV
191ps     38.59mV    1.513mV    202.8mV
229ps     191.4mV    12.34mV    289.1mV
262ps     273.7mV    58.82mV    331.2mV
300ps     319.2mV    198.8mV    358.8mV
325ps     335.7mV    256mV      369.6mV
421ps     359.1mV    326mV      386.8mV
5ns       366.2mV    344.2mV    393.9mV
[Falling Waveform]
R_fixture= 40.000
V_fixture= 1.100
V_fixture_min= 1.060
V_fixture_max= 1.170
|time   V(typ)   V(min)   V(max)
0s        963.4mV    901.9mV    1.057V
145ps     963.3mV    901.9mV    1.056V
188ps     959.1mV    901.9mV    982.9mV
244ps     855mV      900.9mV    898.8mV
260ps     829.5mV    883.7mV    880.9mV
317ps     763.4mV    775.2mV    834.7mV
372ps     727.1mV    715.8mV    808.3mV
450ps     701.5mV    676.1mV    788.3mV
561ps     688.2mV    656.7mV    776.7mV
5ns       681.9mV    647.3mV    770.5mV
[Falling Waveform]
R_fixture= 40.000
V_fixture= 0.0
V_fixture_min= 0.0
V_fixture_max= 0.0
|time   V(typ)   V(min)   V(max)
0s        365.8mV    343.2mV    393.5mV
143ps     365.6mV    343.2mV    392.1mV
185ps     357.5mV    343.1mV    277.7mV
235ps     223.1mV    341.8mV    128.2mV
273ps     126.1mV    262.7mV    66.94mV
311ps     67.32mV    167.3mV    35.38mV
363ps     28.91mV    78.89mV    15.8mV
424ps     11.64mV    31.16mV    7.329mV
713ps     1.751mV    2.508mV    2.537mV
5ns       1.002mV    1.502mV    2.129mV
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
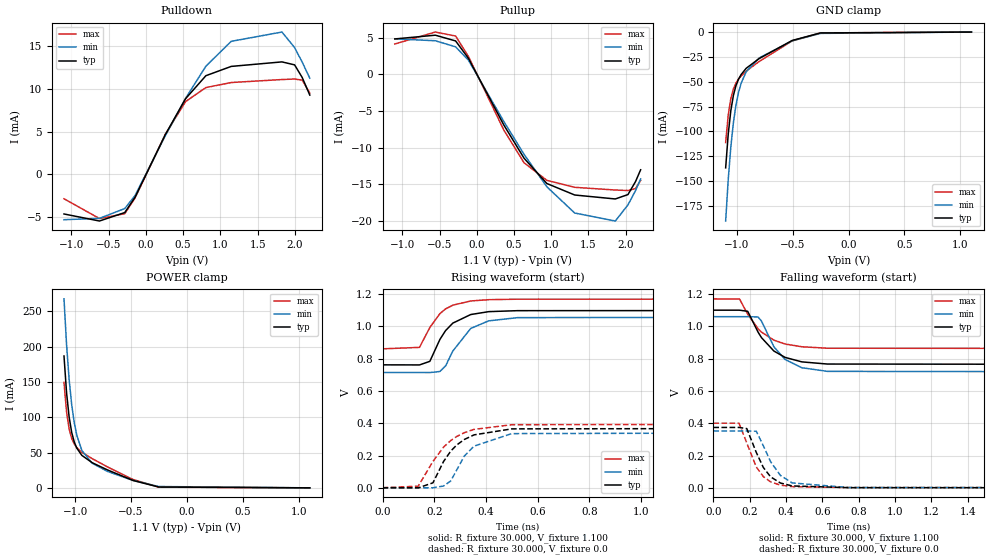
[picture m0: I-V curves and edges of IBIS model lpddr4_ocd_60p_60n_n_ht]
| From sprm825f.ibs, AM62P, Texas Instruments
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|   Model lpddr4_ocd_60p_60n_n_ht
[Model] lpddr4_ocd_60p_60n_n_ht
Model_type I/O
Polarity   Non-Inverting
Enable   Active-High
Vinl =  0.113V
Vinh =  0.253V
Vmeas =  0.183V
C_comp   3.036pF   3.018pF   3.082pF
C_comp_pullup   0.276pF   0.271pF   0.277pF
C_comp_pulldown   1.220pF   1.206pF   1.236pF
[Model Spec]
Vinh   0.253V   0.247V   0.265V
Vinl   0.113V   0.107V   0.125V
Vmeas   0.183V   0.176V   0.195V
[Temperature Range]   25.000   0.125k   -40.000
[Voltage Range]   1.100V   1.060V   1.170V
[Pullup Reference]   1.100V   1.060V   1.170V
[Pulldown Reference]   0.0V   0.0V   0.0V
[C Comp Corner]
C_comp_pullup   0.271pF   0.276pF   0.277pF
C_comp_pulldown   1.220pF   1.206pF   1.236pF
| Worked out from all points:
|   slope of the pulldown table from 0 to 0.165 V, typ, clamps not added: 55.3 ohm
|   slope of the pullup table from 0 to 0.165 V, typ, clamps not added: 51.6 ohm
|   GND clamp passes 1 mA (typ) near -0.26 V on its own axis
|   POWER clamp passes 1 mA (typ) near -0.24 V on its own axis
|   rising waveform, R_fixture 30.000, V_fixture 1.100: 20-80 % time 84.7ps typ, 90.9ps min, 82.2ps max; typ from 0.762 V to 1.1 V
|   rising waveform, R_fixture 30.000, V_fixture 0.0: 20-80 % time 105ps typ, 102ps min, 120ps max; typ from 0.001 V to 0.375 V
|   falling waveform, R_fixture 30.000, V_fixture 1.100: 20-80 % time 141ps typ, 127ps min, 145ps max; typ from 1.1 V to 0.762 V
|   falling waveform, R_fixture 30.000, V_fixture 0.0: 20-80 % time 98.7ps typ, 107ps min, 93.8ps max; typ from 0.375 V to 0.001 V
[Pulldown]
|Voltage   I(typ)   I(min)   I(max)
-1.1V     -4.662mA   -5.333mA   -2.879mA
-624mV    -5.487mA   -5.176mA   -5.197mA
-284mV    -4.493mA   -4.026mA   -4.625mA
-147mV    -2.717mA   -2.518mA   -2.805mA
261mV     4.65mA     4.521mA    4.697mA
533mV     8.86mA     8.913mA    8.517mA
805mV     11.55mA    12.66mA    10.16mA
1.145V    12.64mA    15.58mA    10.75mA
1.826V    13.17mA    16.67mA    11.1mA
1.996V    12.82mA    14.85mA    11.16mA
2.098V    11.34mA    13.14mA    11.03mA
2.2V      9.276mA    11.26mA    9.525mA
[Pullup]
|Voltage   I(typ)   I(min)   I(max)
-1.1V     4.852mA    4.863mA    4.161mA
-556mV    5.364mA    4.606mA    5.795mA
-284mV    4.579mA    3.774mA    5.248mA
-113mV    2.225mA    1.973mA    2.483mA
363mV     -6.889mA   -6.408mA   -7.581mA
635mV     -11.43mA   -10.9mA    -12.05mA
941mV     -14.88mA   -15.33mA   -14.45mA
1.315V    -16.45mA   -18.91mA   -15.4mA
1.86V     -16.99mA   -20mA      -15.77mA
2.03V     -16.39mA   -17.8mA    -15.84mA
2.132V    -14.61mA   -15.84mA   -15.57mA
2.2V      -13.01mA   -14.26mA   -14.46mA
[GND_clamp]
|Voltage   I(typ)   I(min)   I(max)
-1.1V     -136.6mA   -190.1mA   -111.1mA
-1.077V   -102.6mA   -148.4mA   -83.57mA
-1.054V   -79.22mA   -115.9mA   -67.05mA
-1.031V   -63.93mA   -91.43mA   -57.36mA
-1.008V   -54.04mA   -73.6mA    -51.37mA
-985mV    -47.47mA   -60.82mA   -47.28mA
-962mV    -42.85mA   -51.68mA   -44.18mA
-917mV    -36.56mA   -40.08mA   -39.42mA
-802mV    -26.83mA   -26.21mA   -29.77mA
-504mV    -8.458mA   -8.847mA   -8.902mA
-252mV    -923uA     -1.37mA    -917.2uA
1.1V      0A         0A         0A
[POWER_clamp]
|Voltage   I(typ)   I(min)   I(max)
-1.1V     186.7mA    267.6mA    149.4mA
-1.077V   134.7mA    202.8mA    107.4mA
-1.054V   100.3mA    153.6mA    83.44mA
-1.031V   78.51mA    117.7mA    69.97mA
-1.008V   64.87mA    92.18mA    62.12mA
-985mV    56.1mA     74.26mA    56.97mA
-940mV    45.96mA    52.89mA    50.3mA
-848mV    35.63mA    34.9mA     41.42mA
-710mV    25.31mA    23.21mA    29.58mA
-481mV    10.42mA    10.4mA     11.78mA
-252mV    1.166mA    1.865mA    981uA
1.1V      0A         0A         0A
[Ramp]
| variable   typ   min   max
dV/dt_r   0.236/85.778p   0.221/94.351p   0.256/83.872p
dV/dt_f   0.235/0.167n   0.221/0.167n   0.256/0.177n
R_load = 30.000
[Rising Waveform]
R_fixture= 30.000
V_fixture= 1.100
V_fixture_min= 1.060
V_fixture_max= 1.170
|time   V(typ)   V(min)   V(max)
0s        761.8mV    714.3mV    860.8mV
143ps     761.3mV    714.3mV    869.9mV
183ps     783.5mV    713.9mV    992.7mV
222ps     919.1mV    720.8mV    1.079V
244ps     974mV      755.4mV    1.108V
272ps     1.02V      847.3mV    1.131V
341ps     1.073V     986.8mV    1.157V
411ps     1.091V     1.034V     1.165V
523ps     1.097V     1.054V     1.168V
5ns       1.1V       1.06V      1.17V
[Rising Waveform]
R_fixture= 30.000
V_fixture= 0.0
V_fixture_min= 0.0
V_fixture_max= 0.0
|time   V(typ)   V(min)   V(max)
0s        850uV      1.28mV     1.802mV
138ps     796uV      1.275mV    11.06mV
195ps     31.84mV    1.287mV    164.2mV
236ps     163.6mV    12.19mV    252.7mV
264ps     228.4mV    43.46mV    293.6mV
287ps     265.9mV    111.4mV    318.6mV
316ps     299.7mV    196.8mV    341.9mV
354ps     328.5mV    258.8mV    362.4mV
500ps     365.7mV    336.4mV    391.4mV
5ns       374.8mV    353.3mV    400.8mV
[Falling Waveform]
R_fixture= 30.000
V_fixture= 1.100
V_fixture_min= 1.060
V_fixture_max= 1.170
|time   V(typ)   V(min)   V(max)
0s        1.1V       1.06V      1.17V
144ps     1.1V       1.06V      1.169V
189ps     1.093V     1.06V      1.075V
246ps     964.2mV    1.058V     985mV
265ps     929.9mV    1.032V     964.3mV
333ps     847.4mV    873.6mV    914.6mV
395ps     807.7mV    794.5mV    890.6mV
487ps     780.2mV    743.9mV    873.6mV
627ps     766.8mV    721.5mV    864.7mV
5ns       761.8mV    714.4mV    860.8mV
[Falling Waveform]
R_fixture= 30.000
V_fixture= 0.0
V_fixture_min= 0.0
V_fixture_max= 0.0
|time   V(typ)   V(min)   V(max)
0s        374.5mV    352.7mV    400.8mV
141ps     374.5mV    352.7mV    401.1mV
184ps     367.4mV    352.7mV    278mV
236ps     220.5mV    351.2mV    130.4mV
275ps     126.8mV    261.3mV    70.39mV
315ps     68.93mV    162.5mV    37.94mV
369ps     30.79mV    77.61mV    17.61mV
434ps     12.69mV    31.2mV     8.343mV
744ps     2.059mV    2.698mV    2.784mV
5ns       857.8uV    1.339mV    1.807mV
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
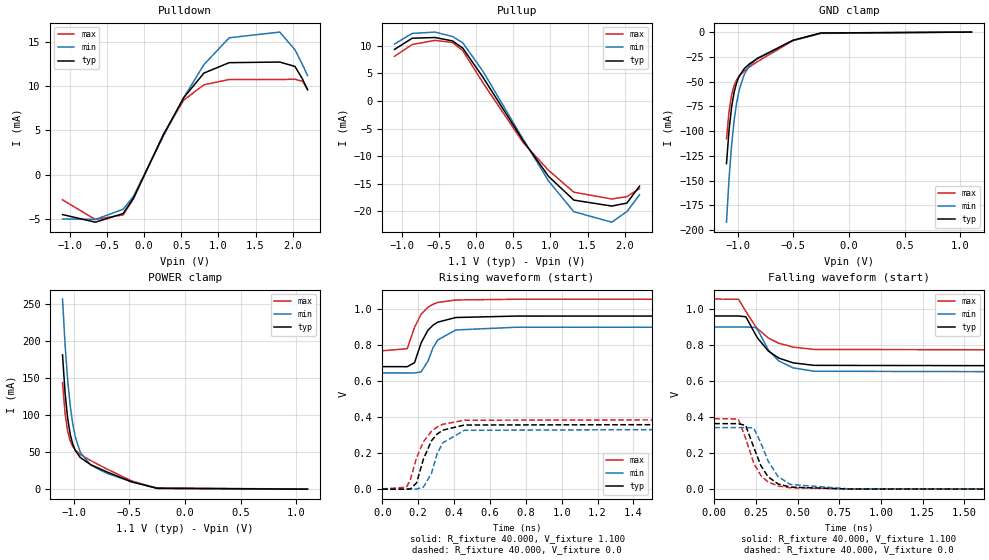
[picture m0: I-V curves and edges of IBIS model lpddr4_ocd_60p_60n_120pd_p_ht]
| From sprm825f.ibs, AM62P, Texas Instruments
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|   Model lpddr4_ocd_60p_60n_120pd_p_ht
[Model] lpddr4_ocd_60p_60n_120pd_p_ht
Model_type I/O
Polarity   Non-Inverting
Enable   Active-High
Vinl =  0.113V
Vinh =  0.253V
Vmeas =  0.183V
C_comp   2.501pF   2.444pF   2.627pF
C_comp_pullup   0.222pF   0.220pF   0.241pF
C_comp_pulldown   1.010pF   0.984pF   1.054pF
[Model Spec]
Vinh   0.253V   0.247V   0.265V
Vinl   0.113V   0.107V   0.125V
Vmeas   0.183V   0.176V   0.195V
[Temperature Range]   25.000   0.125k   -40.000
[Voltage Range]   1.100V   1.060V   1.170V
[Pullup Reference]   1.100V   1.060V   1.170V
[Pulldown Reference]   0.0V   0.0V   0.0V
[C Comp Corner]
C_comp_pullup   0.222pF   0.220pF   0.241pF
C_comp_pulldown   1.010pF   0.984pF   1.054pF
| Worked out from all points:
|   slope of the pulldown table from 0 to 0.165 V, typ, clamps not added: 56.7 ohm
|   slope of the pullup table from 0 to 0.165 V, typ, clamps not added: 50 ohm
|   GND clamp passes 1 mA (typ) near -0.26 V on its own axis
|   POWER clamp passes 1 mA (typ) near -0.24 V on its own axis
|   rising waveform, R_fixture 40.000, V_fixture 1.100: 20-80 % time 82.6ps typ, 81.5ps min, 81.3ps max; typ from 0.682 V to 0.963 V
|   rising waveform, R_fixture 40.000, V_fixture 0.0: 20-80 % time 86.2ps typ, 82.8ps min, 101ps max; typ from 0.001 V to 0.365 V
|   falling waveform, R_fixture 40.000, V_fixture 1.100: 20-80 % time 149ps typ, 133ps min, 167ps max; typ from 0.963 V to 0.682 V
|   falling waveform, R_fixture 40.000, V_fixture 0.0: 20-80 % time 102ps typ, 112ps min, 97.7ps max; typ from 0.365 V to 0.001 V
[Pulldown]
|Voltage   I(typ)   I(min)   I(max)
-1.1V     -4.465mA   -4.958mA   -2.813mA
-658mV    -5.322mA   -5.009mA   -5.016mA
-284mV    -4.35mA    -3.873mA   -4.5mA
-147mV    -2.645mA   -2.437mA   -2.741mA
261mV     4.542mA    4.396mA    4.609mA
533mV     8.695mA    8.688mA    8.416mA
805mV     11.45mA    12.41mA    10.13mA
1.145V    12.62mA    15.42mA    10.73mA
1.826V    12.69mA    16.06mA    10.72mA
2.03V     12.2mA     14.08mA    10.76mA
2.132V    10.78mA    12.41mA    10.53mA
2.2V      9.575mA    11.17mA    9.655mA
[Pullup]
|Voltage   I(typ)   I(min)   I(max)
-1.1V     9.331mA    10.3mA     8.089mA
-862mV    11.36mA    12.23mA    10.22mA
-556mV    11.49mA    12.47mA    10.97mA
-318mV    10.87mA    11.67mA    10.59mA
-181mV    9.57mA     10.53mA    9.109mA
90.72mV   4.302mA    5.379mA    3.299mA
635mV     -7.226mA   -6.993mA   -7.577mA
975mV     -13.66mA   -14.49mA   -12.56mA
1.315V    -17.95mA   -20.05mA   -16.52mA
1.826V    -19.03mA   -21.95mA   -17.75mA
2.03V     -18.49mA   -20.03mA   -17.33mA
2.2V      -15.42mA   -16.99mA   -15.86mA
[GND_clamp]
|Voltage   I(typ)   I(min)   I(max)
-1.1V     -132.9mA   -192.1mA   -107.9mA
-1.077V   -98.86mA   -148mA     -79.9mA
-1.054V   -75.63mA   -114.1mA   -63.35mA
-1.031V   -60.5mA    -88.93mA   -53.84mA
-1.008V   -50.81mA   -70.83mA   -48.11mA
-985mV    -44.46mA   -58.02mA   -44.3mA
-940mV    -36.83mA   -42.48mA   -39.19mA
-894mV    -32.12mA   -34.02mA   -35.3mA
-825mV    -26.95mA   -26.56mA   -29.98mA
-504mV    -8.258mA   -8.592mA   -8.733mA
-252mV    -912.8uA   -1.351mA   -908.2uA
1.1V      0A         0A         0A
[POWER_clamp]
|Voltage   I(typ)   I(min)   I(max)
-1.1V     181.7mA    257.3mA    143.9mA
-1.077V   130mA      195.2mA    102.2mA
-1.054V   95.89mA    147.8mA    78.5mA
-1.031V   74.31mA    112.9mA    65.32mA
-1.008V   60.91mA    88.11mA    57.78mA
-985mV    52.38mA    70.63mA    52.94mA
-940mV    42.73mA    49.84mA    46.89mA
-848mV    33.32mA    32.69mA    38.81mA
-710mV    23.85mA    21.95mA    27.87mA
-481mV    10mA       9.999mA    11.31mA
-252mV    1.151mA    1.835mA    969.3uA
1.1V      0A         0A         0A
[Ramp]
| variable   typ   min   max
dV/dt_r   0.204/64.725p   0.186/67.193p   0.233/76.545p
dV/dt_f   0.204/0.144n   0.186/0.149n   0.233/0.138n
R_load = 40.000
[Rising Waveform]
R_fixture= 40.000
V_fixture= 1.100
V_fixture_min= 1.060
V_fixture_max= 1.170
|time   V(typ)   V(min)   V(max)
0s        681.8mV    646.7mV    769.8mV
139ps     681.3mV    646.7mV    781.1mV
180ps     703.8mV    646.4mV    900.3mV
217ps     814.7mV    653.1mV    973.4mV
255ps     884.4mV    712.5mV    1.012V
283ps     912.1mV    787.1mV    1.028V
309ps     928.6mV    829.6mV    1.038V
410ps     954.6mV    885.3mV    1.052V
751ps     962.5mV    900.6mV    1.056V
5ns       963.1mV    901.6mV    1.057V
[Rising Waveform]
R_fixture= 40.000
V_fixture= 0.0
V_fixture_min= 0.0
V_fixture_max= 0.0
|time   V(typ)   V(min)   V(max)
0s        1.001mV    1.51mV     2.122mV
135ps     958.1uV    1.509mV    12.02mV
157ps     2.348mV    1.508mV    54.57mV
191ps     35.46mV    1.523mV    175.4mV
229ps     166.6mV    12.13mV    263.6mV
274ps     269.5mV    87.88mV    322.3mV
306ps     307.1mV    198.2mV    346.5mV
337ps     328.7mV    258.1mV    361.4mV
458ps     357.3mV    328mV      384mV
5ns       365.4mV    343.8mV    392.5mV
[Falling Waveform]
R_fixture= 40.000
V_fixture= 1.100
V_fixture_min= 1.060
V_fixture_max= 1.170
|time   V(typ)   V(min)   V(max)
0s        963.1mV    901.6mV    1.057V
146ps     963mV      901.6mV    1.056V
190ps     958.4mV    901.5mV    987.4mV
246ps     862.1mV    900.1mV    907.9mV
262ps     837.8mV    883.6mV    890.5mV
325ps     767.7mV    773.5mV    840.5mV
386ps     729.5mV    713.7mV    812mV
473ps     702.7mV    674.7mV    790.1mV
599ps     688.7mV    656mV      777.1mV
5ns       681.8mV    646.8mV    769.8mV
[Falling Waveform]
R_fixture= 40.000
V_fixture= 0.0
V_fixture_min= 0.0
V_fixture_max= 0.0
|time   V(typ)   V(min)   V(max)
0s        365.1mV    343mV      392.4mV
144ps     364.9mV    343mV      390.8mV
188ps     355.2mV    342.9mV    283.8mV
237ps     233.8mV    341.1mV    145mV
279ps     132.7mV    258.2mV    77.31mV
323ps     69.72mV    157.6mV    40.92mV
382ps     30.47mV    71.73mV    18.9mV
455ps     12.38mV    27.25mV    8.768mV
808ps     1.861mV    2.702mV    2.586mV
5ns       1.007mV    1.536mV    2.128mV
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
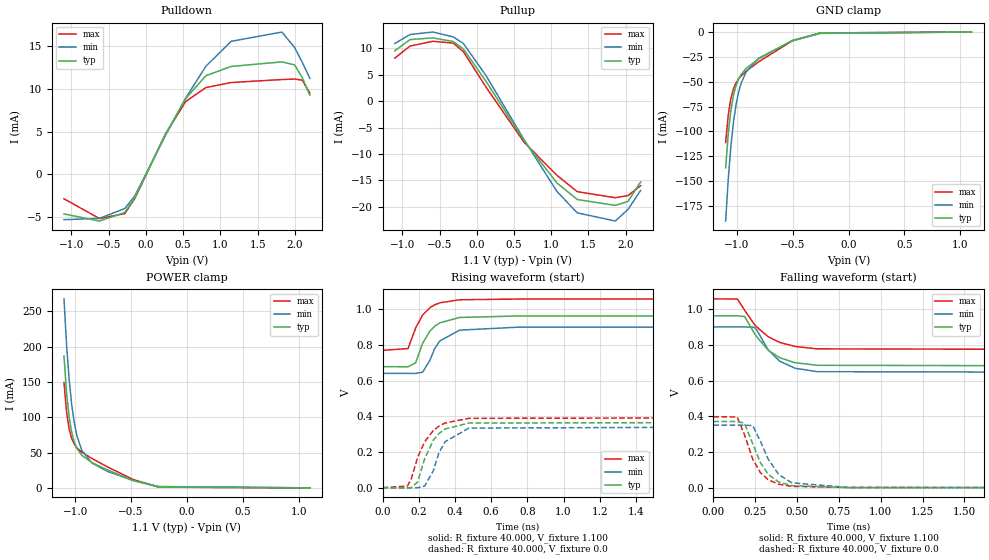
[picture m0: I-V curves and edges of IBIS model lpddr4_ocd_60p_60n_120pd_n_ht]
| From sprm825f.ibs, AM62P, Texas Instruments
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|   Model lpddr4_ocd_60p_60n_120pd_n_ht
[Model] lpddr4_ocd_60p_60n_120pd_n_ht
Model_type I/O
Polarity   Non-Inverting
Enable   Active-High
Vinl =  0.113V
Vinh =  0.253V
Vmeas =  0.183V
C_comp   2.882pF   2.852pF   2.980pF
C_comp_pullup   0.264pF   0.261pF   0.276pF
C_comp_pulldown   1.154pF   1.136pF   1.187pF
[Model Spec]
Vinh   0.253V   0.247V   0.265V
Vinl   0.113V   0.107V   0.125V
Vmeas   0.183V   0.176V   0.195V
[Temperature Range]   25.000   0.125k   -40.000
[Voltage Range]   1.100V   1.060V   1.170V
[Pullup Reference]   1.100V   1.060V   1.170V
[Pulldown Reference]   0.0V   0.0V   0.0V
[C Comp Corner]
C_comp_pullup   0.261pF   0.264pF   0.276pF
C_comp_pulldown   1.154pF   1.136pF   1.187pF
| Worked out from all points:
|   slope of the pulldown table from 0 to 0.165 V, typ, clamps not added: 55.3 ohm
|   slope of the pullup table from 0 to 0.165 V, typ, clamps not added: 48.5 ohm
|   GND clamp passes 1 mA (typ) near -0.26 V on its own axis
|   POWER clamp passes 1 mA (typ) near -0.24 V on its own axis
|   rising waveform, R_fixture 40.000, V_fixture 1.100: 20-80 % time 92.8ps typ, 92.3ps min, 90.2ps max; typ from 0.678 V to 0.961 V
|   rising waveform, R_fixture 40.000, V_fixture 0.0: 20-80 % time 95.8ps typ, 92.4ps min, 111ps max; typ from 0.001 V to 0.371 V
|   falling waveform, R_fixture 40.000, V_fixture 1.100: 20-80 % time 162ps typ, 146ps min, 180ps max; typ from 0.961 V to 0.678 V
|   falling waveform, R_fixture 40.000, V_fixture 0.0: 20-80 % time 112ps typ, 122ps min, 106ps max; typ from 0.371 V to 0.001 V
[Pulldown]
|Voltage   I(typ)   I(min)   I(max)
-1.1V     -4.662mA   -5.333mA   -2.879mA
-624mV    -5.486mA   -5.176mA   -5.197mA
-284mV    -4.493mA   -4.026mA   -4.625mA
-147mV    -2.717mA   -2.518mA   -2.805mA
261mV     4.65mA     4.521mA    4.697mA
533mV     8.86mA     8.913mA    8.517mA
805mV     11.55mA    12.66mA    10.16mA
1.145V    12.64mA    15.58mA    10.75mA
1.826V    13.17mA    16.67mA    11.1mA
1.996V    12.82mA    14.85mA    11.16mA
2.098V    11.34mA    13.14mA    11.03mA
2.2V      9.276mA    11.26mA    9.525mA
[Pullup]
|Voltage   I(typ)   I(min)   I(max)
-1.1V     9.492mA    10.86mA    8.104mA
-896mV    11.6mA     12.56mA    10.38mA
-590mV    11.93mA    13.03mA    11.28mA
-318mV    11.24mA    12.12mA    10.94mA
-181mV    9.847mA    10.9mA     9.353mA
125mV     3.7mA      4.786mA    2.615mA
635mV     -7.477mA   -7.286mA   -7.78mA
1.077V    -15.48mA   -17.08mA   -14.04mA
1.349V    -18.6mA    -21.12mA   -17.12mA
1.86V     -19.71mA   -22.66mA   -18.26mA
2.03V     -18.96mA   -20.48mA   -17.86mA
2.2V      -15.28mA   -16.88mA   -15.99mA
[GND_clamp]
|Voltage   I(typ)   I(min)   I(max)
-1.1V     -136.6mA   -190.1mA   -111.1mA
-1.077V   -102.6mA   -148.4mA   -83.57mA
-1.054V   -79.22mA   -115.9mA   -67.05mA
-1.031V   -63.93mA   -91.43mA   -57.36mA
-1.008V   -54.04mA   -73.6mA    -51.37mA
-985mV    -47.47mA   -60.82mA   -47.28mA
-962mV    -42.85mA   -51.68mA   -44.18mA
-917mV    -36.56mA   -40.08mA   -39.42mA
-802mV    -26.83mA   -26.21mA   -29.77mA
-504mV    -8.458mA   -8.847mA   -8.902mA
-252mV    -923uA     -1.37mA    -917.2uA
1.1V      0A         0A         0A
[POWER_clamp]
|Voltage   I(typ)   I(min)   I(max)
-1.1V     186.7mA    267.6mA    149.4mA
-1.077V   134.7mA    202.8mA    107.4mA
-1.054V   100.3mA    153.6mA    83.44mA
-1.031V   78.51mA    117.7mA    69.97mA
-1.008V   64.87mA    92.18mA    62.12mA
-985mV    56.1mA     74.26mA    56.97mA
-940mV    45.96mA    52.89mA    50.3mA
-848mV    35.63mA    34.9mA     41.42mA
-710mV    25.31mA    23.21mA    29.58mA
-481mV    10.42mA    10.4mA     11.78mA
-252mV    1.166mA    1.865mA    981uA
1.1V      0A         0A         0A
[Ramp]
| variable   typ   min   max
dV/dt_r   0.212/79.827p   0.195/83.761p   0.242/93.343p
dV/dt_f   0.212/0.171n   0.195/0.180n   0.242/0.166n
R_load = 40.000
[Rising Waveform]
R_fixture= 40.000
V_fixture= 1.100
V_fixture_min= 1.060
V_fixture_max= 1.170
|time   V(typ)   V(min)   V(max)
0s        677.6mV    640.1mV    768.6mV
141ps     677.1mV    640.1mV    778.5mV
183ps     699.1mV    639.8mV    893.6mV
221ps     807mV      646.3mV    964.9mV
262ps     876.9mV    713.4mV    1.007V
288ps     902.9mV    777.9mV    1.023V
317ps     922.3mV    821.5mV    1.034V
426ps     952.2mV    881.4mV    1.051V
747ps     960.5mV    897.8mV    1.055V
5ns       961.4mV    899mV      1.056V
[Rising Waveform]
R_fixture= 40.000
V_fixture= 0.0
V_fixture_min= 0.0
V_fixture_max= 0.0
|time   V(typ)   V(min)   V(max)
0s        1.013mV    1.529mV    2.144mV
137ps     953.1uV    1.524mV    10.94mV
158ps     1.751mV    1.52mV     48.72mV
194ps     33.69mV    1.521mV    171.6mV
233ps     164.5mV    11.64mV    258.6mV
281ps     267.6mV    97.24mV    321.3mV
311ps     303.4mV    195.4mV    345mV
346ps     329.6mV    258.8mV    363.1mV
477ps     362.8mV    334.5mV    388.9mV
5ns       371.5mV    351.3mV    398.2mV
[Falling Waveform]
R_fixture= 40.000
V_fixture= 1.100
V_fixture_min= 1.060
V_fixture_max= 1.170
|time   V(typ)   V(min)   V(max)
0s        961.5mV    899.1mV    1.056V
144ps     961.4mV    899.1mV    1.055V
187ps     957.4mV    899.1mV    992.3mV
243ps     867.7mV    898mV      916.1mV
258ps     845.8mV    884.1mV    899.9mV
328ps     769.4mV    770.8mV    844.3mV
396ps     727.7mV    708.2mV    812.9mV
488ps     699.8mV    668.8mV    790.3mV
620ps     685.1mV    649.7mV    776.9mV
5ns       677.6mV    640.3mV    768.7mV
[Falling Waveform]
R_fixture= 40.000
V_fixture= 0.0
V_fixture_min= 0.0
V_fixture_max= 0.0
|time   V(typ)   V(min)   V(max)
0s        371.3mV    350.9mV    398.2mV
142ps     371.2mV    350.9mV    396.6mV
185ps     362.7mV    350.8mV    299.9mV
235ps     247.9mV    348.9mV    162mV
281ps     141.7mV    261.7mV    86.36mV
328ps     76.02mV    160.8mV    45.81mV
391ps     33.49mV    74.92mV    20.85mV
469ps     13.3mV     29.13mV    9.479mV
808ps     2.308mV    3.064mV    3.187mV
5ns       1.025mV    1.633mV    2.152mV
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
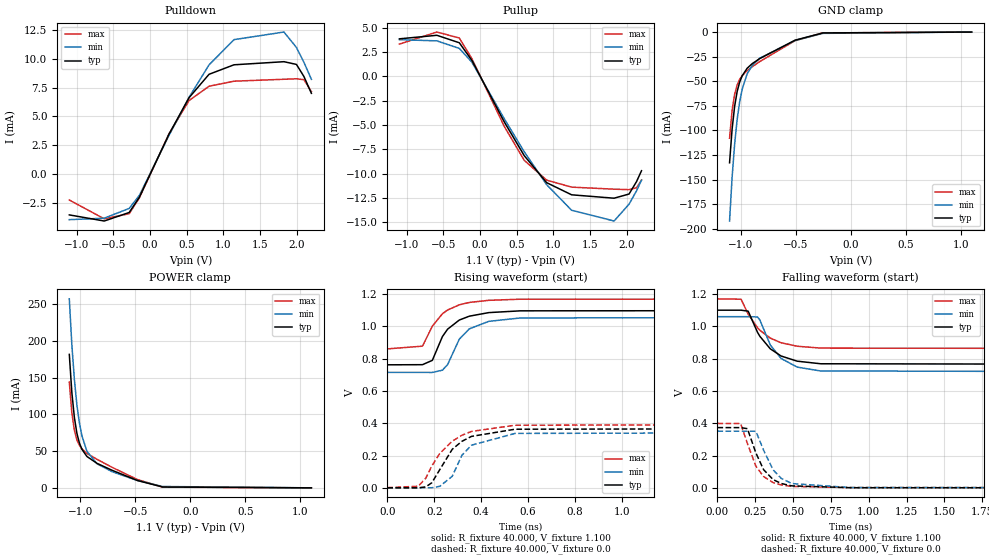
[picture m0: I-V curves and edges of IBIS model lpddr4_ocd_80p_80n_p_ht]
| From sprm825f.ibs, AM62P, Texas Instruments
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|   Model lpddr4_ocd_80p_80n_p_ht
[Model] lpddr4_ocd_80p_80n_p_ht
Model_type I/O
Polarity   Non-Inverting
Enable   Active-High
Vinl =  0.113V
Vinh =  0.253V
Vmeas =  0.183V
C_comp   2.875pF   2.850pF   2.914pF
C_comp_pullup   0.267pF   0.267pF   0.274pF
C_comp_pulldown   1.150pF   1.137pF   1.162pF
[Model Spec]
Vinh   0.253V   0.247V   0.265V
Vinl   0.113V   0.107V   0.125V
Vmeas   0.183V   0.176V   0.195V
[Temperature Range]   25.000   0.125k   -40.000
[Voltage Range]   1.100V   1.060V   1.170V
[Pullup Reference]   1.100V   1.060V   1.170V
[Pulldown Reference]   0.0V   0.0V   0.0V
[C Comp Corner]
C_comp_pullup   0.267pF   0.267pF   0.274pF
C_comp_pulldown   1.150pF   1.137pF   1.162pF
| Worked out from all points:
|   slope of the pulldown table from 0 to 0.165 V, typ, clamps not added: 73.9 ohm
|   slope of the pullup table from 0 to 0.165 V, typ, clamps not added: 69.2 ohm
|   GND clamp passes 1 mA (typ) near -0.26 V on its own axis
|   POWER clamp passes 1 mA (typ) near -0.24 V on its own axis
|   rising waveform, R_fixture 40.000, V_fixture 1.100: 20-80 % time 94.3ps typ, 92.5ps min, 97.7ps max; typ from 0.762 V to 1.1 V
|   rising waveform, R_fixture 40.000, V_fixture 0.0: 20-80 % time 117ps typ, 102ps min, 138ps max; typ from 0.001 V to 0.374 V
|   falling waveform, R_fixture 40.000, V_fixture 1.100: 20-80 % time 165ps typ, 145ps min, 173ps max; typ from 1.1 V to 0.762 V
|   falling waveform, R_fixture 40.000, V_fixture 0.0: 20-80 % time 112ps typ, 119ps min, 109ps max; typ from 0.374 V to 0.001 V
[Pulldown]
|Voltage   I(typ)   I(min)   I(max)
-1.1V     -3.55mA    -3.963mA   -2.257mA
-624mV    -4.081mA   -3.837mA   -3.89mA
-284mV    -3.342mA   -2.988mA   -3.446mA
-147mV    -2.032mA   -1.879mA   -2.1mA
261mV     3.481mA    3.381mA    3.519mA
533mV     6.635mA    6.667mA    6.384mA
805mV     8.661mA    9.479mA    7.624mA
1.145V    9.485mA    11.67mA    8.061mA
1.826V    9.754mA    12.33mA    8.229mA
1.996V    9.518mA    10.99mA    8.27mA
2.098V    8.47mA     9.704mA    8.192mA
2.2V      7.007mA    8.222mA    7.157mA
[Pullup]
|Voltage   I(typ)   I(min)   I(max)
-1.1V     3.878mA    3.791mA    3.337mA
-590mV    4.241mA    3.668mA    4.578mA
-284mV    3.474mA    2.891mA    3.963mA
-113mV    1.662mA    1.483mA    1.847mA
329mV     -4.679mA   -4.354mA   -5.14mA
601mV     -8.155mA   -7.754mA   -8.638mA
907mV     -10.94mA   -11.15mA   -10.68mA
1.247V    -12.19mA   -13.78mA   -11.4mA
1.826V    -12.54mA   -14.89mA   -11.61mA
2.03V     -12.11mA   -13.16mA   -11.66mA
2.132V    -10.83mA   -11.78mA   -11.47mA
2.2V      -9.708mA   -10.68mA   -10.67mA
[GND_clamp]
|Voltage   I(typ)   I(min)   I(max)
-1.1V     -132.9mA   -192.1mA   -107.9mA
-1.077V   -98.86mA   -148mA     -79.9mA
-1.054V   -75.63mA   -114.1mA   -63.35mA
-1.031V   -60.5mA    -88.93mA   -53.84mA
-1.008V   -50.81mA   -70.83mA   -48.11mA
-985mV    -44.46mA   -58.02mA   -44.3mA
-940mV    -36.83mA   -42.48mA   -39.19mA
-894mV    -32.12mA   -34.02mA   -35.3mA
-825mV    -26.95mA   -26.56mA   -29.98mA
-504mV    -8.258mA   -8.592mA   -8.733mA
-252mV    -912.8uA   -1.351mA   -908.3uA
1.1V      0A         0A         0A
[POWER_clamp]
|Voltage   I(typ)   I(min)   I(max)
-1.1V     181.7mA    257.3mA    143.9mA
-1.077V   130mA      195.2mA    102.2mA
-1.054V   95.89mA    147.8mA    78.5mA
-1.031V   74.31mA    112.9mA    65.33mA
-1.008V   60.91mA    88.11mA    57.78mA
-985mV    52.38mA    70.63mA    52.94mA
-940mV    42.73mA    49.84mA    46.89mA
-848mV    33.32mA    32.69mA    38.81mA
-710mV    23.85mA    21.95mA    27.87mA
-481mV    10mA       9.999mA    11.31mA
-252mV    1.151mA    1.835mA    969.3uA
1.1V      0A         0A         0A
[Ramp]
| variable   typ   min   max
dV/dt_r   0.230/80.319p   0.215/72.798p   0.251/87.678p
dV/dt_f   0.230/0.177n   0.215/0.182n   0.251/0.185n
R_load = 40.000
[Rising Waveform]
R_fixture= 40.000
V_fixture= 1.100
V_fixture_min= 1.060
V_fixture_max= 1.170
|time   V(typ)   V(min)   V(max)
0s        762.1mV    715.1mV    860.5mV
150ps     762.9mV    715.2mV    877.5mV
192ps     789.7mV    714.9mV    1.001V
235ps     936.7mV    728.8mV    1.078V
257ps     982.4mV    763.2mV    1.101V
307ps     1.039V     920.6mV    1.133V
350ps     1.063V     984.8mV    1.148V
433ps     1.085V     1.031V     1.161V
568ps     1.096V     1.052V     1.168V
5ns       1.1V       1.06V      1.17V
[Rising Waveform]
R_fixture= 40.000
V_fixture= 0.0
V_fixture_min= 0.0
V_fixture_max= 0.0
|time   V(typ)   V(min)   V(max)
0s        1.126mV    1.689mV    2.392mV
132ps     1.065mV    1.687mV    10.88mV
164ps     7.084mV    1.681mV    60.84mV
190ps     32.74mV    1.622mV    137.2mV
224ps     114.3mV    10.56mV    214.1mV
277ps     239.7mV    72.78mV    290mV
318ps     288.8mV    202.3mV    326.4mV
359ps     319.4mV    265.1mV    350.1mV
545ps     363.7mV    337.7mV    388.5mV
5ns       374.1mV    352.7mV    399.7mV
[Falling Waveform]
R_fixture= 40.000
V_fixture= 1.100
V_fixture_min= 1.060
V_fixture_max= 1.170
|time   V(typ)   V(min)   V(max)
0s        1.1V       1.06V      1.17V
156ps     1.1V       1.06V      1.168V
203ps     1.094V     1.06V      1.076V
265ps     962.8mV    1.058V     991.2mV
281ps     937.5mV    1.038V     975.5mV
349ps     861.2mV    885.1mV    927.3mV
421ps     816.4mV    801.1mV    898.3mV
527ps     784.6mV    747.9mV    877mV
682ps     768.6mV    724.1mV    865.5mV
5ns       762.1mV    715.3mV    860.5mV
[Falling Waveform]
R_fixture= 40.000
V_fixture= 0.0
V_fixture_min= 0.0
V_fixture_max= 0.0
|time   V(typ)   V(min)   V(max)
0s        373.8mV    351.9mV    399.6mV
153ps     373.6mV    351.9mV    399.2mV
198ps     367.3mV    351.8mV    275.3mV
254ps     217mV      351mV      135.1mV
305ps     113.6mV    234mV      70.96mV
368ps     52.11mV    112.4mV    33.52mV
422ps     27.88mV    59.41mV    18.73mV
492ps     13.39mV    27.61mV    9.914mV
880ps     1.95mV     2.894mV    2.817mV
5ns       1.132mV    1.716mV    2.397mV
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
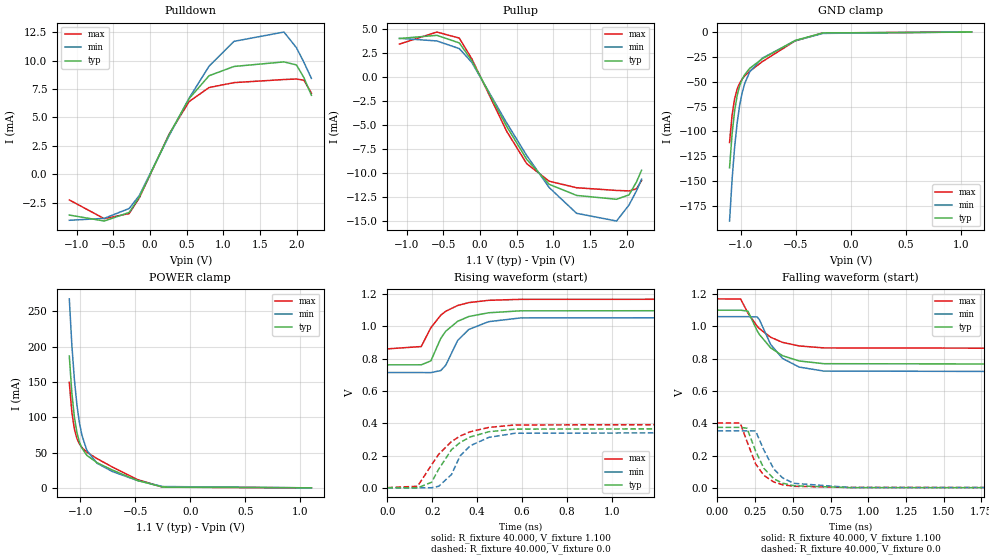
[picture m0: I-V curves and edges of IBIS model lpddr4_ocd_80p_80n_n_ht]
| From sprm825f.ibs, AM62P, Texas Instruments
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|   Model lpddr4_ocd_80p_80n_n_ht
[Model] lpddr4_ocd_80p_80n_n_ht
Model_type I/O
Polarity   Non-Inverting
Enable   Active-High
Vinl =  0.113V
Vinh =  0.253V
Vmeas =  0.183V
C_comp   3.217pF   3.216pF   3.235pF
C_comp_pullup   0.305pF   0.301pF   0.306pF
C_comp_pulldown   1.279pF   1.273pF   1.283pF
[Model Spec]
Vinh   0.253V   0.247V   0.265V
Vinl   0.113V   0.107V   0.125V
Vmeas   0.183V   0.176V   0.195V
[Temperature Range]   25.000   0.125k   -40.000
[Voltage Range]   1.100V   1.060V   1.170V
[Pullup Reference]   1.100V   1.060V   1.170V
[Pulldown Reference]   0.0V   0.0V   0.0V
[C Comp Corner]
C_comp_pullup   0.301pF   0.306pF   0.305pF
C_comp_pulldown   1.279pF   1.273pF   1.283pF
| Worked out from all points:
|   slope of the pulldown table from 0 to 0.165 V, typ, clamps not added: 73.7 ohm
|   slope of the pullup table from 0 to 0.165 V, typ, clamps not added: 68.8 ohm
|   GND clamp passes 1 mA (typ) near -0.26 V on its own axis
|   POWER clamp passes 1 mA (typ) near -0.24 V on its own axis
|   rising waveform, R_fixture 40.000, V_fixture 1.100: 20-80 % time 106ps typ, 106ps min, 107ps max; typ from 0.762 V to 1.1 V
|   rising waveform, R_fixture 40.000, V_fixture 0.0: 20-80 % time 130ps typ, 114ps min, 150ps max; typ from 0.001 V to 0.375 V
|   falling waveform, R_fixture 40.000, V_fixture 1.100: 20-80 % time 178ps typ, 158ps min, 186ps max; typ from 1.1 V to 0.762 V
|   falling waveform, R_fixture 40.000, V_fixture 0.0: 20-80 % time 122ps typ, 131ps min, 119ps max; typ from 0.375 V to 0.001 V
[Pulldown]
|Voltage   I(typ)   I(min)   I(max)
-1.1V     -3.6mA     -4.061mA   -2.269mA
-624mV    -4.125mA   -3.893mA   -3.918mA
-284mV    -3.371mA   -3.023mA   -3.47mA
-147mV    -2.039mA   -1.891mA   -2.105mA
261mV     3.489mA    3.393mA    3.525mA
533mV     6.647mA    6.689mA    6.389mA
805mV     8.664mA    9.502mA    7.623mA
1.145V    9.48mA     11.69mA    8.057mA
1.826V    9.881mA    12.51mA    8.329mA
1.996V    9.616mA    11.13mA    8.375mA
2.098V    8.498mA    9.845mA    8.273mA
2.2V      6.944mA    8.432mA    7.136mA
[Pullup]
|Voltage   I(typ)   I(min)   I(max)
-1.1V     3.978mA    3.999mA    3.399mA
-590mV    4.31mA     3.725mA    4.652mA
-284mV    3.52mA     2.929mA    4.021mA
-113mV    1.673mA    1.492mA    1.862mA
363mV     -5.171mA   -4.81mA    -5.683mA
635mV     -8.585mA   -8.19mA    -9.035mA
941mV     -11.18mA   -11.52mA   -10.86mA
1.315V    -12.34mA   -14.2mA    -11.54mA
1.86V     -12.74mA   -15mA      -11.82mA
2.03V     -12.28mA   -13.33mA   -11.87mA
2.132V    -10.93mA   -11.85mA   -11.65mA
2.2V      -9.724mA   -10.66mA   -10.8mA
[GND_clamp]
|Voltage   I(typ)   I(min)   I(max)
-1.1V     -136.6mA   -190.1mA   -111.1mA
-1.077V   -102.6mA   -148.4mA   -83.57mA
-1.054V   -79.22mA   -115.9mA   -67.05mA
-1.031V   -63.93mA   -91.43mA   -57.36mA
-1.008V   -54.04mA   -73.6mA    -51.37mA
-985mV    -47.47mA   -60.82mA   -47.28mA
-962mV    -42.85mA   -51.68mA   -44.18mA
-917mV    -36.56mA   -40.08mA   -39.42mA
-802mV    -26.83mA   -26.21mA   -29.77mA
-504mV    -8.458mA   -8.847mA   -8.902mA
-252mV    -923uA     -1.37mA    -917.2uA
1.1V      0A         0A         0A
[POWER_clamp]
|Voltage   I(typ)   I(min)   I(max)
-1.1V     186.7mA    267.6mA    149.4mA
-1.077V   134.7mA    202.8mA    107.4mA
-1.054V   100.3mA    153.6mA    83.44mA
-1.031V   78.51mA    117.7mA    69.97mA
-1.008V   64.87mA    92.18mA    62.12mA
-985mV    56.1mA     74.26mA    56.97mA
-940mV    45.96mA    52.89mA    50.3mA
-848mV    35.63mA    34.9mA     41.42mA
-710mV    25.31mA    23.21mA    29.58mA
-481mV    10.42mA    10.4mA     11.78mA
-252mV    1.166mA    1.865mA    981uA
1.1V      0A         0A         0A
[Ramp]
| variable   typ   min   max
dV/dt_r   0.232/98.871p   0.217/91.391p   0.253/0.105n
dV/dt_f   0.232/0.216n   0.217/0.224n   0.253/0.227n
R_load = 40.000
[Rising Waveform]
R_fixture= 40.000
V_fixture= 1.100
V_fixture_min= 1.060
V_fixture_max= 1.170
|time   V(typ)   V(min)   V(max)
0s        761.9mV    714.3mV    860.7mV
151ps     762.2mV    714.3mV    875.1mV
194ps     786.5mV    713.9mV    991.6mV
238ps     925.6mV    726.5mV    1.069V
260ps     969.6mV    759.1mV    1.093V
313ps     1.031V     912mV      1.129V
363ps     1.061V     980.8mV    1.147V
451ps     1.084V     1.029V     1.161V
593ps     1.096V     1.052V     1.167V
5ns       1.1V       1.06V      1.17V
[Rising Waveform]
R_fixture= 40.000
V_fixture= 0.0
V_fixture_min= 0.0
V_fixture_max= 0.0
|time   V(typ)   V(min)   V(max)
0s        1.134mV    1.7mV      2.405mV
135ps     1.024mV    1.694mV    10.9mV
197ps     35.5mV     1.676mV    143.6mV
229ps     117mV      10.84mV    209.3mV
286ps     237.3mV    83.95mV    287.6mV
324ps     281.5mV    198.3mV    321.2mV
369ps     315.6mV    261.2mV    348mV
452ps     348.2mV    313.3mV    374.8mV
568ps     364.3mV    338.7mV    389.9mV
5ns       375.3mV    354.1mV    401.8mV
[Falling Waveform]
R_fixture= 40.000
V_fixture= 1.100
V_fixture_min= 1.060
V_fixture_max= 1.170
|time   V(typ)   V(min)   V(max)
0s        1.1V       1.06V      1.17V
154ps     1.1V       1.06V      1.169V
202ps     1.094V     1.06V      1.082V
264ps     971.5mV    1.058V     1V
279ps     948.7mV    1.04V      985.3mV
353ps     867mV      887.7mV    932.4mV
432ps     818.4mV    801.3mV    900.7mV
542ps     785.9mV    748.1mV    878.8mV
705ps     769.1mV    723.5mV    866.7mV
5ns       761.9mV    714.5mV    860.7mV
[Falling Waveform]
R_fixture= 40.000
V_fixture= 0.0
V_fixture_min= 0.0
V_fixture_max= 0.0
|time   V(typ)   V(min)   V(max)
0s        375.1mV    353.7mV    401.8mV
151ps     375mV      353.7mV    401.8mV
196ps     369.9mV    353.7mV    288.1mV
253ps     228.7mV    352.8mV    149.3mV
308ps     121.7mV    234.8mV    78.21mV
374ps     57.15mV    117.1mV    37.11mV
432ps     30.2mV     62.61mV    20.38mV
507ps     14.17mV    29mV       10.68mV
883ps     2.438mV    3.306mV    3.442mV
5ns       1.147mV    1.813mV    2.412mV
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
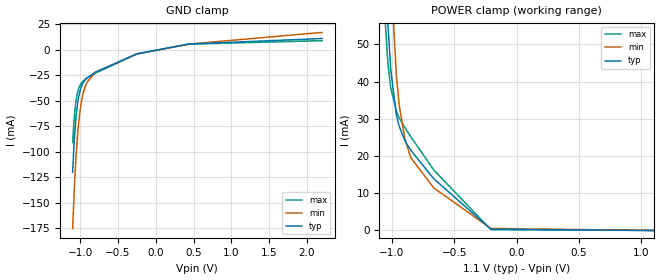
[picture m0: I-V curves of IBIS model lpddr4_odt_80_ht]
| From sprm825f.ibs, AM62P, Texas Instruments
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|   Model lpddr4_odt_80_ht
[Model] lpddr4_odt_80_ht
Model_type Input
Polarity   Non-Inverting
Enable   Active-High
Vinl =  0.113V
Vinh =  0.253V
C_comp   2.678pF   2.644pF   2.686pF
[Model Spec]
Vinh   0.253V   0.247V   0.265V
Vinl   0.113V   0.107V   0.125V
[Temperature Range]   25.000   0.125k   -40.000
[Voltage Range]   1.100V   1.060V   1.170V
[C Comp Corner]
C_comp   2.678pF   2.644pF   2.686pF
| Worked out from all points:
|   GND clamp passes 1 mA (typ) near -0.07 V on its own axis
|   POWER clamp passes 1 mA (typ) near -0.25 V on its own axis
[GND_clamp]
|Voltage   I(typ)   I(min)   I(max)
-1.1V     -120.3mA   -175.6mA   -91.19mA
-1.077V   -87.55mA   -135.2mA   -64.72mA
-1.054V   -65.25mA   -103.8mA   -49.23mA
-1.031V   -50.9mA    -80.3mA    -40.6mA
-1.008V   -41.92mA   -63.29mA   -35.71mA
-985mV    -36.24mA   -51.28mA   -32.73mA
-962mV    -32.51mA   -42.86mA   -30.73mA
-917mV    -27.98mA   -32.67mA   -28.06mA
-802mV    -22.2mA    -22.13mA   -23.13mA
-252mV    -4.059mA   -4.158mA   -4.164mA
435mV     5.579mA    5.513mA    5.474mA
2.2V      11.01mA    17.02mA    8.92mA
[POWER_clamp]
|Voltage   I(typ)   I(min)   I(max)
-1.1V     154.4mA    240.6mA    119.9mA
-1.077V   106.8mA    176.8mA    79.41mA
-1.054V   75.16mA    128.8mA    56.82mA
-1.031V   55.26mA    94.01mA    44.74mA
-1.008V   43.12mA    69.59mA    38.27mA
-963mV    31.01mA    41.34mA    32.06mA
-940mV    27.9mA     33.53mA    30.26mA
-894mV    24.08mA    24.41mA    27.58mA
-848mV    21.57mA    19.61mA    25.22mA
-665mV    13.96mA    11.47mA    16.32mA
-206mV    344uA      552.2uA    239.5uA
1.1V      0A         0A         0A
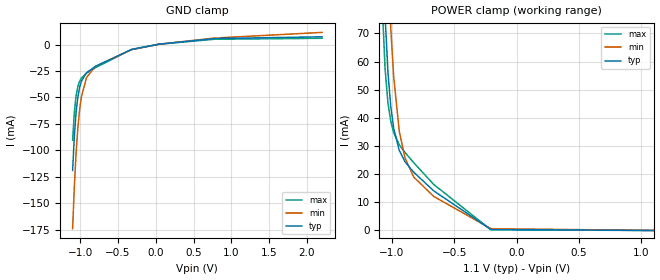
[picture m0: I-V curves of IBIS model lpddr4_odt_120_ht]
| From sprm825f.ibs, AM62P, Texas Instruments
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|   Model lpddr4_odt_120_ht
[Model] lpddr4_odt_120_ht
Model_type Input
Polarity   Non-Inverting
Enable   Active-High
Vinl =  0.113V
Vinh =  0.253V
C_comp   2.759pF   2.736pF   2.762pF
[Model Spec]
Vinh   0.253V   0.247V   0.265V
Vinl   0.113V   0.107V   0.125V
[Temperature Range]   25.000   0.125k   -40.000
[Voltage Range]   1.100V   1.060V   1.170V
[C Comp Corner]
C_comp   2.759pF   2.736pF   2.762pF
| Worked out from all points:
|   GND clamp passes 1 mA (typ) near -0.10 V on its own axis
|   POWER clamp passes 1 mA (typ) near -0.25 V on its own axis
[GND_clamp]
|Voltage   I(typ)   I(min)   I(max)
-1.1V     -119.1mA   -174.2mA   -90.44mA
-1.077V   -86.33mA   -133.9mA   -63.94mA
-1.054V   -64.01mA   -102.5mA   -48.42mA
-1.031V   -49.65mA   -78.95mA   -39.77mA
-1.008V   -40.65mA   -61.94mA   -34.85mA
-985mV    -34.95mA   -49.92mA   -31.83mA
-917mV    -26.65mA   -31.32mA   -27.07mA
-802mV    -20.83mA   -20.79mA   -21.98mA
-321mV    -4.594mA   -4.757mA   -4.755mA
45.83mV   377.2uA    344.2uA    336.1uA
779mV     5.687mA    6.155mA    5.028mA
2.2V      7.344mA    11.5mA     5.944mA
[POWER_clamp]
|Voltage   I(typ)   I(min)   I(max)
-1.1V     155.8mA    243.2mA    120.9mA
-1.077V   108mA      179.3mA    80.22mA
-1.054V   76.24mA    131.1mA    57.49mA
-1.031V   56.2mA     96.14mA    45.29mA
-1.008V   43.93mA    71.59mA    38.69mA
-985mV    36.35mA    54.62mA    34.77mA
-940mV    28.38mA    35.13mA    30.42mA
-894mV    24.41mA    25.77mA    27.69mA
-825mV    20.71mA    19.03mA    24.12mA
-665mV    14.12mA    12.12mA    16.39mA
-206mV    368.1uA    645.9uA    249.1uA
1.1V      0A         0A         0A
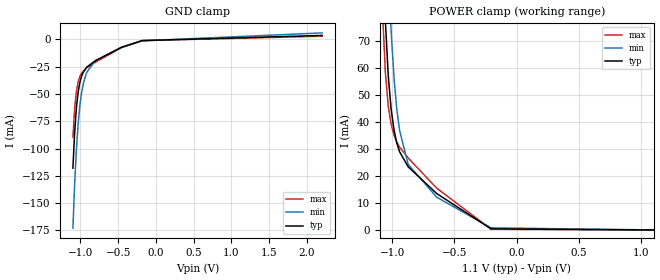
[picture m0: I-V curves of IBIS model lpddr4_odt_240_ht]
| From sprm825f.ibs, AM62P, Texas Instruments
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|   Model lpddr4_odt_240_ht
[Model] lpddr4_odt_240_ht
Model_type Input
Polarity   Non-Inverting
Enable   Active-High
Vinl =  0.113V
Vinh =  0.253V
C_comp   2.845pF   2.841pF   2.850pF
[Model Spec]
Vinh   0.253V   0.247V   0.265V
Vinl   0.113V   0.107V   0.125V
[Temperature Range]   25.000   0.125k   -40.000
[Voltage Range]   1.100V   1.060V   1.170V
[C Comp Corner]
C_comp   2.850pF   2.841pF   2.845pF
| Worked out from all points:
|   GND clamp passes 1 mA (typ) near -0.18 V on its own axis
|   POWER clamp passes 1 mA (typ) near -0.25 V on its own axis
[GND_clamp]
|Voltage   I(typ)   I(min)   I(max)
-1.1V     -118mA     -173mA     -89.7mA
-1.077V   -85.16mA   -132.6mA   -63.17mA
-1.054V   -62.82mA   -101.2mA   -47.63mA
-1.031V   -48.44mA   -77.68mA   -38.95mA
-1.008V   -39.42mA   -60.67mA   -34mA
-985mV    -33.72mA   -48.65mA   -30.95mA
-962mV    -29.96mA   -40.23mA   -28.89mA
-917mV    -25.37mA   -30.04mA   -26.09mA
-802mV    -19.5mA    -19.5mA    -20.85mA
-458mV    -7.211mA   -7.27mA    -7.571mA
-183mV    -1.048mA   -1.251mA   -1.066mA
2.2V      3.682mA    6.016mA    2.977mA
[POWER_clamp]
|Voltage   I(typ)   I(min)   I(max)
-1.1V     157.1mA    245.7mA    121.8mA
-1.077V   109.2mA    181.7mA    81mA
-1.054V   77.32mA    133.4mA    58.15mA
-1.031V   57.15mA    98.3mA     45.83mA
-1.008V   44.77mA    73.63mA    39.12mA
-985mV    37.09mA    56.54mA    35.11mA
-963mV    32.23mA    44.87mA    32.56mA
-940mV    28.93mA    36.81mA    30.64mA
-871mV    23.35mA    24.25mA    26.62mA
-642mV    13.46mA    12.11mA    15.46mA
-206mV    416.8uA    783.5uA    274.1uA
1.1V      0A         0A         0A
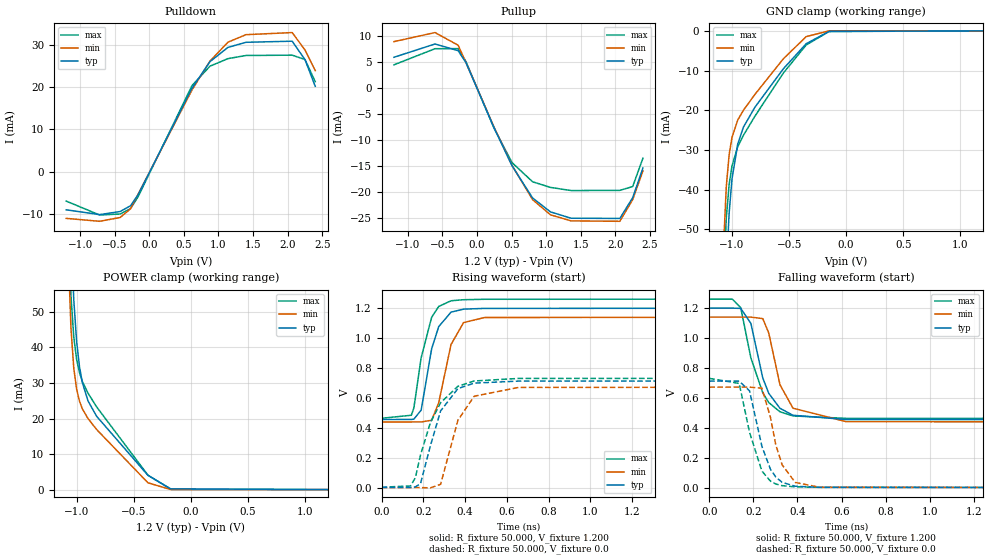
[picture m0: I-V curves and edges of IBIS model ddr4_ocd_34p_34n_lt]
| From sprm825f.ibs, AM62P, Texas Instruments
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|LPDDR4 ********** End LPDDR4 HT Models
|DDR4 ********** Begin DDR4 LT Models
|   Model ddr4_ocd_34p_34n_lt
[Model] ddr4_ocd_34p_34n_lt
Model_type I/O
Polarity   Non-Inverting
Enable   Active-High
Vinl =  0.700V
Vinh =  0.900V
Vmeas =  0.600V
C_comp   2.033pF   1.929pF   2.166pF
[Model Spec]
Vinh   0.900V   0.820V   0.980V
Vinl   0.700V   0.620V   0.780V
Vmeas   0.600V   NA   NA
[Temperature Range]   25.000   -40.000   -40.000
[Voltage Range]   1.200V   1.140V   1.260V
[Pullup Reference]   1.200V   1.140V   1.260V
[Pulldown Reference]   0.0V   0.0V   0.0V
[C Comp Corner]
C_comp   2.033pF   1.929pF   2.166pF
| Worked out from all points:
|   slope of the pulldown table from 0 to 0.18 V, typ, clamps not added: 29.6 ohm
|   slope of the pullup table from 0 to 0.18 V, typ, clamps not added: 32.3 ohm
|   GND clamp passes 1 mA (typ) near -0.25 V on its own axis
|   POWER clamp passes 1 mA (typ) near -0.25 V on its own axis
|   rising waveform, R_fixture 50.000, V_fixture 1.200: 20-80 % time 64.1ps typ, 67.1ps min, 64.6ps max; typ from 0.455 V to 1.2 V
|   rising waveform, R_fixture 50.000, V_fixture 0.0: 20-80 % time 89.4ps typ, 84.5ps min, 116ps max; typ from 0.001 V to 0.713 V
|   falling waveform, R_fixture 50.000, V_fixture 1.200: 20-80 % time 84ps typ, 78.4ps min, 88.7ps max; typ from 1.2 V to 0.455 V
|   falling waveform, R_fixture 50.000, V_fixture 0.0: 20-80 % time 76.3ps typ, 68.4ps min, 70.4ps max; typ from 0.713 V to 0.001 V
[Pulldown]
|Voltage   I(typ)   I(min)   I(max)
-1.2V     -9.006mA   -11.03mA   -6.947mA
-718mV    -10.14mA   -11.72mA   -10.24mA
-421mV    -9.412mA   -10.82mA   -9.989mA
-272mV    -8.055mA   -8.78mA    -8.751mA
-161mV    -5.435mA   -5.32mA    -5.9mA
619mV     19.76mA    19.35mA    20.38mA
878mV     26.02mA    26.15mA    24.95mA
1.138V    29.39mA    30.62mA    26.73mA
1.398V    30.59mA    32.39mA    27.47mA
2.066V    30.85mA    32.89mA    27.55mA
2.252V    26.49mA    28.78mA    26.52mA
2.4V      20.19mA    23.89mA    21.28mA
[Pullup]
|Voltage   I(typ)   I(min)   I(max)
-1.2V     5.943mA    8.949mA    4.494mA
-606mV    8.496mA    10.69mA    7.591mA
-272mV    7.209mA    8.254mA    7.602mA
-161mV    4.965mA    4.989mA    5.17mA
247mV     -7.589mA   -7.486mA   -7.694mA
507mV     -14.9mA    -14.83mA   -14.3mA
804mV     -21.09mA   -21.41mA   -17.98mA
1.064V    -23.78mA   -24.34mA   -19.07mA
1.361V    -24.99mA   -25.5mA    -19.67mA
2.066V    -25.03mA   -25.58mA   -19.64mA
2.252V    -21.04mA   -21.41mA   -18.9mA
2.4V      -15.33mA   -15.91mA   -13.45mA
[GND_clamp]
|Voltage   I(typ)   I(min)   I(max)
-1.2V     -396.3mA   -359.8mA   -370.1mA
-1.075V   -83.02mA   -54.49mA   -62.73mA
-1.05V    -59.94mA   -39.12mA   -46.97mA
-1.025V   -45.76mA   -31.12mA   -38.62mA
-1V       -37.22mA   -26.8mA    -33.98mA
-950mV    -28.5mA    -22.45mA   -29.17mA
-900mV    -24.23mA   -19.99mA   -26.3mA
-800mV    -19.26mA   -16.03mA   -21.52mA
-550mV    -9.545mA   -7.027mA   -10.62mA
-350mV    -3.249mA   -1.463mA   -3.563mA
-150mV    -148.5uA   -4.429uA   -178.6uA
1.2V      0A         0A         0A
[POWER_clamp]
|Voltage   I(typ)   I(min)   I(max)
-1.2V     594.8mA    611.1mA    623.3mA
-1.075V   106.2mA    68.15mA    77.8mA
-1.05V    73.23mA    45.49mA    54.67mA
-1.025V   53.34mA    34.11mA    42.85mA
-1V       41.61mA    28.23mA    36.57mA
-975mV    34.56mA    24.88mA    32.87mA
-950mV    30.12mA    22.73mA    30.42mA
-900mV    24.94mA    19.97mA    27.12mA
-825mV    20.64mA    16.92mA    23.28mA
-375mV    4.008mA    1.916mA    4.058mA
-175mV    200.6uA    5.438uA    99.18uA
1.2V      0A         0A         0A
[Ramp]
| variable   typ   min   max
dV/dt_r   0.427/89.561p   0.434/87.040p   0.437/0.117n
dV/dt_f   0.447/84.662p   0.450/81.126p   0.478/88.149p
R_load = 60.000
[Rising Waveform]
R_fixture= 50.000
V_fixture= 1.200
V_fixture_min= 1.140
V_fixture_max= 1.260
|time   V(typ)   V(min)   V(max)
0s        455.2mV    438.8mV    463.4mV
143ps     455.3mV    438.8mV    483.7mV
155ps     457.8mV    438.9mV    532.8mV
190ps     518mV      438.8mV    868.7mV
240ps     927.2mV    450.4mV    1.138V
274ps     1.076V     566.9mV    1.211V
333ps     1.173V     956.5mV    1.249V
393ps     1.193V     1.103V     1.256V
493ps     1.198V     1.137V     1.259V
3ns       1.2V       1.14V      1.26V
[Rising Waveform]
R_fixture= 50.000
V_fixture= 0.0
V_fixture_min= 0.0
V_fixture_max= 0.0
|time   V(typ)   V(min)   V(max)
0s        1.434mV    129.7uV    2.494mV
139ps     1.37mV     124.7uV    11.11mV
162ps     4.513mV    125.3uV    65.51mV
187ps     27.16mV    115.4uV    218.5mV
234ps     278.4mV    -1.779mV   433.5mV
283ps     512.4mV    21.95mV    567.1mV
366ps     662mV      450.1mV    677.4mV
444ps     698.5mV    611mV      712.7mV
656ps     711.9mV    669.5mV    729.8mV
3ns       712.8mV    672.6mV    731.1mV
[Falling Waveform]
R_fixture= 50.000
V_fixture= 1.200
V_fixture_min= 1.140
V_fixture_max= 1.260
|time   V(typ)   V(min)   V(max)
0s        1.2V       1.14V      1.26V
105ps     1.2V       1.14V      1.26V
143ps     1.198V     1.14V      1.203V
189ps     1.098V     1.14V      867.2mV
243ps     733.9mV    1.13V      634.6mV
270ps     631.1mV    1.034V     569.9mV
321ps     531.2mV    688.2mV    507.8mV
380ps     484.7mV    531.8mV    480.4mV
621ps     456.3mV    442.2mV    464.1mV
3ns       455.2mV    438.8mV    463.4mV
[Falling Waveform]
R_fixture= 50.000
V_fixture= 0.0
V_fixture_min= 0.0
V_fixture_max= 0.0
|time   V(typ)   V(min)   V(max)
0s        712.8mV    672.5mV    731.1mV
136ps     712.6mV    672.5mV    697.2mV
183ps     647.6mV    672.5mV    370.5mV
239ps     277.2mV    665.7mV    112.2mV
278ps     123.6mV    469.6mV    44.64mV
302ps     72.3mV     286.6mV    25.83mV
331ps     36.75mV    153.4mV    14.79mV
390ps     11.04mV    36.29mV    6.887mV
500ps     3.468mV    4.197mV    3.86mV
3ns       1.433mV    130.6uV    2.494mV
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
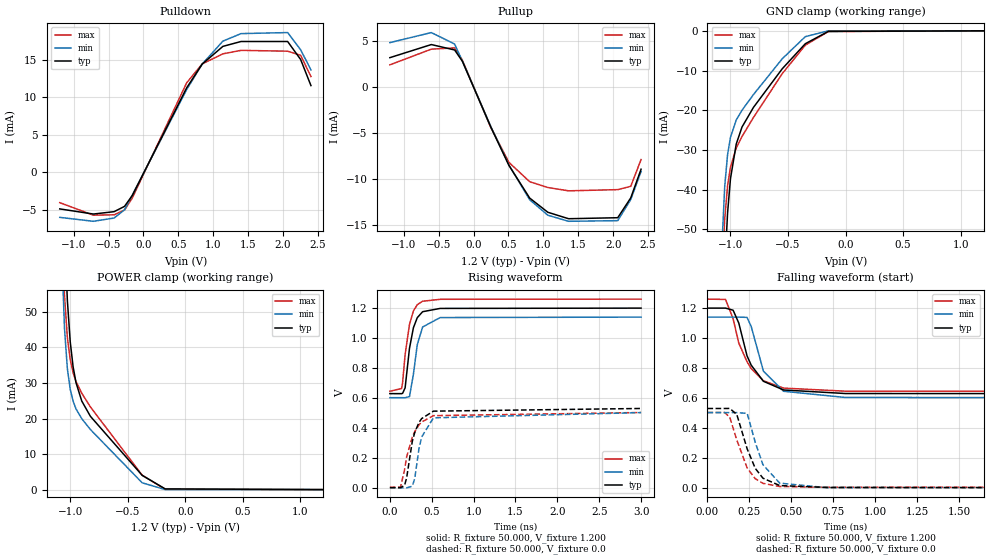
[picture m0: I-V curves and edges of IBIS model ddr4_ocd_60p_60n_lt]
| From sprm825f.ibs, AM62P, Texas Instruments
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|   Model ddr4_ocd_60p_60n_lt
[Model] ddr4_ocd_60p_60n_lt
Model_type I/O
Polarity   Non-Inverting
Enable   Active-High
Vinl =  0.700V
Vinh =  0.900V
Vmeas =  0.600V
C_comp   2.354pF   2.257pF   2.430pF
[Model Spec]
Vinh   0.900V   0.820V   0.980V
Vinl   0.700V   0.620V   0.780V
Vmeas   0.600V   NA   NA
[Temperature Range]   25.000   -40.000   -40.000
[Voltage Range]   1.200V   1.140V   1.260V
[Pullup Reference]   1.200V   1.140V   1.260V
[Pulldown Reference]   0.0V   0.0V   0.0V
[C Comp Corner]
C_comp   2.354pF   2.257pF   2.430pF
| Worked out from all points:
|   slope of the pulldown table from 0 to 0.18 V, typ, clamps not added: 51.9 ohm
|   slope of the pullup table from 0 to 0.18 V, typ, clamps not added: 56.7 ohm
|   GND clamp passes 1 mA (typ) near -0.25 V on its own axis
|   POWER clamp passes 1 mA (typ) near -0.25 V on its own axis
|   rising waveform, R_fixture 50.000, V_fixture 1.200: 20-80 % time 91.8ps typ, 91.7ps min, 91.5ps max; typ from 0.629 V to 1.2 V
|   rising waveform, R_fixture 50.000, V_fixture 0.0: 20-80 % time 127ps typ, 116ps min, 155ps max; typ from 0.002 V to 0.53 V
|   falling waveform, R_fixture 50.000, V_fixture 1.200: 20-80 % time 116ps typ, 103ps min, 129ps max; typ from 1.2 V to 0.629 V
|   falling waveform, R_fixture 50.000, V_fixture 0.0: 20-80 % time 105ps typ, 93.8ps min, 98.9ps max; typ from 0.53 V to 0.002 V
[Pulldown]
|Voltage   I(typ)   I(min)   I(max)
-1.2V     -4.862mA   -5.99mA    -4.03mA
-718mV    -5.546mA   -6.512mA   -5.698mA
-421mV    -5.23mA    -6.077mA   -5.647mA
-272mV    -4.526mA   -4.984mA   -5.015mA
-161mV    -3.087mA   -3.031mA   -3.417mA
619mV     11.26mA    11.03mA    11.93mA
841mV     14.42mA    14.42mA    14.44mA
1.138V    16.78mA    17.48mA    15.79mA
1.398V    17.43mA    18.48mA    16.25mA
2.066V    17.43mA    18.62mA    16.14mA
2.252V    15.04mA    16.34mA    15.6mA
2.4V      11.56mA    13.65mA    12.77mA
[Pullup]
|Voltage   I(typ)   I(min)   I(max)
-1.2V     3.216mA    4.848mA    2.435mA
-606mV    4.639mA    5.941mA    4.139mA
-272mV    4.049mA    4.689mA    4.277mA
-161mV    2.823mA    2.843mA    2.946mA
247mV     -4.328mA   -4.267mA   -4.391mA
507mV     -8.502mA   -8.457mA   -8.167mA
804mV     -12.04mA   -12.22mA   -10.26mA
1.064V    -13.58mA   -13.9mA    -10.89mA
1.361V    -14.28mA   -14.56mA   -11.25mA
2.066V    -14.17mA   -14.49mA   -11.12mA
2.252V    -12.02mA   -12.2mA    -10.76mA
2.4V      -8.904mA   -9.156mA   -7.854mA
[GND_clamp]
|Voltage   I(typ)   I(min)   I(max)
-1.2V     -396.3mA   -359.8mA   -370.5mA
-1.075V   -83.02mA   -54.49mA   -63.08mA
-1.05V    -59.94mA   -39.12mA   -47.32mA
-1.025V   -45.76mA   -31.12mA   -38.96mA
-1V       -37.22mA   -26.8mA    -34.32mA
-950mV    -28.5mA    -22.45mA   -29.5mA
-900mV    -24.23mA   -19.99mA   -26.62mA
-800mV    -19.26mA   -16.03mA   -21.8mA
-550mV    -9.545mA   -7.027mA   -10.77mA
-350mV    -3.249mA   -1.463mA   -3.61mA
-150mV    -148.5uA   -4.429uA   -178.6uA
1.2V      0A         0A         0A
[POWER_clamp]
|Voltage   I(typ)   I(min)   I(max)
-1.2V     594.8mA    611.1mA    623.3mA
-1.075V   106.2mA    68.15mA    77.8mA
-1.05V    73.23mA    45.49mA    54.67mA
-1.025V   53.34mA    34.11mA    42.85mA
-1V       41.61mA    28.23mA    36.57mA
-975mV    34.56mA    24.88mA    32.87mA
-950mV    30.12mA    22.73mA    30.42mA
-900mV    24.94mA    19.97mA    27.12mA
-825mV    20.64mA    16.92mA    23.28mA
-375mV    4.008mA    1.916mA    4.058mA
-175mV    200.6uA    5.443uA    99.19uA
1.2V      0A         0A         0A
[Ramp]
| variable   typ   min   max
dV/dt_r   0.317/0.126n   0.301/0.116n   0.300/0.156n
dV/dt_f   0.342/0.115n   0.323/0.103n   0.369/0.128n
R_load = 60.000
[Rising Waveform]
R_fixture= 50.000
V_fixture= 1.200
V_fixture_min= 1.140
V_fixture_max= 1.260
|time   V(typ)   V(min)   V(max)
0s        629.2mV    602mV      645mV
140ps     629mV      602mV      663.4mV
152ps     631.3mV    602mV      702.5mV
182ps     667.6mV    601.9mV    889.9mV
234ps     931.1mV    609.5mV    1.091V
281ps     1.069V     758.4mV    1.181V
327ps     1.136V     955.9mV    1.223V
391ps     1.176V     1.074V     1.246V
601ps     1.198V     1.137V     1.259V
3ns       1.2V       1.14V      1.26V
[Rising Waveform]
R_fixture= 50.000
V_fixture= 0.0
V_fixture_min= 0.0
V_fixture_max= 0.0
|time   V(typ)   V(min)   V(max)
0s        1.981mV    174.6uV    3.443mV
127ps     1.94mV     169.5uV    5.199mV
175ps     16.38mV    167.4uV    120.6mV
200ps     66.17mV    196.7uV    206.2mV
267ps     308.5mV    11.33mV    338.3mV
297ps     369.6mV    62.15mV    375.9mV
347ps     436.1mV    260.4mV    420.2mV
380ps     462.9mV    340.1mV    440mV
520ps     512.2mV    467.7mV    482.2mV
3ns       530.1mV    502.6mV    503.2mV
[Falling Waveform]
R_fixture= 50.000
V_fixture= 1.200
V_fixture_min= 1.140
V_fixture_max= 1.260
|time   V(typ)   V(min)   V(max)
0s        1.2V       1.14V      1.26V
108ps     1.2V       1.14V      1.258V
153ps     1.186V     1.14V      1.129V
187ps     1.1V       1.14V      966.2mV
236ps     881.7mV    1.138V     842.4mV
261ps     819.1mV    1.077V     796.5mV
334ps     711.5mV    779.2mV    714.6mV
454ps     653.5mV    644.9mV    666.1mV
824ps     629.8mV    603.5mV    645.4mV
3ns       629.2mV    602mV      645mV
[Falling Waveform]
R_fixture= 50.000
V_fixture= 0.0
V_fixture_min= 0.0
V_fixture_max= 0.0
|time   V(typ)   V(min)   V(max)
0s        530mV      502.5mV    503.2mV
102ps     530mV      502.5mV    503.5mV
133ps     530.4mV    502.5mV    471.4mV
175ps     490.4mV    502.5mV    320mV
237ps     260.1mV    497.4mV    132.2mV
285ps     130.5mV    304.4mV    61.4mV
331ps     64.78mV    154.3mV    30.26mV
431ps     15.52mV    31.71mV    9.288mV
711ps     2.84mV     1.545mV    3.937mV
3ns       1.98mV     176uV      3.443mV
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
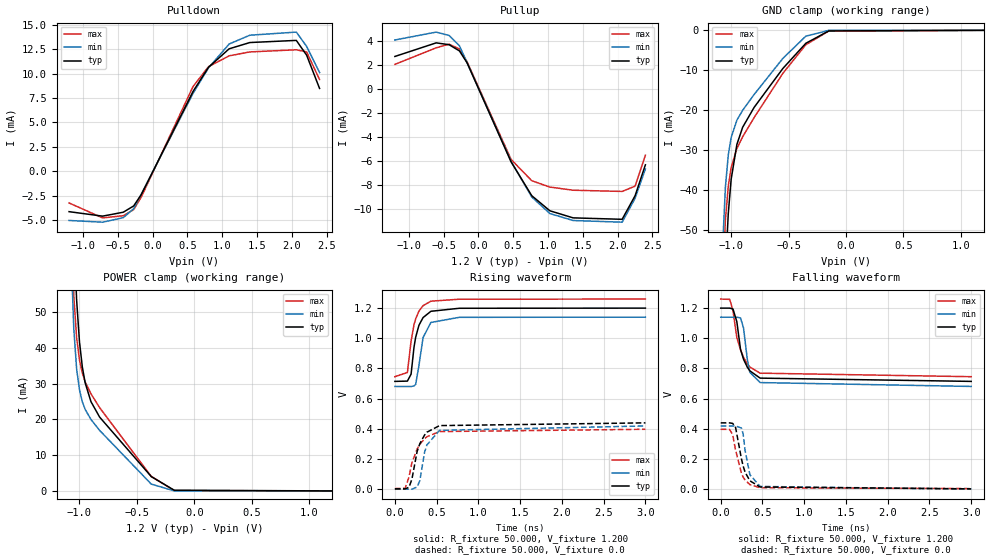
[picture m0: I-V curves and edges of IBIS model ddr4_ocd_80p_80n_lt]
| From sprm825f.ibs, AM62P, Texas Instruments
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|   Model ddr4_ocd_80p_80n_lt
[Model] ddr4_ocd_80p_80n_lt
Model_type I/O
Polarity   Non-Inverting
Enable   Active-High
Vinl =  0.700V
Vinh =  0.900V
Vmeas =  0.600V
C_comp   2.588pF   2.501pF   2.607pF
[Model Spec]
Vinh   0.900V   0.820V   0.980V
Vinl   0.700V   0.620V   0.780V
Vmeas   0.600V   NA   NA
[Temperature Range]   25.000   -40.000   -40.000
[Voltage Range]   1.200V   1.140V   1.260V
[Pullup Reference]   1.200V   1.140V   1.260V
[Pulldown Reference]   0.0V   0.0V   0.0V
[C Comp Corner]
C_comp   2.588pF   2.501pF   2.607pF
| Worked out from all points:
|   slope of the pulldown table from 0 to 0.18 V, typ, clamps not added: 67.6 ohm
|   slope of the pullup table from 0 to 0.18 V, typ, clamps not added: 74.1 ohm
|   GND clamp passes 1 mA (typ) near -0.25 V on its own axis
|   POWER clamp passes 1 mA (typ) near -0.25 V on its own axis
|   rising waveform, R_fixture 50.000, V_fixture 1.200: 20-80 % time 96.8ps typ, 83.8ps min, 100ps max; typ from 0.714 V to 1.2 V
|   rising waveform, R_fixture 50.000, V_fixture 0.0: 20-80 % time 136ps typ, 117ps min, 158ps max; typ from 0.002 V to 0.44 V
|   falling waveform, R_fixture 50.000, V_fixture 1.200: 20-80 % time 121ps typ, 71.4ps min, 143ps max; typ from 1.2 V to 0.714 V
|   falling waveform, R_fixture 50.000, V_fixture 0.0: 20-80 % time 109ps typ, 82.7ps min, 109ps max; typ from 0.44 V to 0.002 V
[Pulldown]
|Voltage   I(typ)   I(min)   I(max)
-1.2V     -4.138mA   -5.038mA   -3.244mA
-718mV    -4.597mA   -5.215mA   -4.78mA
-421mV    -4.194mA   -4.754mA   -4.551mA
-272mV    -3.555mA   -3.836mA   -3.931mA
-161mV    -2.383mA   -2.321mA   -2.63mA
581mV     8.157mA    7.957mA    8.662mA
804mV     10.64mA    10.58mA    10.7mA
1.101V    12.53mA    13.02mA    11.81mA
1.398V    13.17mA    13.92mA    12.21mA
2.066V    13.39mA    14.24mA    12.43mA
2.214V    11.88mA    12.78mA    12.21mA
2.4V      8.473mA    10.1mA     9.385mA
[Pullup]
|Voltage   I(typ)   I(min)   I(max)
-1.2V     2.716mA    4.087mA    2.056mA
-606mV    3.849mA    4.745mA    3.437mA
-421mV    3.694mA    4.461mA    3.74mA
-272mV    3.176mA    3.6mA      3.338mA
-161mV    2.171mA    2.174mA    2.253mA
470mV     -6.059mA   -6.015mA   -5.855mA
767mV     -8.876mA   -8.983mA   -7.628mA
1.027V    -10.13mA   -10.36mA   -8.155mA
1.361V    -10.72mA   -10.94mA   -8.419mA
2.066V    -10.84mA   -11.08mA   -8.519mA
2.252V    -8.875mA   -9.091mA   -8.079mA
2.4V      -6.303mA   -6.648mA   -5.506mA
[GND_clamp]
|Voltage   I(typ)   I(min)   I(max)
-1.2V     -396.3mA   -359.8mA   -370.5mA
-1.075V   -83.02mA   -54.49mA   -63.08mA
-1.05V    -59.94mA   -39.12mA   -47.32mA
-1.025V   -45.76mA   -31.12mA   -38.96mA
-1V       -37.22mA   -26.8mA    -34.32mA
-950mV    -28.5mA    -22.45mA   -29.5mA
-900mV    -24.23mA   -19.99mA   -26.62mA
-800mV    -19.26mA   -16.03mA   -21.8mA
-550mV    -9.545mA   -7.027mA   -10.77mA
-350mV    -3.249mA   -1.463mA   -3.61mA
-150mV    -148.5uA   -4.429uA   -178.6uA
1.2V      0A         0A         0A
[POWER_clamp]
|Voltage   I(typ)   I(min)   I(max)
-1.2V     594.8mA    611.1mA    623.3mA
-1.075V   106.2mA    68.15mA    77.8mA
-1.05V    73.23mA    45.49mA    54.67mA
-1.025V   53.34mA    34.11mA    42.85mA
-1V       41.61mA    28.23mA    36.57mA
-975mV    34.56mA    24.88mA    32.87mA
-950mV    30.12mA    22.73mA    30.42mA
-900mV    24.94mA    19.97mA    27.12mA
-825mV    20.64mA    16.92mA    23.28mA
-375mV    4.008mA    1.916mA    4.058mA
-175mV    200.6uA    5.448uA    99.19uA
1.2V      0A         0A         0A
[Ramp]
| variable   typ   min   max
dV/dt_r   0.262/0.136n   0.251/0.116n   0.236/0.159n
dV/dt_f   0.291/0.121n   0.275/71.606p   0.309/0.142n
R_load = 60.000
[Rising Waveform]
R_fixture= 50.000
V_fixture= 1.200
V_fixture_min= 1.140
V_fixture_max= 1.260
|time   V(typ)   V(min)   V(max)
0s        714.4mV    680.9mV    745.5mV
150ps     716.3mV    680.9mV    773.5mV
194ps     762.5mV    680.4mV    982.3mV
229ps     941mV      684.1mV    1.09V
249ps     1.007V     694.9mV    1.129V
288ps     1.086V     819.1mV    1.18V
337ps     1.137V     1.004V     1.216V
431ps     1.179V     1.105V     1.246V
771ps     1.199V     1.139V     1.259V
3ns       1.2V       1.14V      1.26V
[Rising Waveform]
R_fixture= 50.000
V_fixture= 0.0
V_fixture_min= 0.0
V_fixture_max= 0.0
|time   V(typ)   V(min)   V(max)
0s        2.274mV    185.1uV    3.976mV
123ps     2.249mV    181uV      5.906mV
169ps     12.68mV    178.9uV    80.57mV
204ps     66.3mV     163.9uV    175.4mV
266ps     249.6mV    14.46mV    265.3mV
299ps     301.9mV    56.55mV    297mV
355ps     358.6mV    243.6mV    334.4mV
384ps     377.8mV    293.6mV    347.8mV
534ps     421.4mV    389.8mV    381.8mV
3ns       439.6mV    419.1mV    397.1mV
[Falling Waveform]
R_fixture= 50.000
V_fixture= 1.200
V_fixture_min= 1.140
V_fixture_max= 1.260
|time   V(typ)   V(min)   V(max)
0s        1.2V       1.14V      1.26V
108ps     1.2V       1.14V      1.258V
147ps     1.194V     1.14V      1.183V
193ps     1.11V      1.14V      1.005V
237ps     927.1mV    1.135V     923.8mV
273ps     861.3mV    1.069V     874.3mV
318ps     809.3mV    862.3mV    830.4mV
348ps     784.6mV    774.8mV    810.1mV
472ps     736.1mV    706.6mV    768.9mV
3ns       714.4mV    680.9mV    745.5mV
[Falling Waveform]
R_fixture= 50.000
V_fixture= 0.0
V_fixture_min= 0.0
V_fixture_max= 0.0
|time   V(typ)   V(min)   V(max)
0s        439.5mV    419.1mV    397.1mV
105ps     439.5mV    419.1mV    396.2mV
143ps     436.1mV    419.1mV    362.2mV
178ps     408.7mV    419mV      258.1mV
248ps     201.7mV    405.2mV    104.9mV
268ps     154.7mV    366.5mV    81.21mV
292ps     112.5mV    256.5mV    60.4mV
349ps     55.93mV    95.99mV    30.54mV
471ps     14.57mV    18.18mV    9.765mV
3ns       2.273mV    189.3uV    3.975mV
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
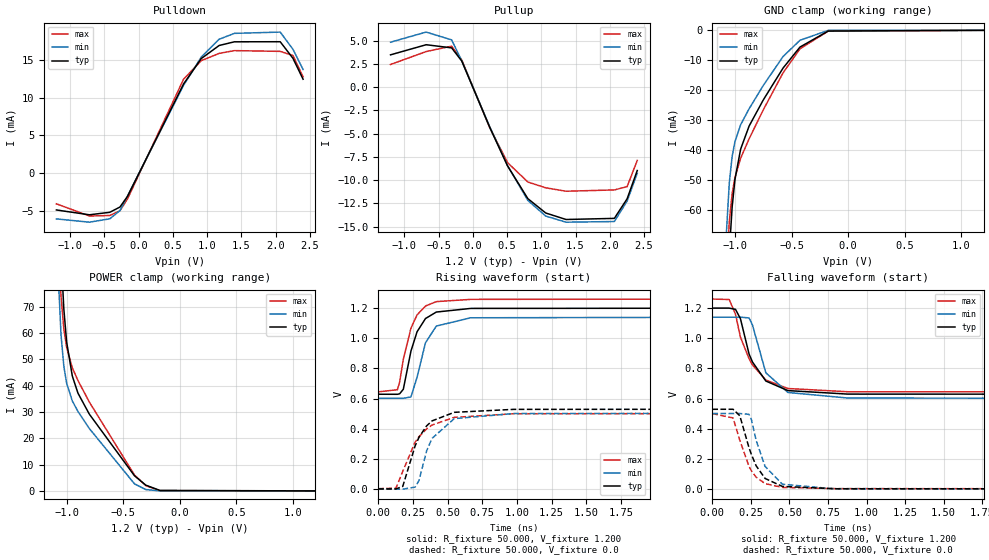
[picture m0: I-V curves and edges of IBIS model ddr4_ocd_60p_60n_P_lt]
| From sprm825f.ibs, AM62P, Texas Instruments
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|   Model ddr4_ocd_60p_60n_P_lt
[Model] ddr4_ocd_60p_60n_P_lt
Model_type I/O
Polarity   Non-Inverting
Enable   Active-High
Vinl =  0.700V
Vinh =  0.900V
Vmeas =  0.600V
C_comp   2.675pF   2.621pF   2.768pF
C_comp_pullup   0.253pF   0.249pF   0.268pF
C_comp_pulldown   1.065pF   1.043pF   1.096pF
[Model Spec]
Vinh   0.900V   0.820V   0.980V
Vinl   0.700V   0.620V   0.780V
Vmeas   0.600V   NA   NA
[Temperature Range]   25.000   -40.000   -40.000
[Voltage Range]   1.200V   1.140V   1.260V
[Pullup Reference]   1.200V   1.140V   1.260V
[Pulldown Reference]   0.0V   0.0V   0.0V
[C Comp Corner]
C_comp_pullup   0.253pF   0.249pF   0.268pF
C_comp_pulldown   1.065pF   1.043pF   1.096pF
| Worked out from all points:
|   slope of the pulldown table from 0 to 0.18 V, typ, clamps not added: 52 ohm
|   slope of the pullup table from 0 to 0.18 V, typ, clamps not added: 56.9 ohm
|   GND clamp passes 1 mA (typ) near -0.25 V on its own axis
|   POWER clamp passes 1 mA (typ) near -0.24 V on its own axis
|   rising waveform, R_fixture 50.000, V_fixture 1.200: 20-80 % time 103ps typ, 102ps min, 104ps max; typ from 0.629 V to 1.2 V
|   rising waveform, R_fixture 50.000, V_fixture 0.0: 20-80 % time 142ps typ, 131ps min, 180ps max; typ from 0.002 V to 0.53 V
|   falling waveform, R_fixture 50.000, V_fixture 1.200: 20-80 % time 129ps typ, 117ps min, 144ps max; typ from 1.2 V to 0.629 V
|   falling waveform, R_fixture 50.000, V_fixture 0.0: 20-80 % time 115ps typ, 105ps min, 109ps max; typ from 0.529 V to 0.002 V
[Pulldown]
|Voltage   I(typ)   I(min)   I(max)
-1.2V     -4.899mA   -6.086mA   -4.083mA
-718mV    -5.542mA   -6.524mA   -5.703mA
-421mV    -5.211mA   -6.076mA   -5.636mA
-272mV    -4.512mA   -4.986mA   -5.005mA
-161mV    -3.08mA    -3.033mA   -3.413mA
656mV     11.83mA    11.65mA    12.46mA
915mV     15.21mA    15.41mA    14.93mA
1.175V    16.94mA    17.77mA    15.89mA
1.398V    17.43mA    18.55mA    16.26mA
2.066V    17.44mA    18.72mA    16.16mA
2.252V    15.24mA    16.44mA    15.61mA
2.4V      12.46mA    13.75mA    12.78mA
[Pullup]
|Voltage   I(typ)   I(min)   I(max)
-1.2V     3.47mA     4.83mA     2.432mA
-680mV    4.558mA    5.917mA    3.824mA
-309mV    4.22mA     5.08mA     4.403mA
-161mV    2.812mA    2.836mA    2.926mA
247mV     -4.313mA   -4.256mA   -4.361mA
507mV     -8.473mA   -8.435mA   -8.119mA
804mV     -12mA      -12.19mA   -10.21mA
1.064V    -13.54mA   -13.87mA   -10.83mA
1.361V    -14.24mA   -14.53mA   -11.2mA
2.066V    -14.12mA   -14.46mA   -11.06mA
2.252V    -12.02mA   -12.26mA   -10.71mA
2.4V      -8.975mA   -9.277mA   -7.887mA
[GND_clamp]
|Voltage   I(typ)   I(min)   I(max)
-1.2V     -423mA     -390.7mA   -407.3mA
-1.075V   -97.83mA   -66.95mA   -80.47mA
-1.05V    -73.83mA   -50.72mA   -63.69mA
-1.025V   -58.88mA   -42.03mA   -54.46mA
-1V       -49.64mA   -37.06mA   -49.02mA
-950mV    -39.6mA    -31.47mA   -42.62mA
-875mV    -31.9mA    -26.14mA   -36.15mA
-750mV    -23.22mA   -18.39mA   -26.52mA
-575mV    -12.59mA   -8.74mA    -14.18mA
-425mV    -5.575mA   -3.312mA   -6.164mA
-175mV    -232.2uA   -7.719uA   -237.1uA
1.2V      0A         0A         0A
[POWER_clamp]
|Voltage   I(typ)   I(min)   I(max)
-1.2V     670.7mA    628.9mA    647.6mA
-1.075V   125.5mA    82.79mA    98.14mA
-1.05V    90.4mA     59.49mA    74.22mA
-1.025V   69.26mA    47.48mA    61.61mA
-1V       56.63mA    40.97mA    54.54mA
-950mV    43.7mA     34.22mA    46.83mA
-900mV    37.19mA    30.22mA    41.98mA
-800mV    29.23mA    23.76mA    33.84mA
-400mV    5.761mA    2.693mA    6.038mA
-300mV    2.19mA     521.5uA    2.013mA
-175mV    202uA      5.489uA    99.3uA
1.2V      0A         0A         0A
[Ramp]
| variable   typ   min   max
dV/dt_r   0.371/0.137n   0.350/0.136n   0.397/0.164n
dV/dt_f   0.371/0.124n   0.349/0.107n   0.396/0.114n
R_load = 60.000
[Rising Waveform]
R_fixture= 50.000
V_fixture= 1.200
V_fixture_min= 1.140
V_fixture_max= 1.260
|time   V(typ)   V(min)   V(max)
0s        629.3mV    602.3mV    645mV
138ps     628.9mV    602.3mV    659.1mV
154ps     631.9mV    602.3mV    706.9mV
181ps     662mV      602.2mV    860.8mV
236ps     915mV      611.3mV    1.067V
280ps     1.043V     741.4mV    1.155V
341ps     1.131V     970.8mV    1.214V
419ps     1.174V     1.081V     1.243V
667ps     1.198V     1.136V     1.258V
3ns       1.2V       1.14V      1.26V
[Rising Waveform]
R_fixture= 50.000
V_fixture= 0.0
V_fixture_min= 0.0
V_fixture_max= 0.0
|time   V(typ)   V(min)   V(max)
0s        1.997mV    179.4uV    3.445mV
128ps     1.949mV    173uV      6.842mV
177ps     18.51mV    171.3uV    118.2mV
266ps     286.7mV    13.64mV    311.8mV
294ps     343.6mV    57.19mV    347.7mV
349ps     419.5mV    254.1mV    399.8mV
388ps     452.6mV    336.5mV    425.1mV
548ps     509.4mV    467.7mV    476mV
978ps     529.1mV    501.3mV    500mV
3ns       529.8mV    503.2mV    501.4mV
[Falling Waveform]
R_fixture= 50.000
V_fixture= 1.200
V_fixture_min= 1.140
V_fixture_max= 1.260
|time   V(typ)   V(min)   V(max)
0s        1.2V       1.14V      1.26V
109ps     1.2V       1.14V      1.257V
150ps     1.192V     1.14V      1.16V
182ps     1.13V      1.14V      1.008V
238ps     895.9mV    1.135V     864.7mV
260ps     843.1mV    1.088V     823.7mV
347ps     716.7mV    771mV      723.5mV
490ps     653.4mV    640.9mV    667.3mV
880ps     630.1mV    604mV      645.7mV
3ns       629.3mV    602.3mV    645mV
[Falling Waveform]
R_fixture= 50.000
V_fixture= 0.0
V_fixture_min= 0.0
V_fixture_max= 0.0
|time   V(typ)   V(min)   V(max)
0s        529.5mV    501.5mV    501mV
134ps     529.8mV    501.5mV    472.3mV
178ps     486.8mV    501.5mV    324.2mV
237ps     277.3mV    496.5mV    153.2mV
253ps     230.4mV    462mV      122.2mV
284ps     154.9mV    323.3mV    79.51mV
342ps     71.14mV    150.6mV    36.99mV
454ps     18.43mV    33.08mV    11.65mV
794ps     3.041mV    1.755mV    3.98mV
3ns       1.978mV    174.9uV    3.436mV
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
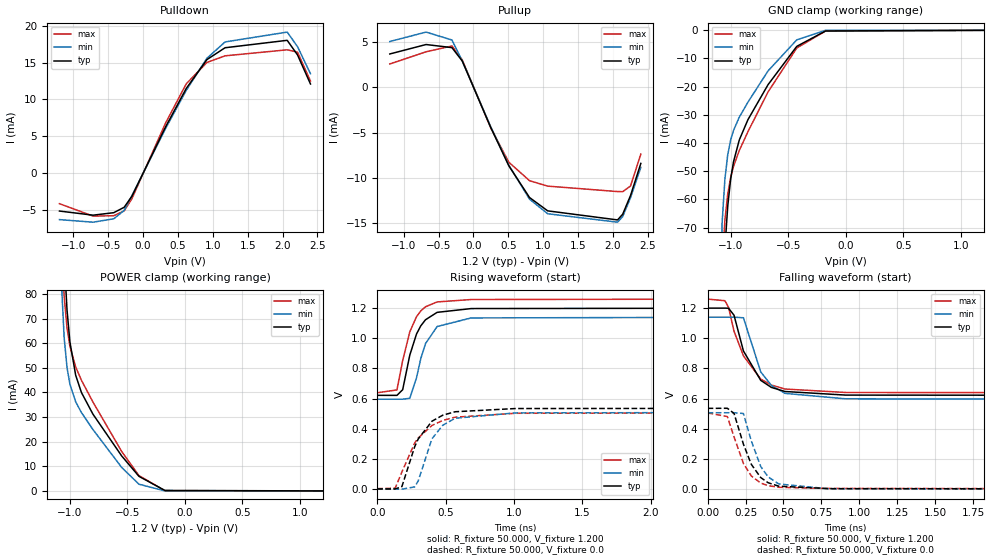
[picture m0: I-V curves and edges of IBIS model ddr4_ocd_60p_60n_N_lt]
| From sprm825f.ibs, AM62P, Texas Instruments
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|   Model ddr4_ocd_60p_60n_N_lt
[Model] ddr4_ocd_60p_60n_N_lt
Model_type I/O
Polarity   Non-Inverting
Enable   Active-High
Vinl =  0.700V
Vinh =  0.900V
Vmeas =  0.600V
C_comp   3.048pF   2.993pF   3.116pF
C_comp_pullup   0.292pF   0.288pF   0.302pF
C_comp_pulldown   1.204pF   1.182pF   1.227pF
[Model Spec]
Vinh   0.900V   0.820V   0.980V
Vinl   0.700V   0.620V   0.780V
Vmeas   0.600V   NA   NA
[Temperature Range]   25.000   -40.000   -40.000
[Voltage Range]   1.200V   1.140V   1.260V
[Pullup Reference]   1.200V   1.140V   1.260V
[Pulldown Reference]   0.0V   0.0V   0.0V
[C Comp Corner]
C_comp_pullup   0.292pF   0.288pF   0.302pF
C_comp_pulldown   1.204pF   1.182pF   1.227pF
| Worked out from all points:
|   slope of the pulldown table from 0 to 0.18 V, typ, clamps not added: 50.6 ohm
|   slope of the pullup table from 0 to 0.18 V, typ, clamps not added: 55.4 ohm
|   GND clamp passes 1 mA (typ) near -0.25 V on its own axis
|   POWER clamp passes 1 mA (typ) near -0.24 V on its own axis
|   rising waveform, R_fixture 50.000, V_fixture 1.200: 20-80 % time 115ps typ, 113ps min, 114ps max; typ from 0.622 V to 1.2 V
|   rising waveform, R_fixture 50.000, V_fixture 0.0: 20-80 % time 157ps typ, 145ps min, 196ps max; typ from 0.002 V to 0.536 V
|   falling waveform, R_fixture 50.000, V_fixture 1.200: 20-80 % time 142ps typ, 130ps min, 159ps max; typ from 1.2 V to 0.622 V
|   falling waveform, R_fixture 50.000, V_fixture 0.0: 20-80 % time 125ps typ, 116ps min, 118ps max; typ from 0.536 V to 0.002 V
[Pulldown]
|Voltage   I(typ)   I(min)   I(max)
-1.2V     -5.186mA   -6.351mA   -4.184mA
-718mV    -5.748mA   -6.702mA   -5.872mA
-421mV    -5.409mA   -6.24mA    -5.822mA
-272mV    -4.672mA   -5.1mA     -5.163mA
-161mV    -3.174mA   -3.096mA   -3.506mA
322mV     6.26mA     6.038mA    6.789mA
619mV     11.5mA     11.24mA    12.13mA
915mV     15.42mA    15.6mA     15.03mA
1.175V    17.03mA    17.82mA    15.93mA
2.066V    18.04mA    19.16mA    16.75mA
2.214V    16.06mA    17.18mA    16.43mA
2.4V      12.1mA     13.49mA    12.5mA
[Pullup]
|Voltage   I(typ)   I(min)   I(max)
-1.2V     3.674mA    5.049mA    2.574mA
-680mV    4.717mA    6.089mA    3.914mA
-309mV    4.374mA    5.216mA    4.558mA
-161mV    2.897mA    2.901mA    3.012mA
247mV     -4.428mA   -4.35mA    -4.478mA
507mV     -8.672mA   -8.603mA   -8.274mA
804mV     -12.17mA   -12.35mA   -10.31mA
1.064V    -13.64mA   -13.96mA   -10.91mA
2.066V    -14.64mA   -14.89mA   -11.51mA
2.14V     -14.01mA   -14.27mA   -11.52mA
2.252V    -11.95mA   -12.19mA   -10.9mA
2.4V      -8.403mA   -8.843mA   -7.368mA
[GND_clamp]
|Voltage   I(typ)   I(min)   I(max)
-1.2V     -425.9mA   -379.8mA   -398.3mA
-1.075V   -101.6mA   -69.04mA   -84.28mA
-1.05V    -77.49mA   -52.88mA   -67.47mA
-1.025V   -62.34mA   -44.08mA   -58.02mA
-1V       -52.87mA   -38.95mA   -52.27mA
-975mV    -46.68mA   -35.53mA   -48.3mA
-925mV    -38.95mA   -30.85mA   -42.67mA
-850mV    -31.75mA   -25.54mA   -36.03mA
-675mV    -19.3mA    -14.42mA   -21.88mA
-425mV    -5.686mA   -3.366mA   -6.273mA
-175mV    -233uA     -7.686uA   -237.7uA
1.2V      0A         0A         0A
[POWER_clamp]
|Voltage   I(typ)   I(min)   I(max)
-1.2V     676.6mA    632.8mA    654.2mA
-1.075V   130.1mA    85.72mA    103.3mA
-1.05V    94.76mA    62.24mA    79.03mA
-1.025V   73.36mA    50.04mA    66.12mA
-1V       60.47mA    43.33mA    58.72mA
-950mV    47.01mA    36.18mA    50.34mA
-900mV    39.97mA    31.83mA    44.95mA
-800mV    31.18mA    24.94mA    36.1mA
-550mV    14.2mA     9.538mA    16.02mA
-400mV    5.928mA    2.735mA    6.211mA
-175mV    202.9uA    5.524uA    99.59uA
1.2V      0A         0A         0A
[Ramp]
| variable   typ   min   max
dV/dt_r   0.381/0.163n   0.357/0.162n   0.406/0.195n
dV/dt_f   0.380/0.147n   0.356/0.131n   0.406/0.132n
R_load = 60.000
[Rising Waveform]
R_fixture= 50.000
V_fixture= 1.200
V_fixture_min= 1.140
V_fixture_max= 1.260
|time   V(typ)   V(min)   V(max)
0s        622mV      596.4mV    639.1mV
144ps     621.8mV    596.4mV    657.9mV
186ps     659.4mV    596.3mV    852.8mV
238ps     888.7mV    602.7mV    1.043V
287ps     1.028V     737.9mV    1.143V
318ps     1.082V     864.4mV    1.181V
353ps     1.123V     965mV      1.209V
438ps     1.172V     1.078V     1.241V
687ps     1.197V     1.135V     1.257V
3ns       1.2V       1.14V      1.26V
[Rising Waveform]
R_fixture= 50.000
V_fixture= 0.0
V_fixture_min= 0.0
V_fixture_max= 0.0
|time   V(typ)   V(min)   V(max)
0s        2.043mV    237.2uV    3.486mV
131ps     1.959mV    217.6uV    6.884mV
180ps     16.77mV    206.3uV    113.6mV
274ps     282.2mV    15.28mV    306.4mV
300ps     333.5mV    56.08mV    339.4mV
400ps     450.4mV    333.8mV    422.3mV
480ps     490.8mV    424.5mV    456.2mV
570ps     513.2mV    470.2mV    477.3mV
1.01ns    534.5mV    505.7mV    503.1mV
3ns       536mV      508.4mV    505.7mV
[Falling Waveform]
R_fixture= 50.000
V_fixture= 1.200
V_fixture_min= 1.140
V_fixture_max= 1.260
|time   V(typ)   V(min)   V(max)
0s        1.2V       1.14V      1.26V
114ps     1.2V       1.14V      1.249V
138ps     1.199V     1.14V      1.205V
174ps     1.153V     1.14V      1.047V
236ps     916.2mV    1.136V     883.9mV
350ps     721.3mV    777.6mV    729.8mV
420ps     674.6mV    687.9mV    690.4mV
510ps     647.4mV    635mV      663.8mV
910ps     623.6mV    598.9mV    640.9mV
3ns       622mV      596.4mV    639.1mV
[Falling Waveform]
R_fixture= 50.000
V_fixture= 0.0
V_fixture_min= 0.0
V_fixture_max= 0.0
|time   V(typ)   V(min)   V(max)
0s        535.8mV    506.7mV    505.4mV
130ps     536.2mV    506.8mV    481.3mV
174ps     502.4mV    506.8mV    347.2mV
236ps     298.1mV    501.6mV    170.3mV
288ps     164.7mV    319.6mV    87.66mV
350ps     77.14mV    150.2mV    40.66mV
399ps     42.72mV    81.39mV    23.57mV
469ps     19.82mV    34.49mV    12.58mV
799ps     3.765mV    2.53mV     4.781mV
3ns       2.022mV    193.6uV    3.477mV
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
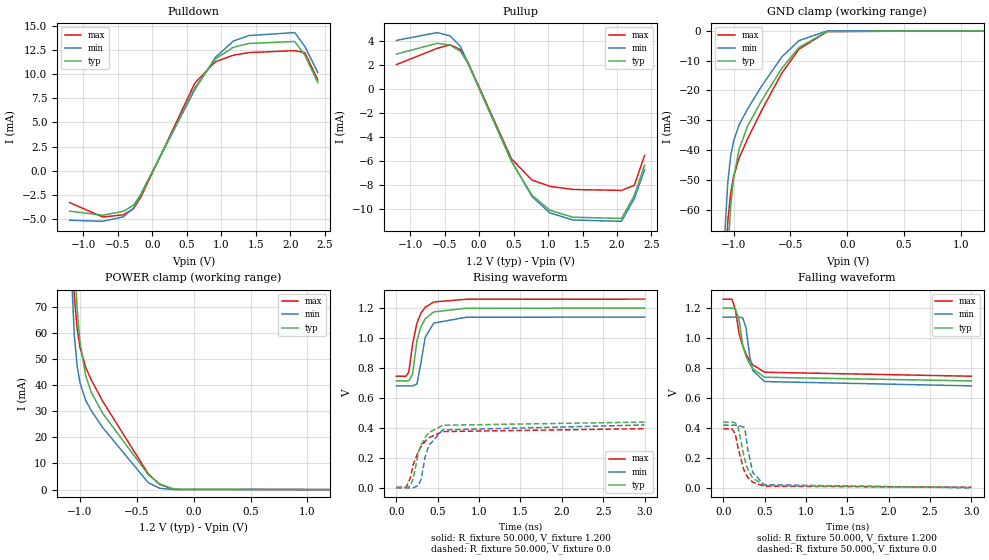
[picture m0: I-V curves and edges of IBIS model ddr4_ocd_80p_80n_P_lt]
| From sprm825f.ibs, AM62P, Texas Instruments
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|   Model ddr4_ocd_80p_80n_P_lt
[Model] ddr4_ocd_80p_80n_P_lt
Model_type I/O
Polarity   Non-Inverting
Enable   Active-High
Vinl =  0.700V
Vinh =  0.900V
Vmeas =  0.600V
C_comp   2.908pF   2.865pF   2.945pF
C_comp_pullup   0.288pF   0.287pF   0.290pF
C_comp_pulldown   1.145pF   1.125pF   1.160pF
[Model Spec]
Vinh   0.900V   0.820V   0.980V
Vinl   0.700V   0.620V   0.780V
Vmeas   0.600V   NA   NA
[Temperature Range]   25.000   -40.000   -40.000
[Voltage Range]   1.200V   1.140V   1.260V
[Pullup Reference]   1.200V   1.140V   1.260V
[Pulldown Reference]   0.0V   0.0V   0.0V
[C Comp Corner]
C_comp_pullup   0.288pF   0.287pF   0.290pF
C_comp_pulldown   1.145pF   1.125pF   1.160pF
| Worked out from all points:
|   slope of the pulldown table from 0 to 0.18 V, typ, clamps not added: 67.6 ohm
|   slope of the pullup table from 0 to 0.18 V, typ, clamps not added: 74.3 ohm
|   GND clamp passes 1 mA (typ) near -0.25 V on its own axis
|   POWER clamp passes 1 mA (typ) near -0.24 V on its own axis
|   rising waveform, R_fixture 50.000, V_fixture 1.200: 20-80 % time 112ps typ, 97.2ps min, 117ps max; typ from 0.714 V to 1.2 V
|   rising waveform, R_fixture 50.000, V_fixture 0.0: 20-80 % time 153ps typ, 140ps min, 184ps max; typ from 0.002 V to 0.439 V
|   falling waveform, R_fixture 50.000, V_fixture 1.200: 20-80 % time 138ps typ, 85.7ps min, 163ps max; typ from 1.2 V to 0.714 V
|   falling waveform, R_fixture 50.000, V_fixture 0.0: 20-80 % time 123ps typ, 94.1ps min, 122ps max; typ from 0.439 V to 0.002 V
[Pulldown]
|Voltage   I(typ)   I(min)   I(max)
-1.2V     -4.165mA   -5.106mA   -3.283mA
-718mV    -4.586mA   -5.214mA   -4.774mA
-421mV    -4.182mA   -4.754mA   -4.542mA
-272mV    -3.547mA   -3.839mA   -3.925mA
-161mV    -2.381mA   -2.323mA   -2.628mA
619mV     8.608mA    8.436mA    9.09mA
915mV     11.56mA    11.72mA    11.27mA
1.175V    12.77mA    13.41mA    11.95mA
1.398V    13.16mA    13.98mA    12.22mA
2.066V    13.37mA    14.29mA    12.42mA
2.214V    11.94mA    12.84mA    12.2mA
2.4V      9.127mA    10.18mA    9.402mA
[Pullup]
|Voltage   I(typ)   I(min)   I(max)
-1.2V     2.935mA    4.075mA    2.058mA
-606mV    3.837mA    4.731mA    3.418mA
-421mV    3.68mA     4.446mA    3.712mA
-272mV    3.164mA    3.59mA     3.311mA
-161mV    2.165mA    2.168mA    2.235mA
470mV     -6.042mA   -6mA       -5.815mA
767mV     -8.854mA   -8.961mA   -7.585mA
1.027V    -10.11mA   -10.33mA   -8.111mA
1.361V    -10.69mA   -10.92mA   -8.373mA
2.066V    -10.79mA   -11.03mA   -8.452mA
2.252V    -8.865mA   -9.124mA   -8.025mA
2.4V      -6.356mA   -6.726mA   -5.529mA
[GND_clamp]
|Voltage   I(typ)   I(min)   I(max)
-1.2V     -423mA     -390.7mA   -407.3mA
-1.075V   -97.83mA   -66.95mA   -80.47mA
-1.05V    -73.83mA   -50.72mA   -63.69mA
-1.025V   -58.88mA   -42.03mA   -54.46mA
-1V       -49.64mA   -37.06mA   -49.02mA
-950mV    -39.6mA    -31.47mA   -42.62mA
-875mV    -31.9mA    -26.14mA   -36.15mA
-750mV    -23.22mA   -18.39mA   -26.52mA
-575mV    -12.59mA   -8.74mA    -14.18mA
-425mV    -5.575mA   -3.312mA   -6.164mA
-175mV    -232.2uA   -7.716uA   -237.1uA
1.2V      0A         0A         0A
[POWER_clamp]
|Voltage   I(typ)   I(min)   I(max)
-1.2V     670.7mA    628.9mA    647.6mA
-1.075V   125.5mA    82.79mA    98.14mA
-1.05V    90.4mA     59.49mA    74.22mA
-1.025V   69.26mA    47.48mA    61.61mA
-1V       56.63mA    40.97mA    54.54mA
-950mV    43.7mA     34.22mA    46.83mA
-900mV    37.19mA    30.22mA    41.98mA
-800mV    29.23mA    23.76mA    33.84mA
-400mV    5.761mA    2.693mA    6.038mA
-300mV    2.19mA     521.5uA    2.013mA
-175mV    201.9uA    5.487uA    99.31uA
1.2V      0A         0A         0A
[Ramp]
| variable   typ   min   max
dV/dt_r   0.324/0.158n   0.305/0.150n   0.345/0.197n
dV/dt_f   0.324/0.132n   0.304/86.503p   0.344/0.127n
R_load = 60.000
[Rising Waveform]
R_fixture= 50.000
V_fixture= 1.200
V_fixture_min= 1.140
V_fixture_max= 1.260
|time   V(typ)   V(min)   V(max)
0s        714.2mV    681mV      745.3mV
115ps     714.2mV    681mV      745.5mV
150ps     715.5mV    681mV      772.2mV
195ps     759mV      680.5mV    958.5mV
248ps     979.5mV    693.4mV    1.1V
296ps     1.075V     833.6mV    1.166V
349ps     1.129V     1.007V     1.206V
452ps     1.175V     1.1V       1.241V
842ps     1.199V     1.139V     1.259V
3ns       1.2V       1.14V      1.26V
[Rising Waveform]
R_fixture= 50.000
V_fixture= 0.0
V_fixture_min= 0.0
V_fixture_max= 0.0
|time   V(typ)   V(min)   V(max)
0s        2.292mV    205.7uV    3.978mV
119ps     2.279mV    199.4uV    4.933mV
167ps     11.52mV    196.7uV    65.42mV
203ps     60.46mV    175.7uV    154.2mV
265ps     232.4mV    16.76mV    243mV
299ps     284.8mV    57.77mV    276.3mV
349ps     337.9mV    211.1mV    312.5mV
393ps     368.7mV    284mV      335mV
560ps     418.1mV    387.1mV    376mV
3ns       439.3mV    419.9mV    395.5mV
[Falling Waveform]
R_fixture= 50.000
V_fixture= 1.200
V_fixture_min= 1.140
V_fixture_max= 1.260
|time   V(typ)   V(min)   V(max)
0s        1.2V       1.14V      1.26V
106ps     1.2V       1.14V      1.259V
147ps     1.195V     1.14V      1.19V
194ps     1.117V     1.14V      1.024V
236ps     950.4mV    1.135V     948.8mV
276ps     879.2mV    1.069V     893.6mV
319ps     827.6mV    885.2mV    850mV
358ps     794mV      783.3mV    821.8mV
502ps     738.5mV    709.7mV    772mV
3ns       714.2mV    681mV      745.3mV
[Falling Waveform]
R_fixture= 50.000
V_fixture= 0.0
V_fixture_min= 0.0
V_fixture_max= 0.0
|time   V(typ)   V(min)   V(max)
0s        439mV      418.2mV    395.2mV
106ps     439mV      418.2mV    393.9mV
145ps     434.1mV    418.2mV    361.8mV
179ps     409.6mV    418.2mV    267.8mV
249ps     218mV      404.5mV    121.5mV
267ps     176.5mV    376.2mV    98.99mV
297ps     124.9mV    257.6mV    70.91mV
358ps     64.3mV     101.9mV    37.36mV
497ps     17.06mV    21.25mV    11.61mV
3ns       2.27mV     188.1uV    3.969mV
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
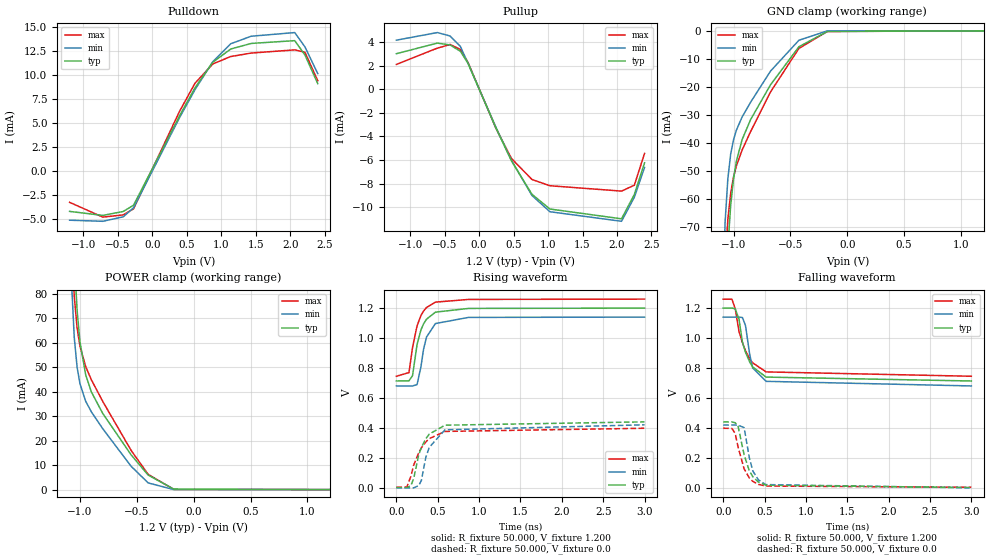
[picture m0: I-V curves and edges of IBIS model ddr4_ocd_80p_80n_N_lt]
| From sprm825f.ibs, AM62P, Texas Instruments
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|   Model ddr4_ocd_80p_80n_N_lt
[Model] ddr4_ocd_80p_80n_N_lt
Model_type I/O
Polarity   Non-Inverting
Enable   Active-High
Vinl =  0.700V
Vinh =  0.900V
Vmeas =  0.600V
C_comp   3.246pF   3.204pF   3.263pF
C_comp_pullup   0.321pF   0.321pF   0.322pF
C_comp_pulldown   1.272pF   1.252pF   1.281pF
[Model Spec]
Vinh   0.900V   0.820V   0.980V
Vinl   0.700V   0.620V   0.780V
Vmeas   0.600V   NA   NA
[Temperature Range]   25.000   -40.000   -40.000
[Voltage Range]   1.200V   1.140V   1.260V
[Pullup Reference]   1.200V   1.140V   1.260V
[Pulldown Reference]   0.0V   0.0V   0.0V
[C Comp Corner]
C_comp_pullup   0.322pF   0.321pF   0.321pF
C_comp_pulldown   1.272pF   1.252pF   1.281pF
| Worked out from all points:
|   slope of the pulldown table from 0 to 0.18 V, typ, clamps not added: 67.5 ohm
|   slope of the pullup table from 0 to 0.18 V, typ, clamps not added: 73.9 ohm
|   GND clamp passes 1 mA (typ) near -0.25 V on its own axis
|   POWER clamp passes 1 mA (typ) near -0.24 V on its own axis
|   rising waveform, R_fixture 50.000, V_fixture 1.200: 20-80 % time 125ps typ, 110ps min, 130ps max; typ from 0.714 V to 1.2 V
|   rising waveform, R_fixture 50.000, V_fixture 0.0: 20-80 % time 170ps typ, 154ps min, 201ps max; typ from 0.002 V to 0.441 V
|   falling waveform, R_fixture 50.000, V_fixture 1.200: 20-80 % time 153ps typ, 105ps min, 180ps max; typ from 1.2 V to 0.714 V
|   falling waveform, R_fixture 50.000, V_fixture 0.0: 20-80 % time 135ps typ, 107ps min, 133ps max; typ from 0.441 V to 0.002 V
[Pulldown]
|Voltage   I(typ)   I(min)   I(max)
-1.2V     -4.226mA   -5.142mA   -3.284mA
-718mV    -4.644mA   -5.256mA   -4.821mA
-421mV    -4.233mA   -4.786mA   -4.59mA
-272mV    -3.58mA    -3.848mA   -3.956mA
396mV     5.729mA    5.54mA     6.191mA
619mV     8.627mA    8.431mA    9.102mA
878mV     11.29mA    11.35mA    11.11mA
1.138V    12.66mA    13.21mA    11.88mA
1.435V    13.24mA    13.99mA    12.24mA
2.066V    13.53mA    14.37mA    12.57mA
2.214V    12.04mA    12.88mA    12.32mA
2.4V      9.059mA    10.1mA     9.364mA
[Pullup]
|Voltage   I(typ)   I(min)   I(max)
-1.2V     3.001mA    4.145mA    2.093mA
-606mV    3.897mA    4.788mA    3.469mA
-421mV    3.739mA    4.497mA    3.78mA
-272mV    3.206mA    3.614mA    3.367mA
-161mV    2.182mA    2.179mA    2.262mA
247mV     -3.321mA   -3.266mA   -3.355mA
470mV     -6.079mA   -6.028mA   -5.872mA
767mV     -8.898mA   -8.998mA   -7.645mA
1.027V    -10.14mA   -10.37mA   -8.171mA
2.066V    -10.97mA   -11.18mA   -8.625mA
2.252V    -8.911mA   -9.143mA   -8.127mA
2.4V      -6.233mA   -6.623mA   -5.434mA
[GND_clamp]
|Voltage   I(typ)   I(min)   I(max)
-1.2V     -425.9mA   -379.8mA   -398.3mA
-1.075V   -101.6mA   -69.04mA   -84.28mA
-1.05V    -77.49mA   -52.88mA   -67.47mA
-1.025V   -62.34mA   -44.08mA   -58.02mA
-1V       -52.87mA   -38.95mA   -52.27mA
-975mV    -46.68mA   -35.53mA   -48.3mA
-925mV    -38.95mA   -30.85mA   -42.67mA
-850mV    -31.75mA   -25.54mA   -36.03mA
-675mV    -19.3mA    -14.42mA   -21.88mA
-425mV    -5.686mA   -3.366mA   -6.273mA
-175mV    -233uA     -7.686uA   -237.7uA
1.2V      0A         0A         0A
[POWER_clamp]
|Voltage   I(typ)   I(min)   I(max)
-1.2V     676.6mA    632.8mA    654.2mA
-1.075V   130.1mA    85.72mA    103.3mA
-1.05V    94.76mA    62.24mA    79.03mA
-1.025V   73.36mA    50.04mA    66.12mA
-1V       60.47mA    43.33mA    58.72mA
-950mV    47.01mA    36.18mA    50.34mA
-900mV    39.97mA    31.83mA    44.95mA
-800mV    31.18mA    24.94mA    36.1mA
-550mV    14.2mA     9.538mA    16.02mA
-400mV    5.928mA    2.735mA    6.211mA
-175mV    202.8uA    5.523uA    99.57uA
1.2V      0A         0A         0A
[Ramp]
| variable   typ   min   max
dV/dt_r   0.326/0.192n   0.306/0.184n   0.348/0.241n
dV/dt_f   0.326/0.160n   0.305/0.110n   0.347/0.149n
R_load = 60.000
[Rising Waveform]
R_fixture= 50.000
V_fixture= 1.200
V_fixture_min= 1.140
V_fixture_max= 1.260
|time   V(typ)   V(min)   V(max)
0s        713.6mV    680.6mV    745.2mV
152ps     714.6mV    680.6mV    769.5mV
195ps     749.2mV    680.2mV    937.6mV
250ps     957.6mV    689.8mV    1.082V
297ps     1.055V     809.9mV    1.151V
328ps     1.094V     924.5mV    1.18V
364ps     1.126V     1.007V     1.204V
472ps     1.173V     1.097V     1.24V
872ps     1.198V     1.138V     1.258V
3ns       1.2V       1.14V      1.26V
[Rising Waveform]
R_fixture= 50.000
V_fixture= 0.0
V_fixture_min= 0.0
V_fixture_max= 0.0
|time   V(typ)   V(min)   V(max)
0s        2.336mV    274.1uV    4.012mV
127ps     2.268mV    252.6uV    7.077mV
175ps     14.88mV    244.9uV    76.95mV
209ps     62.29mV    199.7uV    151.7mV
271ps     223.1mV    15.87mV    236.3mV
302ps     269.7mV    50.01mV    266.7mV
355ps     327.6mV    202.4mV    306.1mV
397ps     358.9mV    270.2mV    328.6mV
587ps     418.5mV    387.6mV    376.9mV
3ns       440.8mV    421.1mV    398.1mV
[Falling Waveform]
R_fixture= 50.000
V_fixture= 1.200
V_fixture_min= 1.140
V_fixture_max= 1.260
|time   V(typ)   V(min)   V(max)
0s        1.2V       1.14V      1.26V
106ps     1.2V       1.14V      1.259V
145ps     1.196V     1.14V      1.197V
191ps     1.126V     1.14V      1.044V
233ps     972.5mV    1.137V     968.7mV
270ps     904.9mV    1.083V     915.3mV
320ps     840.7mV    892.2mV    862.1mV
356ps     807.5mV    800.8mV    834.6mV
519ps     739.6mV    711.2mV    774.2mV
3ns       713.5mV    680.5mV    745.2mV
[Falling Waveform]
R_fixture= 50.000
V_fixture= 0.0
V_fixture_min= 0.0
V_fixture_max= 0.0
|time   V(typ)   V(min)   V(max)
0s        440.6mV    419.3mV    397.8mV
104ps     440.6mV    419.3mV    397mV
145ps     434.8mV    419.3mV    364.4mV
180ps     411.6mV    419.3mV    272.2mV
253ps     220.4mV    402mV      127.6mV
316ps     114.1mV    201.4mV    66.1mV
359ps     74.13mV    112.3mV    43.08mV
426ps     38.76mV    53.15mV    23.52mV
516ps     17.73mV    22.07mV    12.27mV
3ns       2.309mV    205.9uV    4.001mV
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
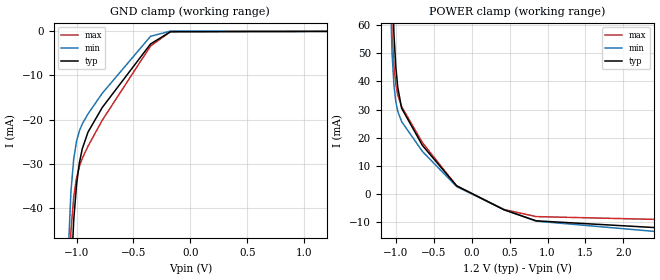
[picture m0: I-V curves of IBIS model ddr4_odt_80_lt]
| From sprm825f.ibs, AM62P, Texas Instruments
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|   Model ddr4_odt_80_lt
[Model] ddr4_odt_80_lt
Model_type Input
Polarity   Non-Inverting
Enable   Active-High
Vinl =  0.700V
Vinh =  0.900V
C_comp   2.643pF   2.505pF   2.684pF
[Model Spec]
Vinh   0.900V   0.820V   0.980V
Vinl   0.700V   0.620V   0.780V
[Temperature Range]   25.000   -40.000   -40.000
[Voltage Range]   1.200V   1.140V   1.260V
[C Comp Corner]
C_comp   2.643pF   2.505pF   2.684pF
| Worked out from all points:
|   GND clamp passes 1 mA (typ) near -0.26 V on its own axis
|   POWER clamp passes 1 mA (typ) near -0.07 V on its own axis
[GND_clamp]
|Voltage   I(typ)   I(min)   I(max)
-1.2V     -390mA     -354.4mA   -365.5mA
-1.075V   -79.16mA   -51.46mA   -60.71mA
-1.05V    -56.54mA   -36.5mA    -45.42mA
-1.025V   -42.79mA   -28.87mA   -37.47mA
-1V       -34.66mA   -24.88mA   -33.19mA
-975mV    -29.76mA   -22.56mA   -30.62mA
-950mV    -26.65mA   -21mA      -28.82mA
-900mV    -22.88mA   -18.75mA   -26.08mA
-775mV    -17.29mA   -14.06mA   -20.18mA
-350mV    -2.859mA   -1.117mA   -3.321mA
-175mV    -75.7uA    73.71uA    -64.86uA
1.2V      0A         0A         0A
[POWER_clamp]
|Voltage   I(typ)   I(min)   I(max)
-1.2V     597.6mA    615.2mA    625.3mA
-1.075V   109.3mA    72.51mA    80.02mA
-1.05V    76.4mA     49.89mA    56.93mA
-1.025V   56.58mA    38.56mA    45.15mA
-1V       44.9mA     32.71mA    38.91mA
-975mV    37.91mA    29.41mA    35.26mA
-925mV    30.57mA    25.81mA    31.1mA
-650mV    17.31mA    15.18mA    18.31mA
-200mV    2.999mA    2.718mA    2.973mA
425mV     -5.529mA   -5.478mA   -5.417mA
850mV     -9.45mA    -9.557mA   -7.948mA
2.4V      -11.82mA   -13.18mA   -8.928mA
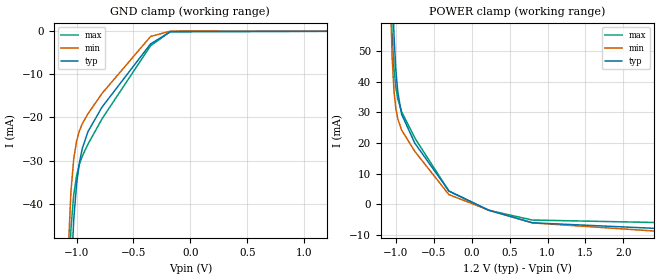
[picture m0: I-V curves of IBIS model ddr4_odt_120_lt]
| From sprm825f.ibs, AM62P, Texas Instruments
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|   Model ddr4_odt_120_lt
[Model] ddr4_odt_120_lt
Model_type Input
Polarity   Non-Inverting
Enable   Active-High
Vinl =  0.700V
Vinh =  0.900V
C_comp   2.747pF   2.621pF   2.767pF
[Model Spec]
Vinh   0.900V   0.820V   0.980V
Vinl   0.700V   0.620V   0.780V
[Temperature Range]   25.000   -40.000   -40.000
[Voltage Range]   1.200V   1.140V   1.260V
[C Comp Corner]
C_comp   2.747pF   2.621pF   2.767pF
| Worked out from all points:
|   GND clamp passes 1 mA (typ) near -0.26 V on its own axis
|   POWER clamp passes 1 mA (typ) near -0.11 V on its own axis
[GND_clamp]
|Voltage   I(typ)   I(min)   I(max)
-1.2V     -392.1mA   -356.2mA   -367.1mA
-1.075V   -80.41mA   -52.45mA   -61.46mA
-1.05V    -57.63mA   -37.36mA   -46.01mA
-1.025V   -43.73mA   -29.6mA    -37.92mA
-1V       -35.46mA   -25.49mA   -33.51mA
-975mV    -30.44mA   -23.08mA   -30.84mA
-950mV    -27.21mA   -21.46mA   -28.98mA
-900mV    -23.27mA   -19.14mA   -26.19mA
-775mV    -17.54mA   -14.37mA   -20.26mA
-350mV    -2.936mA   -1.214mA   -3.35mA
-175mV    -96.01uA   47.81uA    -71.2uA
1.2V      0A         0A         0A
[POWER_clamp]
|Voltage   I(typ)   I(min)   I(max)
-1.2V     596.6mA    613.8mA    624.7mA
-1.075V   108.2mA    71.04mA    79.28mA
-1.05V    75.33mA    48.41mA    56.17mA
-1.025V   55.49mA    37.06mA    44.38mA
-1V       43.79mA    31.21mA    38.12mA
-975mV    36.78mA    27.89mA    34.46mA
-925mV    29.41mA    24.26mA    30.27mA
-750mV    19.93mA    17.24mA    21.62mA
-300mV    4.272mA    3.086mA    4.235mA
225mV     -2.009mA   -1.979mA   -2.034mA
800mV     -6.106mA   -6.152mA   -5.215mA
2.4V      -7.918mA   -8.786mA   -6.008mA
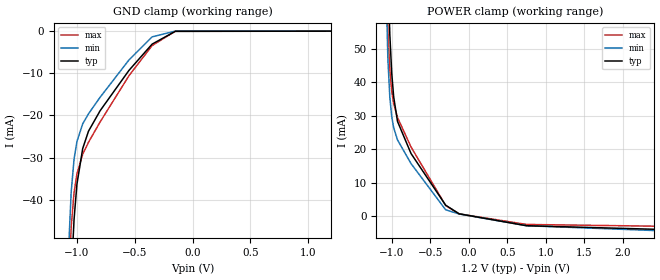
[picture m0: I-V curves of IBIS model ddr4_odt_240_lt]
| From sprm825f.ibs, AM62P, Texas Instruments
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|   Model ddr4_odt_240_lt
[Model] ddr4_odt_240_lt
Model_type Input
Polarity   Non-Inverting
Enable   Active-High
Vinl =  0.700V
Vinh =  0.900V
C_comp   2.855pF   2.749pF   2.860pF
[Model Spec]
Vinh   0.900V   0.820V   0.980V
Vinl   0.700V   0.620V   0.780V
[Temperature Range]   25.000   -40.000   -40.000
[Voltage Range]   1.200V   1.140V   1.260V
[C Comp Corner]
C_comp   2.860pF   2.749pF   2.855pF
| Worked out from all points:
|   GND clamp passes 1 mA (typ) near -0.26 V on its own axis
|   POWER clamp passes 1 mA (typ) near -0.18 V on its own axis
[GND_clamp]
|Voltage   I(typ)   I(min)   I(max)
-1.2V     -394.1mA   -358mA     -368.6mA
-1.075V   -81.66mA   -53.49mA   -62.18mA
-1.05V    -58.74mA   -38.27mA   -46.59mA
-1.025V   -44.71mA   -30.39mA   -38.37mA
-1V       -36.31mA   -26.19mA   -33.86mA
-950mV    -27.85mA   -22mA      -29.21mA
-900mV    -23.75mA   -19.62mA   -26.38mA
-800mV    -18.91mA   -15.71mA   -21.58mA
-550mV    -9.313mA   -6.837mA   -10.58mA
-350mV    -3.084mA   -1.363mA   -3.433mA
-150mV    -50.79uA   17.46uA    -27.48uA
1.2V      0A         0A         0A
[POWER_clamp]
|Voltage   I(typ)   I(min)   I(max)
-1.2V     595.8mA    612.5mA    624mA
-1.075V   107.2mA    69.63mA    78.56mA
-1.05V    74.3mA     46.98mA    55.44mA
-1.025V   54.44mA    35.62mA    43.64mA
-1V       42.72mA    29.75mA    37.37mA
-975mV    35.7mA     26.41mA    33.69mA
-925mV    28.29mA    22.75mA    29.46mA
-750mV    18.7mA     15.68mA    20.66mA
-300mV    3.184mA    1.812mA    3.097mA
-125mV    614.2uA    565uA      602.8uA
750mV     -2.951mA   -2.955mA   -2.567mA
2.4V      -4.008mA   -4.386mA   -3.088mA
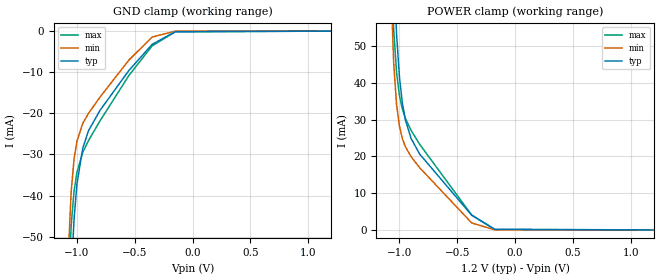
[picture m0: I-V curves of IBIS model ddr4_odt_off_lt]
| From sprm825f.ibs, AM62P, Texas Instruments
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|   Model ddr4_odt_off_lt
[Model] ddr4_odt_off_lt
Model_type Input
Polarity   Non-Inverting
Enable   Active-High
Vinl =  0.700V
Vinh =  0.900V
C_comp   2.937pF   2.862pF   2.961pF
[Model Spec]
Vinh   0.900V   0.820V   0.980V
Vinl   0.700V   0.620V   0.780V
[Temperature Range]   25.000   -40.000   -40.000
[Voltage Range]   1.200V   1.140V   1.260V
[C Comp Corner]
C_comp   2.961pF   2.862pF   2.937pF
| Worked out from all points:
|   GND clamp passes 1 mA (typ) near -0.25 V on its own axis
|   POWER clamp passes 1 mA (typ) near -0.25 V on its own axis
[GND_clamp]
|Voltage   I(typ)   I(min)   I(max)
-1.2V     -396.3mA   -359.8mA   -370.5mA
-1.075V   -83.01mA   -54.49mA   -63.09mA
-1.05V    -59.94mA   -39.13mA   -47.34mA
-1.025V   -45.76mA   -31.13mA   -38.98mA
-1V       -37.22mA   -26.81mA   -34.35mA
-950mV    -28.52mA   -22.47mA   -29.52mA
-900mV    -24.24mA   -20.01mA   -26.64mA
-800mV    -19.27mA   -16.04mA   -21.82mA
-550mV    -9.558mA   -7.033mA   -10.79mA
-350mV    -3.25mA    -1.463mA   -3.61mA
-150mV    -148.5uA   -4.426uA   -178.6uA
1.2V      0A         0A         0A
[POWER_clamp]
|Voltage   I(typ)   I(min)   I(max)
-1.2V     594.8mA    611.1mA    623.3mA
-1.075V   106.2mA    68.17mA    77.82mA
-1.05V    73.23mA    45.5mA     54.69mA
-1.025V   53.35mA    34.13mA    42.87mA
-1V       41.61mA    28.24mA    36.59mA
-975mV    34.57mA    24.89mA    32.89mA
-950mV    30.13mA    22.75mA    30.44mA
-900mV    24.94mA    19.98mA    27.14mA
-825mV    20.64mA    16.93mA    23.3mA
-375mV    4.012mA    1.917mA    4.064mA
-175mV    200.6uA    5.454uA    99.22uA
1.2V      0A         0A         0A
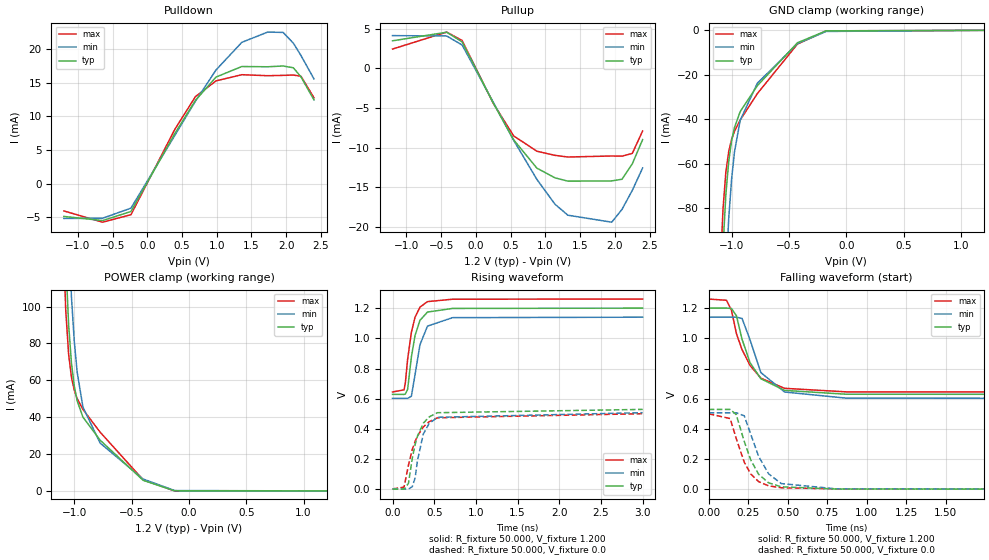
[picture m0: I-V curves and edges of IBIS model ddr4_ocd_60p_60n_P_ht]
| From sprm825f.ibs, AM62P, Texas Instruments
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|   Model ddr4_ocd_60p_60n_P_ht
[Model] ddr4_ocd_60p_60n_P_ht
Model_type I/O
Polarity   Non-Inverting
Enable   Active-High
Vinl =  0.700V
Vinh =  0.900V
Vmeas =  0.600V
C_comp   2.675pF   2.664pF   2.768pF
C_comp_pullup   0.253pF   0.251pF   0.268pF
C_comp_pulldown   1.065pF   1.062pF   1.096pF
[Model Spec]
Vinh   0.900V   0.820V   0.980V
Vinl   0.700V   0.620V   0.780V
Vmeas   0.600V   NA   NA
[Temperature Range]   25.000   0.125k   -40.000
[Voltage Range]   1.200V   1.140V   1.260V
[Pullup Reference]   1.200V   1.140V   1.260V
[Pulldown Reference]   0.0V   0.0V   0.0V
[C Comp Corner]
C_comp_pullup   0.253pF   0.251pF   0.268pF
C_comp_pulldown   1.065pF   1.062pF   1.096pF
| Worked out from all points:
|   slope of the pulldown table from 0 to 0.18 V, typ, clamps not added: 52 ohm
|   slope of the pullup table from 0 to 0.18 V, typ, clamps not added: 56.9 ohm
|   GND clamp passes 1 mA (typ) near -0.25 V on its own axis
|   POWER clamp passes 1 mA (typ) near -0.24 V on its own axis
|   rising waveform, R_fixture 50.000, V_fixture 1.200: 20-80 % time 104ps typ, 111ps min, 104ps max; typ from 0.629 V to 1.2 V
|   rising waveform, R_fixture 50.000, V_fixture 0.0: 20-80 % time 142ps typ, 124ps min, 179ps max; typ from 0.002 V to 0.53 V
|   falling waveform, R_fixture 50.000, V_fixture 1.200: 20-80 % time 128ps typ, 124ps min, 144ps max; typ from 1.2 V to 0.629 V
|   falling waveform, R_fixture 50.000, V_fixture 0.0: 20-80 % time 115ps typ, 125ps min, 110ps max; typ from 0.529 V to 0.002 V
[Pulldown]
|Voltage   I(typ)   I(min)   I(max)
-1.2V     -4.899mA   -5.203mA   -4.083mA
-643mV    -5.518mA   -5.168mA   -5.758mA
-235mV    -4.162mA   -3.667mA   -4.641mA
396mV     7.441mA    7.165mA    8.065mA
693mV     12.39mA    12.27mA    12.95mA
990mV     15.87mA    16.93mA    15.3mA
1.361V    17.44mA    21.04mA    16.22mA
1.732V    17.4mA     22.57mA    16.07mA
1.955V    17.52mA    22.52mA    16.12mA
2.103V    17.25mA    20.92mA    16.17mA
2.214V    15.87mA    19.05mA    15.98mA
2.4V      12.46mA    15.59mA    12.78mA
[Pullup]
|Voltage   I(typ)   I(min)   I(max)
-1.2V     3.47mA     4.123mA    2.432mA
-421mV    4.553mA    4.082mA    4.569mA
-198mV    3.335mA    2.939mA    3.508mA
247mV     -4.313mA   -4.219mA   -4.361mA
544mV     -9.01mA    -9.07mA    -8.515mA
878mV     -12.57mA   -13.99mA   -10.44mA
1.138V    -13.79mA   -17.11mA   -10.96mA
1.324V    -14.21mA   -18.5mA    -11.17mA
1.955V    -14.18mA   -19.38mA   -11.04mA
2.103V    -13.97mA   -17.77mA   -11.06mA
2.252V    -12.02mA   -15.36mA   -10.71mA
2.4V      -8.975mA   -12.55mA   -7.887mA
[GND_clamp]
|Voltage   I(typ)   I(min)   I(max)
-1.2V     -423mA     -507.2mA   -407.3mA
-1.1V     -134.4mA   -193.5mA   -110.3mA
-1.075V   -97.83mA   -145.9mA   -80.47mA
-1.05V    -73.83mA   -110.2mA   -63.69mA
-1.025V   -58.88mA   -84.64mA   -54.46mA
-1V       -49.64mA   -66.89mA   -49.02mA
-975mV    -43.7mA    -54.73mA   -45.38mA
-925mV    -36.51mA   -40.43mA   -40.3mA
-775mV    -24.85mA   -23.75mA   -28.4mA
-425mV    -5.575mA   -5.99mA    -6.164mA
-175mV    -232.1uA   -495.6uA   -237.1uA
1.2V      0A         0A         0A
[POWER_clamp]
|Voltage   I(typ)   I(min)   I(max)
-1.2V     670.7mA    714.9mA    647.6mA
-1.1V     181mA      257.1mA    142.6mA
-1.075V   125.5mA    190mA      98.14mA
-1.05V    90.4mA     140.3mA    74.22mA
-1.025V   69.26mA    105.1mA    61.61mA
-1V       56.63mA    80.77mA    54.54mA
-975mV    48.83mA    64.32mA    50.06mA
-925mV    40.03mA    45.47mA    44.24mA
-775mV    27.54mA    25.97mA    31.88mA
-400mV    5.761mA    6.431mA    6.038mA
-125mV    43.18uA    212.5uA    14.4uA
1.2V      0A         0A         0A
[Ramp]
| variable   typ   min   max
dV/dt_r   0.371/0.137n   0.345/0.140n   0.397/0.163n
dV/dt_f   0.371/0.124n   0.345/0.129n   0.396/0.114n
R_load = 60.000
[Rising Waveform]
R_fixture= 50.000
V_fixture= 1.200
V_fixture_min= 1.140
V_fixture_max= 1.260
|time   V(typ)   V(min)   V(max)
0s        629.3mV    602.9mV    645mV
138ps     628.9mV    602.9mV    659.1mV
154ps     631.9mV    602.9mV    707mV
181ps     662.3mV    602.6mV    861mV
226ps     875.8mV    616.8mV    1.039V
270ps     1.019V     759.7mV    1.14V
329ps     1.119V     957.1mV    1.206V
419ps     1.174V     1.081V     1.243V
720ps     1.198V     1.137V     1.259V
3ns       1.2V       1.14V      1.26V
[Rising Waveform]
R_fixture= 50.000
V_fixture= 0.0
V_fixture_min= 0.0
V_fixture_max= 0.0
|time   V(typ)   V(min)   V(max)
0s        1.997mV    2.356mV    3.445mV
138ps     1.914mV    2.353mV    15.62mV
191ps     39.94mV    2.374mV    160.6mV
237ps     207.4mV    18.88mV    264.7mV
271ps     297.6mV    76.09mV    318.4mV
300ps     354.1mV    193.9mV    354.5mV
369ps     438.1mV    366.3mV    413.7mV
439ps     480mV      436.7mV    448.2mV
539ps     507.9mV    477.5mV    474.4mV
3ns       529.8mV    508.2mV    501.4mV
[Falling Waveform]
R_fixture= 50.000
V_fixture= 1.200
V_fixture_min= 1.140
V_fixture_max= 1.260
|time   V(typ)   V(min)   V(max)
0s        1.2V       1.14V      1.26V
113ps     1.2V       1.14V      1.252V
144ps     1.198V     1.14V      1.187V
176ps     1.149V     1.14V      1.03V
211ps     994.8mV    1.132V     925.8mV
262ps     838.7mV    989.7mV    820.5mV
330ps     733.1mV    773.8mV    736.8mV
480ps     655.6mV    645mV      669.4mV
870ps     630.2mV    604.4mV    645.8mV
3ns       629.3mV    602.6mV    645mV
[Falling Waveform]
R_fixture= 50.000
V_fixture= 0.0
V_fixture_min= 0.0
V_fixture_max= 0.0
|time   V(typ)   V(min)   V(max)
0s        529.5mV    507.4mV    501mV
136ps     529.6mV    507.4mV    469.2mV
174ps     496.3mV    507.4mV    338.4mV
225ps     318.6mV    487.5mV    181.2mV
266ps     196mV      366.2mV    102.5mV
316ps     100.5mV    219.6mV    51.9mV
379ps     44.18mV    103.8mV    24mV
459ps     17.53mV    39.04mV    11.22mV
809ps     2.964mV    3.908mV    3.936mV
3ns       1.978mV    2.19mV     3.436mV
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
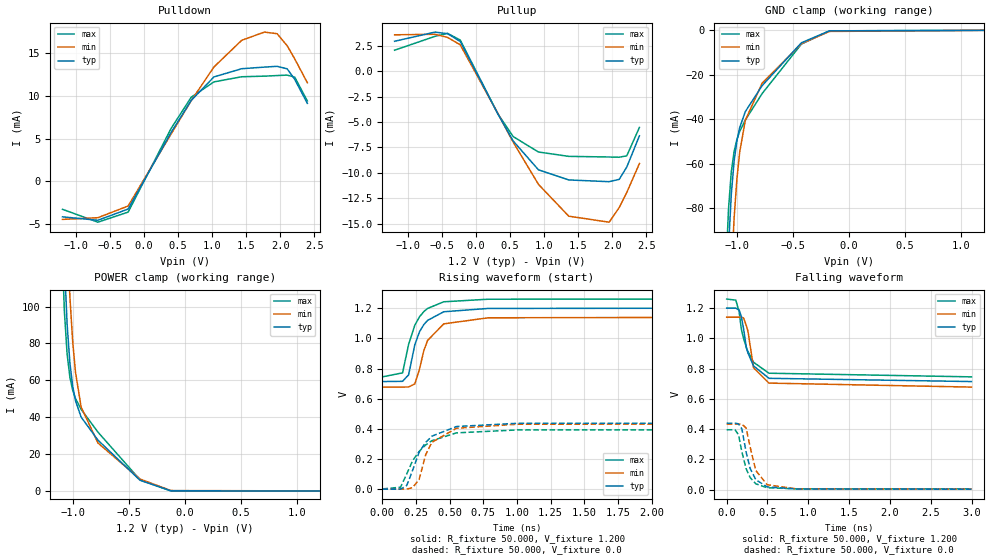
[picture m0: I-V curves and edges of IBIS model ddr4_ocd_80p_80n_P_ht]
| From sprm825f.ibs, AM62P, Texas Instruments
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|   Model ddr4_ocd_80p_80n_P_ht
[Model] ddr4_ocd_80p_80n_P_ht
Model_type I/O
Polarity   Non-Inverting
Enable   Active-High
Vinl =  0.700V
Vinh =  0.900V
Vmeas =  0.600V
C_comp   2.934pF   2.908pF   2.945pF
C_comp_pullup   0.290pF   0.288pF   0.292pF
C_comp_pulldown   1.154pF   1.145pF   1.160pF
[Model Spec]
Vinh   0.900V   0.820V   0.980V
Vinl   0.700V   0.620V   0.780V
Vmeas   0.600V   NA   NA
[Temperature Range]   25.000   0.125k   -40.000
[Voltage Range]   1.200V   1.140V   1.260V
[Pullup Reference]   1.200V   1.140V   1.260V
[Pulldown Reference]   0.0V   0.0V   0.0V
[C Comp Corner]
C_comp_pullup   0.288pF   0.292pF   0.290pF
C_comp_pulldown   1.145pF   1.154pF   1.160pF
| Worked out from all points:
|   slope of the pulldown table from 0 to 0.18 V, typ, clamps not added: 67.6 ohm
|   slope of the pullup table from 0 to 0.18 V, typ, clamps not added: 74.3 ohm
|   GND clamp passes 1 mA (typ) near -0.25 V on its own axis
|   POWER clamp passes 1 mA (typ) near -0.24 V on its own axis
|   rising waveform, R_fixture 50.000, V_fixture 1.200: 20-80 % time 111ps typ, 111ps min, 118ps max; typ from 0.714 V to 1.2 V
|   rising waveform, R_fixture 50.000, V_fixture 0.0: 20-80 % time 153ps typ, 123ps min, 184ps max; typ from 0.002 V to 0.439 V
|   falling waveform, R_fixture 50.000, V_fixture 1.200: 20-80 % time 138ps typ, 103ps min, 164ps max; typ from 1.2 V to 0.714 V
|   falling waveform, R_fixture 50.000, V_fixture 0.0: 20-80 % time 123ps typ, 122ps min, 122ps max; typ from 0.439 V to 0.002 V
[Pulldown]
|Voltage   I(typ)   I(min)   I(max)
-1.2V     -4.165mA   -4.465mA   -3.283mA
-680mV    -4.566mA   -4.266mA   -4.792mA
-235mV    -3.252mA   -2.897mA   -3.612mA
396mV     5.714mA    5.525mA    6.179mA
693mV     9.477mA    9.443mA    9.848mA
1.027V    12.22mA    13.39mA    11.64mA
1.435V    13.18mA    16.51mA    12.24mA
1.769V    13.37mA    17.47mA    12.31mA
1.955V    13.46mA    17.28mA    12.38mA
2.103V    13.17mA    15.88mA    12.43mA
2.214V    11.94mA    14.34mA    12.2mA
2.4V      9.127mA    11.54mA    9.402mA
[Pullup]
|Voltage   I(typ)   I(min)   I(max)
-1.2V     2.935mA    3.569mA    2.058mA
-606mV    3.837mA    3.623mA    3.418mA
-421mV    3.68mA     3.313mA    3.712mA
-235mV    2.916mA    2.588mA    3.055mA
322mV     -4.246mA   -4.203mA   -4.234mA
544mV     -6.867mA   -6.977mA   -6.433mA
915mV     -9.693mA   -11.12mA   -7.945mA
1.361V    -10.69mA   -14.25mA   -8.373mA
1.955V    -10.86mA   -14.84mA   -8.435mA
2.103V    -10.63mA   -13.4mA    -8.457mA
2.214V    -9.421mA   -11.92mA   -8.318mA
2.4V      -6.356mA   -9.081mA   -5.529mA
[GND_clamp]
|Voltage   I(typ)   I(min)   I(max)
-1.2V     -423mA     -507.2mA   -407.3mA
-1.1V     -134.4mA   -193.5mA   -110.3mA
-1.075V   -97.83mA   -145.9mA   -80.47mA
-1.05V    -73.83mA   -110.2mA   -63.69mA
-1.025V   -58.88mA   -84.64mA   -54.46mA
-1V       -49.64mA   -66.89mA   -49.02mA
-975mV    -43.7mA    -54.73mA   -45.38mA
-925mV    -36.51mA   -40.43mA   -40.3mA
-775mV    -24.85mA   -23.75mA   -28.4mA
-425mV    -5.575mA   -5.99mA    -6.164mA
-175mV    -232.1uA   -495.6uA   -237uA
1.2V      0A         0A         0A
[POWER_clamp]
|Voltage   I(typ)   I(min)   I(max)
-1.2V     670.7mA    714.9mA    647.6mA
-1.1V     181mA      257.1mA    142.6mA
-1.075V   125.5mA    190mA      98.14mA
-1.05V    90.4mA     140.3mA    74.22mA
-1.025V   69.26mA    105.1mA    61.61mA
-1V       56.63mA    80.77mA    54.54mA
-975mV    48.83mA    64.32mA    50.06mA
-925mV    40.03mA    45.47mA    44.24mA
-775mV    27.54mA    25.98mA    31.88mA
-400mV    5.761mA    6.431mA    6.038mA
-125mV    43.13uA    212.5uA    14.41uA
1.2V      0A         0A         0A
[Ramp]
| variable   typ   min   max
dV/dt_r   0.324/0.157n   0.303/0.148n   0.345/0.197n
dV/dt_f   0.324/0.133n   0.302/0.117n   0.344/0.127n
R_load = 60.000
[Rising Waveform]
R_fixture= 50.000
V_fixture= 1.200
V_fixture_min= 1.140
V_fixture_max= 1.260
|time   V(typ)   V(min)   V(max)
0s        714.2mV    677.9mV    745.3mV
150ps     715.7mV    677.9mV    771.8mV
195ps     758.8mV    678.2mV    960mV
241ps     957.3mV    698.3mV    1.087V
276ps     1.044V     796.8mV    1.143V
308ps     1.091V     919.3mV    1.177V
336ps     1.119V     986.3mV    1.198V
456ps     1.176V     1.096V     1.242V
786ps     1.198V     1.136V     1.259V
3ns       1.2V       1.14V      1.26V
[Rising Waveform]
R_fixture= 50.000
V_fixture= 0.0
V_fixture_min= 0.0
V_fixture_max= 0.0
|time   V(typ)   V(min)   V(max)
0s        2.292mV    2.693mV    3.978mV
135ps     2.197mV    2.689mV    15.06mV
181ps     26.4mV     2.618mV    102.8mV
224ps     125.3mV    12.09mV    189.8mV
273ps     246.3mV    66.12mV    251.8mV
321ps     310.9mV    228.2mV    294.2mV
368ps     352.8mV    312.5mV    323.1mV
550ps     416.7mV    405.3mV    374.7mV
1ns       437.9mV    431.7mV    394mV
3ns       439.3mV    433.3mV    395.5mV
[Falling Waveform]
R_fixture= 50.000
V_fixture= 1.200
V_fixture_min= 1.140
V_fixture_max= 1.260
|time   V(typ)   V(min)   V(max)
0s        1.2V       1.14V      1.26V
112ps     1.2V       1.14V      1.253V
153ps     1.187V     1.14V      1.174V
180ps     1.144V     1.14V      1.059V
207ps     1.063V     1.135V     998.6mV
242ps     935.8mV    1.082V     939.2mV
261ps     902.1mV    1.046V     912.2mV
329ps     817.8mV    805.5mV    841.8mV
518ps     735.7mV    704mV      769.4mV
3ns       714.2mV    677.6mV    745.3mV
[Falling Waveform]
R_fixture= 50.000
V_fixture= 0.0
V_fixture_min= 0.0
V_fixture_max= 0.0
|time   V(typ)   V(min)   V(max)
0s        439mV      432.5mV    395.2mV
102ps     439mV      432.5mV    395.5mV
145ps     434.1mV    432.5mV    361.8mV
186ps     401.1mV    432.8mV    249mV
238ps     247.7mV    406.9mV    138.1mV
287ps     140mV      282.5mV    79.23mV
357ps     64.91mV    125.2mV    37.76mV
497ps     17.05mV    31.39mV    11.61mV
857ps     3.274mV    4.355mV    4.411mV
3ns       2.27mV     2.503mV    3.969mV
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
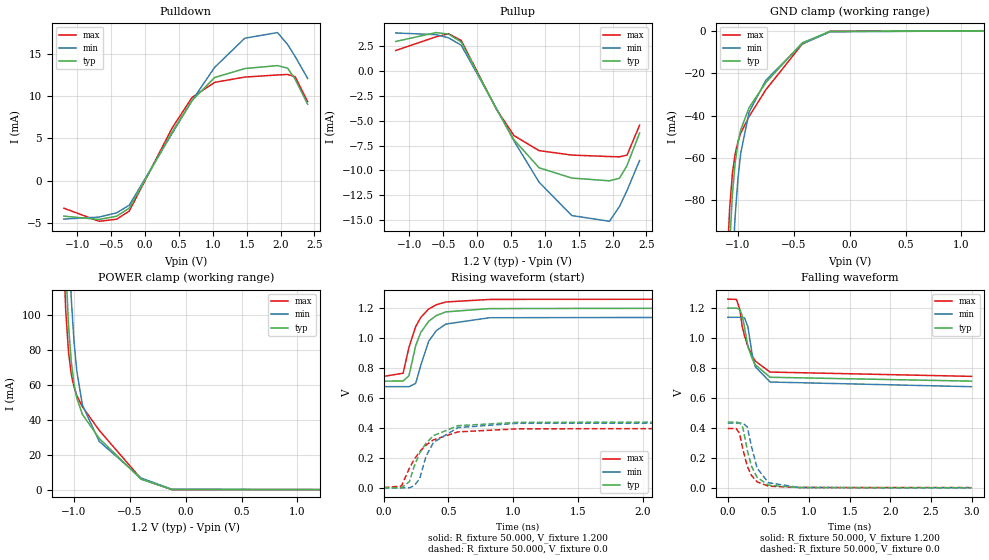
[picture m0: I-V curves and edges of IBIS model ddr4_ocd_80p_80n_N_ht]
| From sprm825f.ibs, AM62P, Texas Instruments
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|   Model ddr4_ocd_80p_80n_N_ht
[Model] ddr4_ocd_80p_80n_N_ht
Model_type I/O
Polarity   Non-Inverting
Enable   Active-High
Vinl =  0.700V
Vinh =  0.900V
Vmeas =  0.600V
C_comp   3.263pF   3.246pF   3.301pF
C_comp_pullup   0.322pF   0.321pF   0.331pF
C_comp_pulldown   1.281pF   1.272pF   1.291pF
[Model Spec]
Vinh   0.900V   0.820V   0.980V
Vinl   0.700V   0.620V   0.780V
Vmeas   0.600V   NA   NA
[Temperature Range]   25.000   0.125k   -40.000
[Voltage Range]   1.200V   1.140V   1.260V
[Pullup Reference]   1.200V   1.140V   1.260V
[Pulldown Reference]   0.0V   0.0V   0.0V
[C Comp Corner]
C_comp_pullup   0.322pF   0.331pF   0.321pF
C_comp_pulldown   1.272pF   1.291pF   1.281pF
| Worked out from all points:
|   slope of the pulldown table from 0 to 0.18 V, typ, clamps not added: 67.5 ohm
|   slope of the pullup table from 0 to 0.18 V, typ, clamps not added: 73.9 ohm
|   GND clamp passes 1 mA (typ) near -0.25 V on its own axis
|   POWER clamp passes 1 mA (typ) near -0.24 V on its own axis
|   rising waveform, R_fixture 50.000, V_fixture 1.200: 20-80 % time 125ps typ, 128ps min, 129ps max; typ from 0.714 V to 1.2 V
|   rising waveform, R_fixture 50.000, V_fixture 0.0: 20-80 % time 169ps typ, 144ps min, 201ps max; typ from 0.002 V to 0.441 V
|   falling waveform, R_fixture 50.000, V_fixture 1.200: 20-80 % time 154ps typ, 122ps min, 179ps max; typ from 1.2 V to 0.714 V
|   falling waveform, R_fixture 50.000, V_fixture 0.0: 20-80 % time 134ps typ, 135ps min, 132ps max; typ from 0.441 V to 0.002 V
[Pulldown]
|Voltage   I(typ)   I(min)   I(max)
-1.2V     -4.226mA   -4.577mA   -3.284mA
-680mV    -4.624mA   -4.337mA   -4.84mA
-421mV    -4.233mA   -3.838mA   -4.59mA
-235mV    -3.277mA   -2.929mA   -3.635mA
396mV     5.729mA    5.547mA    6.191mA
693mV     9.495mA    9.478mA    9.857mA
1.027V    12.22mA    13.43mA    11.64mA
1.472V    13.28mA    16.88mA    12.27mA
1.955V    13.63mA    17.55mA    12.52mA
2.103V    13.33mA    16.15mA    12.58mA
2.214V    12.04mA    14.73mA    12.32mA
2.4V      9.059mA    12.11mA    9.364mA
[Pullup]
|Voltage   I(typ)   I(min)   I(max)
-1.2V     3.001mA    3.857mA    2.093mA
-606mV    3.897mA    3.686mA    3.469mA
-421mV    3.739mA    3.368mA    3.78mA
-235mV    2.95mA     2.623mA    3.102mA
285mV     -3.8mA     -3.75mA    -3.825mA
544mV     -6.907mA   -7.017mA   -6.491mA
915mV     -9.733mA   -11.18mA   -8.005mA
1.398V    -10.77mA   -14.55mA   -8.453mA
1.955V    -11.05mA   -15.13mA   -8.603mA
2.103V    -10.79mA   -13.63mA   -8.63mA
2.214V    -9.505mA   -12.03mA   -8.46mA
2.4V      -6.233mA   -8.996mA   -5.434mA
[GND_clamp]
|Voltage   I(typ)   I(min)   I(max)
-1.2V     -425.9mA   -479.1mA   -398.3mA
-1.1V     -138.2mA   -191.6mA   -113.7mA
-1.075V   -101.6mA   -146.5mA   -84.28mA
-1.05V    -77.49mA   -112.3mA   -67.47mA
-1.025V   -62.34mA   -87.34mA   -58.02mA
-1V       -52.87mA   -69.78mA   -52.27mA
-975mV    -46.68mA   -57.59mA   -48.3mA
-900mV    -36.21mA   -38.39mA   -40.36mA
-750mV    -24.4mA    -23.28mA   -27.78mA
-425mV    -5.686mA   -6.132mA   -6.273mA
-175mV    -233uA     -499.4uA   -237.7uA
1.2V      0A         0A         0A
[POWER_clamp]
|Voltage   I(typ)   I(min)   I(max)
-1.2V     676.6mA    754.8mA    654.2mA
-1.1V     185.8mA    267.5mA    148mA
-1.075V   130.1mA    197.5mA    103.3mA
-1.05V    94.76mA    146mA      79.03mA
-1.025V   73.36mA    109.6mA    66.12mA
-1V       60.47mA    84.71mA    58.72mA
-975mV    52.41mA    67.84mA    53.9mA
-925mV    43.07mA    48.41mA    47.45mA
-775mV    29.35mA    27.65mA    33.98mA
-400mV    5.928mA    6.639mA    6.211mA
-125mV    43.26uA    213.4uA    14.44uA
1.2V      0A         0A         0A
[Ramp]
| variable   typ   min   max
dV/dt_r   0.326/0.191n   0.304/0.190n   0.348/0.240n
dV/dt_f   0.326/0.158n   0.303/0.149n   0.347/0.149n
R_load = 60.000
[Rising Waveform]
R_fixture= 50.000
V_fixture= 1.200
V_fixture_min= 1.140
V_fixture_max= 1.260
|time   V(typ)   V(min)   V(max)
0s        713.6mV    676.7mV    745.2mV
150ps     714.1mV    676.7mV    766.1mV
195ps     749.3mV    676.6mV    938.4mV
247ps     950mV      698.5mV    1.077V
287ps     1.039V     820.6mV    1.139V
347ps     1.112V     978.9mV    1.194V
407ps     1.151V     1.051V     1.223V
480ps     1.175V     1.094V     1.241V
817ps     1.197V     1.136V     1.258V
3ns       1.2V       1.139V     1.26V
[Rising Waveform]
R_fixture= 50.000
V_fixture= 0.0
V_fixture_min= 0.0
V_fixture_max= 0.0
|time   V(typ)   V(min)   V(max)
0s        2.336mV    2.774mV    4.011mV
137ps     2.183mV    2.735mV    13.79mV
199ps     44.31mV    2.807mV    134mV
235ps     144.7mV    16.24mV    191.9mV
278ps     235.1mV    63.47mV    243.7mV
327ps     300.1mV    213.4mV    287.1mV
384ps     350.3mV    305.1mV    322.3mV
574ps     416.7mV    404.2mV    375.3mV
1.034ns   438.7mV    432.5mV    395.6mV
3ns       440.8mV    434.5mV    398.1mV
[Falling Waveform]
R_fixture= 50.000
V_fixture= 1.200
V_fixture_min= 1.140
V_fixture_max= 1.260
|time   V(typ)   V(min)   V(max)
0s        1.2V       1.139V     1.26V
107ps     1.2V       1.139V     1.258V
149ps     1.191V     1.139V     1.188V
176ps     1.152V     1.139V     1.081V
206ps     1.071V     1.135V     1.015V
247ps     942.5mV    1.076V     946.6mV
305ps     857.3mV    875.3mV    876.1mV
338ps     822.8mV    809.7mV    847.3mV
520ps     739.4mV    707.6mV    774mV
3ns       713.5mV    676.4mV    745.2mV
[Falling Waveform]
R_fixture= 50.000
V_fixture= 0.0
V_fixture_min= 0.0
V_fixture_max= 0.0
|time   V(typ)   V(min)   V(max)
0s        440.6mV    433.8mV    397.8mV
102ps     440.6mV    433.9mV    397.9mV
144ps     435.7mV    433.9mV    366mV
185ps     405.2mV    434.2mV    260.1mV
240ps     252.5mV    407.7mV    146.1mV
291ps     147.3mV    278.9mV    85.32mV
360ps     72.93mV    134.5mV    42.61mV
500ps     20.12mV    36.6mV     13.54mV
880ps     3.871mV    4.66mV     5.048mV
3ns       2.309mV    2.563mV    4mV
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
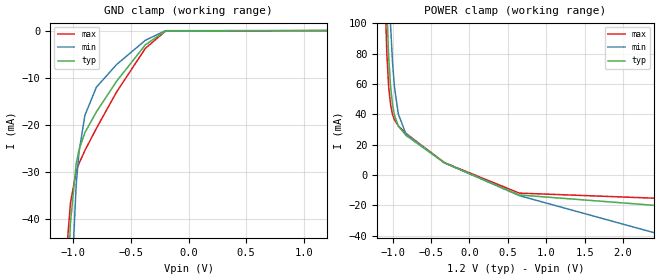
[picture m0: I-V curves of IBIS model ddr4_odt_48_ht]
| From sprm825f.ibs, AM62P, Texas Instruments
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|   Model ddr4_odt_48_ht
[Model] ddr4_odt_48_ht
Model_type Input
Polarity   Non-Inverting
Enable   Active-High
Vinl =  0.700V
Vinh =  0.900V
C_comp   2.297pF   2.244pF   2.453pF
[Model Spec]
Vinh   0.900V   0.820V   0.980V
Vinl   0.700V   0.620V   0.780V
[Temperature Range]   25.000   0.125k   -40.000
[Voltage Range]   1.200V   1.140V   1.260V
[C Comp Corner]
C_comp   2.297pF   2.244pF   2.453pF
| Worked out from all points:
|   GND clamp passes 1 mA (typ) near -0.28 V on its own axis
|   POWER clamp passes 1 mA (typ) near -0.04 V on its own axis
[GND_clamp]
|Voltage   I(typ)   I(min)   I(max)
-1.2V     -386.1mA   -431mA     -362.7mA
-1.075V   -76.68mA   -114.2mA   -59.37mA
-1.05V    -54.32mA   -82.06mA   -44.31mA
-1.025V   -40.8mA    -59mA      -36.55mA
-975mV    -28.18mA   -32.61mA   -29.91mA
-950mV    -25.22mA   -25.67mA   -28.15mA
-900mV    -21.66mA   -18mA      -25.45mA
-800mV    -17.25mA   -12.01mA   -20.75mA
-625mV    -10.76mA   -7.211mA   -13.04mA
-375mV    -3.027mA   -2.057mA   -3.769mA
-200mV    -82.61uA   -21.27uA   -108.6uA
1.2V      0A         0A         0A
[POWER_clamp]
|Voltage   I(typ)   I(min)   I(max)
-1.2V     599mA      738.3mA    626.4mA
-1.1V     162.3mA    254.1mA    124.8mA
-1.075V   110.9mA    184.9mA    81.19mA
-1.05V    78.04mA    134.1mA    58.11mA
-1.025V   58.25mA    98.56mA    46.37mA
-1V       46.6mA     74.4mA     40.15mA
-975mV    39.64mA    58.28mA    36.54mA
-925mV    32.37mA    40.36mA    32.46mA
-825mV    26.21mA    27.06mA    27.5mA
-325mV    8.127mA    8.101mA    8.266mA
650mV     -13.09mA   -13.52mA   -11.86mA
2.4V      -19.89mA   -37.9mA    -15.19mA
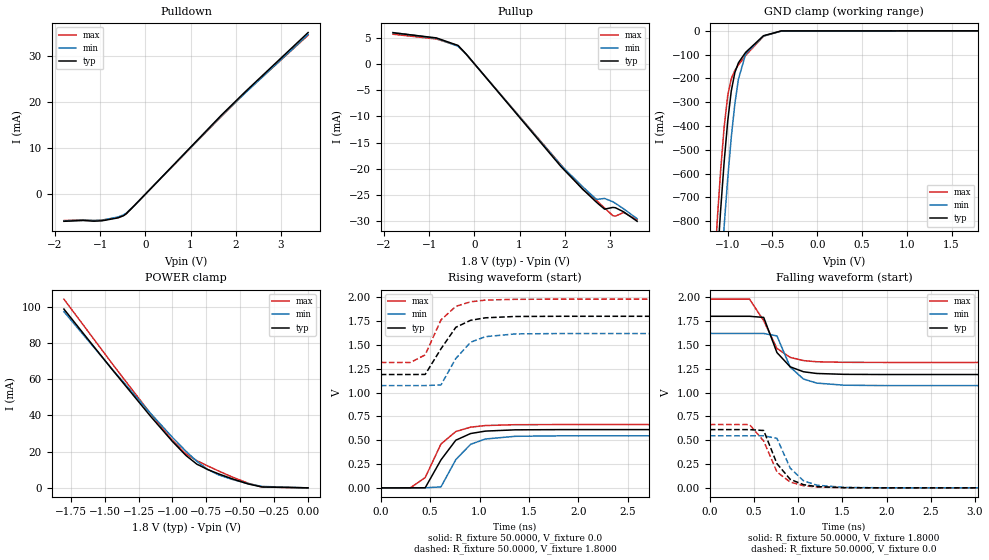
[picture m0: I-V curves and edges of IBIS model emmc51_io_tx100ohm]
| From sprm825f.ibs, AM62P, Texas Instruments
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|   Model emmc51_io_tx100ohm
[Model]  emmc51_io_tx100ohm
Model_type I/O
Polarity   Non-Inverting
Enable   Active-High
Vinl =   0.6300V
Vinh =   1.1700V
Vmeas =  0.2000V
Cref =   0.5000pF
Rref =   50.0000
Vref =   0.2000V
C_comp   2.0000pF   2.0000pF   2.0000pF
[Temperature Range]   25.0000   0.1250k   -40.0000
[Voltage Range]   1.8000V   1.6200V   1.9800V
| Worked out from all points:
|   slope of the pulldown table from 0 to 0.27 V, typ, clamps not added: 96.8 ohm
|   slope of the pullup table from 0 to 0.27 V, typ, clamps not added: 96.8 ohm
|   GND clamp passes 1 mA (typ) near -0.43 V on its own axis
|   POWER clamp passes 1 mA (typ) near -0.38 V on its own axis
|   rising waveform, R_fixture 50.0000, V_fixture 0.0: 20-80 % time 236ps typ, 229ps min, 230ps max; typ from 0 V to 0.611 V
|   rising waveform, R_fixture 50.0000, V_fixture 1.8000: 20-80 % time 234ps typ, 229ps min, 227ps max; typ from 1.19 V to 1.8 V
|   falling waveform, R_fixture 50.0000, V_fixture 1.8000: 20-80 % time 214ps typ, 213ps min, 240ps max; typ from 1.8 V to 1.19 V
|   falling waveform, R_fixture 50.0000, V_fixture 0.0: 20-80 % time 222ps typ, 221ps min, 235ps max; typ from 0.611 V to 0 V
[Pulldown]
|Voltage   I(typ)   I(min)   I(max)
-1.8V     -5.911mA   -5.822mA   -5.756mA
-1.38V    -5.736mA   -5.652mA   -5.572mA
-1.14V    -5.884mA   -5.73mA    -5.767mA
-960mV    -5.81mA    -5.677mA   -5.654mA
-600mV    -5.154mA   -4.964mA   -5.065mA
-480mV    -4.68mA    -4.486mA   -4.636mA
-420mV    -4.262mA   -4.118mA   -4.217mA
-240mV    -2.479mA   -2.455mA   -2.436mA
1.68V     17.2mA     17.03mA    16.92mA
2.22V     22.41mA    22.14mA    22.23mA
3.6V      35.21mA    34.81mA    34.63mA
[Pullup]
|Voltage   I(typ)   I(min)   I(max)
-1.8V     5.924mA    5.957mA    5.644mA
-840mV    4.938mA    4.865mA    4.733mA
-360mV    3.499mA    3.34mA     3.453mA
-180mV    1.859mA    1.833mA    1.826mA
1.92V     -19.6mA    -19.36mA   -19.28mA
2.4V      -23.88mA   -23.43mA   -23.92mA
2.7V      -26.34mA   -25.8mA    -25.97mA
2.88V     -27.66mA   -25.62mA   -27.45mA
3.06V     -27.33mA   -26.24mA   -28.87mA
3.12V     -27.39mA   -26.55mA   -28.99mA
3.3V      -28.16mA   -27.59mA   -28.29mA
3.6V      -29.97mA   -29.48mA   -29.69mA
[GND_clamp]
|Voltage   I(typ)   I(min)   I(max)
-1.8V     -6.702A    -6.906A    -6.586A
-1.12V    -991.1mA   -1.287A    -813.9mA
-1.08V    -758.6mA   -1.044A    -591.9mA
-1.04V    -552.1mA   -821.7mA   -405.1mA
-1V       -379.5mA   -621.1mA   -272.1mA
-960mV    -252.2mA   -446.8mA   -200.8mA
-920mV    -175.1mA   -305.6mA   -166.2mA
-880mV    -134mA     -202.7mA   -143.1mA
-800mV    -90.55mA   -97.27mA   -103.4mA
-600mV    -20.52mA   -21.87mA   -22.63mA
-400mV    -332.1uA   -1.109mA   -151.2uA
1.8V      231.4nA    26.73uA    254.2nA
[POWER_clamp]
|Voltage   I(typ)   I(min)   I(max)
-1.8V     98.61mA    97.2mA     104.1mA
-1.44V    64.88mA    65.13mA    68.09mA
-1.16V    39.38mA    40.99mA    40.81mA
-1V       25.58mA    27.85mA    26.18mA
-900mV    17.84mA    20.17mA    18.67mA
-820mV    13.08mA    14.63mA    15mA
-740mV    10.1mA     10.15mA    12.1mA
-660mV    7.73mA     7.169mA    9.318mA
-560mV    4.993mA    4.669mA    6.008mA
-440mV    2.128mA    2.259mA    2.491mA
-340mV    491.7uA    786.4uA    470uA
0V        231.4nA    1.21uA     740.9nA
[Ramp]
| variable   typ   min   max
dV/dt_r  0.3667/0.2298n   0.3277/0.2293n   0.3985/0.2208n
dV/dt_f  0.3667/0.2136n   0.3281/0.2127n   0.3986/0.2359n
R_load = 50.0000
[Rising Waveform]
R_fixture= 50.0000
V_fixture= 0.0
V_fixture_min= 0.0
V_fixture_max= 0.0
|time   V(typ)   V(min)   V(max)
0s        2.035uV    20.67uV    4.241uV
300ps     120.7uV    37.4uV     413.4uV
450ps     846.5uV    244.6uV    107.8mV
610ps     293.8mV    10.4mV     460.6mV
760ps     500mV      295.9mV    590.8mV
910ps     570mV      457.1mV    636.8mV
1.06ns    595.5mV    512.6mV    653.8mV
1.36ns    608.7mV    540.8mV    662.6mV
1.82ns    611mV      545.8mV    664.1mV
15ns      611.2mV    546.3mV    664.2mV
[Rising Waveform]
R_fixture= 50.0000
V_fixture= 1.8000
V_fixture_min= 1.6200
V_fixture_max= 1.9800
|time   V(typ)   V(min)   V(max)
0s        1.189V     1.073V     1.316V
300ps     1.189V     1.073V     1.316V
450ps     1.19V      1.073V     1.395V
610ps     1.459V     1.08V      1.762V
760ps     1.684V     1.357V     1.904V
910ps     1.758V     1.528V     1.952V
1.06ns    1.784V     1.586V     1.97V
1.36ns    1.798V     1.615V     1.978V
1.82ns    1.8V       1.619V     1.98V
15ns      1.8V       1.62V      1.98V
[Falling Waveform]
R_fixture= 50.0000
V_fixture= 1.8000
V_fixture_min= 1.6200
V_fixture_max= 1.9800
|time   V(typ)   V(min)   V(max)
0s        1.8V       1.62V      1.98V
450ps     1.8V       1.62V      1.98V
610ps     1.788V     1.62V      1.753V
760ps     1.419V     1.594V     1.463V
910ps     1.27V      1.267V     1.369V
1.06ns    1.218V     1.142V     1.335V
1.21ns    1.2V       1.099V     1.323V
1.52ns    1.191V     1.077V     1.317V
1.97ns    1.189V     1.073V     1.316V
15ns      1.189V     1.073V     1.316V
[Falling Waveform]
R_fixture= 50.0000
V_fixture= 0.0
V_fixture_min= 0.0
V_fixture_max= 0.0
|time   V(typ)   V(min)   V(max)
0s        611.2mV    546.3mV    664.2mV
450ps     611mV      546.2mV    663.8mV
610ps     601.7mV    546mV      491.4mV
760ps     253.6mV    519.2mV    166.5mV
910ps     89.55mV    207mV      60.68mV
1.06ns    33.55mV    74.14mV    22.88mV
1.21ns    13.02mV    28.31mV    8.938mV
1.52ns    2.1mV      4.733mV    1.402mV
1.97ns    168.6uV    416.5uV    101.3uV
15ns      2.026uV    20.6uV     4.188uV
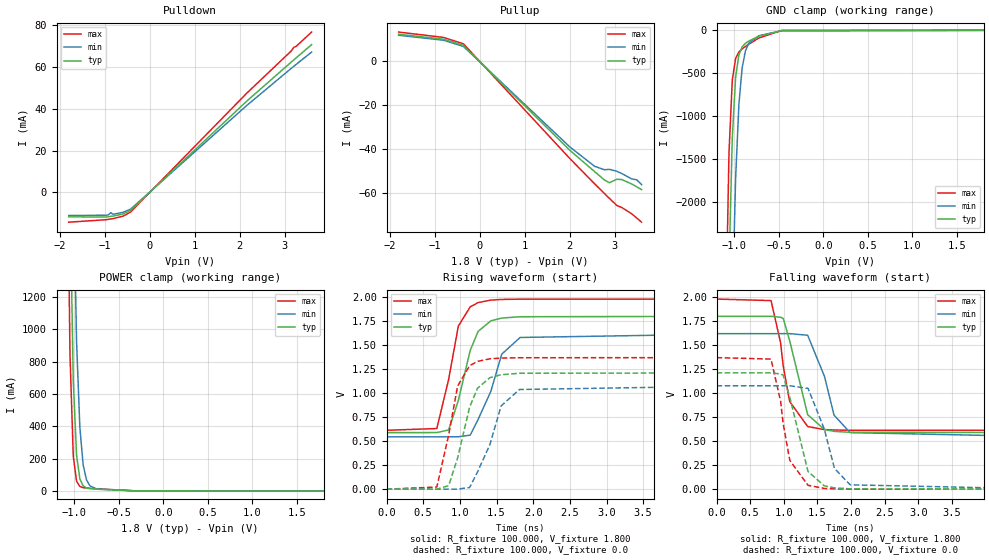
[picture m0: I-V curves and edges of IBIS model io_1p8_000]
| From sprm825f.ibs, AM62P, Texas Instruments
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|   Model io_1p8_000
[Model]   io_1p8_000
Model_type   I/O
Polarity   Non-Inverting
Enable   Active-High
Vinl =  0.630V
Vinh =  1.170V
Vmeas = 0.900V
Cref =  6.000pF
|   typ   min   max
C_comp   3.520pF   3.519pF   3.571pF
[Model Spec]
Vinh   1.170V   1.053V   1.287V
Vinl   0.630V   0.567V   0.693V
[Voltage Range]   1.8   1.62   1.98
[Temperature Range]   30   125   -40
[Pullup Reference]   1.8   1.62   1.98
[Pulldown Reference]   0   0   0
[Power Clamp Reference]   1.8   1.62   1.98
[GND Clamp Reference]   0   0   0
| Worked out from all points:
|   slope of the pulldown table from 0 to 0.27 V, typ, clamps not added: 48.6 ohm
|   slope of the pullup table from 0 to 0.27 V, typ, clamps not added: 48.6 ohm
|   GND clamp passes 1 mA (typ) near -0.43 V on its own axis
|   POWER clamp passes 1 mA (typ) near -0.38 V on its own axis
|   rising waveform, R_fixture 100.000, V_fixture 1.800: 20-80 % time 246ps typ, 306ps min, 209ps max; typ from 0.589 V to 1.8 V
|   rising waveform, R_fixture 100.000, V_fixture 0.0: 20-80 % time 245ps typ, 304ps min, 210ps max; typ from 0 V to 1.21 V
|   falling waveform, R_fixture 100.000, V_fixture 1.800: 20-80 % time 238ps typ, 290ps min, 207ps max; typ from 1.8 V to 0.589 V
|   falling waveform, R_fixture 100.000, V_fixture 0.0: 20-80 % time 238ps typ, 290ps min, 207ps max; typ from 1.21 V to 0 V
[Pulldown]
|Voltage   I(typ)   I(min)   I(max)
-1.8V     -11.68mA   -11.04mA   -14.23mA
-975mV    -11.76mA   -10.9mA    -13.05mA
-920mV    -11.62mA   -10.77mA   -12.87mA
-865mV    -11.45mA   -9.719mA   -12.68mA
-810mV    -11.27mA   -10.44mA   -12.48mA
-590mV    -10.29mA   -9.489mA   -11.35mA
-425mV    -8.59mA    -8.008mA   -9.39mA
2.16V     43.71mA    41.63mA    47.5mA
3.15V     62.4mA     59.39mA    67.72mA
3.205V    63.42mA    60.35mA    69.44mA
3.26V     64.44mA    61.31mA    69.94mA
3.6V      70.7mA     67.15mA    76.7mA
[Pullup]
|Voltage   I(typ)   I(min)   I(max)
-1.8V     12.04mA    11.61mA    13.05mA
-800mV    9.816mA    9.331mA    10.62mA
-360mV    6.993mA    6.502mA    7.706mA
2.005V    -40.74mA   -39.21mA   -44.5mA
2.555V    -50.43mA   -48.03mA   -55.98mA
2.775V    -54.27mA   -49.59mA   -60.42mA
2.885V    -55.49mA   -49.41mA   -62.65mA
3.05V     -53.92mA   -50.29mA   -65.86mA
3.16V     -54.06mA   -51.32mA   -66.78mA
3.38V     -56.07mA   -53.77mA   -69.65mA
3.49V     -57.33mA   -54.15mA   -71.53mA
3.6V      -58.65mA   -56.38mA   -73.46mA
[GND_clamp]
|Voltage   I(typ)   I(min)   I(max)
-1.8V     -76.47A    -76.69A    -88.72A
-1.097V   -5.201A    -8.268A    -3.42A
-1.06V    -2.769A    -5.461A    -1.424A
-1.023V   -1.254A    -3.251A    -579mA
-986mV    -548.8mA   -1.735A    -328.6mA
-949mV    -286.3mA   -863.3mA   -252.5mA
-912mV    -191.8mA   -432.8mA   -215.7mA
-875mV    -150.6mA   -237.8mA   -187.7mA
-838mV    -125.4mA   -149.7mA   -161.9mA
-727mV    -70.03mA   -63.5mA    -90.71mA
-468mV    -2.466mA   -4.456mA   -1.95mA
1.8V      0A         0A         0A
[POWER_clamp]
|Voltage   I(typ)   I(min)   I(max)
-1.8V     48.65A     48.99A     48.49A
-1.086V   3.937A     6.144A     2.539A
-1.049V   1.843A     3.749A     845.6mA
-1.012V   681.6mA    1.988A     214.1mA
-975mV    220.2mA    922.3mA    60.04mA
-938mV    73.81mA    391.5mA    27.7mA
-901mV    31.1mA     161.6mA    20.27mA
-864mV    18.42mA    69.07mA    17.69mA
-827mV    14.1mA     32.73mA    16.04mA
-753mV    10.72mA    12.25mA    13.19mA
-309mV    231.8uA    484uA      182.7uA
1.8V      0A         0A         0A
[Ramp]
| variable   typ   min   max
dV/dt_r   0.726/0.246n   0.646/0.304n   0.822/0.210n
dV/dt_f   0.727/0.238n   0.645/0.290n   0.820/0.207n
R_load = 100.000
[Rising Waveform]
R_fixture= 100.000
V_fixture= 1.800
V_fixture_min= 1.620
V_fixture_max= 1.980
|time   V(typ)   V(min)   V(max)
0s        588.9mV    545.2mV    613.2mV
686ps     589.4mV    545.2mV    631.4mV
847ps     616.4mV    545.4mV    1.143V
979ps     923.3mV    545.8mV    1.698V
1.141ns   1.445V     562.7mV    1.899V
1.249ns   1.643V     726.5mV    1.943V
1.422ns   1.753V     1.018V     1.969V
1.571ns   1.782V     1.406V     1.976V
1.822ns   1.796V     1.58V      1.979V
5ns       1.8V       1.62V      1.98V
[Rising Waveform]
R_fixture= 100.000
V_fixture= 0.0
V_fixture_min= 0.0
V_fixture_max= 0.0
|time   V(typ)   V(min)   V(max)
0s        2.024uV    21.01uV    3.965uV
686ps     467.7uV    77.56uV    22.14mV
848ps     36.98mV    235.2uV    566.8mV
969ps     323.7mV    581.5uV    1.073V
1.133ns   854.6mV    17.5mV     1.286V
1.241ns   1.052V     179mV      1.331V
1.411ns   1.162V     467.9mV    1.358V
1.562ns   1.192V     866.5mV    1.365V
1.812ns   1.207V     1.038V     1.369V
5ns       1.211V     1.077V     1.37V
[Falling Waveform]
R_fixture= 100.000
V_fixture= 1.800
V_fixture_min= 1.620
V_fixture_max= 1.980
|time   V(typ)   V(min)   V(max)
0s        1.8V       1.62V      1.98V
810ps     1.8V       1.62V      1.964V
952ps     1.791V     1.62V      1.524V
991ps     1.778V     1.62V      1.282V
1.086ns   1.548V     1.62V      914.1mV
1.354ns   776.3mV    1.603V     652.6mV
1.603ns   621.6mV    1.176V     620.3mV
1.746ns   602mV      770.8mV    616mV
1.984ns   592.1mV    589.2mV    613.8mV
5ns       588.9mV    545.2mV    613.2mV
[Falling Waveform]
R_fixture= 100.000
V_fixture= 0.0
V_fixture_min= 0.0
V_fixture_max= 0.0
|time   V(typ)   V(min)   V(max)
0s        1.211V     1.077V     1.37V
809ps     1.211V     1.077V     1.355V
953ps     1.2V       1.077V     912.1mV
990ps     1.188V     1.077V     682.6mV
1.089ns   955.2mV    1.077V     299.1mV
1.359ns   184.6mV    1.05V      40.12mV
1.6ns     35.02mV    627.6mV    7.942mV
1.752ns   13.53mV    216.1mV    3.049mV
1.985ns   3.545mV    45.23mV    753.1uV
5ns       2.203uV    21.24uV    4.068uV
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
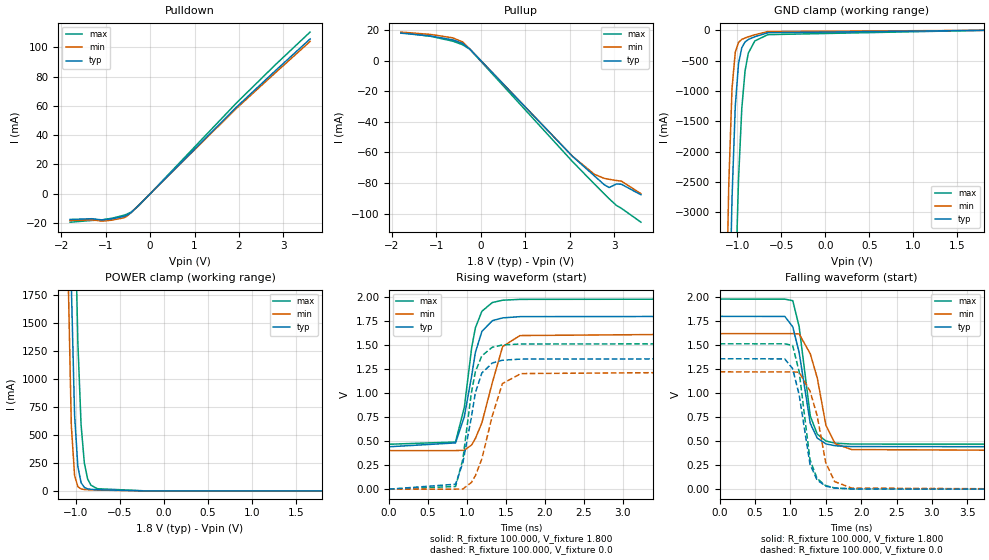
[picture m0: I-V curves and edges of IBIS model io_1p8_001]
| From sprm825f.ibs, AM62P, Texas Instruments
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|   Model io_1p8_001
[Model]   io_1p8_001
Model_type   I/O
Polarity   Non-Inverting
Enable   Active-High
Vinl =  0.630V
Vinh =  1.170V
Vmeas = 0.900V
Cref =  6.000pF
|   typ   min   max
C_comp   3.352pF   3.296pF   3.453pF
[Model Spec]
Vinh   1.170V   1.053V   1.287V
Vinl   0.630V   0.567V   0.693V
[Voltage Range]   1.8   1.62   1.98
[Temperature Range]   30   125   -40
[Pullup Reference]   1.8   1.62   1.98
[Pulldown Reference]   0   0   0
[Power Clamp Reference]   1.8   1.62   1.98
[GND Clamp Reference]   0   0   0
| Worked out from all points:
|   slope of the pulldown table from 0 to 0.27 V, typ, clamps not added: 32.5 ohm
|   slope of the pullup table from 0 to 0.27 V, typ, clamps not added: 32.5 ohm
|   GND clamp passes 1 mA (typ) near -0.43 V on its own axis
|   POWER clamp passes 1 mA (typ) near -0.38 V on its own axis
|   rising waveform, R_fixture 100.000, V_fixture 1.800: 20-80 % time 185ps typ, 230ps min, 159ps max; typ from 0.442 V to 1.8 V
|   rising waveform, R_fixture 100.000, V_fixture 0.0: 20-80 % time 186ps typ, 230ps min, 160ps max; typ from 0 V to 1.36 V
|   falling waveform, R_fixture 100.000, V_fixture 1.800: 20-80 % time 175ps typ, 214ps min, 152ps max; typ from 1.8 V to 0.442 V
|   falling waveform, R_fixture 100.000, V_fixture 0.0: 20-80 % time 176ps typ, 215ps min, 153ps max; typ from 1.36 V to 0 V
[Pulldown]
|Voltage   I(typ)   I(min)   I(max)
-1.8V     -17.52mA   -18.26mA   -19.41mA
-1.305V   -17.04mA   -17.8mA    -18.22mA
-1.085V   -17.85mA   -18.69mA   -17.82mA
-865mV    -17.17mA   -18.05mA   -16.78mA
-590mV    -15.43mA   -16.43mA   -14.68mA
-535mV    -14.84mA   -15.67mA   -14.09mA
-425mV    -12.85mA   -12.88mA   -12.48mA
-260mV    -8.005mA   -7.888mA   -8.353mA
1.94V     59.04mA    58.22mA    61.89mA
2.82V     84.04mA    82.65mA    88.11mA
3.6V      105.7mA    104mA      110.4mA
[Pullup]
|Voltage   I(typ)   I(min)   I(max)
-1.8V     18.04mA    18.73mA    18.45mA
-1.13V    16.16mA    17.2mA     15.95mA
-635mV    13.66mA    14.97mA    12.84mA
-415mV    11.4mA     12.37mA    10.5mA
-250mV    7.659mA    7.67mA     7.565mA
2.06V     -62.53mA   -62.45mA   -65.93mA
2.555V    -75.36mA   -74.29mA   -80.66mA
2.775V    -81.1mA    -76.95mA   -87.08mA
2.885V    -82.94mA   -77.55mA   -90.27mA
3.05V     -80.6mA    -78.36mA   -94.65mA
3.16V     -80.78mA   -78.74mA   -96.5mA
3.6V      -87.64mA   -86.95mA   -105.6mA
[GND_clamp]
|Voltage   I(typ)   I(min)   I(max)
-1.8V     -76.47A    -73.89A    -95.14A
-1.134V   -8.338A    -5.269A    -13.51A
-1.097V   -5.201A    -2.551A    -9.957A
-1.06V    -2.769A    -957.9mA   -6.857A
-1.023V   -1.254A    -361.3mA   -4.314A
-986mV    -548.8mA   -198.7mA   -2.455A
-949mV    -286.3mA   -149.8mA   -1.289A
-912mV    -191.8mA   -125.6mA   -669.7mA
-875mV    -150.6mA   -106.8mA   -376.6mA
-801mV    -105.3mA   -73.35mA   -175.4mA
-653mV    -39.86mA   -20.09mA   -71.17mA
1.8V      0A         0A         0A
[POWER_clamp]
|Voltage   I(typ)   I(min)   I(max)
-1.8V     48.65A     48.13A     49.56A
-1.086V   3.937A     1.965A     7.361A
-1.049V   1.843A     586.5mA    4.756A
-1.012V   681.6mA    139.2mA    2.697A
-975mV    220.2mA    38.2mA     1.331A
-938mV    73.81mA    17.48mA    589.9mA
-901mV    31.1mA     12.68mA    249.5mA
-864mV    18.42mA    10.94mA    108.1mA
-827mV    14.1mA     9.785mA    51.65mA
-753mV    10.72mA    7.761mA    19.73mA
-198mV    6.084uA    324.1nA    314.4uA
1.8V      0A         0A         0A
[Ramp]
| variable   typ   min   max
dV/dt_r   0.815/0.187n   0.733/0.230n   0.908/0.159n
dV/dt_f   0.815/0.175n   0.731/0.215n   0.907/0.152n
R_load = 100.000
[Rising Waveform]
R_fixture= 100.000
V_fixture= 1.800
V_fixture_min= 1.620
V_fixture_max= 1.980
|time   V(typ)   V(min)   V(max)
0s        441.5mV    401.8mV    467.8mV
855ps     481.8mV    402.2mV    491.2mV
968ps     756.2mV    404.7mV    853.3mV
1.062ns   1.181V     461.3mV    1.475V
1.11ns    1.426V     528.1mV    1.682V
1.193ns   1.643V     691.6mV    1.853V
1.327ns   1.755V     1.11V      1.944V
1.459ns   1.784V     1.486V     1.968V
1.682ns   1.797V     1.6V       1.977V
5ns       1.8V       1.62V      1.98V
[Rising Waveform]
R_fixture= 100.000
V_fixture= 0.0
V_fixture_min= 0.0
V_fixture_max= 0.0
|time   V(typ)   V(min)   V(max)
0s        1.517uV    506.9nV    94.35uV
856ps     51.59mV    370.1uV    28.19mV
949ps     275.9mV    1.905mV    312.4mV
1.057ns   742.8mV    68.24mV    998.2mV
1.109ns   1.004V     139.6mV    1.222V
1.192ns   1.209V     314.1mV    1.389V
1.326ns   1.314V     762.4mV    1.478V
1.456ns   1.343V     1.1V       1.502V
1.693ns   1.355V     1.204V     1.512V
5ns       1.358V     1.222V     1.514V
[Falling Waveform]
R_fixture= 100.000
V_fixture= 1.800
V_fixture_min= 1.620
V_fixture_max= 1.980
|time   V(typ)   V(min)   V(max)
0s        1.8V       1.62V      1.98V
921ps     1.799V     1.62V      1.979V
1.033ns   1.69V      1.62V      1.963V
1.123ns   1.423V     1.617V     1.692V
1.28ns    685.6mV    1.41V      762.3mV
1.379ns   531.5mV    1.159V     573mV
1.501ns   471.4mV    666.4mV    501.5mV
1.633ns   451.9mV    472.3mV    479mV
1.866ns   443.7mV    412.6mV    469.9mV
5ns       441.5mV    401.8mV    467.8mV
[Falling Waveform]
R_fixture= 100.000
V_fixture= 0.0
V_fixture_min= 0.0
V_fixture_max= 0.0
|time   V(typ)   V(min)   V(max)
0s        1.358V     1.222V     1.514V
918ps     1.357V     1.221V     1.514V
1.031ns   1.256V     1.221V     1.497V
1.123ns   983.9mV    1.218V     1.223V
1.276ns   259.5mV    1.023V     307.5mV
1.377ns   94.75mV    766.7mV    110.2mV
1.498ns   32.1mV     278.5mV    36.12mV
1.625ns   11.8mV     78.65mV    12.81mV
1.866ns   2.443mV    11.29mV    2.426mV
5ns       1.614uV    517.3nV    94.39uV
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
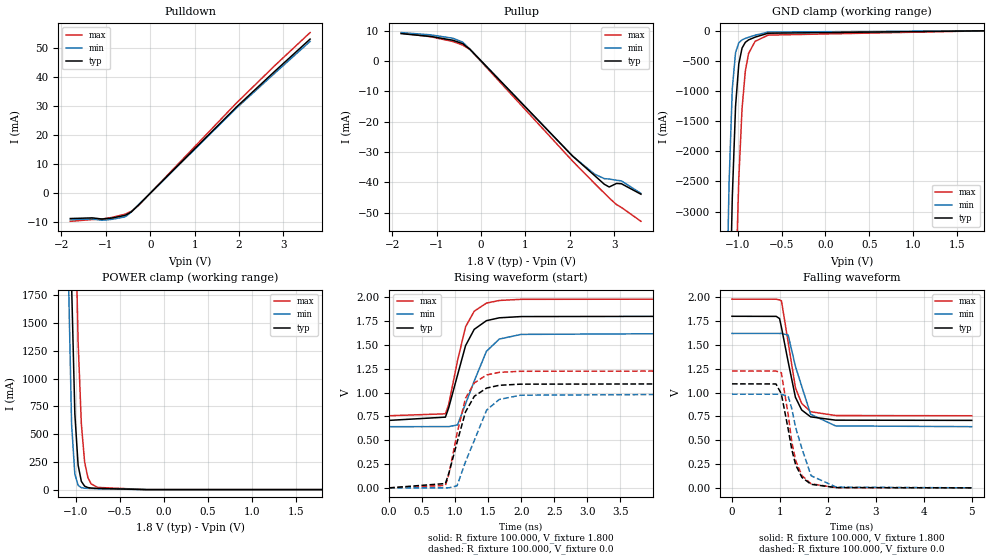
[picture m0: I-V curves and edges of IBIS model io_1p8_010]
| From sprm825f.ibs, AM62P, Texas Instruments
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|   Model io_1p8_010
[Model]   io_1p8_010
Model_type   I/O
Polarity   Non-Inverting
Enable   Active-High
Vinl =  0.630V
Vinh =  1.170V
Vmeas = 0.900V
Cref =  6.000pF
|   typ   min   max
C_comp   3.603pF   3.572pF   3.672pF
[Model Spec]
Vinh   1.170V   1.053V   1.287V
Vinl   0.630V   0.567V   0.693V
[Voltage Range]   1.8   1.62   1.98
[Temperature Range]   30   125   -40
[Pullup Reference]   1.8   1.62   1.98
[Pulldown Reference]   0   0   0
[Power Clamp Reference]   1.8   1.62   1.98
[GND Clamp Reference]   0   0   0
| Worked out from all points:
|   slope of the pulldown table from 0 to 0.27 V, typ, clamps not added: 64.7 ohm
|   slope of the pullup table from 0 to 0.27 V, typ, clamps not added: 64.9 ohm
|   GND clamp passes 1 mA (typ) near -0.43 V on its own axis
|   POWER clamp passes 1 mA (typ) near -0.38 V on its own axis
|   rising waveform, R_fixture 100.000, V_fixture 1.800: 20-80 % time 277ps typ, 326ps min, 247ps max; typ from 0.708 V to 1.8 V
|   rising waveform, R_fixture 100.000, V_fixture 0.0: 20-80 % time 278ps typ, 322ps min, 249ps max; typ from 0 V to 1.09 V
|   falling waveform, R_fixture 100.000, V_fixture 1.800: 20-80 % time 267ps typ, 308ps min, 244ps max; typ from 1.8 V to 0.708 V
|   falling waveform, R_fixture 100.000, V_fixture 0.0: 20-80 % time 269ps typ, 311ps min, 245ps max; typ from 1.09 V to 0 V
[Pulldown]
|Voltage   I(typ)   I(min)   I(max)
-1.8V     -8.748mA   -9.114mA   -9.694mA
-1.305V   -8.512mA   -8.888mA   -9.098mA
-1.085V   -8.915mA   -9.333mA   -8.897mA
-865mV    -8.581mA   -9.015mA   -8.378mA
-590mV    -7.717mA   -8.228mA   -7.338mA
-535mV    -7.426mA   -7.858mA   -7.04mA
-425mV    -6.445mA   -6.475mA   -6.245mA
-260mV    -4.017mA   -3.966mA   -4.184mA
1.94V     29.63mA    29.27mA    31.01mA
2.82V     42.17mA    41.52mA    44.13mA
3.6V      53.04mA    52.25mA    55.29mA
[Pullup]
|Voltage   I(typ)   I(min)   I(max)
-1.8V     9.008mA    9.361mA    9.206mA
-1.13V    8.074mA    8.598mA    7.964mA
-635mV    6.829mA    7.492mA    6.413mA
-415mV    5.707mA    6.207mA    5.247mA
-250mV    3.841mA    3.857mA    3.786mA
2.06V     -31.36mA   -31.39mA   -33.02mA
2.555V    -37.79mA   -37.33mA   -40.39mA
2.775V    -40.67mA   -38.83mA   -43.6mA
2.885V    -41.58mA   -38.95mA   -45.2mA
3.05V     -40.41mA   -39.37mA   -47.39mA
3.16V     -40.51mA   -39.56mA   -48.32mA
3.6V      -43.96mA   -43.69mA   -52.9mA
[GND_clamp]
|Voltage   I(typ)   I(min)   I(max)
-1.8V     -76.47A    -73.89A    -85.22A
-1.134V   -8.338A    -5.269A    -13.51A
-1.097V   -5.201A    -2.551A    -9.957A
-1.06V    -2.769A    -957.9mA   -6.857A
-1.023V   -1.254A    -361.3mA   -4.314A
-986mV    -548.8mA   -198.7mA   -2.455A
-949mV    -286.3mA   -149.8mA   -1.289A
-912mV    -191.8mA   -125.6mA   -669.7mA
-875mV    -150.6mA   -106.8mA   -376.6mA
-801mV    -105.3mA   -73.35mA   -175.4mA
-653mV    -39.86mA   -20.09mA   -71.17mA
1.8V      0A         0A         0A
[POWER_clamp]
|Voltage   I(typ)   I(min)   I(max)
-1.8V     48.65A     48.13A     49.56A
-1.086V   3.937A     1.965A     7.361A
-1.049V   1.843A     586.5mA    4.756A
-1.012V   681.6mA    139.2mA    2.697A
-975mV    220.2mA    38.2mA     1.331A
-938mV    73.81mA    17.48mA    589.9mA
-901mV    31.1mA     12.68mA    249.5mA
-864mV    18.42mA    10.94mA    108.1mA
-827mV    14.1mA     9.785mA    51.65mA
-753mV    10.72mA    7.761mA    19.73mA
-198mV    6.084uA    324.1nA    314.4uA
1.8V      0A         0A         0A
[Ramp]
| variable   typ   min   max
dV/dt_r   0.655/0.278n   0.589/0.322n   0.735/0.249n
dV/dt_f   0.655/0.268n   0.587/0.309n   0.734/0.245n
R_load = 100.000
[Rising Waveform]
R_fixture= 100.000
V_fixture= 1.800
V_fixture_min= 1.620
V_fixture_max= 1.980
|time   V(typ)   V(min)   V(max)
0s        707.9mV    642.1mV    756.5mV
852ps     741.9mV    642.4mV    776.9mV
901ps     838.6mV    642.6mV    872.8mV
1.035ns   1.182V     660.2mV    1.333V
1.157ns   1.492V     881.5mV    1.69V
1.288ns   1.663V     1.12V      1.853V
1.473ns   1.754V     1.433V     1.938V
1.668ns   1.784V     1.561V     1.966V
1.997ns   1.797V     1.61V      1.978V
5ns       1.8V       1.62V      1.98V
[Rising Waveform]
R_fixture= 100.000
V_fixture= 0.0
V_fixture_min= 0.0
V_fixture_max= 0.0
|time   V(typ)   V(min)   V(max)
0s        2.434uV    811.7nV    152.6uV
852ps     45.34mV    282uV      25.31mV
906ps     158.6mV    479.7uV    145.3mV
1.028ns   476.9mV    21.88mV    569.9mV
1.156ns   796.6mV    274.2mV    940.2mV
1.29ns    961.4mV    498.2mV    1.101V
1.476ns   1.047V     816mV      1.185V
1.667ns   1.076V     927.3mV    1.212V
1.991ns   1.088V     972.1mV    1.223V
5ns       1.091V     982.3mV    1.226V
[Falling Waveform]
R_fixture= 100.000
V_fixture= 1.800
V_fixture_min= 1.620
V_fixture_max= 1.980
|time   V(typ)   V(min)   V(max)
0s        1.8V       1.62V      1.98V
923ps     1.799V     1.62V      1.979V
992ps     1.776V     1.62V      1.972V
1.032ns   1.683V     1.62V      1.962V
1.171ns   1.324V     1.603V     1.528V
1.323ns   950.2mV    1.276V     1.051V
1.453ns   817.1mV    1.067V     886.5mV
1.64ns    745mV      772.2mV    798.8mV
2.16ns    710.3mV    650mV      758.9mV
5ns       707.9mV    642.1mV    756.5mV
[Falling Waveform]
R_fixture= 100.000
V_fixture= 0.0
V_fixture_min= 0.0
V_fixture_max= 0.0
|time   V(typ)   V(min)   V(max)
0s        1.091V     982.3mV    1.226V
918ps     1.09V      982.2mV    1.225V
1.029ns   986.7mV    982mV      1.208V
1.172ns   616.3mV    961.6mV    769.3mV
1.247ns   402.3mV    830.3mV    483.5mV
1.329ns   239.6mV    629.9mV    285.2mV
1.46ns    108.8mV    409.8mV    127.6mV
1.649ns   37.26mV    127.2mV    42.61mV
2.175ns   2.464mV    7.887mV    2.602mV
5ns       2.499uV    1.056uV    152.7uV
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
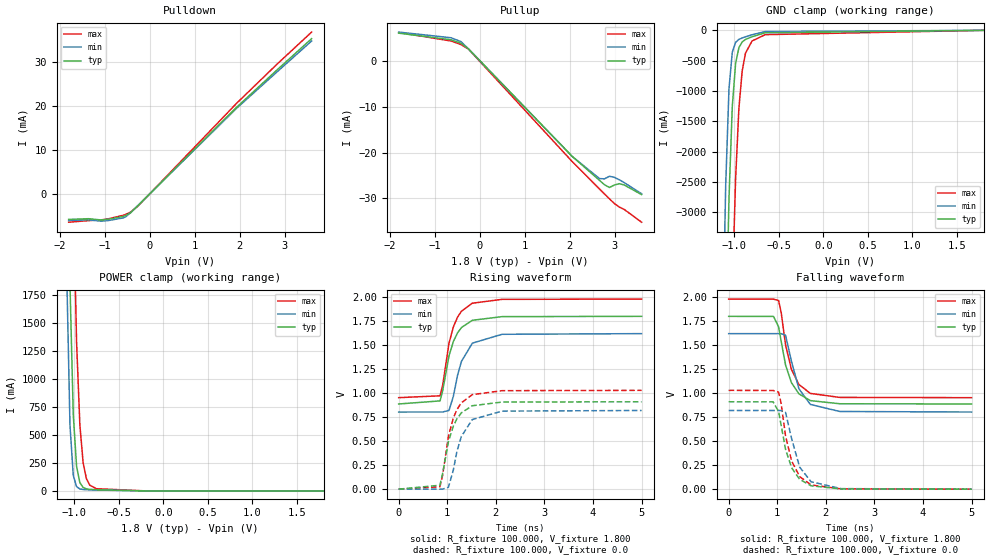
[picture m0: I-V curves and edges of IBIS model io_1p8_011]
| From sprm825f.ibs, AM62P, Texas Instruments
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|   Model io_1p8_011
[Model]   io_1p8_011
Model_type   I/O
Polarity   Non-Inverting
Enable   Active-High
Vinl =  0.630V
Vinh =  1.170V
Vmeas = 0.900V
Cref =  6.000pF
|   typ   min   max
C_comp   3.686pF   3.664pF   3.744pF
[Model Spec]
Vinh   1.170V   1.053V   1.287V
Vinl   0.630V   0.567V   0.693V
[Voltage Range]   1.8   1.62   1.98
[Temperature Range]   30   125   -40
[Pullup Reference]   1.8   1.62   1.98
[Pulldown Reference]   0   0   0
[Power Clamp Reference]   1.8   1.62   1.98
[GND Clamp Reference]   0   0   0
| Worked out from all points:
|   slope of the pulldown table from 0 to 0.27 V, typ, clamps not added: 97 ohm
|   slope of the pullup table from 0 to 0.27 V, typ, clamps not added: 97.5 ohm
|   GND clamp passes 1 mA (typ) near -0.43 V on its own axis
|   POWER clamp passes 1 mA (typ) near -0.38 V on its own axis
|   rising waveform, R_fixture 100.000, V_fixture 1.800: 20-80 % time 276ps typ, 286ps min, 268ps max; typ from 0.887 V to 1.8 V
|   rising waveform, R_fixture 100.000, V_fixture 0.0: 20-80 % time 280ps typ, 287ps min, 274ps max; typ from 0 V to 0.91 V
|   falling waveform, R_fixture 100.000, V_fixture 1.800: 20-80 % time 272ps typ, 277ps min, 268ps max; typ from 1.8 V to 0.887 V
|   falling waveform, R_fixture 100.000, V_fixture 0.0: 20-80 % time 276ps typ, 283ps min, 271ps max; typ from 0.91 V to 0 V
[Pulldown]
|Voltage   I(typ)   I(min)   I(max)
-1.8V     -5.828mA   -6.074mA   -6.459mA
-1.36V    -5.662mA   -5.916mA   -6.103mA
-1.085V   -5.944mA   -6.225mA   -5.933mA
-920mV    -5.804mA   -6.084mA   -5.691mA
-590mV    -5.147mA   -5.49mA    -4.894mA
-535mV    -4.954mA   -5.246mA   -4.695mA
-425mV    -4.301mA   -4.325mA   -4.165mA
-260mV    -2.682mA   -2.649mA   -2.792mA
1.94V     19.78mA    19.55mA    20.69mA
2.82V     28.11mA    27.67mA    29.42mA
3.6V      35.34mA    34.81mA    36.84mA
[Pullup]
|Voltage   I(typ)   I(min)   I(max)
-1.8V     5.972mA    6.203mA    6.117mA
-635mV    4.532mA    4.972mA    4.265mA
-415mV    3.791mA    4.125mA    3.491mA
-250mV    2.554mA    2.566mA    2.521mA
2.06V     -20.86mA   -20.88mA   -22mA
2.665V    -26.07mA   -25.67mA   -27.95mA
2.775V    -27.01mA   -25.73mA   -29.02mA
2.885V    -27.61mA   -25.17mA   -30.08mA
2.995V    -27.07mA   -25.4mA    -31.1mA
3.105V    -26.78mA   -25.93mA   -31.88mA
3.215V    -27.07mA   -26.56mA   -32.4mA
3.6V      -29.16mA   -28.97mA   -35.16mA
[GND_clamp]
|Voltage   I(typ)   I(min)   I(max)
-1.8V     -76.47A    -73.89A    -85.22A
-1.134V   -8.338A    -5.269A    -13.51A
-1.097V   -5.201A    -2.551A    -9.957A
-1.06V    -2.769A    -957.9mA   -6.857A
-1.023V   -1.254A    -361.3mA   -4.314A
-986mV    -548.8mA   -198.7mA   -2.455A
-949mV    -286.3mA   -149.8mA   -1.289A
-912mV    -191.8mA   -125.6mA   -669.7mA
-875mV    -150.6mA   -106.8mA   -376.6mA
-801mV    -105.3mA   -73.35mA   -175.4mA
-653mV    -39.86mA   -20.09mA   -71.17mA
1.8V      0A         0A         0A
[POWER_clamp]
|Voltage   I(typ)   I(min)   I(max)
-1.8V     48.65A     48.13A     49.56A
-1.086V   3.937A     1.965A     7.361A
-1.049V   1.843A     586.5mA    4.756A
-1.012V   681.6mA    139.2mA    2.697A
-975mV    220.2mA    38.2mA     1.331A
-938mV    73.81mA    17.48mA    589.9mA
-901mV    31.1mA     12.68mA    249.5mA
-864mV    18.42mA    10.94mA    108.1mA
-827mV    14.1mA     9.785mA    51.65mA
-753mV    10.72mA    7.761mA    19.73mA
-198mV    6.084uA    324.1nA    314.4uA
1.8V      0A         0A         0A
[Ramp]
| variable   typ   min   max
dV/dt_r   0.546/0.280n   0.492/0.286n   0.617/0.272n
dV/dt_f   0.548/0.270n   0.490/0.276n   0.616/0.267n
R_load = 100.000
[Rising Waveform]
R_fixture= 100.000
V_fixture= 1.800
V_fixture_min= 1.620
V_fixture_max= 1.980
|time   V(typ)   V(min)   V(max)
0s        887.3mV    803.4mV    953.1mV
852ps     919.3mV    803.6mV    972.4mV
906ps     1.026V     803.8mV    1.083V
1.036ns   1.389V     820.1mV    1.52V
1.127ns   1.54V      969.9mV    1.692V
1.213ns   1.629V     1.189V     1.793V
1.293ns   1.684V     1.332V     1.854V
1.517ns   1.759V     1.521V     1.937V
2.128ns   1.797V     1.613V     1.977V
5ns       1.8V       1.62V      1.98V
[Rising Waveform]
R_fixture= 100.000
V_fixture= 0.0
V_fixture_min= 0.0
V_fixture_max= 0.0
|time   V(typ)   V(min)   V(max)
0s        3.049uV    1.015uV    192.2uV
849ps     41.03mV    262.8uV    24.46mV
904ps     161.2mV    436.1uV    144.7mV
1.024ns   494.6mV    19.32mV    550.7mV
1.123ns   654.5mV    194.4mV    737.9mV
1.199ns   732.9mV    394.2mV    828.4mV
1.289ns   794.3mV    547.4mV    899.3mV
1.513ns   868.9mV    724.6mV    984.2mV
2.129ns   907.5mV    813mV      1.026V
5ns       910.2mV    819.6mV    1.029V
[Falling Waveform]
R_fixture= 100.000
V_fixture= 1.800
V_fixture_min= 1.620
V_fixture_max= 1.980
|time   V(typ)   V(min)   V(max)
0s        1.8V       1.62V      1.98V
923ps     1.799V     1.62V      1.979V
1.027ns   1.692V     1.62V      1.965V
1.081ns   1.539V     1.62V      1.84V
1.171ns   1.293V     1.603V     1.502V
1.291ns   1.11V      1.333V     1.249V
1.446ns   992.6mV    1.045V     1.09V
1.681ns   922.4mV    882.8mV    997.1mV
2.286ns   889.6mV    809.1mV    955.7mV
5ns       887.3mV    803.4mV    953.1mV
[Falling Waveform]
R_fixture= 100.000
V_fixture= 0.0
V_fixture_min= 0.0
V_fixture_max= 0.0
|time   V(typ)   V(min)   V(max)
0s        910.2mV    819.6mV    1.029V
915ps     909.2mV    819.5mV    1.028V
1.027ns   808.4mV    819.3mV    1.011V
1.077ns   675.4mV    819.1mV    901.1mV
1.171ns   412.8mV    799.2mV    552.9mV
1.295ns   223.4mV    527.4mV    293.9mV
1.461ns   102mV      229.8mV    131.4mV
1.695ns   35.29mV    77.68mV    44.16mV
2.311ns   2.483mV    5.776mV    2.957mV
5ns       3.164uV    1.278uV    192.2uV
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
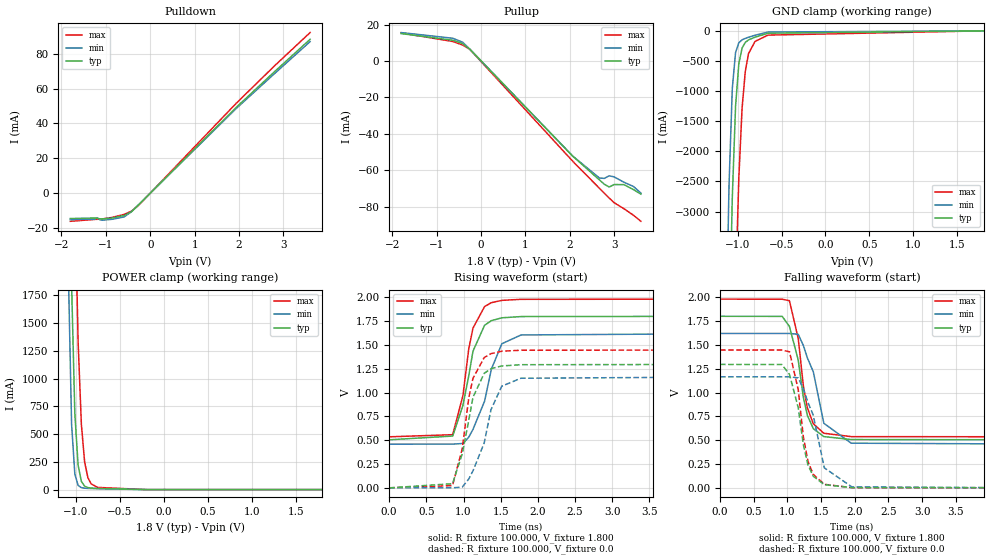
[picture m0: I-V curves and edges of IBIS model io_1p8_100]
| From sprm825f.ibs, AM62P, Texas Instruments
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|   Model io_1p8_100
[Model]   io_1p8_100
Model_type   I/O
Polarity   Non-Inverting
Enable   Active-High
Vinl =  0.630V
Vinh =  1.170V
Vmeas = 0.900V
Cref =  6.000pF
|   typ   min   max
C_comp   3.436pF   3.388pF   3.526pF
[Model Spec]
Vinh   1.170V   1.053V   1.287V
Vinl   0.630V   0.567V   0.693V
[Voltage Range]   1.8   1.62   1.98
[Temperature Range]   30   125   -40
[Pullup Reference]   1.8   1.62   1.98
[Pulldown Reference]   0   0   0
[Power Clamp Reference]   1.8   1.62   1.98
[GND Clamp Reference]   0   0   0
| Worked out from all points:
|   slope of the pulldown table from 0 to 0.27 V, typ, clamps not added: 38.9 ohm
|   slope of the pullup table from 0 to 0.27 V, typ, clamps not added: 39 ohm
|   GND clamp passes 1 mA (typ) near -0.43 V on its own axis
|   POWER clamp passes 1 mA (typ) near -0.38 V on its own axis
|   rising waveform, R_fixture 100.000, V_fixture 1.800: 20-80 % time 213ps typ, 265ps min, 184ps max; typ from 0.504 V to 1.8 V
|   rising waveform, R_fixture 100.000, V_fixture 0.0: 20-80 % time 212ps typ, 262ps min, 185ps max; typ from 0 V to 1.29 V
|   falling waveform, R_fixture 100.000, V_fixture 1.800: 20-80 % time 203ps typ, 248ps min, 179ps max; typ from 1.8 V to 0.504 V
|   falling waveform, R_fixture 100.000, V_fixture 0.0: 20-80 % time 204ps typ, 249ps min, 179ps max; typ from 1.29 V to 0 V
[Pulldown]
|Voltage   I(typ)   I(min)   I(max)
-1.8V     -14.6mA    -15.22mA   -16.19mA
-1.25V    -14.3mA    -14.93mA   -15.11mA
-1.195V   -14.48mA   -14.17mA   -15.04mA
-1.14V    -14.73mA   -15.24mA   -14.97mA
-1.085V   -14.88mA   -15.58mA   -14.86mA
-865mV    -14.32mA   -15.04mA   -13.99mA
-590mV    -12.87mA   -13.71mA   -12.25mA
-425mV    -10.73mA   -10.76mA   -10.41mA
-260mV    -6.684mA   -6.592mA   -6.971mA
1.94V     49.29mA    48.65mA    51.65mA
2.82V     70.18mA    69.07mA    73.54mA
3.6V      88.27mA    86.95mA    92.14mA
[Pullup]
|Voltage   I(typ)   I(min)   I(max)
-1.8V     15.05mA    15.61mA    15.38mA
-635mV    11.39mA    12.48mA    10.7mA
-415mV    9.515mA    10.33mA    8.751mA
-250mV    6.395mA    6.408mA    6.309mA
2.06V     -52.21mA   -52.17mA   -54.99mA
2.665V    -65.36mA   -64.31mA   -69.95mA
2.775V    -67.73mA   -64.53mA   -72.64mA
2.885V    -69.26mA   -63.11mA   -75.31mA
2.995V    -67.92mA   -63.69mA   -77.86mA
3.215V    -67.94mA   -66.6mA    -81.16mA
3.435V    -70.74mA   -69.02mA   -84.83mA
3.6V      -73.19mA   -72.65mA   -88.11mA
[GND_clamp]
|Voltage   I(typ)   I(min)   I(max)
-1.8V     -76.47A    -73.89A    -85.22A
-1.134V   -8.338A    -5.269A    -13.51A
-1.097V   -5.201A    -2.551A    -9.957A
-1.06V    -2.769A    -957.9mA   -6.857A
-1.023V   -1.254A    -361.3mA   -4.314A
-986mV    -548.8mA   -198.7mA   -2.455A
-949mV    -286.3mA   -149.8mA   -1.289A
-912mV    -191.8mA   -125.6mA   -669.7mA
-875mV    -150.6mA   -106.8mA   -376.6mA
-801mV    -105.3mA   -73.35mA   -175.4mA
-653mV    -39.86mA   -20.09mA   -71.17mA
1.8V      0A         0A         0A
[POWER_clamp]
|Voltage   I(typ)   I(min)   I(max)
-1.8V     48.65A     48.13A     49.56A
-1.086V   3.937A     1.965A     7.361A
-1.049V   1.843A     586.5mA    4.756A
-1.012V   681.6mA    139.2mA    2.697A
-975mV    220.2mA    38.2mA     1.331A
-938mV    73.81mA    17.48mA    589.9mA
-901mV    31.1mA     12.68mA    249.5mA
-864mV    18.42mA    10.94mA    108.1mA
-827mV    14.1mA     9.785mA    51.65mA
-753mV    10.72mA    7.761mA    19.73mA
-198mV    6.084uA    324.1nA    314.4uA
1.8V      0A         0A         0A
[Ramp]
| variable   typ   min   max
dV/dt_r   0.777/0.213n   0.699/0.263n   0.868/0.185n
dV/dt_f   0.777/0.203n   0.697/0.249n   0.867/0.179n
R_load = 100.000
[Rising Waveform]
R_fixture= 100.000
V_fixture= 1.800
V_fixture_min= 1.620
V_fixture_max= 1.980
|time   V(typ)   V(min)   V(max)
0s        504.4mV    458.5mV    535.5mV
854ps     543.4mV    458.8mV    557.7mV
992ps     866.6mV    465.7mV    968.9mV
1.07ns    1.174V     531.5mV    1.458V
1.127ns   1.434V     613.6mV    1.676V
1.283ns   1.706V     909.7mV    1.902V
1.374ns   1.754V     1.245V     1.943V
1.515ns   1.784V     1.512V     1.967V
1.773ns   1.797V     1.604V     1.978V
5ns       1.8V       1.62V      1.98V
[Rising Waveform]
R_fixture= 100.000
V_fixture= 0.0
V_fixture_min= 0.0
V_fixture_max= 0.0
|time   V(typ)   V(min)   V(max)
0s        1.733uV    578.9nV    108uV
852ps     43.4mV     317uV      24.05mV
983ps     358mV      8.092mV    412.8mV
1.07ns    708.2mV    92.62mV    942.3mV
1.127ns   950.7mV    178.6mV    1.15V
1.278ns   1.202V     472.7mV    1.367V
1.369ns   1.25V      820.4mV    1.408V
1.514ns   1.279V     1.067V     1.433V
1.772ns   1.292V     1.15V      1.444V
5ns       1.295V     1.165V     1.446V
[Falling Waveform]
R_fixture= 100.000
V_fixture= 1.800
V_fixture_min= 1.620
V_fixture_max= 1.980
|time   V(typ)   V(min)   V(max)
0s        1.8V       1.62V      1.98V
923ps     1.799V     1.62V      1.979V
1.03ns    1.694V     1.62V      1.964V
1.161ns   1.341V     1.611V     1.568V
1.238ns   945.9mV    1.492V     1.066V
1.296ns   761.7mV    1.365V     840.7mV
1.385ns   621.1mV    1.217V     672.1mV
1.541ns   537.9mV    677.5mV    572.8mV
1.947ns   506.7mV    468.7mV    537.6mV
5ns       504.4mV    458.5mV    535.5mV
[Falling Waveform]
R_fixture= 100.000
V_fixture= 0.0
V_fixture_min= 0.0
V_fixture_max= 0.0
|time   V(typ)   V(min)   V(max)
0s        1.295V     1.165V     1.446V
919ps     1.294V     1.165V     1.446V
1.032ns   1.189V     1.165V     1.427V
1.161ns   840.9mV    1.154V     1.03V
1.236ns   456mV      1.04V      539.5mV
1.305ns   242.3mV    896.5mV    281.4mV
1.383ns   122.8mV    764.9mV    141.9mV
1.548ns   33.32mV    210mV      37mV
1.957ns   2.366mV    10.06mV    2.337mV
5ns       1.76uV     553.5nV    108.1uV
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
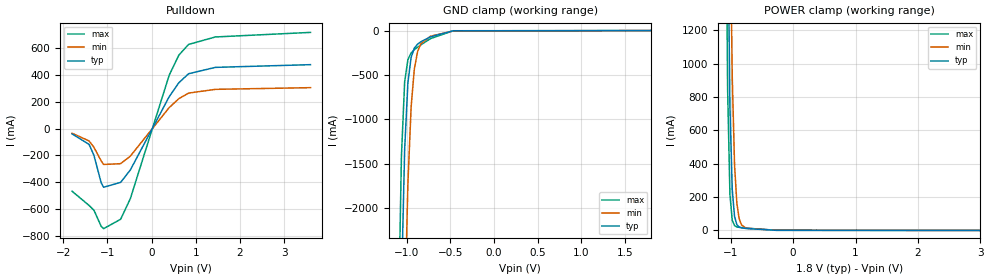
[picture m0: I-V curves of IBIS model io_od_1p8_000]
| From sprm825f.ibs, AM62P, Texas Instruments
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|   Model io_od_1p8_000
[Model]   io_od_1p8_000
Model_type   I/O_open_drain
Polarity   Non-Inverting
Enable   Active-High
Vinl =  0.630V
Vinh =  1.170V
Vmeas = 0.900V
Cref =  50.000pF
Rref =  4.700k
Vref =  1.800V
|   typ   min   max
C_comp   8.019pF   6.288pF   10.308pF
[Model Spec]
Vinh   1.170V   1.053V   1.287V
Vinl   0.630V   0.567V   0.693V
[Voltage Range]   1.8   1.62   1.98
[Temperature Range]   30   125   -40
[Pullup Reference]   1.8   1.62   1.98
[Pulldown Reference]   0   0   0
[Power Clamp Reference]   1.8   1.62   1.98
[GND Clamp Reference]   0   0   0
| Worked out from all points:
|   slope of the pulldown table from 0 to 0.27 V, typ, clamps not added: 1.64 ohm
|   GND clamp passes 1 mA (typ) near -0.43 V on its own axis
|   POWER clamp passes 1 mA (typ) near -0.37 V on its own axis
[Pulldown]
|Voltage   I(typ)   I(min)   I(max)
-1.8V     -39.91mA   -34.99mA   -468.3mA
-1.415V   -118.2mA   -92.5mA    -574.3mA
-1.305V   -199.6mA   -140.1mA   -609.7mA
-1.14V    -405.9mA   -242.3mA   -730.7mA
-1.085V   -438.4mA   -268.3mA   -747.8mA
-700mV    -402mA     -262.4mA   -677.5mA
-480mV    -309.3mA   -205.8mA   -523.4mA
400mV     238mA      156.5mA    398.7mA
620mV     342.9mA    223.5mA    549.2mA
840mV     409.6mA    264.9mA    628.5mA
1.445V    457mA      292.9mA    684.2mA
3.6V      477.3mA    305.5mA    718.3mA
[GND_clamp]
|Voltage   I(typ)   I(min)   I(max)
-1.8V     -76.47A    -76.69A    -88.72A
-1.097V   -5.386A    -8.268A    -3.42A
-1.06V    -2.917A    -5.461A    -1.424A
-1.023V   -1.346A    -3.251A    -578.9mA
-986mV    -591.1mA   -1.735A    -328.6mA
-949mV    -302.3mA   -863.2mA   -252.5mA
-912mV    -197.4mA   -432.7mA   -215.7mA
-875mV    -152.6mA   -237.8mA   -187.7mA
-838mV    -126.3mA   -149.6mA   -161.9mA
-727mV    -70.56mA   -63.46mA   -90.7mA
-468mV    -2.661mA   -4.447mA   -1.949mA
1.8V      0A         0A         0A
[POWER_clamp]
|Voltage   I(typ)   I(min)   I(max)
-1.8V     48.67A     48.99A     48.49A
-1.086V   4.074A     6.144A     2.54A
-1.049V   1.948A     3.749A     845.8mA
-1.012V   740.1mA    1.988A     214.2mA
-975mV    244.4mA    922.4mA    60.18mA
-938mV    82.37mA    391.6mA    27.84mA
-901mV    33.98mA    161.7mA    20.41mA
-864mV    19.43mA    69.17mA    17.82mA
-827mV    14.52mA    32.82mA    16.17mA
-753mV    10.9mA     12.35mA    13.31mA
-272mV    149.6uA    291uA      119.3uA
3.6V      -838.1uA   -712.3uA   -1.009mA
[Ramp]
| variable   typ   min   max
dV/dt_r   1.047/0.703n   0.927/0.727n   1.166/0.695n
dV/dt_f   1.047/0.116n   0.927/0.175n   1.166/80.571p
R_load = 50.000
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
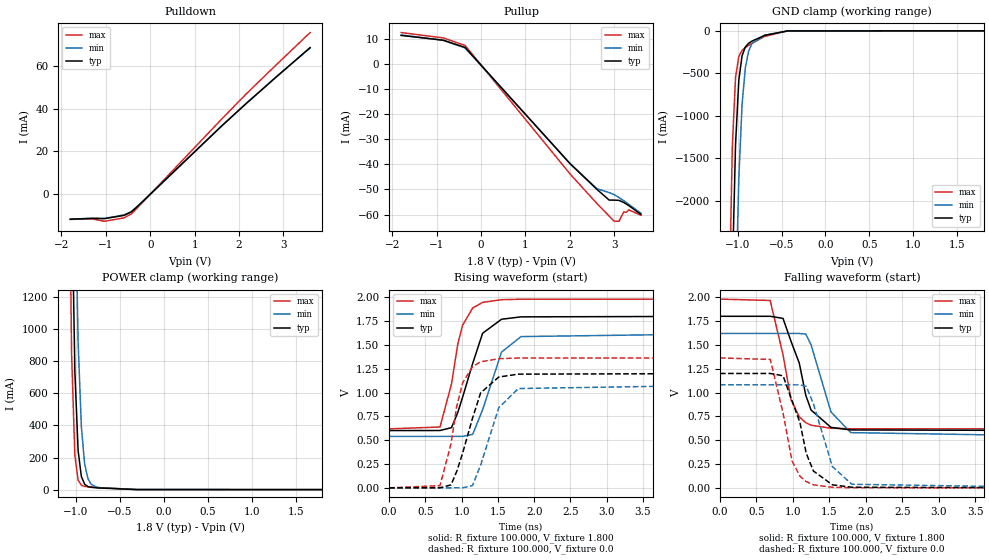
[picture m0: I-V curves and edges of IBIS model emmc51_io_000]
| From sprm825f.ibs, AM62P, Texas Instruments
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|   Model emmc51_io_000
[Model]   emmc51_io_000
Model_type   I/O
Polarity   Non-Inverting
Enable   Active-High
Vinl =  0.630V
Vinh =  1.170V
Vmeas = 0.900V
Cref =  15.000pF
Vref =  0.000V
|   typ   min   max
C_comp   3.560pF   3.550pF   3.579pF
[Model Spec]
Vinh   1.170V   1.053V   1.287V
Vinl   0.630V   0.567V   0.693V
[Voltage Range]   1.8   1.62   1.98
[Temperature Range]   30   125   -40
[Pullup Reference]   1.8   1.62   1.98
[Pulldown Reference]   0   0   0
[Power Clamp Reference]   1.8   1.62   1.98
[GND Clamp Reference]   0   0   0
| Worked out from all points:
|   slope of the pulldown table from 0 to 0.27 V, typ, clamps not added: 50.1 ohm
|   slope of the pullup table from 0 to 0.27 V, typ, clamps not added: 49.9 ohm
|   GND clamp passes 1 mA (typ) near -0.43 V on its own axis
|   POWER clamp passes 1 mA (typ) near -0.37 V on its own axis
|   rising waveform, R_fixture 100.000, V_fixture 1.800: 20-80 % time 282ps typ, 276ps min, 220ps max; typ from 0.601 V to 1.8 V
|   rising waveform, R_fixture 100.000, V_fixture 0.0: 20-80 % time 282ps typ, 275ps min, 221ps max; typ from 0 V to 1.2 V
|   falling waveform, R_fixture 100.000, V_fixture 1.800: 20-80 % time 269ps typ, 257ps min, 215ps max; typ from 1.8 V to 0.601 V
|   falling waveform, R_fixture 100.000, V_fixture 0.0: 20-80 % time 268ps typ, 258ps min, 214ps max; typ from 1.2 V to 0 V
[Pulldown]
|Voltage   I(typ)   I(min)   I(max)
-1.8V     -11.72mA   -11.69mA   -11.8mA
-1.305V   -11.31mA   -11.29mA   -11.56mA
-1.03V    -11.45mA   -11.34mA   -12.69mA
-590mV    -9.922mA   -9.703mA   -11.08mA
-425mV    -8.31mA    -8.144mA   -9.254mA
-260mV    -5.191mA   -5.203mA   -5.722mA
1.61V     31.9mA     31.96mA    35.14mA
2.16V     42.4mA     42.32mA    46.86mA
2.82V     54.48mA    54.53mA    60.13mA
3.6V      68.55mA    68.32mA    75.57mA
[Pullup]
|Voltage   I(typ)   I(min)   I(max)
-1.8V     11.58mA    11.76mA    12.72mA
-855mV    9.66mA     9.656mA    10.59mA
-360mV    6.777mA    6.575mA    7.574mA
2.005V    -39.71mA   -39.61mA   -43.81mA
2.61V     -49.96mA   -49.71mA   -55.63mA
2.885V    -54.23mA   -51.24mA   -60.64mA
2.995V    -54.25mA   -52.04mA   -62.64mA
3.105V    -54.33mA   -53.19mA   -62.71mA
3.215V    -55.21mA   -54.5mA    -58.92mA
3.27V     -55.79mA   -55.19mA   -59.17mA
3.325V    -56.43mA   -55.89mA   -58.13mA
3.6V      -59.94mA   -59.51mA   -60.29mA
[GND_clamp]
|Voltage   I(typ)   I(min)   I(max)
-1.8V     -75.65A    -76.8A     -77.06A
-1.097V   -5.362A    -8.277A    -3.304A
-1.06V    -2.901A    -5.469A    -1.372A
-1.023V   -1.335A    -3.257A    -545.7mA
-986mV    -582mA     -1.741A    -302.4mA
-949mV    -294.6mA   -868.2mA   -230.2mA
-912mV    -190.9mA   -437mA     -196.5mA
-875mV    -147.1mA   -241.5mA   -171.2mA
-838mV    -121.7mA   -152.7mA   -148.1mA
-690mV    -53.07mA   -50.52mA   -64.4mA
-431mV    -1.025mA   -2.287mA   -556.4uA
1.8V      0A         0A         0A
[POWER_clamp]
|Voltage   I(typ)   I(min)   I(max)
-1.8V     48.67A     48.99A     48.49A
-1.086V   4.073A     6.144A     2.539A
-1.049V   1.948A     3.749A     845.4mA
-1.012V   739.7mA    1.988A     213.8mA
-975mV    244mA      922.4mA    59.8mA
-938mV    81.98mA    391.6mA    27.48mA
-901mV    33.62mA    161.7mA    20.07mA
-864mV    19.09mA    69.19mA    17.5mA
-827mV    14.2mA     32.83mA    15.87mA
-753mV    10.62mA    12.34mA    13.05mA
-309mV    256.1uA    485.5uA    182.3uA
1.8V      0A         0A         0A
[Ramp]
| variable   typ   min   max
dV/dt_r   0.720/0.281n   0.649/0.275n   0.818/0.221n
dV/dt_f   0.719/0.269n   0.648/0.257n   0.816/0.213n
R_load = 100.000
[Rising Waveform]
R_fixture= 100.000
V_fixture= 1.800
V_fixture_min= 1.620
V_fixture_max= 1.980
|time   V(typ)   V(min)   V(max)
0s        601.1mV    539.7mV    619.1mV
701ps     601.7mV    539.8mV    638.3mV
860ps     632mV      539.9mV    1.09V
947ps     791.9mV    540.2mV    1.512V
1.012ns   948.1mV    540.3mV    1.705V
1.152ns   1.305V     560.9mV    1.887V
1.289ns   1.622V     820.2mV    1.946V
1.55ns    1.769V     1.424V     1.974V
1.819ns   1.794V     1.587V     1.979V
5ns       1.8V       1.62V      1.98V
[Rising Waveform]
R_fixture= 100.000
V_fixture= 0.0
V_fixture_min= 0.0
V_fixture_max= 0.0
|time   V(typ)   V(min)   V(max)
0s        2.422uV    21.07uV    4.142uV
701ps     538uV      67.48uV    23.11mV
854ps     31.78mV    205.5uV    464.6mV
933ps     175.1mV    378.3uV    860.2mV
1.014ns   365.9mV    634.2uV    1.103V
1.149ns   729mV      23.43mV    1.271V
1.261ns   995.6mV    236.9mV    1.322V
1.512ns   1.163V     841.1mV    1.355V
1.782ns   1.193V     1.042V     1.362V
5ns       1.2V       1.081V     1.363V
[Falling Waveform]
R_fixture= 100.000
V_fixture= 1.800
V_fixture_min= 1.620
V_fixture_max= 1.980
|time   V(typ)   V(min)   V(max)
0s        1.8V       1.62V      1.98V
688ps     1.8V       1.62V      1.966V
864ps     1.778V     1.62V      1.397V
974ps     1.537V     1.62V      924.2mV
1.087ns   1.309V     1.62V      745.1mV
1.176ns   971.8mV    1.613V     683.8mV
1.249ns   816.1mV    1.5V       657.3mV
1.521ns   634.8mV    796.6mV    625.3mV
1.793ns   607.7mV    579.5mV    620.1mV
5ns       601.1mV    539.7mV    619.1mV
[Falling Waveform]
R_fixture= 100.000
V_fixture= 0.0
V_fixture_min= 0.0
V_fixture_max= 0.0
|time   V(typ)   V(min)   V(max)
0s        1.2V       1.081V     1.363V
690ps     1.2V       1.081V     1.347V
865ps     1.176V     1.081V     784mV
987ps     915.5mV    1.081V     284.6mV
1.096ns   686.2mV    1.08V      122.9mV
1.182ns   363.7mV    1.065V     65.53mV
1.281ns   176.5mV    881.6mV    32.45mV
1.541ns   31.86mV    223.1mV    5.411mV
1.808ns   6.65mV     37.62mV    1.038mV
5ns       2.438uV    21.17uV    4.147uV
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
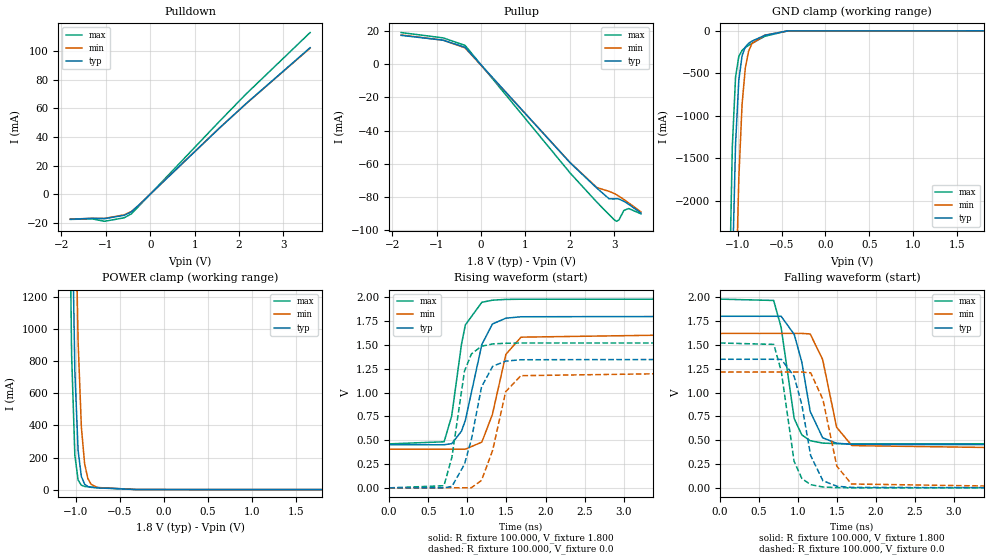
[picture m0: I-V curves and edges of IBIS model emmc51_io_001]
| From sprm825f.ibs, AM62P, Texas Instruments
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|   Model emmc51_io_001
[Model]   emmc51_io_001
Model_type   I/O
Polarity   Non-Inverting
Enable   Active-High
Vinl =  0.630V
Vinh =  1.170V
Vmeas = 0.900V
Cref =  15.000pF
Vref =  0.000V
|   typ   min   max
C_comp   3.405pF   3.396pF   3.409pF
[Model Spec]
Vinh   1.170V   1.053V   1.287V
Vinl   0.630V   0.567V   0.693V
[Voltage Range]   1.8   1.62   1.98
[Temperature Range]   30   125   -40
[Pullup Reference]   1.8   1.62   1.98
[Pulldown Reference]   0   0   0
[Power Clamp Reference]   1.8   1.62   1.98
[GND Clamp Reference]   0   0   0
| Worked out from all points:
|   slope of the pulldown table from 0 to 0.27 V, typ, clamps not added: 33.5 ohm
|   slope of the pullup table from 0 to 0.27 V, typ, clamps not added: 33.4 ohm
|   GND clamp passes 1 mA (typ) near -0.43 V on its own axis
|   POWER clamp passes 1 mA (typ) near -0.37 V on its own axis
|   rising waveform, R_fixture 100.000, V_fixture 1.800: 20-80 % time 216ps typ, 206ps min, 163ps max; typ from 0.452 V to 1.8 V
|   rising waveform, R_fixture 100.000, V_fixture 0.0: 20-80 % time 216ps typ, 206ps min, 163ps max; typ from 0 V to 1.35 V
|   falling waveform, R_fixture 100.000, V_fixture 1.800: 20-80 % time 202ps typ, 187ps min, 155ps max; typ from 1.8 V to 0.452 V
|   falling waveform, R_fixture 100.000, V_fixture 0.0: 20-80 % time 201ps typ, 189ps min, 156ps max; typ from 1.35 V to 0 V
[Pulldown]
|Voltage   I(typ)   I(min)   I(max)
-1.8V     -17.59mA   -17.54mA   -17.71mA
-1.305V   -16.98mA   -16.93mA   -17.35mA
-1.03V    -17.18mA   -17.01mA   -19.04mA
-590mV    -14.87mA   -14.54mA   -16.61mA
-425mV    -12.44mA   -12.19mA   -13.85mA
-260mV    -7.763mA   -7.782mA   -8.562mA
1.555V    46.1mA     46.19mA    50.82mA
2.16V     63.41mA    63.29mA    70.12mA
3.6V      102.5mA    102.2mA    113.1mA
[Pullup]
|Voltage   I(typ)   I(min)   I(max)
-1.8V     17.39mA    17.65mA    19.08mA
-855mV    14.49mA    14.48mA    15.88mA
-360mV    10.15mA    9.848mA    11.34mA
2.005V    -59.4mA    -59.26mA   -65.54mA
2.61V     -74.75mA   -74.36mA   -83.22mA
2.885V    -81.15mA   -76.66mA   -90.71mA
2.995V    -81.18mA   -77.85mA   -93.7mA
3.05V     -81.04mA   -78.66mA   -94.68mA
3.105V    -81.29mA   -79.56mA   -93.84mA
3.215V    -82.6mA    -81.52mA   -88.16mA
3.325V    -84.43mA   -83.61mA   -86.97mA
3.6V      -89.68mA   -89.01mA   -90.19mA
[GND_clamp]
|Voltage   I(typ)   I(min)   I(max)
-1.8V     -75.65A    -76.8A     -77.06A
-1.097V   -5.362A    -8.277A    -3.304A
-1.06V    -2.901A    -5.469A    -1.372A
-1.023V   -1.335A    -3.257A    -545.7mA
-986mV    -582mA     -1.741A    -302.4mA
-949mV    -294.6mA   -868.2mA   -230.2mA
-912mV    -190.9mA   -437mA     -196.5mA
-875mV    -147.1mA   -241.5mA   -171.2mA
-838mV    -121.7mA   -152.7mA   -148.1mA
-690mV    -53.07mA   -50.52mA   -64.4mA
-431mV    -1.025mA   -2.287mA   -556.4uA
1.8V      0A         0A         0A
[POWER_clamp]
|Voltage   I(typ)   I(min)   I(max)
-1.8V     48.67A     48.99A     48.49A
-1.086V   4.073A     6.144A     2.539A
-1.049V   1.948A     3.749A     845.4mA
-1.012V   739.7mA    1.988A     213.8mA
-975mV    244mA      922.4mA    59.8mA
-938mV    81.98mA    391.6mA    27.48mA
-901mV    33.62mA    161.7mA    20.07mA
-864mV    19.09mA    69.19mA    17.5mA
-827mV    14.2mA     32.83mA    15.87mA
-753mV    10.62mA    12.34mA    13.05mA
-309mV    256.1uA    485.5uA    182.3uA
1.8V      0A         0A         0A
[Ramp]
| variable   typ   min   max
dV/dt_r   0.810/0.216n   0.729/0.206n   0.912/0.162n
dV/dt_f   0.809/0.202n   0.729/0.187n   0.911/0.154n
R_load = 100.000
[Rising Waveform]
R_fixture= 100.000
V_fixture= 1.800
V_fixture_min= 1.620
V_fixture_max= 1.980
|time   V(typ)   V(min)   V(max)
0s        451.8mV    405.6mV    461.5mV
703ps     452.5mV    405.6mV    483.3mV
800ps     463.4mV    405.7mV    754.4mV
925ps     594.3mV    406mV      1.505V
975ps     709.6mV    406.2mV    1.71V
1.186ns   1.505V     480.2mV    1.947V
1.321ns   1.719V     770.7mV    1.969V
1.493ns   1.78V      1.401V     1.977V
1.687ns   1.795V     1.581V     1.979V
5ns       1.8V       1.62V      1.98V
[Rising Waveform]
R_fixture= 100.000
V_fixture= 0.0
V_fixture_min= 0.0
V_fixture_max= 0.0
|time   V(typ)   V(min)   V(max)
0s        1.819uV    15.81uV    3.085uV
701ps     644.2uV    66.01uV    22.45mV
803ps     14.82mV    151.6uV    322mV
963ps     246.7mV    551.6uV    1.223V
1.053ns   512.8mV    1.704mV    1.406V
1.182ns   1.06V      78.54mV    1.486V
1.324ns   1.275V     394mV      1.51V
1.491ns   1.33V      1.009V     1.517V
1.684ns   1.344V     1.177V     1.52V
5ns       1.349V     1.215V     1.52V
[Falling Waveform]
R_fixture= 100.000
V_fixture= 1.800
V_fixture_min= 1.620
V_fixture_max= 1.980
|time   V(typ)   V(min)   V(max)
0s        1.8V       1.62V      1.98V
689ps     1.8V       1.62V      1.966V
785ps     1.8V       1.62V      1.684V
953ps     1.61V      1.62V      726.1mV
1.05ns    1.321V     1.62V      556.3mV
1.158ns   801.9mV    1.615V     494.8mV
1.318ns   525.1mV    1.346V     469.9mV
1.497ns   468.2mV    635.8mV    463.7mV
1.693ns   456.1mV    443.4mV    462.1mV
5ns       451.8mV    405.6mV    461.5mV
[Falling Waveform]
R_fixture= 100.000
V_fixture= 0.0
V_fixture_min= 0.0
V_fixture_max= 0.0
|time   V(typ)   V(min)   V(max)
0s        1.349V     1.215V     1.52V
691ps     1.349V     1.215V     1.505V
787ps     1.348V     1.215V     1.222V
951ps     1.172V     1.215V     278.9mV
1.051ns   870.7mV    1.215V     98.07mV
1.164ns   338.6mV    1.207V     33.57mV
1.321ns   74.59mV    929.1mV    9.267mV
1.5ns     17.19mV    226.5mV    2.214mV
1.689ns   4.643mV    40.54mV    659.4uV
5ns       1.84uV     15.86uV    3.097uV
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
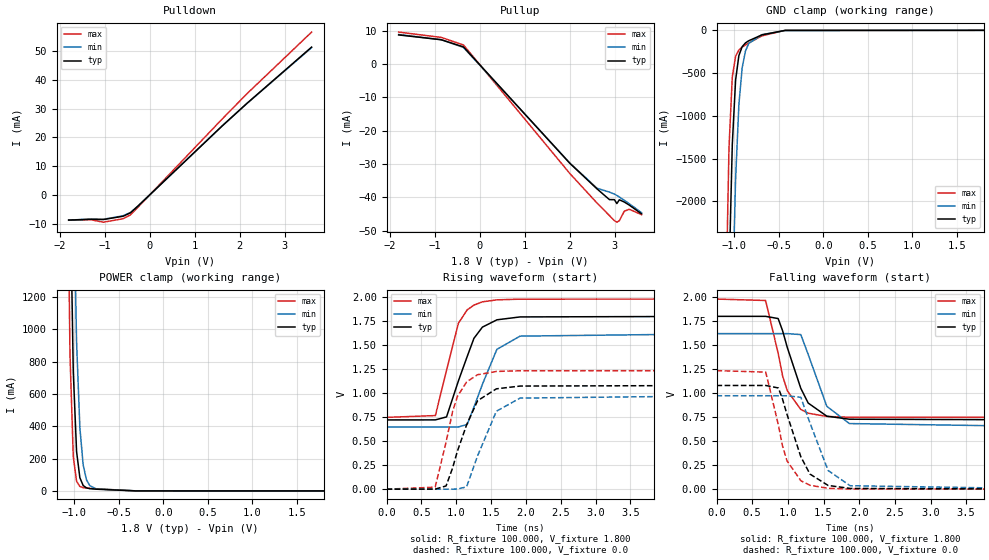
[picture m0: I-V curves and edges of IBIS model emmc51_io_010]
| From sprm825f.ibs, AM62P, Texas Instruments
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|   Model emmc51_io_010
[Model]   emmc51_io_010
Model_type   I/O
Polarity   Non-Inverting
Enable   Active-High
Vinl =  0.630V
Vinh =  1.170V
Vmeas = 0.900V
Cref =  15.000pF
Vref =  0.000V
|   typ   min   max
C_comp   3.664pF   3.622pF   3.671pF
[Model Spec]
Vinh   1.170V   1.053V   1.287V
Vinl   0.630V   0.567V   0.693V
[Voltage Range]   1.8   1.62   1.98
[Temperature Range]   30   125   -40
[Pullup Reference]   1.8   1.62   1.98
[Pulldown Reference]   0   0   0
[Power Clamp Reference]   1.8   1.62   1.98
[GND Clamp Reference]   0   0   0
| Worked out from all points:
|   slope of the pulldown table from 0 to 0.27 V, typ, clamps not added: 66.7 ohm
|   slope of the pullup table from 0 to 0.27 V, typ, clamps not added: 66.5 ohm
|   GND clamp passes 1 mA (typ) near -0.43 V on its own axis
|   POWER clamp passes 1 mA (typ) near -0.37 V on its own axis
|   rising waveform, R_fixture 100.000, V_fixture 1.800: 20-80 % time 309ps typ, 305ps min, 250ps max; typ from 0.721 V to 1.8 V
|   rising waveform, R_fixture 100.000, V_fixture 0.0: 20-80 % time 308ps typ, 304ps min, 253ps max; typ from 0 V to 1.08 V
|   falling waveform, R_fixture 100.000, V_fixture 1.800: 20-80 % time 296ps typ, 287ps min, 246ps max; typ from 1.8 V to 0.721 V
|   falling waveform, R_fixture 100.000, V_fixture 0.0: 20-80 % time 297ps typ, 288ps min, 246ps max; typ from 1.08 V to 0 V
[Pulldown]
|Voltage   I(typ)   I(min)   I(max)
-1.8V     -8.78mA    -8.761mA   -8.836mA
-1.305V   -8.478mA   -8.46mA    -8.66mA
-1.03V    -8.582mA   -8.501mA   -9.509mA
-590mV    -7.439mA   -7.275mA   -8.304mA
-425mV    -6.236mA   -6.11mA    -6.941mA
-260mV    -3.897mA   -3.906mA   -4.293mA
1.61V     23.95mA    23.99mA    26.37mA
2.16V     31.82mA    31.76mA    35.16mA
3.6V      51.43mA    51.26mA    56.66mA
[Pullup]
|Voltage   I(typ)   I(min)   I(max)
-1.8V     8.681mA    8.813mA    9.531mA
-855mV    7.242mA    7.239mA    7.936mA
-360mV    5.085mA    4.933mA    5.68mA
2.005V    -29.81mA   -29.73mA   -32.87mA
2.61V     -37.49mA   -37.29mA   -41.73mA
2.885V    -40.69mA   -38.44mA   -45.48mA
2.995V    -40.7mA    -39.04mA   -46.98mA
3.05V     -41.88mA   -39.44mA   -47.46mA
3.105V    -40.75mA   -39.9mA    -47.02mA
3.215V    -41.41mA   -40.88mA   -44.17mA
3.325V    -42.33mA   -41.92mA   -43.58mA
3.6V      -44.96mA   -44.63mA   -45.2mA
[GND_clamp]
|Voltage   I(typ)   I(min)   I(max)
-1.8V     -75.65A    -76.8A     -77.06A
-1.097V   -5.362A    -8.277A    -3.304A
-1.06V    -2.901A    -5.469A    -1.372A
-1.023V   -1.335A    -3.257A    -545.7mA
-986mV    -582mA     -1.741A    -302.4mA
-949mV    -294.6mA   -868.2mA   -230.2mA
-912mV    -190.9mA   -437mA     -196.5mA
-875mV    -147.1mA   -241.5mA   -171.2mA
-838mV    -121.7mA   -152.7mA   -148.1mA
-690mV    -53.07mA   -50.52mA   -64.4mA
-431mV    -1.025mA   -2.287mA   -556.4uA
1.8V      0A         0A         0A
[POWER_clamp]
|Voltage   I(typ)   I(min)   I(max)
-1.8V     48.67A     48.99A     48.49A
-1.086V   4.073A     6.144A     2.539A
-1.049V   1.948A     3.749A     845.4mA
-1.012V   739.7mA    1.988A     213.8mA
-975mV    244mA      922.4mA    59.8mA
-938mV    81.98mA    391.6mA    27.48mA
-901mV    33.62mA    161.7mA    20.07mA
-864mV    19.09mA    69.19mA    17.5mA
-827mV    14.2mA     32.83mA    15.87mA
-753mV    10.62mA    12.34mA    13.05mA
-309mV    256.1uA    485.5uA    182.3uA
1.8V      0A         0A         0A
[Ramp]
| variable   typ   min   max
dV/dt_r   0.648/0.309n   0.584/0.304n   0.741/0.253n
dV/dt_f   0.647/0.296n   0.583/0.286n   0.739/0.246n
R_load = 100.000
[Rising Waveform]
R_fixture= 100.000
V_fixture= 1.800
V_fixture_min= 1.620
V_fixture_max= 1.980
|time   V(typ)   V(min)   V(max)
0s        721.1mV    647.6mV    747.7mV
701ps     721.6mV    647.6mV    766.5mV
861ps     752.6mV    647.8mV    1.238V
1.032ns   1.129V     648.4mV    1.729V
1.157ns   1.381V     674.3mV    1.867V
1.254ns   1.571V     854.3mV    1.917V
1.376ns   1.688V     1.093V     1.951V
1.584ns   1.764V     1.457V     1.972V
1.917ns   1.794V     1.594V     1.979V
5ns       1.8V       1.62V      1.98V
[Rising Waveform]
R_fixture= 100.000
V_fixture= 0.0
V_fixture_min= 0.0
V_fixture_max= 0.0
|time   V(typ)   V(min)   V(max)
0s        2.906uV    25.28uV    5.002uV
698ps     496.8uV    72.49uV    20.72mV
854ps     33.34mV    200.9uV    488.3mV
947ps     218.7mV    397.9uV    806.7mV
1.016ns   393.9mV    625.3uV    964.6mV
1.149ns   670mV      24.31mV    1.117V
1.306ns   921.3mV    346.5mV    1.192V
1.576ns   1.045V     811.6mV    1.226V
1.916ns   1.074V     948.5mV    1.233V
5ns       1.08V      973.1mV    1.235V
[Falling Waveform]
R_fixture= 100.000
V_fixture= 1.800
V_fixture_min= 1.620
V_fixture_max= 1.980
|time   V(typ)   V(min)   V(max)
0s        1.8V       1.62V      1.98V
688ps     1.8V       1.62V      1.965V
864ps     1.777V     1.62V      1.415V
927ps     1.648V     1.62V      1.177V
993ps     1.473V     1.62V      1.024V
1.181ns   1.051V     1.61V      830.7mV
1.285ns   896.8mV    1.403V     791.4mV
1.546ns   760.3mV    863.2mV    757.2mV
1.862ns   728.7mV    683.3mV    749.2mV
5ns       721.1mV    647.6mV    747.7mV
[Falling Waveform]
R_fixture= 100.000
V_fixture= 0.0
V_fixture_min= 0.0
V_fixture_max= 0.0
|time   V(typ)   V(min)   V(max)
0s        1.08V      973.1mV    1.235V
690ps     1.08V      973.1mV    1.219V
867ps     1.054V     973mV      669.5mV
923ps     942.7mV    973mV      455.2mV
988ps     778.6mV    972.9mV    295.5mV
1.182ns   337.1mV    956.1mV    87.63mV
1.31ns    157.2mV    688.9mV    40.22mV
1.564ns   38.86mV    194.8mV    9.026mV
1.873ns   7.679mV    35.73mV    1.598mV
5ns       2.918uV    25.42uV    5.005uV
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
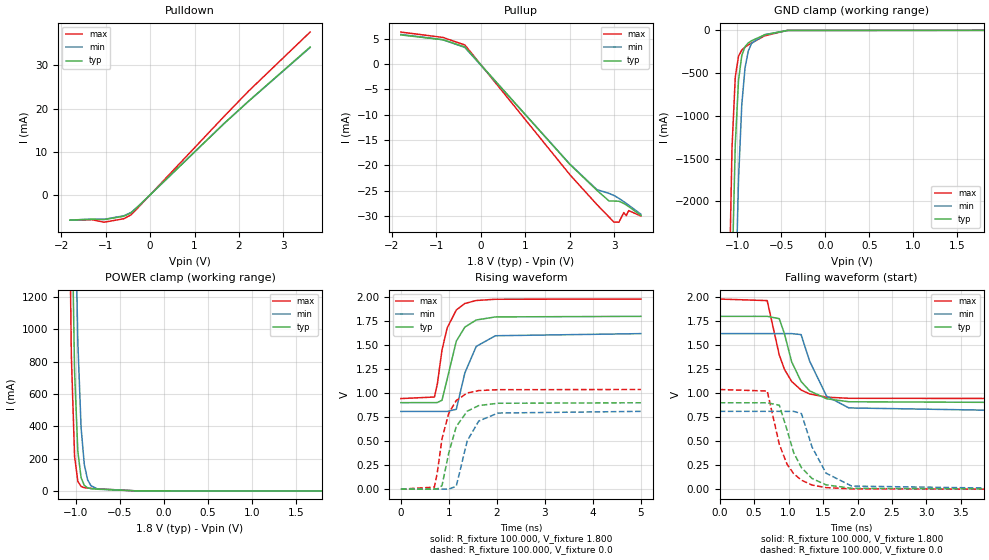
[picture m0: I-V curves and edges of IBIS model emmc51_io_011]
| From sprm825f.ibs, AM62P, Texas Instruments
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|   Model emmc51_io_011
[Model]   emmc51_io_011
Model_type   I/O
Polarity   Non-Inverting
Enable   Active-High
Vinl =  0.630V
Vinh =  1.170V
Vmeas = 0.900V
Cref =  15.000pF
Vref =  0.000V
|   typ   min   max
C_comp   3.749pF   3.694pF   3.762pF
[Model Spec]
Vinh   1.170V   1.053V   1.287V
Vinl   0.630V   0.567V   0.693V
[Voltage Range]   1.8   1.62   1.98
[Temperature Range]   30   125   -40
[Pullup Reference]   1.8   1.62   1.98
[Pulldown Reference]   0   0   0
[Power Clamp Reference]   1.8   1.62   1.98
[GND Clamp Reference]   0   0   0
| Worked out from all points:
|   slope of the pulldown table from 0 to 0.27 V, typ, clamps not added: 100 ohm
|   slope of the pullup table from 0 to 0.27 V, typ, clamps not added: 99.8 ohm
|   GND clamp passes 1 mA (typ) near -0.43 V on its own axis
|   POWER clamp passes 1 mA (typ) near -0.37 V on its own axis
|   rising waveform, R_fixture 100.000, V_fixture 1.800: 20-80 % time 293ps typ, 295ps min, 262ps max; typ from 0.901 V to 1.8 V
|   rising waveform, R_fixture 100.000, V_fixture 0.0: 20-80 % time 296ps typ, 293ps min, 270ps max; typ from 0 V to 0.9 V
|   falling waveform, R_fixture 100.000, V_fixture 1.800: 20-80 % time 285ps typ, 284ps min, 262ps max; typ from 1.8 V to 0.901 V
|   falling waveform, R_fixture 100.000, V_fixture 0.0: 20-80 % time 289ps typ, 290ps min, 266ps max; typ from 0.9 V to 0 V
[Pulldown]
|Voltage   I(typ)   I(min)   I(max)
-1.8V     -5.858mA   -5.843mA   -5.887mA
-1.305V   -5.656mA   -5.643mA   -5.77mA
-1.03V    -5.726mA   -5.671mA   -6.341mA
-590mV    -4.963mA   -4.854mA   -5.537mA
-425mV    -4.162mA   -4.077mA   -4.63mA
-260mV    -2.601mA   -2.607mA   -2.864mA
1.665V    16.52mA    16.55mA    18.18mA
2.215V    21.71mA    21.69mA    24.04mA
3.6V      34.26mA    34.16mA    37.74mA
[Pullup]
|Voltage   I(typ)   I(min)   I(max)
-1.8V     5.769mA    5.859mA    6.325mA
-855mV    4.815mA    4.815mA    5.271mA
-360mV    3.386mA    3.284mA    3.779mA
2.005V    -19.86mA   -19.8mA    -21.89mA
2.61V     -24.95mA   -24.81mA   -27.76mA
2.885V    -27.07mA   -25.57mA   -30.25mA
2.995V    -27.07mA   -25.97mA   -31.24mA
3.105V    -27.11mA   -26.54mA   -31.25mA
3.215V    -27.55mA   -27.19mA   -29.35mA
3.27V     -27.84mA   -27.53mA   -29.95mA
3.325V    -28.16mA   -27.88mA   -28.96mA
3.6V      -29.91mA   -29.68mA   -30.03mA
[GND_clamp]
|Voltage   I(typ)   I(min)   I(max)
-1.8V     -75.65A    -76.8A     -77.07A
-1.097V   -5.362A    -8.277A    -3.304A
-1.06V    -2.901A    -5.469A    -1.372A
-1.023V   -1.335A    -3.257A    -545.8mA
-986mV    -582mA     -1.741A    -302.4mA
-949mV    -294.6mA   -868.2mA   -230.2mA
-912mV    -190.9mA   -437mA     -196.6mA
-875mV    -147.1mA   -241.5mA   -171.3mA
-838mV    -121.7mA   -152.7mA   -148.1mA
-690mV    -53.07mA   -50.52mA   -64.41mA
-431mV    -1.025mA   -2.287mA   -556.4uA
1.8V      0A         0A         0A
[POWER_clamp]
|Voltage   I(typ)   I(min)   I(max)
-1.8V     48.67A     48.99A     48.49A
-1.086V   4.073A     6.144A     2.539A
-1.049V   1.948A     3.749A     845.4mA
-1.012V   739.7mA    1.988A     213.8mA
-975mV    244mA      922.4mA    59.8mA
-938mV    81.98mA    391.6mA    27.48mA
-901mV    33.62mA    161.7mA    20.07mA
-864mV    19.09mA    69.19mA    17.5mA
-827mV    14.2mA     32.83mA    15.87mA
-753mV    10.62mA    12.34mA    13.05mA
-309mV    256.1uA    485.5uA    182.3uA
1.8V      0A         0A         0A
[Ramp]
| variable   typ   min   max
dV/dt_r   0.540/0.297n   0.486/0.293n   0.623/0.269n
dV/dt_f   0.540/0.285n   0.486/0.285n   0.622/0.260n
R_load = 100.000
[Rising Waveform]
R_fixture= 100.000
V_fixture= 1.800
V_fixture_min= 1.620
V_fixture_max= 1.980
|time   V(typ)   V(min)   V(max)
0s        900.9mV    809.4mV    943.5mV
699ps     901.4mV    809.5mV    959.7mV
761ps     902.5mV    809.5mV    1.099V
857ps     926.2mV    809.6mV    1.45V
965ps     1.148V     809.8mV    1.68V
1.155ns   1.542V     831.8mV    1.866V
1.333ns   1.688V     1.211V     1.934V
1.57ns    1.762V     1.487V     1.965V
1.969ns   1.794V     1.598V     1.978V
5ns       1.8V       1.62V      1.98V
[Rising Waveform]
R_fixture= 100.000
V_fixture= 0.0
V_fixture_min= 0.0
V_fixture_max= 0.0
|time   V(typ)   V(min)   V(max)
0s        3.629uV    31.6uV     6.31uV
698ps     462.3uV    78.46uV    21.38mV
756ps     1.553mV    108.3uV    163.5mV
857ps     37.15mV    201.3uV    524.7mV
996ps     372.5mV    487uV      788.9mV
1.154ns   652.9mV    30.48mV    923.2mV
1.382ns   812.1mV    502.9mV    1.002V
1.622ns   870.4mV    709.4mV    1.027V
2.022ns   894.7mV    792.9mV    1.036V
5ns       899.9mV    810.5mV    1.038V
[Falling Waveform]
R_fixture= 100.000
V_fixture= 1.800
V_fixture_min= 1.620
V_fixture_max= 1.980
|time   V(typ)   V(min)   V(max)
0s        1.8V       1.62V      1.98V
689ps     1.8V       1.62V      1.964V
864ps     1.776V     1.62V      1.399V
940ps     1.618V     1.62V      1.248V
1.044ns   1.327V     1.62V      1.122V
1.181ns   1.122V     1.61V      1.033V
1.305ns   1.024V     1.334V     991.6mV
1.551ns   941.5mV    969.1mV    958.2mV
1.874ns   910.4mV    846.3mV    946.6mV
5ns       900.9mV    809.4mV    943.6mV
[Falling Waveform]
R_fixture= 100.000
V_fixture= 0.0
V_fixture_min= 0.0
V_fixture_max= 0.0
|time   V(typ)   V(min)   V(max)
0s        899.9mV    810.5mV    1.038V
690ps     899.6mV    810.5mV    1.022V
865ps     874.6mV    810.5mV    466.7mV
978ps     615.4mV    810.3mV    258.4mV
1.074ns   380mV      810.1mV    160.7mV
1.186ns   224.6mV    787.5mV    93.79mV
1.34ns    111.1mV    439.5mV    42.88mV
1.544ns   44.95mV    166.6mV    16.22mV
1.916ns   9.064mV    32.16mV    2.827mV
5ns       3.667uV    31.86uV    6.313uV
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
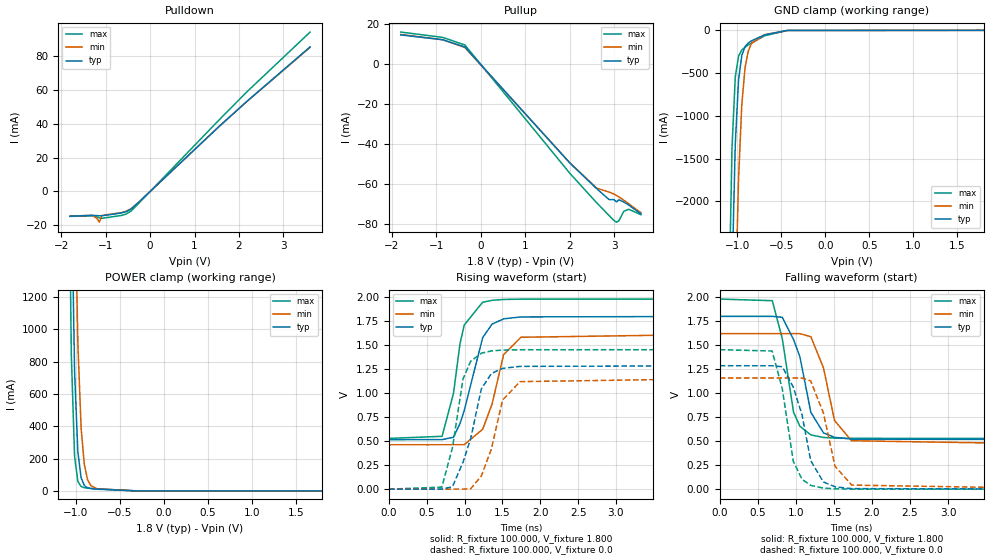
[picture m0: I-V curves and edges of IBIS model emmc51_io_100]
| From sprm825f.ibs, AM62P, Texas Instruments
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|   Model emmc51_io_100
[Model]   emmc51_io_100
Model_type   I/O
Polarity   Non-Inverting
Enable   Active-High
Vinl =  0.630V
Vinh =  1.170V
Vmeas = 0.900V
Cref =  15.000pF
Vref =  0.000V
|   typ   min   max
C_comp   3.487pF   3.478pF   3.494pF
[Model Spec]
Vinh   1.170V   1.053V   1.287V
Vinl   0.630V   0.567V   0.693V
[Voltage Range]   1.8   1.62   1.98
[Temperature Range]   30   125   -40
[Pullup Reference]   1.8   1.62   1.98
[Pulldown Reference]   0   0   0
[Power Clamp Reference]   1.8   1.62   1.98
[GND Clamp Reference]   0   0   0
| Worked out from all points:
|   slope of the pulldown table from 0 to 0.27 V, typ, clamps not added: 40.1 ohm
|   slope of the pullup table from 0 to 0.27 V, typ, clamps not added: 40 ohm
|   GND clamp passes 1 mA (typ) near -0.43 V on its own axis
|   POWER clamp passes 1 mA (typ) near -0.37 V on its own axis
|   rising waveform, R_fixture 100.000, V_fixture 1.800: 20-80 % time 245ps typ, 240ps min, 189ps max; typ from 0.516 V to 1.8 V
|   rising waveform, R_fixture 100.000, V_fixture 0.0: 20-80 % time 245ps typ, 239ps min, 190ps max; typ from 0 V to 1.29 V
|   falling waveform, R_fixture 100.000, V_fixture 1.800: 20-80 % time 233ps typ, 222ps min, 182ps max; typ from 1.8 V to 0.516 V
|   falling waveform, R_fixture 100.000, V_fixture 0.0: 20-80 % time 231ps typ, 221ps min, 182ps max; typ from 1.29 V to 0 V
[Pulldown]
|Voltage   I(typ)   I(min)   I(max)
-1.8V     -14.65mA   -14.62mA   -14.76mA
-1.305V   -14.15mA   -14.11mA   -14.46mA
-1.195V   -14.27mA   -15.95mA   -15.01mA
-1.14V    -14.38mA   -18.19mA   -15.58mA
-1.085V   -14.4mA    -14.24mA   -15.9mA
-645mV    -12.76mA   -12.52mA   -14.22mA
-535mV    -11.94mA   -11.64mA   -13.36mA
-425mV    -10.38mA   -10.17mA   -11.56mA
-260mV    -6.482mA   -6.497mA   -7.146mA
1.555V    38.49mA    38.56mA    42.41mA
2.16V     52.94mA    52.85mA    58.52mA
3.6V      85.62mA    85.32mA    94.37mA
[Pullup]
|Voltage   I(typ)   I(min)   I(max)
-1.8V     14.48mA    14.7mA     15.9mA
-855mV    12.07mA    12.07mA    13.24mA
-360mV    8.466mA    8.214mA    9.461mA
2.005V    -49.57mA   -49.46mA   -54.7mA
2.61V     -62.39mA   -62.07mA   -69.46mA
2.885V    -67.73mA   -63.99mA   -75.72mA
2.995V    -67.75mA   -64.98mA   -78.21mA
3.05V     -68.89mA   -65.66mA   -79.02mA
3.105V    -67.84mA   -66.41mA   -78.31mA
3.215V    -68.94mA   -68.05mA   -73.57mA
3.325V    -70.46mA   -69.79mA   -72.58mA
3.6V      -74.85mA   -74.3mA    -75.27mA
[GND_clamp]
|Voltage   I(typ)   I(min)   I(max)
-1.8V     -75.65A    -76.8A     -77.06A
-1.097V   -5.362A    -8.277A    -3.304A
-1.06V    -2.901A    -5.469A    -1.372A
-1.023V   -1.335A    -3.257A    -545.7mA
-986mV    -582mA     -1.741A    -302.4mA
-949mV    -294.6mA   -868.2mA   -230.2mA
-912mV    -190.9mA   -437mA     -196.5mA
-875mV    -147.1mA   -241.5mA   -171.2mA
-838mV    -121.7mA   -152.7mA   -148.1mA
-690mV    -53.07mA   -50.52mA   -64.4mA
-431mV    -1.025mA   -2.287mA   -556.4uA
1.8V      0A         0A         0A
[POWER_clamp]
|Voltage   I(typ)   I(min)   I(max)
-1.8V     48.67A     48.99A     48.49A
-1.086V   4.073A     6.144A     2.539A
-1.049V   1.948A     3.749A     845.4mA
-1.012V   739.7mA    1.988A     213.8mA
-975mV    244mA      922.4mA    59.8mA
-938mV    81.98mA    391.6mA    27.48mA
-901mV    33.62mA    161.7mA    20.07mA
-864mV    19.09mA    69.19mA    17.5mA
-827mV    14.2mA     32.83mA    15.87mA
-753mV    10.62mA    12.34mA    13.05mA
-309mV    256.1uA    485.5uA    182.3uA
1.8V      0A         0A         0A
[Ramp]
| variable   typ   min   max
dV/dt_r   0.771/0.245n   0.695/0.238n   0.872/0.189n
dV/dt_f   0.771/0.232n   0.694/0.221n   0.871/0.182n
R_load = 100.000
[Rising Waveform]
R_fixture= 100.000
V_fixture= 1.800
V_fixture_min= 1.620
V_fixture_max= 1.980
|time   V(typ)   V(min)   V(max)
0s        515.6mV    462.9mV    528.6mV
703ps     516.2mV    462.9mV    550.5mV
854ps     540.7mV    463.1mV    999.2mV
940ps     683.4mV    463.3mV    1.517V
996ps     820.2mV    463.5mV    1.71V
1.239ns   1.578V     623.6mV    1.947V
1.363ns   1.719V     885.5mV    1.967V
1.516ns   1.774V     1.402V     1.976V
1.744ns   1.794V     1.582V     1.979V
5ns       1.8V       1.62V      1.98V
[Rising Waveform]
R_fixture= 100.000
V_fixture= 0.0
V_fixture_min= 0.0
V_fixture_max= 0.0
|time   V(typ)   V(min)   V(max)
0s        2.077uV    18.06uV    3.535uV
700ps     578.5uV    66.07uV    21.21mV
840ps     25.54mV    192.6uV    432mV
980ps     282.9mV    564.7uV    1.15V
1.08ns    523.3mV    4.35mV     1.332V
1.221ns   1.043V     135.4mV    1.416V
1.355ns   1.205V     421mV      1.44V
1.502ns   1.258V     928.2mV    1.449V
1.733ns   1.279V     1.12V      1.452V
5ns       1.286V     1.158V     1.453V
[Falling Waveform]
R_fixture= 100.000
V_fixture= 1.800
V_fixture_min= 1.620
V_fixture_max= 1.980
|time   V(typ)   V(min)   V(max)
0s        1.8V       1.62V      1.98V
691ps     1.8V       1.62V      1.963V
822ps     1.79V      1.62V      1.57V
971ps     1.558V     1.62V      800.7mV
1.054ns   1.379V     1.62V      655mV
1.198ns   799.4mV    1.588V     565.2mV
1.364ns   586.5mV    1.263V     538.7mV
1.509ns   539.7mV    715.2mV    532.2mV
1.733ns   521.2mV    504.3mV    529.3mV
5ns       515.6mV    462.9mV    528.6mV
[Falling Waveform]
R_fixture= 100.000
V_fixture= 0.0
V_fixture_min= 0.0
V_fixture_max= 0.0
|time   V(typ)   V(min)   V(max)
0s        1.286V     1.158V     1.453V
689ps     1.285V     1.158V     1.439V
823ps     1.275V     1.158V     1.045V
967ps     1.063V     1.158V     290.1mV
1.082ns   774.2mV    1.157V     102.8mV
1.196ns   297.1mV    1.127V     39.55mV
1.362ns   75.49mV    796mV      11.17mV
1.515ns   24.51mV    239.7mV    3.773mV
1.735ns   5.586mV    42.25mV    865.9uV
5ns       2.101uV    18.09uV    3.544uV
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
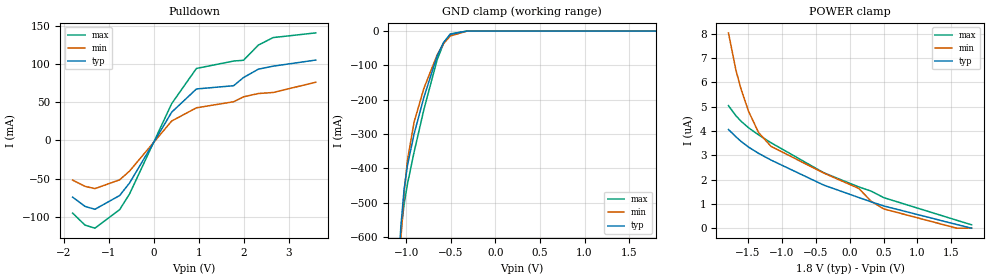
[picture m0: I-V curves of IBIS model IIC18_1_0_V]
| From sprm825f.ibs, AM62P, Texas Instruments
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|   Model IIC18_1_0_V
[Model]  IIC18_1_0_V
Model_type I/O_open_drain
Polarity   Non-Inverting
Enable   Active-High
Vinl =  0.540V
Vinh =  1.260V
Vmeas =  0.900V
Cref =  50.000pF
Rref =  1.000M
Vref =  0.0V
C_comp   8.659pF   8.515pF   8.754pF
[Model Spec]
Vinh   1.260V   1.134V   1.386V
Vinl   0.540V   0.486V   0.594V
Vmeas   0.900V   NA   NA
Vref   0.0V   NA   NA
Cref   50.000pF   NA   NA
Rref   1.000M   NA   NA
[Temperature Range]   25.000   0.125k   -40.000
[Voltage Range]   1.800V   1.620V   1.980V
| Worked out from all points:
|   slope of the pulldown table from 0 to 0.27 V, typ, clamps not added: 10.5 ohm
|   GND clamp passes 1 mA (typ) near -0.42 V on its own axis
[Pulldown]
|Voltage   I(typ)   I(min)   I(max)
-1.8V     -74.43mA   -52.12mA   -95.36mA
-1.525V   -86.51mA   -60.23mA   -111.1mA
-1.305V   -90.39mA   -63.27mA   -115.1mA
-755mV    -72.29mA   -51.71mA   -90.8mA
-535mV    -55.85mA   -40.22mA   -70.21mA
400mV     36.93mA    25.37mA    48.14mA
950mV     67.4mA     42.7mA     94.32mA
1.775V    71.64mA    50.63mA    104mA
1.995V    82.32mA    57.1mA     105mA
2.325V    93.33mA    61.41mA    124.9mA
2.655V    97.31mA    62.78mA    134.8mA
3.6V      105.3mA    76.2mA     140.9mA
[GND_clamp]
|Voltage   I(typ)   I(min)   I(max)
-1.8V     -13.06A    -12.03A    -14.07A
-1.097V   -750.9mA   -811mA     -744.1mA
-1.06V    -568.7mA   -607.9mA   -587.9mA
-1.023V   -459.9mA   -469mA     -502.8mA
-986mV    -391.5mA   -376.2mA   -445.5mA
-912mV    -300.2mA   -265.5mA   -353.1mA
-801mV    -192.3mA   -166.3mA   -227.7mA
-653mV    -72.66mA   -69.43mA   -83.58mA
-579mV    -32.26mA   -35.8mA    -34.59mA
-505mV    -9.385mA   -14.2mA    -8.27mA
-320mV    -33.94uA   -278.5uA   -6.542uA
1.8V      0A         0A         0A
[POWER_clamp]
|Voltage   I(typ)   I(min)   I(max)
-1.789V   4.06uA     8.036uA    5.043uA
-1.678V   3.76uA     6.495uA    4.626uA
-1.604V   3.573uA    5.732uA    4.404uA
-1.493V   3.337uA    4.814uA    4.134uA
-1.345V   3.08uA     3.938uA    3.84uA
-1.16V    2.802uA    3.365uA    3.514uA
-383mV    1.773uA    2.269uA    2.282uA
135mV     1.261uA    1.635uA    1.696uA
320mV     1.081uA    1.098uA    1.522uA
505mV     912.7nA    791.1nA    1.254uA
1.578V    151.7nA    0A         328nA
1.8V      0A         0A         138.8nA
[Ramp]
| variable   typ   min   max
dV/dt_r   0.891/0.444n   0.740/0.440n   1.022/0.471n
dV/dt_f   0.231/21.099n   91.039m/16.097n   0.455/15.708n
R_load = 50.000
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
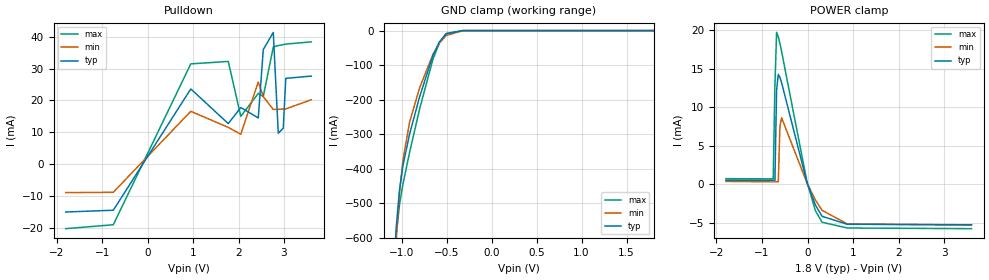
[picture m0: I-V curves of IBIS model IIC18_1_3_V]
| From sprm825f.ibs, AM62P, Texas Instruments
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|   Model IIC18_1_3_V
[Model]  IIC18_1_3_V
Model_type I/O_open_drain
Polarity   Non-Inverting
Enable   Active-High
Vinl =  0.540V
Vinh =  1.260V
Vmeas =  0.900V
Cref =  50.000pF
Rref =  1.000M
Vref =  0.0V
C_comp   8.659pF   8.515pF   8.754pF
[Model Spec]
Vinh   1.260V   1.134V   1.386V
Vinl   0.540V   0.486V   0.594V
Vmeas   0.900V   NA   NA
Vref   0.0V   NA   NA
Cref   50.000pF   NA   NA
Rref   1.000M   NA   NA
[Temperature Range]   25.000   0.125k   -40.000
[Voltage Range]   1.800V   1.620V   1.980V
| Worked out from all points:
|   slope of the pulldown table from 0 to 0.27 V, typ, clamps not added: 38.5 ohm
|   GND clamp passes 1 mA (typ) near -0.42 V on its own axis
|   POWER clamp passes 1 mA (typ) near -0.05 V on its own axis
[Pulldown]
|Voltage   I(typ)   I(min)   I(max)
-1.8V     -15mA      -8.913mA   -20.22mA
-755mV    -14.44mA   -8.818mA   -18.99mA
950mV     23.6mA     16.59mA    31.46mA
1.775V    12.73mA    11.54mA    32.22mA
2.05V     17.77mA    9.387mA    15.01mA
2.435V    14.5mA     25.77mA    22.19mA
2.545V    35.94mA    21.17mA    21.22mA
2.765V    41.33mA    17.16mA    36.74mA
2.875V    9.707mA    17.22mA    37.19mA
2.985V    11.28mA    17.29mA    37.52mA
3.04V     26.91mA    17.33mA    37.65mA
3.6V      27.63mA    20.2mA     38.36mA
[GND_clamp]
|Voltage   I(typ)   I(min)   I(max)
-1.8V     -13.06A    -12.03A    -14.07A
-1.097V   -750.9mA   -811mA     -744.1mA
-1.06V    -568.7mA   -607.9mA   -587.9mA
-1.023V   -459.9mA   -469mA     -502.8mA
-986mV    -391.5mA   -376.2mA   -445.5mA
-912mV    -300.2mA   -265.5mA   -353.1mA
-801mV    -192.3mA   -166.3mA   -227.7mA
-653mV    -72.66mA   -69.43mA   -83.58mA
-579mV    -32.26mA   -35.79mA   -34.59mA
-505mV    -9.384mA   -14.19mA   -8.27mA
-320mV    -33.55uA   -275.7uA   -6.137uA
1.8V      0A         0A         0A
[POWER_clamp]
|Voltage   I(typ)   I(min)   I(max)
-1.789V   502.3uA    344.3uA    709.8uA
-753mV    477.1uA    298.4uA    679.7uA
-716mV    477uA      297.5uA    12.77mA
-679mV    12.2mA     297.2uA    19.7mA
-642mV    14.25mA    301.9uA    19.14mA
-605mV    13.84mA    7.606mA    18.23mA
-568mV    13.14mA    8.59mA     17.18mA
-13mV     244.9uA    177.8uA    321.3uA
172mV     -2.72mA    -2.063mA   -3.44mA
320mV     -4.182mA   -3.407mA   -4.955mA
875mV     -5.218mA   -5.177mA   -5.702mA
3.6V      -5.284mA   -5.313mA   -5.786mA
[Ramp]
| variable   typ   min   max
dV/dt_r   0.541/0.227n   0.354/0.179n   0.705/0.288n
dV/dt_f   0.255/17.578n   0.110/15.295n   0.485/14.137n
R_load = 50.000
|End ************* [Component] IIC _1.8V_V *******************************
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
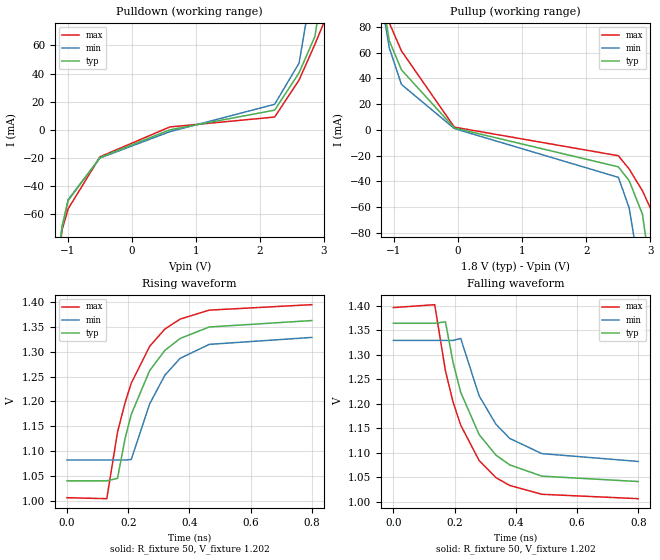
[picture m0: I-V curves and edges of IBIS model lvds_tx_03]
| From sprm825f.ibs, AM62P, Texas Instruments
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|   MODEL lvds_tx_03
[Model] lvds_tx_03
Model_type Output
C_comp 1.524p 1.54p 1.475p
Vmeas = 1.2
Vref = 1.2V
Rref = 50
Cref = 0.5pF
[Model Spec]
[Temperature Range]  40 150 -40
[Voltage Range] 1.8 1.62 1.98
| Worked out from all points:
|   slope of the pulldown table from 0 to 0.27 V, typ, clamps not added: 61.1 ohm
|   slope of the pullup table from 0 to 0.27 V, typ, clamps not added: 88.6 ohm
|   rising waveform, R_fixture 50, V_fixture 1.202: 20-80 % time 131ps typ, 121ps min, 129ps max; typ from 1.04 V to 1.36 V
|   falling waveform, R_fixture 50, V_fixture 1.202: 20-80 % time 127ps typ, 131ps min, 125ps max; typ from 1.36 V to 1.04 V
[Pulldown]
-1.715V   -358.5mA   -310.6mA   -422.9mA
-1.208V   -111.1mA   -107.2mA   -119.1mA
-1.086V   -68.46mA   -69.78mA   -70.98mA
-991mV    -50.23mA   -49.49mA   -56.06mA
-494mV    -19.6mA    -19.99mA   -19.12mA
593.8mV   0A         -1.322mA   2.036mA
2.229V    13.98mA    18.13mA    9.084mA
2.61V     40.45mA    47.32mA    35.32mA
2.858V    66.36mA    113.7mA    60.79mA
3.017V    113.4mA    173.8mA    78.21mA
3.16V     176.1mA    232mA      110.5mA
3.514V    352.2mA    380.6mA    306.1mA
[Pullup]
-1.714V   352.2mA    305mA      416.5mA
-1.27V    135.3mA    125mA      152.2mA
-1.217V   113.4mA    106.2mA    126.2mA
-1.074V   69.38mA    63.8mA     83.22mA
-883.7mV  46.64mA    35.32mA    61.38mA
-58.9mV   1.495mA    996uA      2.108mA
2.5V      -28.79mA   -36.96mA   -20.14mA
2.669V    -39.61mA   -60.82mA   -30.53mA
2.876V    -65.73mA   -124.2mA   -47.47mA
3.04V     -124.6mA   -187.7mA   -65.25mA
3.214V    -206.3mA   -259.7mA   -132.6mA
3.515V    -358.5mA   -386.4mA   -310.8mA
[Ramp]
dV/dt_r .194/131.607p .148/120.981p .234/129.635p
dV/dt_f .194/127.656p .148/130.985p .234/125.318p
[Rising Waveform]
R_fixture = 50
V_fixture = 1.202
V_fixture_min = 1.206
V_fixture_max = 1.201
0s        1.04V      1.082V     1.006V
130ps     1.04V      1.082V     1.004V
165ps     1.045V     1.082V     1.138V
190ps     1.126V     1.082V     1.198V
210ps     1.174V     1.083V     1.237V
270ps     1.262V     1.195V     1.311V
320ps     1.303V     1.253V     1.346V
370ps     1.327V     1.287V     1.366V
465ps     1.35V      1.315V     1.384V
800ps     1.363V     1.329V     1.395V
[Falling Waveform]
R_fixture = 50
V_fixture = 1.202
V_fixture_min = 1.206
V_fixture_max = 1.201
0s        1.364V     1.329V     1.396V
135ps     1.364V     1.329V     1.402V
170ps     1.367V     1.329V     1.267V
195ps     1.284V     1.329V     1.203V
220ps     1.223V     1.333V     1.156V
280ps     1.137V     1.216V     1.084V
335ps     1.095V     1.158V     1.049V
380ps     1.075V     1.129V     1.033V
485ps     1.052V     1.098V     1.015V
800ps     1.041V     1.082V     1.006V
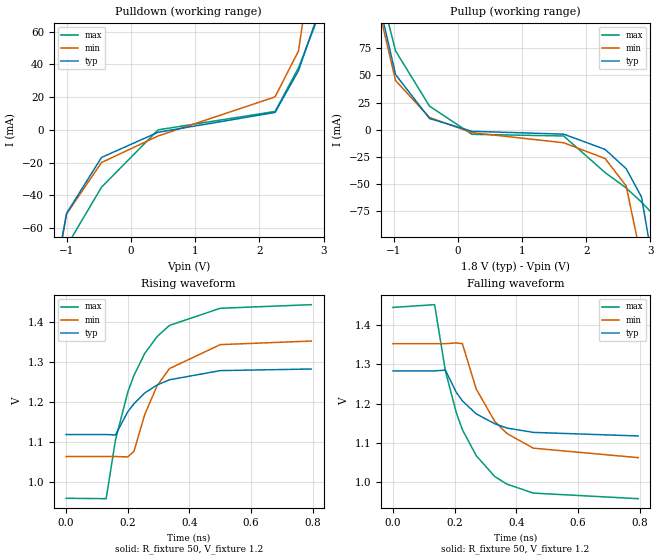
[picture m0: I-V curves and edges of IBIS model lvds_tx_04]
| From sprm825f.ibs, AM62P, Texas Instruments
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|   MODEL lvds_tx_04
[Model] lvds_tx_04
Model_type Output
C_comp 1.451p 1.565p 1.501p
Vmeas = 1.2
Vref = 1.2V
Rref = 50
Cref = 0.5pF
[Model Spec]
[Temperature Range]  40 150 -40
[Voltage Range] 1.8 1.62 1.98
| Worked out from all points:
|   slope of the pulldown table from 0 to 0.27 V, typ, clamps not added: 63.4 ohm
|   slope of the pullup table from 0 to 0.27 V, typ, clamps not added: 166 ohm
|   rising waveform, R_fixture 50, V_fixture 1.2: 20-80 % time 134ps typ, 112ps min, 129ps max; typ from 1.12 V to 1.28 V
|   falling waveform, R_fixture 50, V_fixture 1.2: 20-80 % time 131ps typ, 130ps min, 125ps max; typ from 1.28 V to 1.12 V
[Pulldown]
-1.715V   -358.4mA   -310.7mA   -423.2mA
-1.224V   -117.6mA   -112.9mA   -129.8mA
-1.102V   -72.66mA   -74.18mA   -83.74mA
-1.002V   -51.13mA   -51.47mA   -71.29mA
-457mV    -16.87mA   -19.97mA   -35.06mA
424.1mV   -1.483mA   -3.733mA   0A
2.245V    10.65mA    20.16mA    11.25mA
2.61V     36.21mA    48.28mA    37.95mA
2.869V    65.72mA    117.7mA    64.16mA
3.043V    123.3mA    184.5mA    83.42mA
3.175V    183.2mA    238.7mA    117.6mA
3.514V    352mA      380.6mA    306.2mA
[Pullup]
-1.714V   352mA      305.1mA    416.6mA
-1.233V   118.9mA    112mA      134.1mA
-968.4mV  50.79mA    45.29mA    72.53mA
-439.6mV  10.4mA     11.34mA    21.75mA
221.3mV   -1.324mA   -2.566mA   -4.109mA
1.649V    -3.96mA    -11.86mA   -5.638mA
2.294V    -17.98mA   -26.35mA   -39.25mA
2.622V    -35.7mA    -51.54mA   -53.41mA
2.86V     -61.58mA   -118.6mA   -66.39mA
3.024V    -117.6mA   -181.4mA   -76.57mA
3.177V    -188.1mA   -244.3mA   -117.3mA
3.515V    -358.4mA   -386.4mA   -311.4mA
[Ramp]
dV/dt_r .099/134.293p .173/112.546p .291/129.891p
dV/dt_f .099/131.621p .173/130.028p .291/125.304p
[Rising Waveform]
R_fixture = 50
V_fixture = 1.2
V_fixture_min = 1.207
V_fixture_max = 1.201
0s        1.118V     1.063V     958.5mV
130ps     1.118V     1.063V     957.5mV
160ps     1.117V     1.063V     1.104V
200ps     1.175V     1.062V     1.224V
220ps     1.195V     1.076V     1.266V
255ps     1.222V     1.168V     1.321V
295ps     1.242V     1.24V      1.363V
335ps     1.255V     1.283V     1.391V
500ps     1.278V     1.343V     1.434V
795ps     1.282V     1.352V     1.443V
[Falling Waveform]
R_fixture = 50
V_fixture = 1.2
V_fixture_min = 1.207
V_fixture_max = 1.201
0s        1.283V     1.352V     1.444V
135ps     1.283V     1.352V     1.451V
170ps     1.285V     1.352V     1.283V
205ps     1.229V     1.354V     1.178V
225ps     1.207V     1.352V     1.134V
270ps     1.174V     1.237V     1.068V
330ps     1.149V     1.155V     1.015V
370ps     1.138V     1.124V     995.7mV
455ps     1.127V     1.087V     973.1mV
795ps     1.118V     1.063V     958.9mV
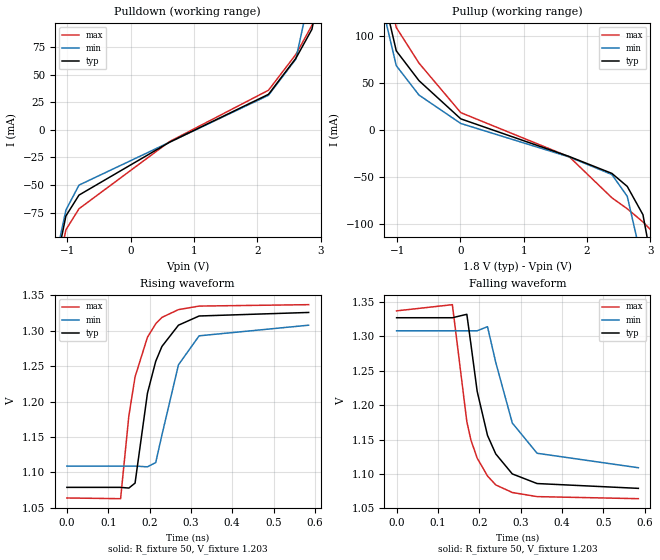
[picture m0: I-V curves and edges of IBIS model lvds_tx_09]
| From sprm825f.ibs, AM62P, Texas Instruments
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|   MODEL lvds_tx_09
[Model] lvds_tx_09
Model_type Output
C_comp 1.628p 1.69p 1.537p
Vmeas = 1.2
Vref = 1.2V
Rref = 50
Cref = 0.5pF
[Model Spec]
[Temperature Range]  40 150 -40
[Voltage Range] 1.8 1.62 1.98
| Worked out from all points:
|   slope of the pulldown table from 0 to 0.27 V, typ, clamps not added: 36.5 ohm
|   slope of the pullup table from 0 to 0.27 V, typ, clamps not added: 27.8 ohm
|   rising waveform, R_fixture 50, V_fixture 1.203: 20-80 % time 54.6ps typ, 54.4ps min, 48.6ps max; typ from 1.08 V to 1.33 V
|   falling waveform, R_fixture 50, V_fixture 1.203: 20-80 % time 58.1ps typ, 66.8ps min, 51.3ps max; typ from 1.33 V to 1.08 V
[Pulldown]
-1.71V    -379mA     -326.6mA   -450.1mA
-1.23V    -143.3mA   -132.3mA   -160.8mA
-1.166V   -117.7mA   -110.7mA   -129.9mA
-1.024V   -77.96mA   -72.64mA   -90.49mA
-817.8mV  -59.09mA   -50.07mA   -71.48mA
612.7mV   -11.2mA    -11.22mA   -10.62mA
2.175V    32.15mA    31.29mA    35.87mA
2.608V    64.85mA    64.16mA    68.3mA
2.861V    91.04mA    131.2mA    94.66mA
3.015V    135.4mA    189.3mA    111.2mA
3.136V    187.7mA    238.7mA    134mA
3.511V    373.5mA    396.2mA    335.1mA
[Pullup]
-1.711V   373.5mA    320.4mA    445.6mA
-1.273V   159.3mA    142.4mA    184.6mA
-1.014V   84.07mA    68.3mA     108.9mA
-655mV    52.31mA    36.98mA    70.99mA
4.836mV   11.68mA    6.78mA     18.29mA
1.72V     -28.45mA   -28.95mA   -28.75mA
2.391V    -46.34mA   -47.56mA   -72.28mA
2.634V    -60.21mA   -70.74mA   -83.98mA
2.882V    -90.32mA   -144mA     -98mA
3.04V     -147.9mA   -205.7mA   -108.9mA
3.172V    -209mA     -260.1mA   -145.6mA
3.51V     -379mA     -402.8mA   -338.6mA
[Ramp]
dV/dt_r .149/54.893p .119/54.385p .164/48.814p
dV/dt_f .149/58.222p .119/67.512p .164/50.861p
[Rising Waveform]
R_fixture = 50
V_fixture = 1.203
V_fixture_min = 1.208
V_fixture_max = 1.201
0s        1.079V     1.109V     1.064V
130ps     1.079V     1.109V     1.063V
150ps     1.078V     1.109V     1.18V
165ps     1.085V     1.109V     1.235V
195ps     1.212V     1.108V     1.291V
215ps     1.257V     1.114V     1.31V
230ps     1.278V     1.153V     1.319V
270ps     1.308V     1.252V     1.33V
320ps     1.321V     1.293V     1.335V
585ps     1.326V     1.308V     1.337V
[Falling Waveform]
R_fixture = 50
V_fixture = 1.203
V_fixture_min = 1.208
V_fixture_max = 1.201
0s        1.327V     1.308V     1.337V
135ps     1.327V     1.308V     1.346V
170ps     1.332V     1.308V     1.176V
180ps     1.288V     1.308V     1.149V
195ps     1.22V      1.308V     1.123V
220ps     1.156V     1.314V     1.097V
240ps     1.129V     1.262V     1.084V
280ps     1.1V       1.174V     1.073V
340ps     1.086V     1.13V      1.067V
585ps     1.079V     1.109V     1.064V
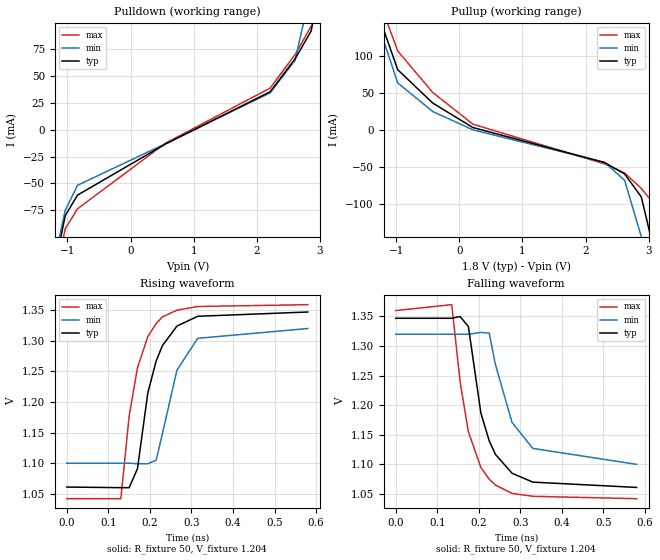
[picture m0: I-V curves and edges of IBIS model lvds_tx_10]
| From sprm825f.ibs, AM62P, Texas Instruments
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|   MODEL lvds_tx_10
[Model] lvds_tx_10
Model_type Output
C_comp 1.648p 1.708p 1.549p
Vmeas = 1.2
Vref = 1.2V
Rref = 50
Cref = 0.5pF
[Model Spec]
[Temperature Range]  40 150 -40
[Voltage Range] 1.8 1.62 1.98
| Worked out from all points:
|   slope of the pulldown table from 0 to 0.27 V, typ, clamps not added: 34.5 ohm
|   slope of the pullup table from 0 to 0.27 V, typ, clamps not added: 25.8 ohm
|   rising waveform, R_fixture 50, V_fixture 1.204: 20-80 % time 53.9ps typ, 51.3ps min, 48.6ps max; typ from 1.06 V to 1.35 V
|   falling waveform, R_fixture 50, V_fixture 1.204: 20-80 % time 57.3ps typ, 65.9ps min, 50.5ps max; typ from 1.35 V to 1.06 V
[Pulldown]
-1.71V    -379.1mA   -326.7mA   -450.1mA
-1.23V    -143.4mA   -132.4mA   -160.8mA
-1.166V   -117.8mA   -110.8mA   -130mA
-1.034V   -80mA      -74.97mA   -92.13mA
-839mV    -60.87mA   -51.69mA   -73.64mA
554.6mV   -13.23mA   -12.91mA   -12.44mA
2.212V    35.51mA    34.48mA    38.92mA
2.608V    66.35mA    64.92mA    70.29mA
2.861V    92.11mA    131.4mA    96.58mA
3.015V    135.7mA    189.4mA    112.8mA
3.131V    185.5mA    236.6mA    133.3mA
3.511V    373.6mA    396.2mA    335.2mA
[Pullup]
-1.711V   373.6mA    320.4mA    445.7mA
-1.283V   164.1mA    146.5mA    190.4mA
-1.236V   144.1mA    129.4mA    166.6mA
-977mV    81.27mA    63.36mA    106.6mA
-422.7mV  36.22mA    24.82mA    50.52mA
214.8mV   3.095mA    0A         7.657mA
2.301V    -44.13mA   -43.98mA   -45.95mA
2.618V    -59.54mA   -68.14mA   -58.23mA
2.882V    -90.49mA   -144.1mA   -79.11mA
3.03V     -143.4mA   -201.5mA   -94.51mA
3.188V    -216.7mA   -266.8mA   -149.8mA
3.51V     -379.1mA   -402.8mA   -338.1mA
[Ramp]
dV/dt_r .172/54.136p .132/51.202p .191/48.829p
dV/dt_f .172/57.355p .132/66.489p .191/50.394p
[Rising Waveform]
R_fixture = 50
V_fixture = 1.204
V_fixture_min = 1.21
V_fixture_max = 1.201
0s        1.061V     1.1V       1.042V
130ps     1.06V      1.1V       1.042V
150ps     1.06V      1.1V       1.177V
170ps     1.091V     1.099V     1.256V
195ps     1.215V     1.099V     1.307V
215ps     1.267V     1.105V     1.328V
230ps     1.292V     1.148V     1.339V
265ps     1.324V     1.252V     1.35V
315ps     1.34V      1.304V     1.356V
580ps     1.347V     1.32V      1.359V
[Falling Waveform]
R_fixture = 50
V_fixture = 1.204
V_fixture_min = 1.21
V_fixture_max = 1.201
0s        1.347V     1.32V      1.36V
135ps     1.347V     1.32V      1.37V
155ps     1.35V      1.32V      1.24V
175ps     1.333V     1.32V      1.155V
205ps     1.187V     1.323V     1.095V
225ps     1.14V      1.322V     1.075V
240ps     1.117V     1.269V     1.065V
280ps     1.085V     1.171V     1.051V
330ps     1.07V      1.127V     1.046V
580ps     1.061V     1.1V       1.042V
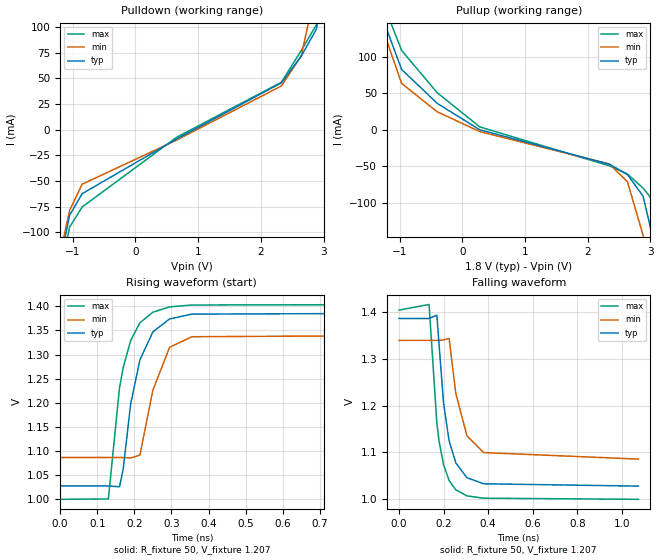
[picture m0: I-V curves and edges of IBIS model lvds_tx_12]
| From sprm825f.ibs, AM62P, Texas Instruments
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|   MODEL lvds_tx_12
[Model] lvds_tx_12
Model_type Output
C_comp 1.675p 1.735p 1.553p
Vmeas = 1.2
Vref = 1.2V
Rref = 50
Cref = 0.5pF
[Model Spec]
[Temperature Range]  40 150 -40
[Voltage Range] 1.8 1.62 1.98
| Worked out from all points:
|   slope of the pulldown table from 0 to 0.27 V, typ, clamps not added: 29.9 ohm
|   slope of the pullup table from 0 to 0.27 V, typ, clamps not added: 23 ohm
|   rising waveform, R_fixture 50, V_fixture 1.207: 20-80 % time 51.9ps typ, 45.7ps min, 48ps max; typ from 1.03 V to 1.39 V
|   falling waveform, R_fixture 50, V_fixture 1.207: 20-80 % time 56.2ps typ, 65.2ps min, 49.2ps max; typ from 1.39 V to 1.03 V
[Pulldown]
-1.71V    -379.2mA   -326.8mA   -450.1mA
-1.245V   -150.4mA   -138.2mA   -169.4mA
-1.182V   -124.1mA   -116.2mA   -137.4mA
-1.05V    -83.49mA   -78.75mA   -94.99mA
-849.5mV  -62.34mA   -53.08mA   -75.33mA
654.9mV   -9.088mA   -10.17mA   -7.434mA
2.328V    45.74mA    42.72mA    46.34mA
2.645V    71.85mA    72.05mA    77.26mA
2.883V    97.66mA    139.3mA    102mA
3.03V     142.5mA    195.9mA    117.5mA
3.152V    195.5mA    245.5mA    141.4mA
3.511V    373.6mA    396.2mA    335.3mA
[Pullup]
-1.711V   373.6mA    320.5mA    445.7mA
-1.299V   171.5mA    152.7mA    199.3mA
-1.236V   144.6mA    129.7mA    167.3mA
-966.5mV  82.48mA    63.34mA    108.5mA
-401.6mV  36.25mA    24.66mA    50.83mA
276.8mV   0A         -2.455mA   3.96mA
2.349V    -47.38mA   -47.02mA   -49.52mA
2.634V    -61.39mA   -71.35mA   -60.68mA
2.882V    -90.86mA   -144.2mA   -79.85mA
3.04V     -148.1mA   -205.9mA   -96.81mA
3.172V    -209.2mA   -260.3mA   -142.2mA
3.51V     -379.2mA   -402.9mA   -338.1mA
[Ramp]
dV/dt_r .216/52.175p .153/45.837p .244/48.324p
dV/dt_f .216/56.124p .153/64.83p .244/49.184p
[Rising Waveform]
R_fixture = 50
V_fixture = 1.207
V_fixture_min = 1.213
V_fixture_max = 1.202
0s        1.027V     1.086V     999mV
130ps     1.027V     1.086V     999.8mV
160ps     1.025V     1.086V     1.231V
170ps     1.062V     1.086V     1.273V
190ps     1.197V     1.085V     1.329V
215ps     1.289V     1.091V     1.366V
250ps     1.347V     1.226V     1.388V
295ps     1.374V     1.315V     1.399V
355ps     1.384V     1.337V     1.403V
1.075ns   1.386V     1.34V      1.404V
[Falling Waveform]
R_fixture = 50
V_fixture = 1.207
V_fixture_min = 1.213
V_fixture_max = 1.202
0s        1.387V     1.34V      1.405V
135ps     1.387V     1.34V      1.417V
170ps     1.394V     1.34V      1.162V
180ps     1.33V      1.34V      1.123V
200ps     1.205V     1.341V     1.073V
225ps     1.124V     1.344V     1.039V
255ps     1.077V     1.226V     1.019V
305ps     1.045V     1.135V     1.006V
380ps     1.032V     1.099V     1.001V
1.075ns   1.027V     1.085V     998.6mV
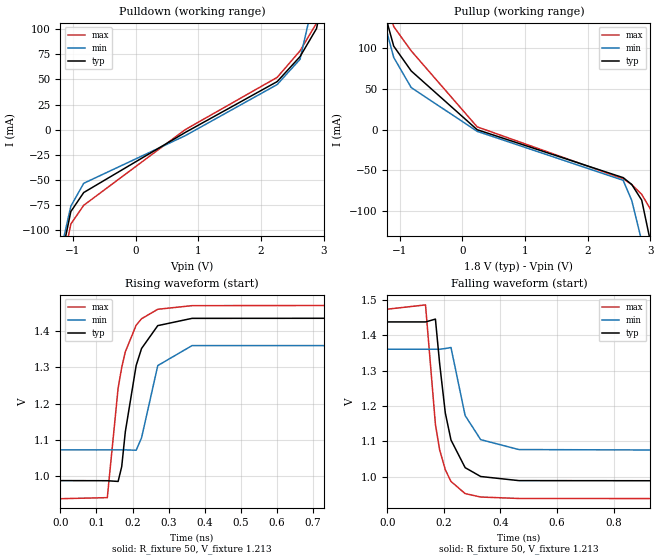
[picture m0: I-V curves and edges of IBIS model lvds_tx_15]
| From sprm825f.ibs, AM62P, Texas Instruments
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|   MODEL lvds_tx_15
[Model] lvds_tx_15
Model_type Output
C_comp 1.687p 1.755p 1.517p
Vmeas = 1.2
Vref = 1.2V
Rref = 50
Cref = 0.5pF
[Model Spec]
[Temperature Range]  40 150 -40
[Voltage Range] 1.8 1.62 1.98
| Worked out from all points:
|   slope of the pulldown table from 0 to 0.27 V, typ, clamps not added: 23.7 ohm
|   slope of the pullup table from 0 to 0.27 V, typ, clamps not added: 20.7 ohm
|   rising waveform, R_fixture 50, V_fixture 1.213: 20-80 % time 47.6ps typ, 39.3ps min, 47.4ps max; typ from 0.988 V to 1.44 V
|   falling waveform, R_fixture 50, V_fixture 1.213: 20-80 % time 54ps typ, 61.8ps min, 47.6ps max; typ from 1.44 V to 0.988 V
[Pulldown]
-1.71V    -379.4mA   -326.9mA   -450.3mA
-1.245V   -150.7mA   -138.4mA   -169.6mA
-1.193V   -128.6mA   -120mA     -142.7mA
-1.034V   -81.2mA    -75.89mA   -93.56mA
-828.4mV  -62.35mA   -53.17mA   -75.01mA
790.5mV   -2.794mA   -5.986mA   0A
2.26V     47.76mA    44.81mA    51.95mA
2.624V    72.49mA    69.88mA    78.23mA
2.888V    100.4mA    141.5mA    105.8mA
3.03V     143.1mA    196.1mA    120.4mA
3.141V    190.9mA    241.2mA    139.8mA
3.511V    373.6mA    396.2mA    335.4mA
[Pullup]
-1.711V   373.6mA    320.5mA    445.7mA
-1.299V   171.9mA    153mA      199.8mA
-1.188V   127.5mA    114.3mA    148.5mA
-1.098V   102.5mA    88.65mA    126.5mA
-818.6mV  72.05mA    51.67mA    96.69mA
233.8mV   0A         -2.002mA   3.498mA
2.565V    -58.8mA    -62.08mA   -60.17mA
2.702V    -67.25mA   -86.95mA   -67.34mA
2.861V    -86.46mA   -136.7mA   -79.35mA
3.088V    -169.6mA   -225.4mA   -108.8mA
3.246V    -245.6mA   -291.5mA   -180.8mA
3.51V     -379.4mA   -403mA     -338.3mA
[Ramp]
dV/dt_r .269/47.841p .172/39.179p .321/47.656p
dV/dt_f .269/53.895p .172/61.599p .321/47.654p
[Rising Waveform]
R_fixture = 50
V_fixture = 1.213
V_fixture_min = 1.216
V_fixture_max = 1.206
0s        988.4mV    1.073V     938.6mV
130ps     988.1mV    1.073V     941.5mV
160ps     986.1mV    1.073V     1.243V
170ps     1.027V     1.073V     1.3V
180ps     1.123V     1.073V     1.343V
210ps     1.305V     1.072V     1.416V
225ps     1.352V     1.106V     1.434V
270ps     1.415V     1.305V     1.46V
365ps     1.435V     1.36V      1.47V
2.035ns   1.436V     1.36V      1.472V
[Falling Waveform]
R_fixture = 50
V_fixture = 1.213
V_fixture_min = 1.216
V_fixture_max = 1.206
0s        1.437V     1.36V      1.473V
135ps     1.437V     1.36V      1.485V
170ps     1.445V     1.36V      1.148V
185ps     1.319V     1.36V      1.076V
205ps     1.18V      1.362V     1.02V
225ps     1.104V     1.365V     987.1mV
275ps     1.026V     1.173V     952.8mV
330ps     1.001V     1.105V     943.1mV
465ps     989.4mV    1.077V     939mV
2.035ns   988.3mV    1.073V     938.4mV
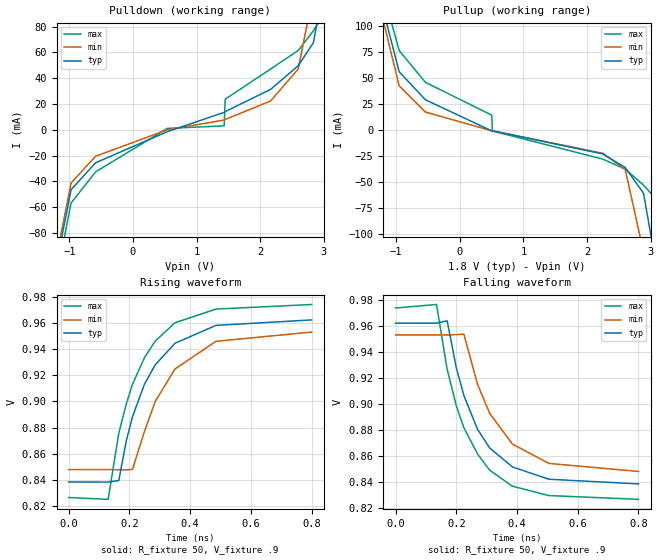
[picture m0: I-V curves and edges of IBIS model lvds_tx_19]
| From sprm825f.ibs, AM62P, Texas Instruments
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|   MODEL lvds_tx_19
[Model] lvds_tx_19
Model_type Output
C_comp 1.37p 957.063f 1.384p
Vmeas = 1.2
Vref = 1.2V
Rref = 50
Cref = 0.5pF
[Model Spec]
[Temperature Range]  40 150 -40
[Voltage Range] 1.8 1.62 1.98
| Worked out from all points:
|   slope of the pulldown table from 0 to 0.27 V, typ, clamps not added: 62.2 ohm
|   slope of the pullup table from 0 to 0.27 V, typ, clamps not added: 48.5 ohm
|   rising waveform, R_fixture 50, V_fixture .9: 20-80 % time 136ps typ, 143ps min, 131ps max; typ from 0.838 V to 0.962 V
|   falling waveform, R_fixture 50, V_fixture .9: 20-80 % time 131ps typ, 136ps min, 130ps max; typ from 0.962 V to 0.838 V
[Pulldown]
-1.717V   -348.6mA   -301.7mA   -413.4mA
-1.236V   -112.9mA   -107.5mA   -123.8mA
-971.5mV  -46.5mA    -41.34mA   -56.8mA
-585.4mV  -25.61mA   -20.54mA   -32.64mA
541.2mV   -1.495mA   -34.87uA   1.029mA
1.435V    13.49mA    7.531mA    3.018mA
1.451V    14.1mA     7.965mA    23.72mA
2.165V    31.29mA    22.32mA    47.09mA
2.599V    49.68mA    47.11mA    61.47mA
2.837V    67.46mA    106.1mA    76.75mA
3.027V    119mA      177.8mA    91.08mA
3.514V    352.7mA    380.6mA    307.4mA
[Pullup]
-1.714V   352.6mA    304.9mA    417.3mA
-1.243V   124.8mA    115.4mA    140.8mA
-952.2mV  55.78mA    42.27mA    76.27mA
-539.6mV  28.84mA    17.01mA    45.6mA
502.4mV   -1.081mA   -983.5uA   14.03mA
513mV     -1.086mA   -988.6uA   -1.204mA
2.248V    -23.28mA   -22.66mA   -28.23mA
2.602V    -36.4mA    -38.29mA   -37.91mA
2.888V    -61.1mA    -117.9mA   -53.26mA
3.036V    -112.3mA   -175.6mA   -63.2mA
3.205V    -190.7mA   -245.6mA   -118mA
3.517V    -348.5mA   -377.8mA   -301mA
[Ramp]
dV/dt_r .075/135.842p .063/143.768p .089/131.625p
dV/dt_f .075/132.017p .063/137.566p .089/130.724p
[Rising Waveform]
R_fixture = 50
V_fixture = .9
V_fixture_min = .901
V_fixture_max = .9
0s        838.3mV    847.8mV    826.4mV
130ps     838.2mV    847.8mV    825mV
165ps     839.4mV    847.7mV    875.5mV
190ps     870.1mV    847.6mV    898.3mV
210ps     888.1mV    847.9mV    913mV
250ps     913.4mV    877.3mV    933.7mV
285ps     928mV      899.9mV    946.2mV
350ps     944.5mV    924.8mV    960.2mV
485ps     958.2mV    946mV      970.7mV
800ps     962.4mV    953.1mV    974.2mV
[Falling Waveform]
R_fixture = 50
V_fixture = .9
V_fixture_min = .901
V_fixture_max = .9
0s        962.5mV    953.4mV    974.2mV
135ps     962.5mV    953.4mV    976.9mV
170ps     964.3mV    953.4mV    926.8mV
200ps     928.2mV    953.7mV    898.8mV
225ps     906.7mV    954mV      881.8mV
270ps     880.6mV    915.4mV    861.6mV
310ps     866.2mV    892.9mV    849.1mV
385ps     851.6mV    869.2mV    836.7mV
505ps     842.1mV    854.3mV    829.5mV
800ps     838.5mV    848.1mV    826.6mV
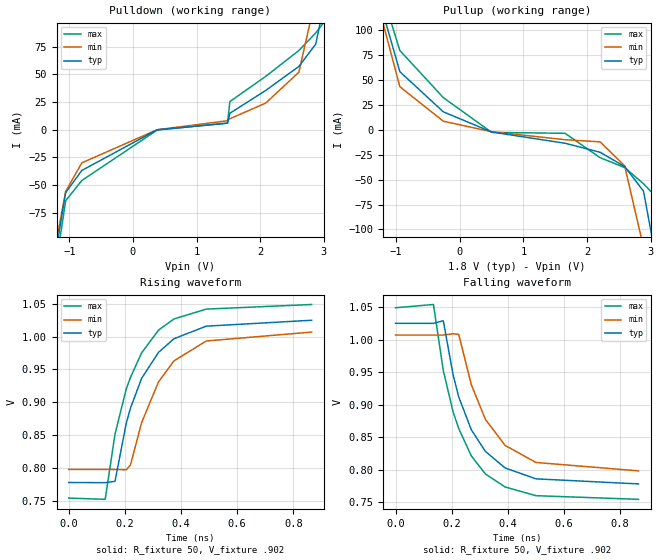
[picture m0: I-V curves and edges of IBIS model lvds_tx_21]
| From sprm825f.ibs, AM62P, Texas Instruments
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|   MODEL lvds_tx_21
[Model] lvds_tx_21
Model_type Output
C_comp 1.359p 870.682f 1.446p
Vmeas = 1.2
Vref = 1.2V
Rref = 50
Cref = 0.5pF
[Model Spec]
[Temperature Range]  40 150 -40
[Voltage Range] 1.8 1.62 1.98
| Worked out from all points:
|   slope of the pulldown table from 0 to 0.27 V, typ, clamps not added: 51.3 ohm
|   slope of the pullup table from 0 to 0.27 V, typ, clamps not added: 32.7 ohm
|   rising waveform, R_fixture 50, V_fixture .902: 20-80 % time 135ps typ, 140ps min, 130ps max; typ from 0.778 V to 1.02 V
|   falling waveform, R_fixture 50, V_fixture .902: 20-80 % time 130ps typ, 135ps min, 127ps max; typ from 1.02 V to 0.778 V
[Pulldown]
-1.717V   -348.6mA   -301.8mA   -413.4mA
-1.289V   -136.1mA   -126.8mA   -152.2mA
-1.056V   -56.69mA   -55.61mA   -64.05mA
-802.3mV  -36.7mA    -29.87mA   -45.77mA
381.1mV   -34.76uA   0A         -294uA
1.488V    5.851mA    8.145mA    6.107mA
1.525V    14.85mA    9.923mA    25.44mA
2.086V    35.34mA    23.97mA    48.04mA
2.609V    57.1mA     51.88mA    71.49mA
2.874V    77.24mA    119.2mA    87.31mA
3.017V    116.2mA    173.8mA    97.96mA
3.514V    352.8mA    380.7mA    307.8mA
[Pullup]
-1.714V   352.7mA    305.2mA    417.4mA
-1.243V   125.5mA    115.9mA    141.7mA
-941.6mV  58.25mA    43.18mA    79.51mA
-259.3mV  18.01mA    8.561mA    32.3mA
502.4mV   -2.317mA   -2.03mA    -2.671mA
1.655V    -13.55mA   -9.993mA   -3.573mA
2.206V    -22.6mA    -12.16mA   -28.04mA
2.592V    -36.92mA   -36.21mA   -37.94mA
2.888V    -61.59mA   -117.9mA   -54.14mA
3.036V    -112.5mA   -175.6mA   -64.12mA
3.189V    -183mA     -239mA     -110.4mA
3.517V    -348.5mA   -377.8mA   -301mA
[Ramp]
dV/dt_r .149/135.149p .126/140.233p .177/130.52p
dV/dt_f .149/130.541p .126/135.554p .177/127.551p
[Rising Waveform]
R_fixture = 50
V_fixture = .902
V_fixture_min = .903
V_fixture_max = .902
0s        777.8mV    797.8mV    754.1mV
130ps     777.6mV    797.8mV    752.2mV
165ps     779.6mV    797.6mV    851.5mV
205ps     868.1mV    797.2mV    920.3mV
220ps     891.1mV    804.5mV    937.9mV
260ps     936.7mV    869.4mV    975.6mV
320ps     976.1mV    931.2mV    1.01V
375ps     996.9mV    963.2mV    1.027V
490ps     1.016V     993.4mV    1.042V
865ps     1.025V     1.007V     1.049V
[Falling Waveform]
R_fixture = 50
V_fixture = .902
V_fixture_min = .903
V_fixture_max = .902
0s        1.025V     1.007V     1.049V
135ps     1.025V     1.007V     1.054V
170ps     1.029V     1.007V     952.5mV
205ps     945.6mV    1.009V     888.7mV
225ps     911.7mV    1.008V     863.2mV
270ps     861.1mV    930.4mV    820.9mV
320ps     828mV      877.2mV    793.3mV
390ps     802.6mV    837.3mV    773.3mV
500ps     785.8mV    811mV      759.9mV
865ps     778mV      798.1mV    754.3mV
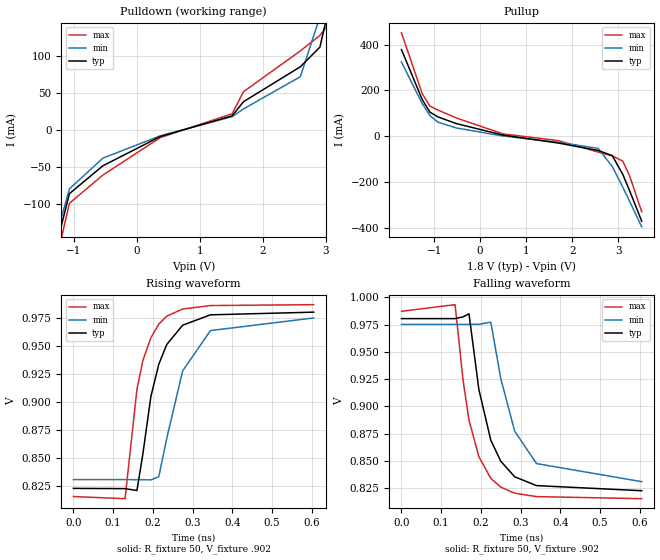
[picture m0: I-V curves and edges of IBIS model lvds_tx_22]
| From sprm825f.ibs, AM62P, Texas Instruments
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|   MODEL lvds_tx_22
[Model] lvds_tx_22
Model_type Output
C_comp 1.397p 957.413f 1.487p
Vmeas = 1.2
Vref = 1.2V
Rref = 50
Cref = 0.5pF
[Model Spec]
[Temperature Range]  40 150 -40
[Voltage Range] 1.8 1.62 1.98
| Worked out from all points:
|   slope of the pulldown table from 0 to 0.27 V, typ, clamps not added: 24.7 ohm
|   slope of the pullup table from 0 to 0.27 V, typ, clamps not added: 18.6 ohm
|   rising waveform, R_fixture 50, V_fixture .902: 20-80 % time 56.8ps typ, 68ps min, 49ps max; typ from 0.822 V to 0.98 V
|   falling waveform, R_fixture 50, V_fixture .902: 20-80 % time 59.4ps typ, 69.3ps min, 52.2ps max; typ from 0.98 V to 0.823 V
[Pulldown]
-1.712V   -371.8mA   -320.2mA   -442mA
-1.258V   -148.6mA   -136mA     -167.9mA
-1.073V   -86.14mA   -79.75mA   -99.11mA
-539.5mV  -48.43mA   -38.11mA   -60.95mA
373.8mV   -8.936mA   -8.016mA   -10.34mA
1.514V    18.88mA    17.84mA    21.73mA
1.694V    37.99mA    28.23mA    51.46mA
2.597V    85.08mA    71.73mA    106.5mA
2.908V    111.6mA    152.6mA    127.4mA
3.151V    201.3mA    249.5mA    154.7mA
3.288V    267.4mA    307mA      213.2mA
3.51V     379mA      400.4mA    342.3mA
[Pullup]
-1.71V    378.9mA    324.7mA    452mA
-1.261V   160.9mA    143.2mA    187mA
-1.092V   105.3mA    90.19mA    131.8mA
-918mV    84.6mA     61.59mA    114.5mA
-522mV    55.48mA    36.4mA     80.2mA
497mV     4.94mA     1.096mA    10.24mA
1.706V    -29.97mA   -26.96mA   -19.55mA
2.567V    -62.31mA   -53.19mA   -69.2mA
2.873V    -84.96mA   -132.9mA   -86.45mA
3.1V      -167mA     -222.4mA   -108.7mA
3.248V    -238mA     -284.3mA   -173.2mA
3.512V    -371.7mA   -396.1mA   -329.9mA
[Ramp]
dV/dt_r .095/57p .087/68.248p .103/49.212p
dV/dt_f .095/59.687p .087/69.942p .103/52.282p
[Rising Waveform]
R_fixture = 50
V_fixture = .902
V_fixture_min = .903
V_fixture_max = .901
0s        822.5mV    830.4mV    815.2mV
130ps     822.3mV    830.4mV    813.3mV
160ps     820.6mV    830.3mV    911.3mV
175ps     853.6mV    830.3mV    937.1mV
195ps     904.6mV    830.1mV    957.2mV
215ps     933.6mV    833mV      969.5mV
235ps     951.2mV    867.2mV    976.6mV
275ps     968.5mV    927.6mV    983mV
345ps     977.8mV    963.7mV    986.1mV
605ps     980.2mV    975mV      986.9mV
[Falling Waveform]
R_fixture = 50
V_fixture = .902
V_fixture_min = .903
V_fixture_max = .901
0s        980.5mV    975.2mV    987.2mV
135ps     980.5mV    975.2mV    993.3mV
155ps     982.1mV    975.2mV    924.2mV
170ps     984.9mV    975.2mV    887.3mV
195ps     915.3mV    975.3mV    853.8mV
225ps     868.9mV    977.2mV    833.9mV
250ps     849.7mV    925.6mV    825.9mV
285ps     835.4mV    877.3mV    820.3mV
340ps     827.3mV    847.5mV    817.2mV
605ps     822.6mV    830.9mV    815.3mV
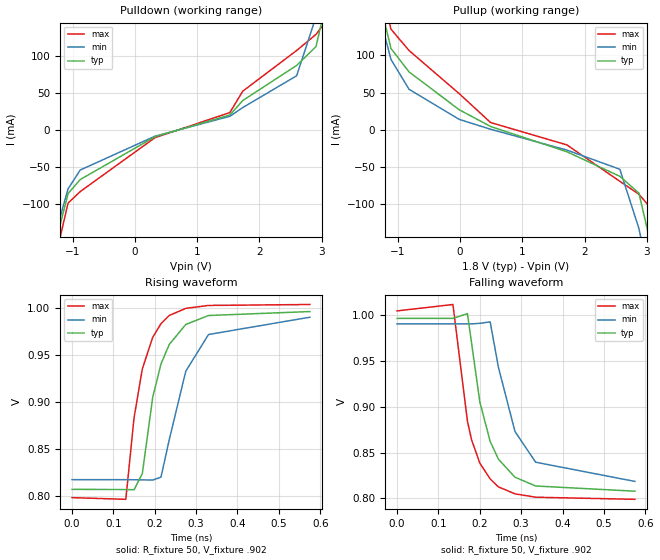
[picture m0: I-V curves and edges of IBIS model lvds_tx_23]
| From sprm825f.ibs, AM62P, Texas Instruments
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|   MODEL lvds_tx_23
[Model] lvds_tx_23
Model_type Output
C_comp 1.384p 1.062p 1.505p
Vmeas = 1.2
Vref = 1.2V
Rref = 50
Cref = 0.5pF
[Model Spec]
[Temperature Range]  40 150 -40
[Voltage Range] 1.8 1.62 1.98
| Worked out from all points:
|   slope of the pulldown table from 0 to 0.27 V, typ, clamps not added: 23.7 ohm
|   slope of the pullup table from 0 to 0.27 V, typ, clamps not added: 17.8 ohm
|   rising waveform, R_fixture 50, V_fixture .902: 20-80 % time 56ps typ, 68.3ps min, 49ps max; typ from 0.807 V to 0.996 V
|   falling waveform, R_fixture 50, V_fixture .902: 20-80 % time 58.9ps typ, 68.2ps min, 51.4ps max; typ from 0.997 V to 0.808 V
[Pulldown]
-1.712V   -371.8mA   -320.2mA   -442mA
-1.247V   -144.1mA   -132.3mA   -162.3mA
-1.073V   -86.21mA   -79.86mA   -99.15mA
-877.4mV  -67.26mA   -54.41mA   -83.52mA
321mV     -9.521mA   -8.793mA   -10.81mA
1.525V    19.94mA    18.19mA    23.2mA
1.731V    39.41mA    29.96mA    52.05mA
2.597V    86.92mA    72.93mA    107.1mA
2.908V    112.4mA    152.8mA    128.9mA
3.151V    201.4mA    249.6mA    155.7mA
3.288V    267.5mA    307.1mA    213.5mA
3.51V     379.1mA    400.4mA    342.4mA
[Pullup]
-1.71V    378.9mA    324.7mA    452mA
-1.282V   170.1mA    150.6mA    198mA
-1.108V   109.5mA    94.67mA    135.4mA
-817.7mV  77.87mA    54.48mA    106.7mA
-9.887mV  26.81mA    13.86mA    48.41mA
491.7mV   4.421mA    652.2uA    9.707mA
1.717V    -29.66mA   -27.38mA   -20.42mA
2.567V    -62.7mA    -53.2mA    -69.45mA
2.873V    -85.31mA   -132.9mA   -86.77mA
3.1V      -167.1mA   -222.4mA   -109mA
3.227V    -227.6mA   -275.4mA   -162.1mA
3.512V    -371.7mA   -396.1mA   -330mA
[Ramp]
dV/dt_r .114/55.952p .104/68.553p .124/49.283p
dV/dt_f .114/59.147p .104/68.955p .124/51.267p
[Rising Waveform]
R_fixture = 50
V_fixture = .902
V_fixture_min = .904
V_fixture_max = .902
0s        807.5mV    817.8mV    798.7mV
130ps     807.3mV    817.8mV    796.9mV
150ps     807.1mV    817.7mV    883.9mV
170ps     824.4mV    817.6mV    935.6mV
195ps     905.2mV    817.4mV    969.1mV
215ps     940.7mV    820.4mV    983.6mV
235ps     961.5mV    860.2mV    992.3mV
275ps     982.8mV    933.1mV    999.9mV
330ps     992.3mV    972.1mV    1.003V
575ps     996.5mV    990.5mV    1.004V
[Falling Waveform]
R_fixture = 50
V_fixture = .902
V_fixture_min = .904
V_fixture_max = .902
0s        996.8mV    990.8mV    1.005V
135ps     996.8mV    990.8mV    1.012V
170ps     1.002V     990.8mV    884.4mV
180ps     970mV      990.8mV    864mV
200ps     905.3mV    991.4mV    838.4mV
225ps     862.2mV    993mV      821.1mV
245ps     842.7mV    943.2mV    812.4mV
285ps     823mV      873mV      804.8mV
335ps     813.4mV    839.4mV    801.1mV
575ps     807.7mV    818.4mV    798.8mV
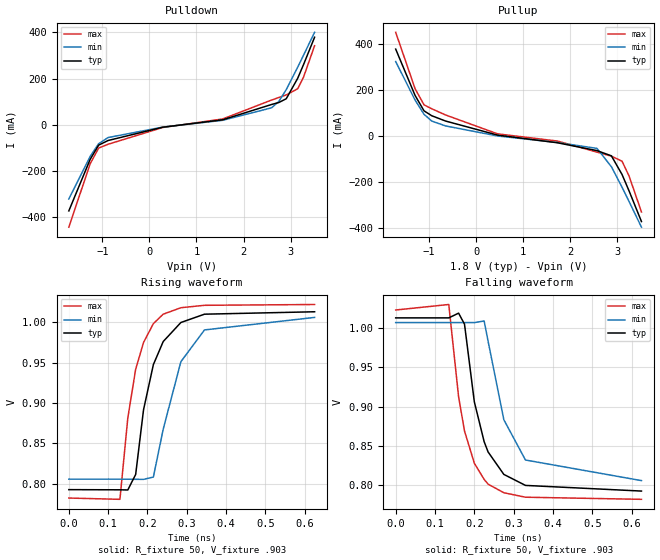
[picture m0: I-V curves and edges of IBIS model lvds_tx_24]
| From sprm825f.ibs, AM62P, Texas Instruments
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|   MODEL lvds_tx_24
[Model] lvds_tx_24
Model_type Output
C_comp 1.368p 1.154p 1.518p
Vmeas = 1.2
Vref = 1.2V
Rref = 50
Cref = 0.5pF
[Model Spec]
[Temperature Range]  40 150 -40
[Voltage Range] 1.8 1.62 1.98
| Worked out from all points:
|   slope of the pulldown table from 0 to 0.27 V, typ, clamps not added: 22.9 ohm
|   slope of the pullup table from 0 to 0.27 V, typ, clamps not added: 17.6 ohm
|   rising waveform, R_fixture 50, V_fixture .903: 20-80 % time 56.1ps typ, 68.1ps min, 49.4ps max; typ from 0.793 V to 1.01 V
|   falling waveform, R_fixture 50, V_fixture .903: 20-80 % time 57.8ps typ, 67.5ps min, 50.8ps max; typ from 1.01 V to 0.793 V
[Pulldown]
-1.712V   -371.8mA   -320.2mA   -442mA
-1.258V   -148.7mA   -136.2mA   -167.9mA
-1.078V   -87.36mA   -81.17mA   -99.98mA
-877.4mV  -67.32mA   -54.54mA   -83.54mA
284.1mV   -9.866mA   -9.333mA   -11.06mA
1.556V    22.09mA    19.95mA    25.69mA
2.597V    88.44mA    74.03mA    107.6mA
2.75V     96.94mA    101.5mA    118.5mA
2.908V    113.2mA    152.9mA    129.8mA
3.151V    201.6mA    249.6mA    156.4mA
3.278V    262.3mA    302.7mA    208.2mA
3.51V     379.1mA    400.4mA    342.4mA
[Pullup]
-1.71V    379mA      324.8mA    452mA
-1.298V   177.2mA    157.1mA    206.5mA
-1.108V   110.2mA    95.02mA    136.3mA
-944.4mV  88.87mA    65.7mA     119.2mA
-648.7mV  65.67mA    44.42mA    92.09mA
454.7mV   4.556mA    774.6uA    10.03mA
1.727V    -28.84mA   -27.79mA   -21.37mA
2.567V    -63.06mA   -53.28mA   -69.65mA
2.873V    -85.66mA   -133mA     -87.04mA
3.1V      -167.2mA   -222.5mA   -109.3mA
3.248V    -238.1mA   -284.3mA   -173.4mA
3.512V    -371.8mA   -396.2mA   -330mA
[Ramp]
dV/dt_r .132/56.517p .121/68.368p .144/49.706p
dV/dt_f .132/57.939p .121/67.866p .144/50.873p
[Rising Waveform]
R_fixture = 50
V_fixture = .903
V_fixture_min = .906
V_fixture_max = .903
0s        792.7mV    805.7mV    782.3mV
130ps     792.5mV    805.7mV    780.7mV
150ps     792.3mV    805.6mV    881.4mV
170ps     811.5mV    805.5mV    941.8mV
190ps     891.6mV    805.4mV    974.9mV
215ps     947.5mV    808.3mV    998.3mV
240ps     976.1mV    867.5mV    1.01V
285ps     999.7mV    951.2mV    1.018V
345ps     1.01V      990.5mV    1.021V
625ps     1.013V     1.006V     1.022V
[Falling Waveform]
R_fixture = 50
V_fixture = .903
V_fixture_min = .906
V_fixture_max = .903
0s        1.013V     1.007V     1.023V
135ps     1.013V     1.007V     1.03V
160ps     1.019V     1.007V     912.5mV
175ps     1.005V     1.007V     869.2mV
200ps     906.2mV    1.007V     828.2mV
225ps     855.5mV    1.009V     807.6mV
235ps     842.5mV    983.2mV    801.6mV
275ps     814mV      883.5mV    790.7mV
330ps     800mV      832.3mV    785mV
625ps     792.8mV    806.1mV    782.3mV
